VERSION 5.8 ;
BUSBITCHARS "[]" ;
DIVIDERCHAR "/" ;
UNITS
    DATABASE MICRONS 1000 ;
END UNITS

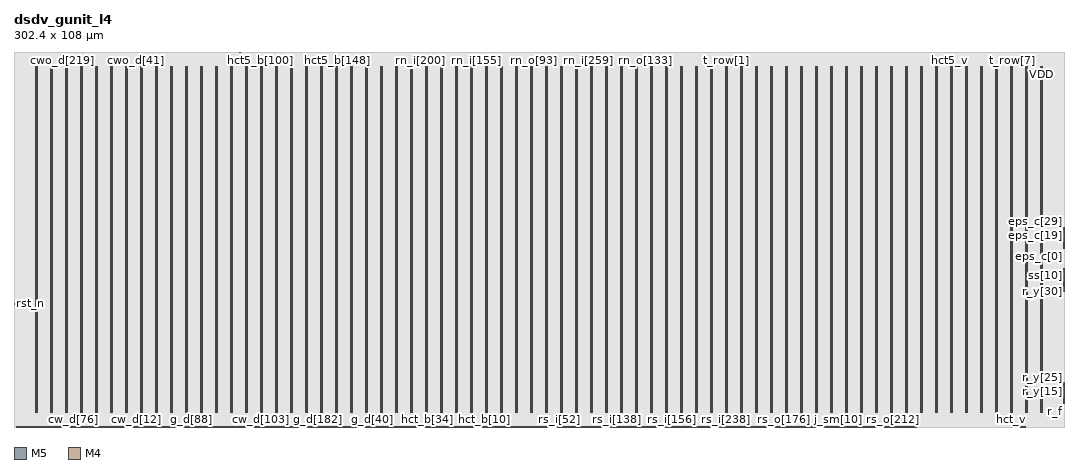
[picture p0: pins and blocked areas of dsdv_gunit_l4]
MACRO dsdv_gunit_l4
  FOREIGN dsdv_gunit_l4 0 0 ;
  CLASS BLOCK ;
  SIZE 302.4 BY 108 ;
  PIN clk
    DIRECTION INPUT ;
    USE SIGNAL ;
    PORT
      LAYER M5 ;
        RECT  155.028 0 155.076 0.48 ;
    END
  END clk
  PIN cw_a[0]
    DIRECTION INPUT ;
    USE SIGNAL ;
    PORT
      LAYER M5 ;
        RECT  31.296 0 31.32 0.084 ;
    END
  END cw_a[0]
  PIN cw_a[1]
    DIRECTION INPUT ;
    USE SIGNAL ;
    PORT
      LAYER M5 ;
        RECT  31.488 0 31.512 0.084 ;
    END
  END cw_a[1]
  PIN cw_a[2]
    DIRECTION INPUT ;
    USE SIGNAL ;
    PORT
      LAYER M5 ;
        RECT  31.68 0 31.704 0.084 ;
    END
  END cw_a[2]
  PIN cw_a[3]
    DIRECTION INPUT ;
    USE SIGNAL ;
    PORT
      LAYER M5 ;
        RECT  31.872 0 31.896 0.084 ;
    END
  END cw_a[3]
  PIN cw_a[4]
    DIRECTION INPUT ;
    USE SIGNAL ;
    PORT
      LAYER M5 ;
        RECT  32.064 0 32.088 0.084 ;
    END
  END cw_a[4]
  PIN cw_a[5]
    DIRECTION INPUT ;
    USE SIGNAL ;
    PORT
      LAYER M5 ;
        RECT  32.256 0 32.28 0.084 ;
    END
  END cw_a[5]
  PIN cw_a[6]
    DIRECTION INPUT ;
    USE SIGNAL ;
    PORT
      LAYER M5 ;
        RECT  32.448 0 32.472 0.084 ;
    END
  END cw_a[6]
  PIN cw_a[7]
    DIRECTION INPUT ;
    USE SIGNAL ;
    PORT
      LAYER M5 ;
        RECT  32.64 0 32.664 0.084 ;
    END
  END cw_a[7]
  PIN cw_d[0]
    DIRECTION INPUT ;
    USE SIGNAL ;
    PORT
      LAYER M5 ;
        RECT  32.832 0 32.856 0.084 ;
    END
  END cw_d[0]
  PIN cw_d[100]
    DIRECTION INPUT ;
    USE SIGNAL ;
    PORT
      LAYER M5 ;
        RECT  70.464 0 70.488 0.084 ;
    END
  END cw_d[100]
  PIN cw_d[101]
    DIRECTION INPUT ;
    USE SIGNAL ;
    PORT
      LAYER M5 ;
        RECT  70.656 0 70.68 0.084 ;
    END
  END cw_d[101]
  PIN cw_d[102]
    DIRECTION INPUT ;
    USE SIGNAL ;
    PORT
      LAYER M5 ;
        RECT  70.848 0 70.872 0.084 ;
    END
  END cw_d[102]
  PIN cw_d[103]
    DIRECTION INPUT ;
    USE SIGNAL ;
    PORT
      LAYER M5 ;
        RECT  71.04 0 71.064 0.084 ;
    END
  END cw_d[103]
  PIN cw_d[104]
    DIRECTION INPUT ;
    USE SIGNAL ;
    PORT
      LAYER M5 ;
        RECT  71.232 0 71.256 0.084 ;
    END
  END cw_d[104]
  PIN cw_d[105]
    DIRECTION INPUT ;
    USE SIGNAL ;
    PORT
      LAYER M5 ;
        RECT  71.424 0 71.448 0.084 ;
    END
  END cw_d[105]
  PIN cw_d[106]
    DIRECTION INPUT ;
    USE SIGNAL ;
    PORT
      LAYER M5 ;
        RECT  71.616 0 71.64 0.084 ;
    END
  END cw_d[106]
  PIN cw_d[107]
    DIRECTION INPUT ;
    USE SIGNAL ;
    PORT
      LAYER M5 ;
        RECT  71.808 0 71.832 0.084 ;
    END
  END cw_d[107]
  PIN cw_d[108]
    DIRECTION INPUT ;
    USE SIGNAL ;
    PORT
      LAYER M5 ;
        RECT  72 0 72.024 0.084 ;
    END
  END cw_d[108]
  PIN cw_d[109]
    DIRECTION INPUT ;
    USE SIGNAL ;
    PORT
      LAYER M5 ;
        RECT  72.192 0 72.216 0.084 ;
    END
  END cw_d[109]
  PIN cw_d[10]
    DIRECTION INPUT ;
    USE SIGNAL ;
    PORT
      LAYER M5 ;
        RECT  34.752 0 34.776 0.084 ;
    END
  END cw_d[10]
  PIN cw_d[110]
    DIRECTION INPUT ;
    USE SIGNAL ;
    PORT
      LAYER M5 ;
        RECT  72.384 0 72.408 0.084 ;
    END
  END cw_d[110]
  PIN cw_d[111]
    DIRECTION INPUT ;
    USE SIGNAL ;
    PORT
      LAYER M5 ;
        RECT  72.576 0 72.6 0.084 ;
    END
  END cw_d[111]
  PIN cw_d[112]
    DIRECTION INPUT ;
    USE SIGNAL ;
    PORT
      LAYER M5 ;
        RECT  72.768 0 72.792 0.084 ;
    END
  END cw_d[112]
  PIN cw_d[113]
    DIRECTION INPUT ;
    USE SIGNAL ;
    PORT
      LAYER M5 ;
        RECT  72.96 0 72.984 0.084 ;
    END
  END cw_d[113]
  PIN cw_d[114]
    DIRECTION INPUT ;
    USE SIGNAL ;
    PORT
      LAYER M5 ;
        RECT  73.152 0 73.176 0.084 ;
    END
  END cw_d[114]
  PIN cw_d[115]
    DIRECTION INPUT ;
    USE SIGNAL ;
    PORT
      LAYER M5 ;
        RECT  73.344 0 73.368 0.084 ;
    END
  END cw_d[115]
  PIN cw_d[116]
    DIRECTION INPUT ;
    USE SIGNAL ;
    PORT
      LAYER M5 ;
        RECT  73.536 0 73.56 0.084 ;
    END
  END cw_d[116]
  PIN cw_d[117]
    DIRECTION INPUT ;
    USE SIGNAL ;
    PORT
      LAYER M5 ;
        RECT  73.728 0 73.752 0.084 ;
    END
  END cw_d[117]
  PIN cw_d[118]
    DIRECTION INPUT ;
    USE SIGNAL ;
    PORT
      LAYER M5 ;
        RECT  6.72 0 6.744 0.084 ;
    END
  END cw_d[118]
  PIN cw_d[119]
    DIRECTION INPUT ;
    USE SIGNAL ;
    PORT
      LAYER M5 ;
        RECT  6.912 0 6.936 0.084 ;
    END
  END cw_d[119]
  PIN cw_d[11]
    DIRECTION INPUT ;
    USE SIGNAL ;
    PORT
      LAYER M5 ;
        RECT  34.944 0 34.968 0.084 ;
    END
  END cw_d[11]
  PIN cw_d[120]
    DIRECTION INPUT ;
    USE SIGNAL ;
    PORT
      LAYER M5 ;
        RECT  7.104 0 7.128 0.084 ;
    END
  END cw_d[120]
  PIN cw_d[121]
    DIRECTION INPUT ;
    USE SIGNAL ;
    PORT
      LAYER M5 ;
        RECT  7.296 0 7.32 0.084 ;
    END
  END cw_d[121]
  PIN cw_d[122]
    DIRECTION INPUT ;
    USE SIGNAL ;
    PORT
      LAYER M5 ;
        RECT  7.488 0 7.512 0.084 ;
    END
  END cw_d[122]
  PIN cw_d[123]
    DIRECTION INPUT ;
    USE SIGNAL ;
    PORT
      LAYER M5 ;
        RECT  7.68 0 7.704 0.084 ;
    END
  END cw_d[123]
  PIN cw_d[124]
    DIRECTION INPUT ;
    USE SIGNAL ;
    PORT
      LAYER M5 ;
        RECT  7.872 0 7.896 0.084 ;
    END
  END cw_d[124]
  PIN cw_d[125]
    DIRECTION INPUT ;
    USE SIGNAL ;
    PORT
      LAYER M5 ;
        RECT  8.064 0 8.088 0.084 ;
    END
  END cw_d[125]
  PIN cw_d[126]
    DIRECTION INPUT ;
    USE SIGNAL ;
    PORT
      LAYER M5 ;
        RECT  8.256 0 8.28 0.084 ;
    END
  END cw_d[126]
  PIN cw_d[127]
    DIRECTION INPUT ;
    USE SIGNAL ;
    PORT
      LAYER M5 ;
        RECT  8.448 0 8.472 0.084 ;
    END
  END cw_d[127]
  PIN cw_d[128]
    DIRECTION INPUT ;
    USE SIGNAL ;
    PORT
      LAYER M5 ;
        RECT  8.64 0 8.664 0.084 ;
    END
  END cw_d[128]
  PIN cw_d[129]
    DIRECTION INPUT ;
    USE SIGNAL ;
    PORT
      LAYER M5 ;
        RECT  8.832 0 8.856 0.084 ;
    END
  END cw_d[129]
  PIN cw_d[12]
    DIRECTION INPUT ;
    USE SIGNAL ;
    PORT
      LAYER M5 ;
        RECT  35.136 0 35.16 0.084 ;
    END
  END cw_d[12]
  PIN cw_d[130]
    DIRECTION INPUT ;
    USE SIGNAL ;
    PORT
      LAYER M5 ;
        RECT  9.024 0 9.048 0.084 ;
    END
  END cw_d[130]
  PIN cw_d[131]
    DIRECTION INPUT ;
    USE SIGNAL ;
    PORT
      LAYER M5 ;
        RECT  9.216 0 9.24 0.084 ;
    END
  END cw_d[131]
  PIN cw_d[132]
    DIRECTION INPUT ;
    USE SIGNAL ;
    PORT
      LAYER M5 ;
        RECT  9.408 0 9.432 0.084 ;
    END
  END cw_d[132]
  PIN cw_d[133]
    DIRECTION INPUT ;
    USE SIGNAL ;
    PORT
      LAYER M5 ;
        RECT  9.6 0 9.624 0.084 ;
    END
  END cw_d[133]
  PIN cw_d[134]
    DIRECTION INPUT ;
    USE SIGNAL ;
    PORT
      LAYER M5 ;
        RECT  9.792 0 9.816 0.084 ;
    END
  END cw_d[134]
  PIN cw_d[135]
    DIRECTION INPUT ;
    USE SIGNAL ;
    PORT
      LAYER M5 ;
        RECT  9.984 0 10.008 0.084 ;
    END
  END cw_d[135]
  PIN cw_d[136]
    DIRECTION INPUT ;
    USE SIGNAL ;
    PORT
      LAYER M5 ;
        RECT  10.176 0 10.2 0.084 ;
    END
  END cw_d[136]
  PIN cw_d[137]
    DIRECTION INPUT ;
    USE SIGNAL ;
    PORT
      LAYER M5 ;
        RECT  10.368 0 10.392 0.084 ;
    END
  END cw_d[137]
  PIN cw_d[138]
    DIRECTION INPUT ;
    USE SIGNAL ;
    PORT
      LAYER M5 ;
        RECT  10.56 0 10.584 0.084 ;
    END
  END cw_d[138]
  PIN cw_d[139]
    DIRECTION INPUT ;
    USE SIGNAL ;
    PORT
      LAYER M5 ;
        RECT  10.752 0 10.776 0.084 ;
    END
  END cw_d[139]
  PIN cw_d[13]
    DIRECTION INPUT ;
    USE SIGNAL ;
    PORT
      LAYER M5 ;
        RECT  35.328 0 35.352 0.084 ;
    END
  END cw_d[13]
  PIN cw_d[140]
    DIRECTION INPUT ;
    USE SIGNAL ;
    PORT
      LAYER M5 ;
        RECT  10.944 0 10.968 0.084 ;
    END
  END cw_d[140]
  PIN cw_d[141]
    DIRECTION INPUT ;
    USE SIGNAL ;
    PORT
      LAYER M5 ;
        RECT  11.136 0 11.16 0.084 ;
    END
  END cw_d[141]
  PIN cw_d[142]
    DIRECTION INPUT ;
    USE SIGNAL ;
    PORT
      LAYER M5 ;
        RECT  11.328 0 11.352 0.084 ;
    END
  END cw_d[142]
  PIN cw_d[143]
    DIRECTION INPUT ;
    USE SIGNAL ;
    PORT
      LAYER M5 ;
        RECT  11.52 0 11.544 0.084 ;
    END
  END cw_d[143]
  PIN cw_d[144]
    DIRECTION INPUT ;
    USE SIGNAL ;
    PORT
      LAYER M5 ;
        RECT  11.712 0 11.736 0.084 ;
    END
  END cw_d[144]
  PIN cw_d[145]
    DIRECTION INPUT ;
    USE SIGNAL ;
    PORT
      LAYER M5 ;
        RECT  11.904 0 11.928 0.084 ;
    END
  END cw_d[145]
  PIN cw_d[146]
    DIRECTION INPUT ;
    USE SIGNAL ;
    PORT
      LAYER M5 ;
        RECT  12.096 0 12.12 0.084 ;
    END
  END cw_d[146]
  PIN cw_d[147]
    DIRECTION INPUT ;
    USE SIGNAL ;
    PORT
      LAYER M5 ;
        RECT  12.288 0 12.312 0.084 ;
    END
  END cw_d[147]
  PIN cw_d[148]
    DIRECTION INPUT ;
    USE SIGNAL ;
    PORT
      LAYER M5 ;
        RECT  12.48 0 12.504 0.084 ;
    END
  END cw_d[148]
  PIN cw_d[149]
    DIRECTION INPUT ;
    USE SIGNAL ;
    PORT
      LAYER M5 ;
        RECT  12.672 0 12.696 0.084 ;
    END
  END cw_d[149]
  PIN cw_d[14]
    DIRECTION INPUT ;
    USE SIGNAL ;
    PORT
      LAYER M5 ;
        RECT  35.52 0 35.544 0.084 ;
    END
  END cw_d[14]
  PIN cw_d[150]
    DIRECTION INPUT ;
    USE SIGNAL ;
    PORT
      LAYER M5 ;
        RECT  0.576 0 0.6 0.084 ;
    END
  END cw_d[150]
  PIN cw_d[151]
    DIRECTION INPUT ;
    USE SIGNAL ;
    PORT
      LAYER M5 ;
        RECT  0.768 0 0.792 0.084 ;
    END
  END cw_d[151]
  PIN cw_d[152]
    DIRECTION INPUT ;
    USE SIGNAL ;
    PORT
      LAYER M5 ;
        RECT  0.96 0 0.984 0.084 ;
    END
  END cw_d[152]
  PIN cw_d[153]
    DIRECTION INPUT ;
    USE SIGNAL ;
    PORT
      LAYER M5 ;
        RECT  1.152 0 1.176 0.084 ;
    END
  END cw_d[153]
  PIN cw_d[154]
    DIRECTION INPUT ;
    USE SIGNAL ;
    PORT
      LAYER M5 ;
        RECT  1.344 0 1.368 0.084 ;
    END
  END cw_d[154]
  PIN cw_d[155]
    DIRECTION INPUT ;
    USE SIGNAL ;
    PORT
      LAYER M5 ;
        RECT  1.536 0 1.56 0.084 ;
    END
  END cw_d[155]
  PIN cw_d[156]
    DIRECTION INPUT ;
    USE SIGNAL ;
    PORT
      LAYER M5 ;
        RECT  1.728 0 1.752 0.084 ;
    END
  END cw_d[156]
  PIN cw_d[157]
    DIRECTION INPUT ;
    USE SIGNAL ;
    PORT
      LAYER M5 ;
        RECT  1.92 0 1.944 0.084 ;
    END
  END cw_d[157]
  PIN cw_d[158]
    DIRECTION INPUT ;
    USE SIGNAL ;
    PORT
      LAYER M5 ;
        RECT  2.112 0 2.136 0.084 ;
    END
  END cw_d[158]
  PIN cw_d[159]
    DIRECTION INPUT ;
    USE SIGNAL ;
    PORT
      LAYER M5 ;
        RECT  2.304 0 2.328 0.084 ;
    END
  END cw_d[159]
  PIN cw_d[15]
    DIRECTION INPUT ;
    USE SIGNAL ;
    PORT
      LAYER M5 ;
        RECT  35.712 0 35.736 0.084 ;
    END
  END cw_d[15]
  PIN cw_d[160]
    DIRECTION INPUT ;
    USE SIGNAL ;
    PORT
      LAYER M5 ;
        RECT  2.496 0 2.52 0.084 ;
    END
  END cw_d[160]
  PIN cw_d[161]
    DIRECTION INPUT ;
    USE SIGNAL ;
    PORT
      LAYER M5 ;
        RECT  2.688 0 2.712 0.084 ;
    END
  END cw_d[161]
  PIN cw_d[162]
    DIRECTION INPUT ;
    USE SIGNAL ;
    PORT
      LAYER M5 ;
        RECT  2.88 0 2.904 0.084 ;
    END
  END cw_d[162]
  PIN cw_d[163]
    DIRECTION INPUT ;
    USE SIGNAL ;
    PORT
      LAYER M5 ;
        RECT  3.072 0 3.096 0.084 ;
    END
  END cw_d[163]
  PIN cw_d[164]
    DIRECTION INPUT ;
    USE SIGNAL ;
    PORT
      LAYER M5 ;
        RECT  3.264 0 3.288 0.084 ;
    END
  END cw_d[164]
  PIN cw_d[165]
    DIRECTION INPUT ;
    USE SIGNAL ;
    PORT
      LAYER M5 ;
        RECT  3.456 0 3.48 0.084 ;
    END
  END cw_d[165]
  PIN cw_d[166]
    DIRECTION INPUT ;
    USE SIGNAL ;
    PORT
      LAYER M5 ;
        RECT  3.648 0 3.672 0.084 ;
    END
  END cw_d[166]
  PIN cw_d[167]
    DIRECTION INPUT ;
    USE SIGNAL ;
    PORT
      LAYER M5 ;
        RECT  3.84 0 3.864 0.084 ;
    END
  END cw_d[167]
  PIN cw_d[168]
    DIRECTION INPUT ;
    USE SIGNAL ;
    PORT
      LAYER M5 ;
        RECT  4.032 0 4.056 0.084 ;
    END
  END cw_d[168]
  PIN cw_d[169]
    DIRECTION INPUT ;
    USE SIGNAL ;
    PORT
      LAYER M5 ;
        RECT  4.224 0 4.248 0.084 ;
    END
  END cw_d[169]
  PIN cw_d[16]
    DIRECTION INPUT ;
    USE SIGNAL ;
    PORT
      LAYER M5 ;
        RECT  35.904 0 35.928 0.084 ;
    END
  END cw_d[16]
  PIN cw_d[170]
    DIRECTION INPUT ;
    USE SIGNAL ;
    PORT
      LAYER M5 ;
        RECT  4.416 0 4.44 0.084 ;
    END
  END cw_d[170]
  PIN cw_d[171]
    DIRECTION INPUT ;
    USE SIGNAL ;
    PORT
      LAYER M5 ;
        RECT  4.608 0 4.632 0.084 ;
    END
  END cw_d[171]
  PIN cw_d[172]
    DIRECTION INPUT ;
    USE SIGNAL ;
    PORT
      LAYER M5 ;
        RECT  4.8 0 4.824 0.084 ;
    END
  END cw_d[172]
  PIN cw_d[173]
    DIRECTION INPUT ;
    USE SIGNAL ;
    PORT
      LAYER M5 ;
        RECT  4.992 0 5.016 0.084 ;
    END
  END cw_d[173]
  PIN cw_d[174]
    DIRECTION INPUT ;
    USE SIGNAL ;
    PORT
      LAYER M5 ;
        RECT  5.184 0 5.208 0.084 ;
    END
  END cw_d[174]
  PIN cw_d[175]
    DIRECTION INPUT ;
    USE SIGNAL ;
    PORT
      LAYER M5 ;
        RECT  5.376 0 5.4 0.084 ;
    END
  END cw_d[175]
  PIN cw_d[176]
    DIRECTION INPUT ;
    USE SIGNAL ;
    PORT
      LAYER M5 ;
        RECT  5.568 0 5.592 0.084 ;
    END
  END cw_d[176]
  PIN cw_d[177]
    DIRECTION INPUT ;
    USE SIGNAL ;
    PORT
      LAYER M5 ;
        RECT  5.76 0 5.784 0.084 ;
    END
  END cw_d[177]
  PIN cw_d[178]
    DIRECTION INPUT ;
    USE SIGNAL ;
    PORT
      LAYER M5 ;
        RECT  5.952 0 5.976 0.084 ;
    END
  END cw_d[178]
  PIN cw_d[179]
    DIRECTION INPUT ;
    USE SIGNAL ;
    PORT
      LAYER M5 ;
        RECT  6.144 0 6.168 0.084 ;
    END
  END cw_d[179]
  PIN cw_d[17]
    DIRECTION INPUT ;
    USE SIGNAL ;
    PORT
      LAYER M5 ;
        RECT  36.096 0 36.12 0.084 ;
    END
  END cw_d[17]
  PIN cw_d[180]
    DIRECTION INPUT ;
    USE SIGNAL ;
    PORT
      LAYER M5 ;
        RECT  6.336 0 6.36 0.084 ;
    END
  END cw_d[180]
  PIN cw_d[181]
    DIRECTION INPUT ;
    USE SIGNAL ;
    PORT
      LAYER M5 ;
        RECT  6.528 0 6.552 0.084 ;
    END
  END cw_d[181]
  PIN cw_d[182]
    DIRECTION INPUT ;
    USE SIGNAL ;
    PORT
      LAYER M5 ;
        RECT  25.152 0 25.176 0.084 ;
    END
  END cw_d[182]
  PIN cw_d[183]
    DIRECTION INPUT ;
    USE SIGNAL ;
    PORT
      LAYER M5 ;
        RECT  25.344 0 25.368 0.084 ;
    END
  END cw_d[183]
  PIN cw_d[184]
    DIRECTION INPUT ;
    USE SIGNAL ;
    PORT
      LAYER M5 ;
        RECT  25.536 0 25.56 0.084 ;
    END
  END cw_d[184]
  PIN cw_d[185]
    DIRECTION INPUT ;
    USE SIGNAL ;
    PORT
      LAYER M5 ;
        RECT  25.728 0 25.752 0.084 ;
    END
  END cw_d[185]
  PIN cw_d[186]
    DIRECTION INPUT ;
    USE SIGNAL ;
    PORT
      LAYER M5 ;
        RECT  25.92 0 25.944 0.084 ;
    END
  END cw_d[186]
  PIN cw_d[187]
    DIRECTION INPUT ;
    USE SIGNAL ;
    PORT
      LAYER M5 ;
        RECT  26.112 0 26.136 0.084 ;
    END
  END cw_d[187]
  PIN cw_d[188]
    DIRECTION INPUT ;
    USE SIGNAL ;
    PORT
      LAYER M5 ;
        RECT  26.304 0 26.328 0.084 ;
    END
  END cw_d[188]
  PIN cw_d[189]
    DIRECTION INPUT ;
    USE SIGNAL ;
    PORT
      LAYER M5 ;
        RECT  26.496 0 26.52 0.084 ;
    END
  END cw_d[189]
  PIN cw_d[18]
    DIRECTION INPUT ;
    USE SIGNAL ;
    PORT
      LAYER M5 ;
        RECT  36.288 0 36.312 0.084 ;
    END
  END cw_d[18]
  PIN cw_d[190]
    DIRECTION INPUT ;
    USE SIGNAL ;
    PORT
      LAYER M5 ;
        RECT  26.688 0 26.712 0.084 ;
    END
  END cw_d[190]
  PIN cw_d[191]
    DIRECTION INPUT ;
    USE SIGNAL ;
    PORT
      LAYER M5 ;
        RECT  26.88 0 26.904 0.084 ;
    END
  END cw_d[191]
  PIN cw_d[192]
    DIRECTION INPUT ;
    USE SIGNAL ;
    PORT
      LAYER M5 ;
        RECT  27.072 0 27.096 0.084 ;
    END
  END cw_d[192]
  PIN cw_d[193]
    DIRECTION INPUT ;
    USE SIGNAL ;
    PORT
      LAYER M5 ;
        RECT  27.264 0 27.288 0.084 ;
    END
  END cw_d[193]
  PIN cw_d[194]
    DIRECTION INPUT ;
    USE SIGNAL ;
    PORT
      LAYER M5 ;
        RECT  27.456 0 27.48 0.084 ;
    END
  END cw_d[194]
  PIN cw_d[195]
    DIRECTION INPUT ;
    USE SIGNAL ;
    PORT
      LAYER M5 ;
        RECT  27.648 0 27.672 0.084 ;
    END
  END cw_d[195]
  PIN cw_d[196]
    DIRECTION INPUT ;
    USE SIGNAL ;
    PORT
      LAYER M5 ;
        RECT  27.84 0 27.864 0.084 ;
    END
  END cw_d[196]
  PIN cw_d[197]
    DIRECTION INPUT ;
    USE SIGNAL ;
    PORT
      LAYER M5 ;
        RECT  28.032 0 28.056 0.084 ;
    END
  END cw_d[197]
  PIN cw_d[198]
    DIRECTION INPUT ;
    USE SIGNAL ;
    PORT
      LAYER M5 ;
        RECT  28.224 0 28.248 0.084 ;
    END
  END cw_d[198]
  PIN cw_d[199]
    DIRECTION INPUT ;
    USE SIGNAL ;
    PORT
      LAYER M5 ;
        RECT  28.416 0 28.44 0.084 ;
    END
  END cw_d[199]
  PIN cw_d[19]
    DIRECTION INPUT ;
    USE SIGNAL ;
    PORT
      LAYER M5 ;
        RECT  36.48 0 36.504 0.084 ;
    END
  END cw_d[19]
  PIN cw_d[1]
    DIRECTION INPUT ;
    USE SIGNAL ;
    PORT
      LAYER M5 ;
        RECT  33.024 0 33.048 0.084 ;
    END
  END cw_d[1]
  PIN cw_d[200]
    DIRECTION INPUT ;
    USE SIGNAL ;
    PORT
      LAYER M5 ;
        RECT  28.608 0 28.632 0.084 ;
    END
  END cw_d[200]
  PIN cw_d[201]
    DIRECTION INPUT ;
    USE SIGNAL ;
    PORT
      LAYER M5 ;
        RECT  28.8 0 28.824 0.084 ;
    END
  END cw_d[201]
  PIN cw_d[202]
    DIRECTION INPUT ;
    USE SIGNAL ;
    PORT
      LAYER M5 ;
        RECT  28.992 0 29.016 0.084 ;
    END
  END cw_d[202]
  PIN cw_d[203]
    DIRECTION INPUT ;
    USE SIGNAL ;
    PORT
      LAYER M5 ;
        RECT  29.184 0 29.208 0.084 ;
    END
  END cw_d[203]
  PIN cw_d[204]
    DIRECTION INPUT ;
    USE SIGNAL ;
    PORT
      LAYER M5 ;
        RECT  29.376 0 29.4 0.084 ;
    END
  END cw_d[204]
  PIN cw_d[205]
    DIRECTION INPUT ;
    USE SIGNAL ;
    PORT
      LAYER M5 ;
        RECT  29.568 0 29.592 0.084 ;
    END
  END cw_d[205]
  PIN cw_d[206]
    DIRECTION INPUT ;
    USE SIGNAL ;
    PORT
      LAYER M5 ;
        RECT  29.76 0 29.784 0.084 ;
    END
  END cw_d[206]
  PIN cw_d[207]
    DIRECTION INPUT ;
    USE SIGNAL ;
    PORT
      LAYER M5 ;
        RECT  29.952 0 29.976 0.084 ;
    END
  END cw_d[207]
  PIN cw_d[208]
    DIRECTION INPUT ;
    USE SIGNAL ;
    PORT
      LAYER M5 ;
        RECT  30.144 0 30.168 0.084 ;
    END
  END cw_d[208]
  PIN cw_d[209]
    DIRECTION INPUT ;
    USE SIGNAL ;
    PORT
      LAYER M5 ;
        RECT  30.336 0 30.36 0.084 ;
    END
  END cw_d[209]
  PIN cw_d[20]
    DIRECTION INPUT ;
    USE SIGNAL ;
    PORT
      LAYER M5 ;
        RECT  36.672 0 36.696 0.084 ;
    END
  END cw_d[20]
  PIN cw_d[210]
    DIRECTION INPUT ;
    USE SIGNAL ;
    PORT
      LAYER M5 ;
        RECT  30.528 0 30.552 0.084 ;
    END
  END cw_d[210]
  PIN cw_d[211]
    DIRECTION INPUT ;
    USE SIGNAL ;
    PORT
      LAYER M5 ;
        RECT  30.72 0 30.744 0.084 ;
    END
  END cw_d[211]
  PIN cw_d[212]
    DIRECTION INPUT ;
    USE SIGNAL ;
    PORT
      LAYER M5 ;
        RECT  30.912 0 30.936 0.084 ;
    END
  END cw_d[212]
  PIN cw_d[213]
    DIRECTION INPUT ;
    USE SIGNAL ;
    PORT
      LAYER M5 ;
        RECT  31.104 0 31.128 0.084 ;
    END
  END cw_d[213]
  PIN cw_d[214]
    DIRECTION INPUT ;
    USE SIGNAL ;
    PORT
      LAYER M5 ;
        RECT  43.2 0 43.224 0.084 ;
    END
  END cw_d[214]
  PIN cw_d[215]
    DIRECTION INPUT ;
    USE SIGNAL ;
    PORT
      LAYER M5 ;
        RECT  43.392 0 43.416 0.084 ;
    END
  END cw_d[215]
  PIN cw_d[216]
    DIRECTION INPUT ;
    USE SIGNAL ;
    PORT
      LAYER M5 ;
        RECT  43.584 0 43.608 0.084 ;
    END
  END cw_d[216]
  PIN cw_d[217]
    DIRECTION INPUT ;
    USE SIGNAL ;
    PORT
      LAYER M5 ;
        RECT  43.776 0 43.8 0.084 ;
    END
  END cw_d[217]
  PIN cw_d[218]
    DIRECTION INPUT ;
    USE SIGNAL ;
    PORT
      LAYER M5 ;
        RECT  43.968 0 43.992 0.084 ;
    END
  END cw_d[218]
  PIN cw_d[219]
    DIRECTION INPUT ;
    USE SIGNAL ;
    PORT
      LAYER M5 ;
        RECT  44.16 0 44.184 0.084 ;
    END
  END cw_d[219]
  PIN cw_d[21]
    DIRECTION INPUT ;
    USE SIGNAL ;
    PORT
      LAYER M5 ;
        RECT  36.864 0 36.888 0.084 ;
    END
  END cw_d[21]
  PIN cw_d[220]
    DIRECTION INPUT ;
    USE SIGNAL ;
    PORT
      LAYER M5 ;
        RECT  44.352 0 44.376 0.084 ;
    END
  END cw_d[220]
  PIN cw_d[221]
    DIRECTION INPUT ;
    USE SIGNAL ;
    PORT
      LAYER M5 ;
        RECT  44.544 0 44.568 0.084 ;
    END
  END cw_d[221]
  PIN cw_d[222]
    DIRECTION INPUT ;
    USE SIGNAL ;
    PORT
      LAYER M5 ;
        RECT  44.736 0 44.76 0.084 ;
    END
  END cw_d[222]
  PIN cw_d[223]
    DIRECTION INPUT ;
    USE SIGNAL ;
    PORT
      LAYER M5 ;
        RECT  44.928 0 44.952 0.084 ;
    END
  END cw_d[223]
  PIN cw_d[224]
    DIRECTION INPUT ;
    USE SIGNAL ;
    PORT
      LAYER M5 ;
        RECT  45.12 0 45.144 0.084 ;
    END
  END cw_d[224]
  PIN cw_d[225]
    DIRECTION INPUT ;
    USE SIGNAL ;
    PORT
      LAYER M5 ;
        RECT  45.312 0 45.336 0.084 ;
    END
  END cw_d[225]
  PIN cw_d[226]
    DIRECTION INPUT ;
    USE SIGNAL ;
    PORT
      LAYER M5 ;
        RECT  45.504 0 45.528 0.084 ;
    END
  END cw_d[226]
  PIN cw_d[227]
    DIRECTION INPUT ;
    USE SIGNAL ;
    PORT
      LAYER M5 ;
        RECT  45.696 0 45.72 0.084 ;
    END
  END cw_d[227]
  PIN cw_d[228]
    DIRECTION INPUT ;
    USE SIGNAL ;
    PORT
      LAYER M5 ;
        RECT  45.888 0 45.912 0.084 ;
    END
  END cw_d[228]
  PIN cw_d[229]
    DIRECTION INPUT ;
    USE SIGNAL ;
    PORT
      LAYER M5 ;
        RECT  46.08 0 46.104 0.084 ;
    END
  END cw_d[229]
  PIN cw_d[22]
    DIRECTION INPUT ;
    USE SIGNAL ;
    PORT
      LAYER M5 ;
        RECT  19.008 0 19.032 0.084 ;
    END
  END cw_d[22]
  PIN cw_d[230]
    DIRECTION INPUT ;
    USE SIGNAL ;
    PORT
      LAYER M5 ;
        RECT  46.272 0 46.296 0.084 ;
    END
  END cw_d[230]
  PIN cw_d[231]
    DIRECTION INPUT ;
    USE SIGNAL ;
    PORT
      LAYER M5 ;
        RECT  46.464 0 46.488 0.084 ;
    END
  END cw_d[231]
  PIN cw_d[232]
    DIRECTION INPUT ;
    USE SIGNAL ;
    PORT
      LAYER M5 ;
        RECT  46.656 0 46.68 0.084 ;
    END
  END cw_d[232]
  PIN cw_d[233]
    DIRECTION INPUT ;
    USE SIGNAL ;
    PORT
      LAYER M5 ;
        RECT  46.848 0 46.872 0.084 ;
    END
  END cw_d[233]
  PIN cw_d[234]
    DIRECTION INPUT ;
    USE SIGNAL ;
    PORT
      LAYER M5 ;
        RECT  47.04 0 47.064 0.084 ;
    END
  END cw_d[234]
  PIN cw_d[235]
    DIRECTION INPUT ;
    USE SIGNAL ;
    PORT
      LAYER M5 ;
        RECT  47.232 0 47.256 0.084 ;
    END
  END cw_d[235]
  PIN cw_d[236]
    DIRECTION INPUT ;
    USE SIGNAL ;
    PORT
      LAYER M5 ;
        RECT  47.424 0 47.448 0.084 ;
    END
  END cw_d[236]
  PIN cw_d[237]
    DIRECTION INPUT ;
    USE SIGNAL ;
    PORT
      LAYER M5 ;
        RECT  47.616 0 47.64 0.084 ;
    END
  END cw_d[237]
  PIN cw_d[238]
    DIRECTION INPUT ;
    USE SIGNAL ;
    PORT
      LAYER M5 ;
        RECT  47.808 0 47.832 0.084 ;
    END
  END cw_d[238]
  PIN cw_d[239]
    DIRECTION INPUT ;
    USE SIGNAL ;
    PORT
      LAYER M5 ;
        RECT  48 0 48.024 0.084 ;
    END
  END cw_d[239]
  PIN cw_d[23]
    DIRECTION INPUT ;
    USE SIGNAL ;
    PORT
      LAYER M5 ;
        RECT  19.2 0 19.224 0.084 ;
    END
  END cw_d[23]
  PIN cw_d[240]
    DIRECTION INPUT ;
    USE SIGNAL ;
    PORT
      LAYER M5 ;
        RECT  48.192 0 48.216 0.084 ;
    END
  END cw_d[240]
  PIN cw_d[241]
    DIRECTION INPUT ;
    USE SIGNAL ;
    PORT
      LAYER M5 ;
        RECT  48.384 0 48.408 0.084 ;
    END
  END cw_d[241]
  PIN cw_d[242]
    DIRECTION INPUT ;
    USE SIGNAL ;
    PORT
      LAYER M5 ;
        RECT  48.576 0 48.6 0.084 ;
    END
  END cw_d[242]
  PIN cw_d[243]
    DIRECTION INPUT ;
    USE SIGNAL ;
    PORT
      LAYER M5 ;
        RECT  48.768 0 48.792 0.084 ;
    END
  END cw_d[243]
  PIN cw_d[244]
    DIRECTION INPUT ;
    USE SIGNAL ;
    PORT
      LAYER M5 ;
        RECT  48.96 0 48.984 0.084 ;
    END
  END cw_d[244]
  PIN cw_d[245]
    DIRECTION INPUT ;
    USE SIGNAL ;
    PORT
      LAYER M5 ;
        RECT  49.152 0 49.176 0.084 ;
    END
  END cw_d[245]
  PIN cw_d[246]
    DIRECTION INPUT ;
    USE SIGNAL ;
    PORT
      LAYER M5 ;
        RECT  104.64 0 104.664 0.084 ;
    END
  END cw_d[246]
  PIN cw_d[247]
    DIRECTION INPUT ;
    USE SIGNAL ;
    PORT
      LAYER M5 ;
        RECT  104.832 0 104.856 0.084 ;
    END
  END cw_d[247]
  PIN cw_d[248]
    DIRECTION INPUT ;
    USE SIGNAL ;
    PORT
      LAYER M5 ;
        RECT  105.024 0 105.048 0.084 ;
    END
  END cw_d[248]
  PIN cw_d[249]
    DIRECTION INPUT ;
    USE SIGNAL ;
    PORT
      LAYER M5 ;
        RECT  105.216 0 105.24 0.084 ;
    END
  END cw_d[249]
  PIN cw_d[24]
    DIRECTION INPUT ;
    USE SIGNAL ;
    PORT
      LAYER M5 ;
        RECT  19.392 0 19.416 0.084 ;
    END
  END cw_d[24]
  PIN cw_d[250]
    DIRECTION INPUT ;
    USE SIGNAL ;
    PORT
      LAYER M5 ;
        RECT  105.408 0 105.432 0.084 ;
    END
  END cw_d[250]
  PIN cw_d[251]
    DIRECTION INPUT ;
    USE SIGNAL ;
    PORT
      LAYER M5 ;
        RECT  105.6 0 105.624 0.084 ;
    END
  END cw_d[251]
  PIN cw_d[252]
    DIRECTION INPUT ;
    USE SIGNAL ;
    PORT
      LAYER M5 ;
        RECT  105.792 0 105.816 0.084 ;
    END
  END cw_d[252]
  PIN cw_d[253]
    DIRECTION INPUT ;
    USE SIGNAL ;
    PORT
      LAYER M5 ;
        RECT  105.984 0 106.008 0.084 ;
    END
  END cw_d[253]
  PIN cw_d[254]
    DIRECTION INPUT ;
    USE SIGNAL ;
    PORT
      LAYER M5 ;
        RECT  106.176 0 106.2 0.084 ;
    END
  END cw_d[254]
  PIN cw_d[255]
    DIRECTION INPUT ;
    USE SIGNAL ;
    PORT
      LAYER M5 ;
        RECT  106.368 0 106.392 0.084 ;
    END
  END cw_d[255]
  PIN cw_d[25]
    DIRECTION INPUT ;
    USE SIGNAL ;
    PORT
      LAYER M5 ;
        RECT  19.584 0 19.608 0.084 ;
    END
  END cw_d[25]
  PIN cw_d[26]
    DIRECTION INPUT ;
    USE SIGNAL ;
    PORT
      LAYER M5 ;
        RECT  19.776 0 19.8 0.084 ;
    END
  END cw_d[26]
  PIN cw_d[27]
    DIRECTION INPUT ;
    USE SIGNAL ;
    PORT
      LAYER M5 ;
        RECT  19.968 0 19.992 0.084 ;
    END
  END cw_d[27]
  PIN cw_d[28]
    DIRECTION INPUT ;
    USE SIGNAL ;
    PORT
      LAYER M5 ;
        RECT  20.16 0 20.184 0.084 ;
    END
  END cw_d[28]
  PIN cw_d[29]
    DIRECTION INPUT ;
    USE SIGNAL ;
    PORT
      LAYER M5 ;
        RECT  20.352 0 20.376 0.084 ;
    END
  END cw_d[29]
  PIN cw_d[2]
    DIRECTION INPUT ;
    USE SIGNAL ;
    PORT
      LAYER M5 ;
        RECT  33.216 0 33.24 0.084 ;
    END
  END cw_d[2]
  PIN cw_d[30]
    DIRECTION INPUT ;
    USE SIGNAL ;
    PORT
      LAYER M5 ;
        RECT  20.544 0 20.568 0.084 ;
    END
  END cw_d[30]
  PIN cw_d[31]
    DIRECTION INPUT ;
    USE SIGNAL ;
    PORT
      LAYER M5 ;
        RECT  20.736 0 20.76 0.084 ;
    END
  END cw_d[31]
  PIN cw_d[32]
    DIRECTION INPUT ;
    USE SIGNAL ;
    PORT
      LAYER M5 ;
        RECT  20.928 0 20.952 0.084 ;
    END
  END cw_d[32]
  PIN cw_d[33]
    DIRECTION INPUT ;
    USE SIGNAL ;
    PORT
      LAYER M5 ;
        RECT  21.12 0 21.144 0.084 ;
    END
  END cw_d[33]
  PIN cw_d[34]
    DIRECTION INPUT ;
    USE SIGNAL ;
    PORT
      LAYER M5 ;
        RECT  21.312 0 21.336 0.084 ;
    END
  END cw_d[34]
  PIN cw_d[35]
    DIRECTION INPUT ;
    USE SIGNAL ;
    PORT
      LAYER M5 ;
        RECT  21.504 0 21.528 0.084 ;
    END
  END cw_d[35]
  PIN cw_d[36]
    DIRECTION INPUT ;
    USE SIGNAL ;
    PORT
      LAYER M5 ;
        RECT  21.696 0 21.72 0.084 ;
    END
  END cw_d[36]
  PIN cw_d[37]
    DIRECTION INPUT ;
    USE SIGNAL ;
    PORT
      LAYER M5 ;
        RECT  21.888 0 21.912 0.084 ;
    END
  END cw_d[37]
  PIN cw_d[38]
    DIRECTION INPUT ;
    USE SIGNAL ;
    PORT
      LAYER M5 ;
        RECT  22.08 0 22.104 0.084 ;
    END
  END cw_d[38]
  PIN cw_d[39]
    DIRECTION INPUT ;
    USE SIGNAL ;
    PORT
      LAYER M5 ;
        RECT  22.272 0 22.296 0.084 ;
    END
  END cw_d[39]
  PIN cw_d[3]
    DIRECTION INPUT ;
    USE SIGNAL ;
    PORT
      LAYER M5 ;
        RECT  33.408 0 33.432 0.084 ;
    END
  END cw_d[3]
  PIN cw_d[40]
    DIRECTION INPUT ;
    USE SIGNAL ;
    PORT
      LAYER M5 ;
        RECT  22.464 0 22.488 0.084 ;
    END
  END cw_d[40]
  PIN cw_d[41]
    DIRECTION INPUT ;
    USE SIGNAL ;
    PORT
      LAYER M5 ;
        RECT  22.656 0 22.68 0.084 ;
    END
  END cw_d[41]
  PIN cw_d[42]
    DIRECTION INPUT ;
    USE SIGNAL ;
    PORT
      LAYER M5 ;
        RECT  22.848 0 22.872 0.084 ;
    END
  END cw_d[42]
  PIN cw_d[43]
    DIRECTION INPUT ;
    USE SIGNAL ;
    PORT
      LAYER M5 ;
        RECT  23.04 0 23.064 0.084 ;
    END
  END cw_d[43]
  PIN cw_d[44]
    DIRECTION INPUT ;
    USE SIGNAL ;
    PORT
      LAYER M5 ;
        RECT  23.232 0 23.256 0.084 ;
    END
  END cw_d[44]
  PIN cw_d[45]
    DIRECTION INPUT ;
    USE SIGNAL ;
    PORT
      LAYER M5 ;
        RECT  23.424 0 23.448 0.084 ;
    END
  END cw_d[45]
  PIN cw_d[46]
    DIRECTION INPUT ;
    USE SIGNAL ;
    PORT
      LAYER M5 ;
        RECT  23.616 0 23.64 0.084 ;
    END
  END cw_d[46]
  PIN cw_d[47]
    DIRECTION INPUT ;
    USE SIGNAL ;
    PORT
      LAYER M5 ;
        RECT  23.808 0 23.832 0.084 ;
    END
  END cw_d[47]
  PIN cw_d[48]
    DIRECTION INPUT ;
    USE SIGNAL ;
    PORT
      LAYER M5 ;
        RECT  24 0 24.024 0.084 ;
    END
  END cw_d[48]
  PIN cw_d[49]
    DIRECTION INPUT ;
    USE SIGNAL ;
    PORT
      LAYER M5 ;
        RECT  24.192 0 24.216 0.084 ;
    END
  END cw_d[49]
  PIN cw_d[4]
    DIRECTION INPUT ;
    USE SIGNAL ;
    PORT
      LAYER M5 ;
        RECT  33.6 0 33.624 0.084 ;
    END
  END cw_d[4]
  PIN cw_d[50]
    DIRECTION INPUT ;
    USE SIGNAL ;
    PORT
      LAYER M5 ;
        RECT  24.384 0 24.408 0.084 ;
    END
  END cw_d[50]
  PIN cw_d[51]
    DIRECTION INPUT ;
    USE SIGNAL ;
    PORT
      LAYER M5 ;
        RECT  24.576 0 24.6 0.084 ;
    END
  END cw_d[51]
  PIN cw_d[52]
    DIRECTION INPUT ;
    USE SIGNAL ;
    PORT
      LAYER M5 ;
        RECT  24.768 0 24.792 0.084 ;
    END
  END cw_d[52]
  PIN cw_d[53]
    DIRECTION INPUT ;
    USE SIGNAL ;
    PORT
      LAYER M5 ;
        RECT  24.96 0 24.984 0.084 ;
    END
  END cw_d[53]
  PIN cw_d[54]
    DIRECTION INPUT ;
    USE SIGNAL ;
    PORT
      LAYER M5 ;
        RECT  12.864 0 12.888 0.084 ;
    END
  END cw_d[54]
  PIN cw_d[55]
    DIRECTION INPUT ;
    USE SIGNAL ;
    PORT
      LAYER M5 ;
        RECT  13.056 0 13.08 0.084 ;
    END
  END cw_d[55]
  PIN cw_d[56]
    DIRECTION INPUT ;
    USE SIGNAL ;
    PORT
      LAYER M5 ;
        RECT  13.248 0 13.272 0.084 ;
    END
  END cw_d[56]
  PIN cw_d[57]
    DIRECTION INPUT ;
    USE SIGNAL ;
    PORT
      LAYER M5 ;
        RECT  13.44 0 13.464 0.084 ;
    END
  END cw_d[57]
  PIN cw_d[58]
    DIRECTION INPUT ;
    USE SIGNAL ;
    PORT
      LAYER M5 ;
        RECT  13.632 0 13.656 0.084 ;
    END
  END cw_d[58]
  PIN cw_d[59]
    DIRECTION INPUT ;
    USE SIGNAL ;
    PORT
      LAYER M5 ;
        RECT  13.824 0 13.848 0.084 ;
    END
  END cw_d[59]
  PIN cw_d[5]
    DIRECTION INPUT ;
    USE SIGNAL ;
    PORT
      LAYER M5 ;
        RECT  33.792 0 33.816 0.084 ;
    END
  END cw_d[5]
  PIN cw_d[60]
    DIRECTION INPUT ;
    USE SIGNAL ;
    PORT
      LAYER M5 ;
        RECT  14.016 0 14.04 0.084 ;
    END
  END cw_d[60]
  PIN cw_d[61]
    DIRECTION INPUT ;
    USE SIGNAL ;
    PORT
      LAYER M5 ;
        RECT  14.208 0 14.232 0.084 ;
    END
  END cw_d[61]
  PIN cw_d[62]
    DIRECTION INPUT ;
    USE SIGNAL ;
    PORT
      LAYER M5 ;
        RECT  14.4 0 14.424 0.084 ;
    END
  END cw_d[62]
  PIN cw_d[63]
    DIRECTION INPUT ;
    USE SIGNAL ;
    PORT
      LAYER M5 ;
        RECT  14.592 0 14.616 0.084 ;
    END
  END cw_d[63]
  PIN cw_d[64]
    DIRECTION INPUT ;
    USE SIGNAL ;
    PORT
      LAYER M5 ;
        RECT  14.784 0 14.808 0.084 ;
    END
  END cw_d[64]
  PIN cw_d[65]
    DIRECTION INPUT ;
    USE SIGNAL ;
    PORT
      LAYER M5 ;
        RECT  14.976 0 15 0.084 ;
    END
  END cw_d[65]
  PIN cw_d[66]
    DIRECTION INPUT ;
    USE SIGNAL ;
    PORT
      LAYER M5 ;
        RECT  15.168 0 15.192 0.084 ;
    END
  END cw_d[66]
  PIN cw_d[67]
    DIRECTION INPUT ;
    USE SIGNAL ;
    PORT
      LAYER M5 ;
        RECT  15.36 0 15.384 0.084 ;
    END
  END cw_d[67]
  PIN cw_d[68]
    DIRECTION INPUT ;
    USE SIGNAL ;
    PORT
      LAYER M5 ;
        RECT  15.552 0 15.576 0.084 ;
    END
  END cw_d[68]
  PIN cw_d[69]
    DIRECTION INPUT ;
    USE SIGNAL ;
    PORT
      LAYER M5 ;
        RECT  15.744 0 15.768 0.084 ;
    END
  END cw_d[69]
  PIN cw_d[6]
    DIRECTION INPUT ;
    USE SIGNAL ;
    PORT
      LAYER M5 ;
        RECT  33.984 0 34.008 0.084 ;
    END
  END cw_d[6]
  PIN cw_d[70]
    DIRECTION INPUT ;
    USE SIGNAL ;
    PORT
      LAYER M5 ;
        RECT  15.936 0 15.96 0.084 ;
    END
  END cw_d[70]
  PIN cw_d[71]
    DIRECTION INPUT ;
    USE SIGNAL ;
    PORT
      LAYER M5 ;
        RECT  16.128 0 16.152 0.084 ;
    END
  END cw_d[71]
  PIN cw_d[72]
    DIRECTION INPUT ;
    USE SIGNAL ;
    PORT
      LAYER M5 ;
        RECT  16.32 0 16.344 0.084 ;
    END
  END cw_d[72]
  PIN cw_d[73]
    DIRECTION INPUT ;
    USE SIGNAL ;
    PORT
      LAYER M5 ;
        RECT  16.512 0 16.536 0.084 ;
    END
  END cw_d[73]
  PIN cw_d[74]
    DIRECTION INPUT ;
    USE SIGNAL ;
    PORT
      LAYER M5 ;
        RECT  16.704 0 16.728 0.084 ;
    END
  END cw_d[74]
  PIN cw_d[75]
    DIRECTION INPUT ;
    USE SIGNAL ;
    PORT
      LAYER M5 ;
        RECT  16.896 0 16.92 0.084 ;
    END
  END cw_d[75]
  PIN cw_d[76]
    DIRECTION INPUT ;
    USE SIGNAL ;
    PORT
      LAYER M5 ;
        RECT  17.088 0 17.112 0.084 ;
    END
  END cw_d[76]
  PIN cw_d[77]
    DIRECTION INPUT ;
    USE SIGNAL ;
    PORT
      LAYER M5 ;
        RECT  17.28 0 17.304 0.084 ;
    END
  END cw_d[77]
  PIN cw_d[78]
    DIRECTION INPUT ;
    USE SIGNAL ;
    PORT
      LAYER M5 ;
        RECT  17.472 0 17.496 0.084 ;
    END
  END cw_d[78]
  PIN cw_d[79]
    DIRECTION INPUT ;
    USE SIGNAL ;
    PORT
      LAYER M5 ;
        RECT  17.664 0 17.688 0.084 ;
    END
  END cw_d[79]
  PIN cw_d[7]
    DIRECTION INPUT ;
    USE SIGNAL ;
    PORT
      LAYER M5 ;
        RECT  34.176 0 34.2 0.084 ;
    END
  END cw_d[7]
  PIN cw_d[80]
    DIRECTION INPUT ;
    USE SIGNAL ;
    PORT
      LAYER M5 ;
        RECT  17.856 0 17.88 0.084 ;
    END
  END cw_d[80]
  PIN cw_d[81]
    DIRECTION INPUT ;
    USE SIGNAL ;
    PORT
      LAYER M5 ;
        RECT  18.048 0 18.072 0.084 ;
    END
  END cw_d[81]
  PIN cw_d[82]
    DIRECTION INPUT ;
    USE SIGNAL ;
    PORT
      LAYER M5 ;
        RECT  18.24 0 18.264 0.084 ;
    END
  END cw_d[82]
  PIN cw_d[83]
    DIRECTION INPUT ;
    USE SIGNAL ;
    PORT
      LAYER M5 ;
        RECT  18.432 0 18.456 0.084 ;
    END
  END cw_d[83]
  PIN cw_d[84]
    DIRECTION INPUT ;
    USE SIGNAL ;
    PORT
      LAYER M5 ;
        RECT  18.624 0 18.648 0.084 ;
    END
  END cw_d[84]
  PIN cw_d[85]
    DIRECTION INPUT ;
    USE SIGNAL ;
    PORT
      LAYER M5 ;
        RECT  18.816 0 18.84 0.084 ;
    END
  END cw_d[85]
  PIN cw_d[86]
    DIRECTION INPUT ;
    USE SIGNAL ;
    PORT
      LAYER M5 ;
        RECT  67.776 0 67.8 0.084 ;
    END
  END cw_d[86]
  PIN cw_d[87]
    DIRECTION INPUT ;
    USE SIGNAL ;
    PORT
      LAYER M5 ;
        RECT  67.968 0 67.992 0.084 ;
    END
  END cw_d[87]
  PIN cw_d[88]
    DIRECTION INPUT ;
    USE SIGNAL ;
    PORT
      LAYER M5 ;
        RECT  68.16 0 68.184 0.084 ;
    END
  END cw_d[88]
  PIN cw_d[89]
    DIRECTION INPUT ;
    USE SIGNAL ;
    PORT
      LAYER M5 ;
        RECT  68.352 0 68.376 0.084 ;
    END
  END cw_d[89]
  PIN cw_d[8]
    DIRECTION INPUT ;
    USE SIGNAL ;
    PORT
      LAYER M5 ;
        RECT  34.368 0 34.392 0.084 ;
    END
  END cw_d[8]
  PIN cw_d[90]
    DIRECTION INPUT ;
    USE SIGNAL ;
    PORT
      LAYER M5 ;
        RECT  68.544 0 68.568 0.084 ;
    END
  END cw_d[90]
  PIN cw_d[91]
    DIRECTION INPUT ;
    USE SIGNAL ;
    PORT
      LAYER M5 ;
        RECT  68.736 0 68.76 0.084 ;
    END
  END cw_d[91]
  PIN cw_d[92]
    DIRECTION INPUT ;
    USE SIGNAL ;
    PORT
      LAYER M5 ;
        RECT  68.928 0 68.952 0.084 ;
    END
  END cw_d[92]
  PIN cw_d[93]
    DIRECTION INPUT ;
    USE SIGNAL ;
    PORT
      LAYER M5 ;
        RECT  69.12 0 69.144 0.084 ;
    END
  END cw_d[93]
  PIN cw_d[94]
    DIRECTION INPUT ;
    USE SIGNAL ;
    PORT
      LAYER M5 ;
        RECT  69.312 0 69.336 0.084 ;
    END
  END cw_d[94]
  PIN cw_d[95]
    DIRECTION INPUT ;
    USE SIGNAL ;
    PORT
      LAYER M5 ;
        RECT  69.504 0 69.528 0.084 ;
    END
  END cw_d[95]
  PIN cw_d[96]
    DIRECTION INPUT ;
    USE SIGNAL ;
    PORT
      LAYER M5 ;
        RECT  69.696 0 69.72 0.084 ;
    END
  END cw_d[96]
  PIN cw_d[97]
    DIRECTION INPUT ;
    USE SIGNAL ;
    PORT
      LAYER M5 ;
        RECT  69.888 0 69.912 0.084 ;
    END
  END cw_d[97]
  PIN cw_d[98]
    DIRECTION INPUT ;
    USE SIGNAL ;
    PORT
      LAYER M5 ;
        RECT  70.08 0 70.104 0.084 ;
    END
  END cw_d[98]
  PIN cw_d[99]
    DIRECTION INPUT ;
    USE SIGNAL ;
    PORT
      LAYER M5 ;
        RECT  70.272 0 70.296 0.084 ;
    END
  END cw_d[99]
  PIN cw_d[9]
    DIRECTION INPUT ;
    USE SIGNAL ;
    PORT
      LAYER M5 ;
        RECT  34.56 0 34.584 0.084 ;
    END
  END cw_d[9]
  PIN cw_v
    DIRECTION INPUT ;
    USE SIGNAL ;
    PORT
      LAYER M5 ;
        RECT  106.56 0 106.584 0.084 ;
    END
  END cw_v
  PIN cwo_a[0]
    DIRECTION OUTPUT ;
    USE SIGNAL ;
    PORT
      LAYER M5 ;
        RECT  58.56 107.916 58.584 108 ;
    END
  END cwo_a[0]
  PIN cwo_a[1]
    DIRECTION OUTPUT ;
    USE SIGNAL ;
    PORT
      LAYER M5 ;
        RECT  58.752 107.916 58.776 108 ;
    END
  END cwo_a[1]
  PIN cwo_a[2]
    DIRECTION OUTPUT ;
    USE SIGNAL ;
    PORT
      LAYER M5 ;
        RECT  58.944 107.916 58.968 108 ;
    END
  END cwo_a[2]
  PIN cwo_a[3]
    DIRECTION OUTPUT ;
    USE SIGNAL ;
    PORT
      LAYER M5 ;
        RECT  59.136 107.916 59.16 108 ;
    END
  END cwo_a[3]
  PIN cwo_a[4]
    DIRECTION OUTPUT ;
    USE SIGNAL ;
    PORT
      LAYER M5 ;
        RECT  59.328 107.916 59.352 108 ;
    END
  END cwo_a[4]
  PIN cwo_a[5]
    DIRECTION OUTPUT ;
    USE SIGNAL ;
    PORT
      LAYER M5 ;
        RECT  59.52 107.916 59.544 108 ;
    END
  END cwo_a[5]
  PIN cwo_a[6]
    DIRECTION OUTPUT ;
    USE SIGNAL ;
    PORT
      LAYER M5 ;
        RECT  59.712 107.916 59.736 108 ;
    END
  END cwo_a[6]
  PIN cwo_a[7]
    DIRECTION OUTPUT ;
    USE SIGNAL ;
    PORT
      LAYER M5 ;
        RECT  59.904 107.916 59.928 108 ;
    END
  END cwo_a[7]
  PIN cwo_d[0]
    DIRECTION OUTPUT ;
    USE SIGNAL ;
    PORT
      LAYER M5 ;
        RECT  60.096 107.916 60.12 108 ;
    END
  END cwo_d[0]
  PIN cwo_d[100]
    DIRECTION OUTPUT ;
    USE SIGNAL ;
    PORT
      LAYER M5 ;
        RECT  67.008 107.916 67.032 108 ;
    END
  END cwo_d[100]
  PIN cwo_d[101]
    DIRECTION OUTPUT ;
    USE SIGNAL ;
    PORT
      LAYER M5 ;
        RECT  67.2 107.916 67.224 108 ;
    END
  END cwo_d[101]
  PIN cwo_d[102]
    DIRECTION OUTPUT ;
    USE SIGNAL ;
    PORT
      LAYER M5 ;
        RECT  67.392 107.916 67.416 108 ;
    END
  END cwo_d[102]
  PIN cwo_d[103]
    DIRECTION OUTPUT ;
    USE SIGNAL ;
    PORT
      LAYER M5 ;
        RECT  67.584 107.916 67.608 108 ;
    END
  END cwo_d[103]
  PIN cwo_d[104]
    DIRECTION OUTPUT ;
    USE SIGNAL ;
    PORT
      LAYER M5 ;
        RECT  67.776 107.916 67.8 108 ;
    END
  END cwo_d[104]
  PIN cwo_d[105]
    DIRECTION OUTPUT ;
    USE SIGNAL ;
    PORT
      LAYER M5 ;
        RECT  67.968 107.916 67.992 108 ;
    END
  END cwo_d[105]
  PIN cwo_d[106]
    DIRECTION OUTPUT ;
    USE SIGNAL ;
    PORT
      LAYER M5 ;
        RECT  68.16 107.916 68.184 108 ;
    END
  END cwo_d[106]
  PIN cwo_d[107]
    DIRECTION OUTPUT ;
    USE SIGNAL ;
    PORT
      LAYER M5 ;
        RECT  68.352 107.916 68.376 108 ;
    END
  END cwo_d[107]
  PIN cwo_d[108]
    DIRECTION OUTPUT ;
    USE SIGNAL ;
    PORT
      LAYER M5 ;
        RECT  68.544 107.916 68.568 108 ;
    END
  END cwo_d[108]
  PIN cwo_d[109]
    DIRECTION OUTPUT ;
    USE SIGNAL ;
    PORT
      LAYER M5 ;
        RECT  68.736 107.916 68.76 108 ;
    END
  END cwo_d[109]
  PIN cwo_d[10]
    DIRECTION OUTPUT ;
    USE SIGNAL ;
    PORT
      LAYER M5 ;
        RECT  62.016 107.916 62.04 108 ;
    END
  END cwo_d[10]
  PIN cwo_d[110]
    DIRECTION OUTPUT ;
    USE SIGNAL ;
    PORT
      LAYER M5 ;
        RECT  68.928 107.916 68.952 108 ;
    END
  END cwo_d[110]
  PIN cwo_d[111]
    DIRECTION OUTPUT ;
    USE SIGNAL ;
    PORT
      LAYER M5 ;
        RECT  69.12 107.916 69.144 108 ;
    END
  END cwo_d[111]
  PIN cwo_d[112]
    DIRECTION OUTPUT ;
    USE SIGNAL ;
    PORT
      LAYER M5 ;
        RECT  69.312 107.916 69.336 108 ;
    END
  END cwo_d[112]
  PIN cwo_d[113]
    DIRECTION OUTPUT ;
    USE SIGNAL ;
    PORT
      LAYER M5 ;
        RECT  69.504 107.916 69.528 108 ;
    END
  END cwo_d[113]
  PIN cwo_d[114]
    DIRECTION OUTPUT ;
    USE SIGNAL ;
    PORT
      LAYER M5 ;
        RECT  69.696 107.916 69.72 108 ;
    END
  END cwo_d[114]
  PIN cwo_d[115]
    DIRECTION OUTPUT ;
    USE SIGNAL ;
    PORT
      LAYER M5 ;
        RECT  69.888 107.916 69.912 108 ;
    END
  END cwo_d[115]
  PIN cwo_d[116]
    DIRECTION OUTPUT ;
    USE SIGNAL ;
    PORT
      LAYER M5 ;
        RECT  70.08 107.916 70.104 108 ;
    END
  END cwo_d[116]
  PIN cwo_d[117]
    DIRECTION OUTPUT ;
    USE SIGNAL ;
    PORT
      LAYER M5 ;
        RECT  70.272 107.916 70.296 108 ;
    END
  END cwo_d[117]
  PIN cwo_d[118]
    DIRECTION OUTPUT ;
    USE SIGNAL ;
    PORT
      LAYER M5 ;
        RECT  19.2 107.916 19.224 108 ;
    END
  END cwo_d[118]
  PIN cwo_d[119]
    DIRECTION OUTPUT ;
    USE SIGNAL ;
    PORT
      LAYER M5 ;
        RECT  19.392 107.916 19.416 108 ;
    END
  END cwo_d[119]
  PIN cwo_d[11]
    DIRECTION OUTPUT ;
    USE SIGNAL ;
    PORT
      LAYER M5 ;
        RECT  62.208 107.916 62.232 108 ;
    END
  END cwo_d[11]
  PIN cwo_d[120]
    DIRECTION OUTPUT ;
    USE SIGNAL ;
    PORT
      LAYER M5 ;
        RECT  19.584 107.916 19.608 108 ;
    END
  END cwo_d[120]
  PIN cwo_d[121]
    DIRECTION OUTPUT ;
    USE SIGNAL ;
    PORT
      LAYER M5 ;
        RECT  19.776 107.916 19.8 108 ;
    END
  END cwo_d[121]
  PIN cwo_d[122]
    DIRECTION OUTPUT ;
    USE SIGNAL ;
    PORT
      LAYER M5 ;
        RECT  19.968 107.916 19.992 108 ;
    END
  END cwo_d[122]
  PIN cwo_d[123]
    DIRECTION OUTPUT ;
    USE SIGNAL ;
    PORT
      LAYER M5 ;
        RECT  20.16 107.916 20.184 108 ;
    END
  END cwo_d[123]
  PIN cwo_d[124]
    DIRECTION OUTPUT ;
    USE SIGNAL ;
    PORT
      LAYER M5 ;
        RECT  20.352 107.916 20.376 108 ;
    END
  END cwo_d[124]
  PIN cwo_d[125]
    DIRECTION OUTPUT ;
    USE SIGNAL ;
    PORT
      LAYER M5 ;
        RECT  20.544 107.916 20.568 108 ;
    END
  END cwo_d[125]
  PIN cwo_d[126]
    DIRECTION OUTPUT ;
    USE SIGNAL ;
    PORT
      LAYER M5 ;
        RECT  20.736 107.916 20.76 108 ;
    END
  END cwo_d[126]
  PIN cwo_d[127]
    DIRECTION OUTPUT ;
    USE SIGNAL ;
    PORT
      LAYER M5 ;
        RECT  20.928 107.916 20.952 108 ;
    END
  END cwo_d[127]
  PIN cwo_d[128]
    DIRECTION OUTPUT ;
    USE SIGNAL ;
    PORT
      LAYER M5 ;
        RECT  21.12 107.916 21.144 108 ;
    END
  END cwo_d[128]
  PIN cwo_d[129]
    DIRECTION OUTPUT ;
    USE SIGNAL ;
    PORT
      LAYER M5 ;
        RECT  21.312 107.916 21.336 108 ;
    END
  END cwo_d[129]
  PIN cwo_d[12]
    DIRECTION OUTPUT ;
    USE SIGNAL ;
    PORT
      LAYER M5 ;
        RECT  62.4 107.916 62.424 108 ;
    END
  END cwo_d[12]
  PIN cwo_d[130]
    DIRECTION OUTPUT ;
    USE SIGNAL ;
    PORT
      LAYER M5 ;
        RECT  21.504 107.916 21.528 108 ;
    END
  END cwo_d[130]
  PIN cwo_d[131]
    DIRECTION OUTPUT ;
    USE SIGNAL ;
    PORT
      LAYER M5 ;
        RECT  21.696 107.916 21.72 108 ;
    END
  END cwo_d[131]
  PIN cwo_d[132]
    DIRECTION OUTPUT ;
    USE SIGNAL ;
    PORT
      LAYER M5 ;
        RECT  21.888 107.916 21.912 108 ;
    END
  END cwo_d[132]
  PIN cwo_d[133]
    DIRECTION OUTPUT ;
    USE SIGNAL ;
    PORT
      LAYER M5 ;
        RECT  22.08 107.916 22.104 108 ;
    END
  END cwo_d[133]
  PIN cwo_d[134]
    DIRECTION OUTPUT ;
    USE SIGNAL ;
    PORT
      LAYER M5 ;
        RECT  22.272 107.916 22.296 108 ;
    END
  END cwo_d[134]
  PIN cwo_d[135]
    DIRECTION OUTPUT ;
    USE SIGNAL ;
    PORT
      LAYER M5 ;
        RECT  22.464 107.916 22.488 108 ;
    END
  END cwo_d[135]
  PIN cwo_d[136]
    DIRECTION OUTPUT ;
    USE SIGNAL ;
    PORT
      LAYER M5 ;
        RECT  22.656 107.916 22.68 108 ;
    END
  END cwo_d[136]
  PIN cwo_d[137]
    DIRECTION OUTPUT ;
    USE SIGNAL ;
    PORT
      LAYER M5 ;
        RECT  22.848 107.916 22.872 108 ;
    END
  END cwo_d[137]
  PIN cwo_d[138]
    DIRECTION OUTPUT ;
    USE SIGNAL ;
    PORT
      LAYER M5 ;
        RECT  23.04 107.916 23.064 108 ;
    END
  END cwo_d[138]
  PIN cwo_d[139]
    DIRECTION OUTPUT ;
    USE SIGNAL ;
    PORT
      LAYER M5 ;
        RECT  23.232 107.916 23.256 108 ;
    END
  END cwo_d[139]
  PIN cwo_d[13]
    DIRECTION OUTPUT ;
    USE SIGNAL ;
    PORT
      LAYER M5 ;
        RECT  62.592 107.916 62.616 108 ;
    END
  END cwo_d[13]
  PIN cwo_d[140]
    DIRECTION OUTPUT ;
    USE SIGNAL ;
    PORT
      LAYER M5 ;
        RECT  23.424 107.916 23.448 108 ;
    END
  END cwo_d[140]
  PIN cwo_d[141]
    DIRECTION OUTPUT ;
    USE SIGNAL ;
    PORT
      LAYER M5 ;
        RECT  23.616 107.916 23.64 108 ;
    END
  END cwo_d[141]
  PIN cwo_d[142]
    DIRECTION OUTPUT ;
    USE SIGNAL ;
    PORT
      LAYER M5 ;
        RECT  23.808 107.916 23.832 108 ;
    END
  END cwo_d[142]
  PIN cwo_d[143]
    DIRECTION OUTPUT ;
    USE SIGNAL ;
    PORT
      LAYER M5 ;
        RECT  24 107.916 24.024 108 ;
    END
  END cwo_d[143]
  PIN cwo_d[144]
    DIRECTION OUTPUT ;
    USE SIGNAL ;
    PORT
      LAYER M5 ;
        RECT  24.192 107.916 24.216 108 ;
    END
  END cwo_d[144]
  PIN cwo_d[145]
    DIRECTION OUTPUT ;
    USE SIGNAL ;
    PORT
      LAYER M5 ;
        RECT  24.384 107.916 24.408 108 ;
    END
  END cwo_d[145]
  PIN cwo_d[146]
    DIRECTION OUTPUT ;
    USE SIGNAL ;
    PORT
      LAYER M5 ;
        RECT  24.576 107.916 24.6 108 ;
    END
  END cwo_d[146]
  PIN cwo_d[147]
    DIRECTION OUTPUT ;
    USE SIGNAL ;
    PORT
      LAYER M5 ;
        RECT  24.768 107.916 24.792 108 ;
    END
  END cwo_d[147]
  PIN cwo_d[148]
    DIRECTION OUTPUT ;
    USE SIGNAL ;
    PORT
      LAYER M5 ;
        RECT  24.96 107.916 24.984 108 ;
    END
  END cwo_d[148]
  PIN cwo_d[149]
    DIRECTION OUTPUT ;
    USE SIGNAL ;
    PORT
      LAYER M5 ;
        RECT  25.152 107.916 25.176 108 ;
    END
  END cwo_d[149]
  PIN cwo_d[14]
    DIRECTION OUTPUT ;
    USE SIGNAL ;
    PORT
      LAYER M5 ;
        RECT  62.784 107.916 62.808 108 ;
    END
  END cwo_d[14]
  PIN cwo_d[150]
    DIRECTION OUTPUT ;
    USE SIGNAL ;
    PORT
      LAYER M5 ;
        RECT  0.768 107.916 0.792 108 ;
    END
  END cwo_d[150]
  PIN cwo_d[151]
    DIRECTION OUTPUT ;
    USE SIGNAL ;
    PORT
      LAYER M5 ;
        RECT  0.96 107.916 0.984 108 ;
    END
  END cwo_d[151]
  PIN cwo_d[152]
    DIRECTION OUTPUT ;
    USE SIGNAL ;
    PORT
      LAYER M5 ;
        RECT  1.152 107.916 1.176 108 ;
    END
  END cwo_d[152]
  PIN cwo_d[153]
    DIRECTION OUTPUT ;
    USE SIGNAL ;
    PORT
      LAYER M5 ;
        RECT  1.344 107.916 1.368 108 ;
    END
  END cwo_d[153]
  PIN cwo_d[154]
    DIRECTION OUTPUT ;
    USE SIGNAL ;
    PORT
      LAYER M5 ;
        RECT  1.536 107.916 1.56 108 ;
    END
  END cwo_d[154]
  PIN cwo_d[155]
    DIRECTION OUTPUT ;
    USE SIGNAL ;
    PORT
      LAYER M5 ;
        RECT  1.728 107.916 1.752 108 ;
    END
  END cwo_d[155]
  PIN cwo_d[156]
    DIRECTION OUTPUT ;
    USE SIGNAL ;
    PORT
      LAYER M5 ;
        RECT  1.92 107.916 1.944 108 ;
    END
  END cwo_d[156]
  PIN cwo_d[157]
    DIRECTION OUTPUT ;
    USE SIGNAL ;
    PORT
      LAYER M5 ;
        RECT  2.112 107.916 2.136 108 ;
    END
  END cwo_d[157]
  PIN cwo_d[158]
    DIRECTION OUTPUT ;
    USE SIGNAL ;
    PORT
      LAYER M5 ;
        RECT  2.304 107.916 2.328 108 ;
    END
  END cwo_d[158]
  PIN cwo_d[159]
    DIRECTION OUTPUT ;
    USE SIGNAL ;
    PORT
      LAYER M5 ;
        RECT  2.496 107.916 2.52 108 ;
    END
  END cwo_d[159]
  PIN cwo_d[15]
    DIRECTION OUTPUT ;
    USE SIGNAL ;
    PORT
      LAYER M5 ;
        RECT  62.976 107.916 63 108 ;
    END
  END cwo_d[15]
  PIN cwo_d[160]
    DIRECTION OUTPUT ;
    USE SIGNAL ;
    PORT
      LAYER M5 ;
        RECT  2.688 107.916 2.712 108 ;
    END
  END cwo_d[160]
  PIN cwo_d[161]
    DIRECTION OUTPUT ;
    USE SIGNAL ;
    PORT
      LAYER M5 ;
        RECT  2.88 107.916 2.904 108 ;
    END
  END cwo_d[161]
  PIN cwo_d[162]
    DIRECTION OUTPUT ;
    USE SIGNAL ;
    PORT
      LAYER M5 ;
        RECT  3.072 107.916 3.096 108 ;
    END
  END cwo_d[162]
  PIN cwo_d[163]
    DIRECTION OUTPUT ;
    USE SIGNAL ;
    PORT
      LAYER M5 ;
        RECT  3.264 107.916 3.288 108 ;
    END
  END cwo_d[163]
  PIN cwo_d[164]
    DIRECTION OUTPUT ;
    USE SIGNAL ;
    PORT
      LAYER M5 ;
        RECT  3.456 107.916 3.48 108 ;
    END
  END cwo_d[164]
  PIN cwo_d[165]
    DIRECTION OUTPUT ;
    USE SIGNAL ;
    PORT
      LAYER M5 ;
        RECT  3.648 107.916 3.672 108 ;
    END
  END cwo_d[165]
  PIN cwo_d[166]
    DIRECTION OUTPUT ;
    USE SIGNAL ;
    PORT
      LAYER M5 ;
        RECT  3.84 107.916 3.864 108 ;
    END
  END cwo_d[166]
  PIN cwo_d[167]
    DIRECTION OUTPUT ;
    USE SIGNAL ;
    PORT
      LAYER M5 ;
        RECT  4.032 107.916 4.056 108 ;
    END
  END cwo_d[167]
  PIN cwo_d[168]
    DIRECTION OUTPUT ;
    USE SIGNAL ;
    PORT
      LAYER M5 ;
        RECT  4.224 107.916 4.248 108 ;
    END
  END cwo_d[168]
  PIN cwo_d[169]
    DIRECTION OUTPUT ;
    USE SIGNAL ;
    PORT
      LAYER M5 ;
        RECT  4.416 107.916 4.44 108 ;
    END
  END cwo_d[169]
  PIN cwo_d[16]
    DIRECTION OUTPUT ;
    USE SIGNAL ;
    PORT
      LAYER M5 ;
        RECT  63.168 107.916 63.192 108 ;
    END
  END cwo_d[16]
  PIN cwo_d[170]
    DIRECTION OUTPUT ;
    USE SIGNAL ;
    PORT
      LAYER M5 ;
        RECT  4.608 107.916 4.632 108 ;
    END
  END cwo_d[170]
  PIN cwo_d[171]
    DIRECTION OUTPUT ;
    USE SIGNAL ;
    PORT
      LAYER M5 ;
        RECT  4.8 107.916 4.824 108 ;
    END
  END cwo_d[171]
  PIN cwo_d[172]
    DIRECTION OUTPUT ;
    USE SIGNAL ;
    PORT
      LAYER M5 ;
        RECT  4.992 107.916 5.016 108 ;
    END
  END cwo_d[172]
  PIN cwo_d[173]
    DIRECTION OUTPUT ;
    USE SIGNAL ;
    PORT
      LAYER M5 ;
        RECT  5.184 107.916 5.208 108 ;
    END
  END cwo_d[173]
  PIN cwo_d[174]
    DIRECTION OUTPUT ;
    USE SIGNAL ;
    PORT
      LAYER M5 ;
        RECT  5.376 107.916 5.4 108 ;
    END
  END cwo_d[174]
  PIN cwo_d[175]
    DIRECTION OUTPUT ;
    USE SIGNAL ;
    PORT
      LAYER M5 ;
        RECT  5.568 107.916 5.592 108 ;
    END
  END cwo_d[175]
  PIN cwo_d[176]
    DIRECTION OUTPUT ;
    USE SIGNAL ;
    PORT
      LAYER M5 ;
        RECT  5.76 107.916 5.784 108 ;
    END
  END cwo_d[176]
  PIN cwo_d[177]
    DIRECTION OUTPUT ;
    USE SIGNAL ;
    PORT
      LAYER M5 ;
        RECT  5.952 107.916 5.976 108 ;
    END
  END cwo_d[177]
  PIN cwo_d[178]
    DIRECTION OUTPUT ;
    USE SIGNAL ;
    PORT
      LAYER M5 ;
        RECT  6.144 107.916 6.168 108 ;
    END
  END cwo_d[178]
  PIN cwo_d[179]
    DIRECTION OUTPUT ;
    USE SIGNAL ;
    PORT
      LAYER M5 ;
        RECT  6.336 107.916 6.36 108 ;
    END
  END cwo_d[179]
  PIN cwo_d[17]
    DIRECTION OUTPUT ;
    USE SIGNAL ;
    PORT
      LAYER M5 ;
        RECT  63.36 107.916 63.384 108 ;
    END
  END cwo_d[17]
  PIN cwo_d[180]
    DIRECTION OUTPUT ;
    USE SIGNAL ;
    PORT
      LAYER M5 ;
        RECT  6.528 107.916 6.552 108 ;
    END
  END cwo_d[180]
  PIN cwo_d[181]
    DIRECTION OUTPUT ;
    USE SIGNAL ;
    PORT
      LAYER M5 ;
        RECT  6.72 107.916 6.744 108 ;
    END
  END cwo_d[181]
  PIN cwo_d[182]
    DIRECTION OUTPUT ;
    USE SIGNAL ;
    PORT
      LAYER M5 ;
        RECT  25.344 107.916 25.368 108 ;
    END
  END cwo_d[182]
  PIN cwo_d[183]
    DIRECTION OUTPUT ;
    USE SIGNAL ;
    PORT
      LAYER M5 ;
        RECT  25.536 107.916 25.56 108 ;
    END
  END cwo_d[183]
  PIN cwo_d[184]
    DIRECTION OUTPUT ;
    USE SIGNAL ;
    PORT
      LAYER M5 ;
        RECT  25.728 107.916 25.752 108 ;
    END
  END cwo_d[184]
  PIN cwo_d[185]
    DIRECTION OUTPUT ;
    USE SIGNAL ;
    PORT
      LAYER M5 ;
        RECT  25.92 107.916 25.944 108 ;
    END
  END cwo_d[185]
  PIN cwo_d[186]
    DIRECTION OUTPUT ;
    USE SIGNAL ;
    PORT
      LAYER M5 ;
        RECT  26.112 107.916 26.136 108 ;
    END
  END cwo_d[186]
  PIN cwo_d[187]
    DIRECTION OUTPUT ;
    USE SIGNAL ;
    PORT
      LAYER M5 ;
        RECT  26.304 107.916 26.328 108 ;
    END
  END cwo_d[187]
  PIN cwo_d[188]
    DIRECTION OUTPUT ;
    USE SIGNAL ;
    PORT
      LAYER M5 ;
        RECT  26.496 107.916 26.52 108 ;
    END
  END cwo_d[188]
  PIN cwo_d[189]
    DIRECTION OUTPUT ;
    USE SIGNAL ;
    PORT
      LAYER M5 ;
        RECT  26.688 107.916 26.712 108 ;
    END
  END cwo_d[189]
  PIN cwo_d[18]
    DIRECTION OUTPUT ;
    USE SIGNAL ;
    PORT
      LAYER M5 ;
        RECT  63.552 107.916 63.576 108 ;
    END
  END cwo_d[18]
  PIN cwo_d[190]
    DIRECTION OUTPUT ;
    USE SIGNAL ;
    PORT
      LAYER M5 ;
        RECT  26.88 107.916 26.904 108 ;
    END
  END cwo_d[190]
  PIN cwo_d[191]
    DIRECTION OUTPUT ;
    USE SIGNAL ;
    PORT
      LAYER M5 ;
        RECT  27.072 107.916 27.096 108 ;
    END
  END cwo_d[191]
  PIN cwo_d[192]
    DIRECTION OUTPUT ;
    USE SIGNAL ;
    PORT
      LAYER M5 ;
        RECT  27.264 107.916 27.288 108 ;
    END
  END cwo_d[192]
  PIN cwo_d[193]
    DIRECTION OUTPUT ;
    USE SIGNAL ;
    PORT
      LAYER M5 ;
        RECT  27.456 107.916 27.48 108 ;
    END
  END cwo_d[193]
  PIN cwo_d[194]
    DIRECTION OUTPUT ;
    USE SIGNAL ;
    PORT
      LAYER M5 ;
        RECT  27.648 107.916 27.672 108 ;
    END
  END cwo_d[194]
  PIN cwo_d[195]
    DIRECTION OUTPUT ;
    USE SIGNAL ;
    PORT
      LAYER M5 ;
        RECT  27.84 107.916 27.864 108 ;
    END
  END cwo_d[195]
  PIN cwo_d[196]
    DIRECTION OUTPUT ;
    USE SIGNAL ;
    PORT
      LAYER M5 ;
        RECT  28.032 107.916 28.056 108 ;
    END
  END cwo_d[196]
  PIN cwo_d[197]
    DIRECTION OUTPUT ;
    USE SIGNAL ;
    PORT
      LAYER M5 ;
        RECT  28.224 107.916 28.248 108 ;
    END
  END cwo_d[197]
  PIN cwo_d[198]
    DIRECTION OUTPUT ;
    USE SIGNAL ;
    PORT
      LAYER M5 ;
        RECT  28.416 107.916 28.44 108 ;
    END
  END cwo_d[198]
  PIN cwo_d[199]
    DIRECTION OUTPUT ;
    USE SIGNAL ;
    PORT
      LAYER M5 ;
        RECT  28.608 107.916 28.632 108 ;
    END
  END cwo_d[199]
  PIN cwo_d[19]
    DIRECTION OUTPUT ;
    USE SIGNAL ;
    PORT
      LAYER M5 ;
        RECT  63.744 107.916 63.768 108 ;
    END
  END cwo_d[19]
  PIN cwo_d[1]
    DIRECTION OUTPUT ;
    USE SIGNAL ;
    PORT
      LAYER M5 ;
        RECT  60.288 107.916 60.312 108 ;
    END
  END cwo_d[1]
  PIN cwo_d[200]
    DIRECTION OUTPUT ;
    USE SIGNAL ;
    PORT
      LAYER M5 ;
        RECT  28.8 107.916 28.824 108 ;
    END
  END cwo_d[200]
  PIN cwo_d[201]
    DIRECTION OUTPUT ;
    USE SIGNAL ;
    PORT
      LAYER M5 ;
        RECT  28.992 107.916 29.016 108 ;
    END
  END cwo_d[201]
  PIN cwo_d[202]
    DIRECTION OUTPUT ;
    USE SIGNAL ;
    PORT
      LAYER M5 ;
        RECT  29.184 107.916 29.208 108 ;
    END
  END cwo_d[202]
  PIN cwo_d[203]
    DIRECTION OUTPUT ;
    USE SIGNAL ;
    PORT
      LAYER M5 ;
        RECT  29.376 107.916 29.4 108 ;
    END
  END cwo_d[203]
  PIN cwo_d[204]
    DIRECTION OUTPUT ;
    USE SIGNAL ;
    PORT
      LAYER M5 ;
        RECT  29.568 107.916 29.592 108 ;
    END
  END cwo_d[204]
  PIN cwo_d[205]
    DIRECTION OUTPUT ;
    USE SIGNAL ;
    PORT
      LAYER M5 ;
        RECT  29.76 107.916 29.784 108 ;
    END
  END cwo_d[205]
  PIN cwo_d[206]
    DIRECTION OUTPUT ;
    USE SIGNAL ;
    PORT
      LAYER M5 ;
        RECT  29.952 107.916 29.976 108 ;
    END
  END cwo_d[206]
  PIN cwo_d[207]
    DIRECTION OUTPUT ;
    USE SIGNAL ;
    PORT
      LAYER M5 ;
        RECT  30.144 107.916 30.168 108 ;
    END
  END cwo_d[207]
  PIN cwo_d[208]
    DIRECTION OUTPUT ;
    USE SIGNAL ;
    PORT
      LAYER M5 ;
        RECT  30.336 107.916 30.36 108 ;
    END
  END cwo_d[208]
  PIN cwo_d[209]
    DIRECTION OUTPUT ;
    USE SIGNAL ;
    PORT
      LAYER M5 ;
        RECT  30.528 107.916 30.552 108 ;
    END
  END cwo_d[209]
  PIN cwo_d[20]
    DIRECTION OUTPUT ;
    USE SIGNAL ;
    PORT
      LAYER M5 ;
        RECT  63.936 107.916 63.96 108 ;
    END
  END cwo_d[20]
  PIN cwo_d[210]
    DIRECTION OUTPUT ;
    USE SIGNAL ;
    PORT
      LAYER M5 ;
        RECT  30.72 107.916 30.744 108 ;
    END
  END cwo_d[210]
  PIN cwo_d[211]
    DIRECTION OUTPUT ;
    USE SIGNAL ;
    PORT
      LAYER M5 ;
        RECT  30.912 107.916 30.936 108 ;
    END
  END cwo_d[211]
  PIN cwo_d[212]
    DIRECTION OUTPUT ;
    USE SIGNAL ;
    PORT
      LAYER M5 ;
        RECT  31.104 107.916 31.128 108 ;
    END
  END cwo_d[212]
  PIN cwo_d[213]
    DIRECTION OUTPUT ;
    USE SIGNAL ;
    PORT
      LAYER M5 ;
        RECT  31.296 107.916 31.32 108 ;
    END
  END cwo_d[213]
  PIN cwo_d[214]
    DIRECTION OUTPUT ;
    USE SIGNAL ;
    PORT
      LAYER M5 ;
        RECT  13.056 107.916 13.08 108 ;
    END
  END cwo_d[214]
  PIN cwo_d[215]
    DIRECTION OUTPUT ;
    USE SIGNAL ;
    PORT
      LAYER M5 ;
        RECT  13.248 107.916 13.272 108 ;
    END
  END cwo_d[215]
  PIN cwo_d[216]
    DIRECTION OUTPUT ;
    USE SIGNAL ;
    PORT
      LAYER M5 ;
        RECT  13.44 107.916 13.464 108 ;
    END
  END cwo_d[216]
  PIN cwo_d[217]
    DIRECTION OUTPUT ;
    USE SIGNAL ;
    PORT
      LAYER M5 ;
        RECT  13.632 107.916 13.656 108 ;
    END
  END cwo_d[217]
  PIN cwo_d[218]
    DIRECTION OUTPUT ;
    USE SIGNAL ;
    PORT
      LAYER M5 ;
        RECT  13.824 107.916 13.848 108 ;
    END
  END cwo_d[218]
  PIN cwo_d[219]
    DIRECTION OUTPUT ;
    USE SIGNAL ;
    PORT
      LAYER M5 ;
        RECT  14.016 107.916 14.04 108 ;
    END
  END cwo_d[219]
  PIN cwo_d[21]
    DIRECTION OUTPUT ;
    USE SIGNAL ;
    PORT
      LAYER M5 ;
        RECT  64.128 107.916 64.152 108 ;
    END
  END cwo_d[21]
  PIN cwo_d[220]
    DIRECTION OUTPUT ;
    USE SIGNAL ;
    PORT
      LAYER M5 ;
        RECT  14.208 107.916 14.232 108 ;
    END
  END cwo_d[220]
  PIN cwo_d[221]
    DIRECTION OUTPUT ;
    USE SIGNAL ;
    PORT
      LAYER M5 ;
        RECT  14.4 107.916 14.424 108 ;
    END
  END cwo_d[221]
  PIN cwo_d[222]
    DIRECTION OUTPUT ;
    USE SIGNAL ;
    PORT
      LAYER M5 ;
        RECT  14.592 107.916 14.616 108 ;
    END
  END cwo_d[222]
  PIN cwo_d[223]
    DIRECTION OUTPUT ;
    USE SIGNAL ;
    PORT
      LAYER M5 ;
        RECT  14.784 107.916 14.808 108 ;
    END
  END cwo_d[223]
  PIN cwo_d[224]
    DIRECTION OUTPUT ;
    USE SIGNAL ;
    PORT
      LAYER M5 ;
        RECT  14.976 107.916 15 108 ;
    END
  END cwo_d[224]
  PIN cwo_d[225]
    DIRECTION OUTPUT ;
    USE SIGNAL ;
    PORT
      LAYER M5 ;
        RECT  15.168 107.916 15.192 108 ;
    END
  END cwo_d[225]
  PIN cwo_d[226]
    DIRECTION OUTPUT ;
    USE SIGNAL ;
    PORT
      LAYER M5 ;
        RECT  15.36 107.916 15.384 108 ;
    END
  END cwo_d[226]
  PIN cwo_d[227]
    DIRECTION OUTPUT ;
    USE SIGNAL ;
    PORT
      LAYER M5 ;
        RECT  15.552 107.916 15.576 108 ;
    END
  END cwo_d[227]
  PIN cwo_d[228]
    DIRECTION OUTPUT ;
    USE SIGNAL ;
    PORT
      LAYER M5 ;
        RECT  15.744 107.916 15.768 108 ;
    END
  END cwo_d[228]
  PIN cwo_d[229]
    DIRECTION OUTPUT ;
    USE SIGNAL ;
    PORT
      LAYER M5 ;
        RECT  15.936 107.916 15.96 108 ;
    END
  END cwo_d[229]
  PIN cwo_d[22]
    DIRECTION OUTPUT ;
    USE SIGNAL ;
    PORT
      LAYER M5 ;
        RECT  31.488 107.916 31.512 108 ;
    END
  END cwo_d[22]
  PIN cwo_d[230]
    DIRECTION OUTPUT ;
    USE SIGNAL ;
    PORT
      LAYER M5 ;
        RECT  16.128 107.916 16.152 108 ;
    END
  END cwo_d[230]
  PIN cwo_d[231]
    DIRECTION OUTPUT ;
    USE SIGNAL ;
    PORT
      LAYER M5 ;
        RECT  16.32 107.916 16.344 108 ;
    END
  END cwo_d[231]
  PIN cwo_d[232]
    DIRECTION OUTPUT ;
    USE SIGNAL ;
    PORT
      LAYER M5 ;
        RECT  16.512 107.916 16.536 108 ;
    END
  END cwo_d[232]
  PIN cwo_d[233]
    DIRECTION OUTPUT ;
    USE SIGNAL ;
    PORT
      LAYER M5 ;
        RECT  16.704 107.916 16.728 108 ;
    END
  END cwo_d[233]
  PIN cwo_d[234]
    DIRECTION OUTPUT ;
    USE SIGNAL ;
    PORT
      LAYER M5 ;
        RECT  16.896 107.916 16.92 108 ;
    END
  END cwo_d[234]
  PIN cwo_d[235]
    DIRECTION OUTPUT ;
    USE SIGNAL ;
    PORT
      LAYER M5 ;
        RECT  17.088 107.916 17.112 108 ;
    END
  END cwo_d[235]
  PIN cwo_d[236]
    DIRECTION OUTPUT ;
    USE SIGNAL ;
    PORT
      LAYER M5 ;
        RECT  17.28 107.916 17.304 108 ;
    END
  END cwo_d[236]
  PIN cwo_d[237]
    DIRECTION OUTPUT ;
    USE SIGNAL ;
    PORT
      LAYER M5 ;
        RECT  17.472 107.916 17.496 108 ;
    END
  END cwo_d[237]
  PIN cwo_d[238]
    DIRECTION OUTPUT ;
    USE SIGNAL ;
    PORT
      LAYER M5 ;
        RECT  17.664 107.916 17.688 108 ;
    END
  END cwo_d[238]
  PIN cwo_d[239]
    DIRECTION OUTPUT ;
    USE SIGNAL ;
    PORT
      LAYER M5 ;
        RECT  17.856 107.916 17.88 108 ;
    END
  END cwo_d[239]
  PIN cwo_d[23]
    DIRECTION OUTPUT ;
    USE SIGNAL ;
    PORT
      LAYER M5 ;
        RECT  31.68 107.916 31.704 108 ;
    END
  END cwo_d[23]
  PIN cwo_d[240]
    DIRECTION OUTPUT ;
    USE SIGNAL ;
    PORT
      LAYER M5 ;
        RECT  18.048 107.916 18.072 108 ;
    END
  END cwo_d[240]
  PIN cwo_d[241]
    DIRECTION OUTPUT ;
    USE SIGNAL ;
    PORT
      LAYER M5 ;
        RECT  18.24 107.916 18.264 108 ;
    END
  END cwo_d[241]
  PIN cwo_d[242]
    DIRECTION OUTPUT ;
    USE SIGNAL ;
    PORT
      LAYER M5 ;
        RECT  18.432 107.916 18.456 108 ;
    END
  END cwo_d[242]
  PIN cwo_d[243]
    DIRECTION OUTPUT ;
    USE SIGNAL ;
    PORT
      LAYER M5 ;
        RECT  18.624 107.916 18.648 108 ;
    END
  END cwo_d[243]
  PIN cwo_d[244]
    DIRECTION OUTPUT ;
    USE SIGNAL ;
    PORT
      LAYER M5 ;
        RECT  18.816 107.916 18.84 108 ;
    END
  END cwo_d[244]
  PIN cwo_d[245]
    DIRECTION OUTPUT ;
    USE SIGNAL ;
    PORT
      LAYER M5 ;
        RECT  19.008 107.916 19.032 108 ;
    END
  END cwo_d[245]
  PIN cwo_d[246]
    DIRECTION OUTPUT ;
    USE SIGNAL ;
    PORT
      LAYER M5 ;
        RECT  37.632 107.916 37.656 108 ;
    END
  END cwo_d[246]
  PIN cwo_d[247]
    DIRECTION OUTPUT ;
    USE SIGNAL ;
    PORT
      LAYER M5 ;
        RECT  37.824 107.916 37.848 108 ;
    END
  END cwo_d[247]
  PIN cwo_d[248]
    DIRECTION OUTPUT ;
    USE SIGNAL ;
    PORT
      LAYER M5 ;
        RECT  38.016 107.916 38.04 108 ;
    END
  END cwo_d[248]
  PIN cwo_d[249]
    DIRECTION OUTPUT ;
    USE SIGNAL ;
    PORT
      LAYER M5 ;
        RECT  38.208 107.916 38.232 108 ;
    END
  END cwo_d[249]
  PIN cwo_d[24]
    DIRECTION OUTPUT ;
    USE SIGNAL ;
    PORT
      LAYER M5 ;
        RECT  31.872 107.916 31.896 108 ;
    END
  END cwo_d[24]
  PIN cwo_d[250]
    DIRECTION OUTPUT ;
    USE SIGNAL ;
    PORT
      LAYER M5 ;
        RECT  38.4 107.916 38.424 108 ;
    END
  END cwo_d[250]
  PIN cwo_d[251]
    DIRECTION OUTPUT ;
    USE SIGNAL ;
    PORT
      LAYER M5 ;
        RECT  38.592 107.916 38.616 108 ;
    END
  END cwo_d[251]
  PIN cwo_d[252]
    DIRECTION OUTPUT ;
    USE SIGNAL ;
    PORT
      LAYER M5 ;
        RECT  38.784 107.916 38.808 108 ;
    END
  END cwo_d[252]
  PIN cwo_d[253]
    DIRECTION OUTPUT ;
    USE SIGNAL ;
    PORT
      LAYER M5 ;
        RECT  38.976 107.916 39 108 ;
    END
  END cwo_d[253]
  PIN cwo_d[254]
    DIRECTION OUTPUT ;
    USE SIGNAL ;
    PORT
      LAYER M5 ;
        RECT  39.168 107.916 39.192 108 ;
    END
  END cwo_d[254]
  PIN cwo_d[255]
    DIRECTION OUTPUT ;
    USE SIGNAL ;
    PORT
      LAYER M5 ;
        RECT  39.36 107.916 39.384 108 ;
    END
  END cwo_d[255]
  PIN cwo_d[25]
    DIRECTION OUTPUT ;
    USE SIGNAL ;
    PORT
      LAYER M5 ;
        RECT  32.064 107.916 32.088 108 ;
    END
  END cwo_d[25]
  PIN cwo_d[26]
    DIRECTION OUTPUT ;
    USE SIGNAL ;
    PORT
      LAYER M5 ;
        RECT  32.256 107.916 32.28 108 ;
    END
  END cwo_d[26]
  PIN cwo_d[27]
    DIRECTION OUTPUT ;
    USE SIGNAL ;
    PORT
      LAYER M5 ;
        RECT  32.448 107.916 32.472 108 ;
    END
  END cwo_d[27]
  PIN cwo_d[28]
    DIRECTION OUTPUT ;
    USE SIGNAL ;
    PORT
      LAYER M5 ;
        RECT  32.64 107.916 32.664 108 ;
    END
  END cwo_d[28]
  PIN cwo_d[29]
    DIRECTION OUTPUT ;
    USE SIGNAL ;
    PORT
      LAYER M5 ;
        RECT  32.832 107.916 32.856 108 ;
    END
  END cwo_d[29]
  PIN cwo_d[2]
    DIRECTION OUTPUT ;
    USE SIGNAL ;
    PORT
      LAYER M5 ;
        RECT  60.48 107.916 60.504 108 ;
    END
  END cwo_d[2]
  PIN cwo_d[30]
    DIRECTION OUTPUT ;
    USE SIGNAL ;
    PORT
      LAYER M5 ;
        RECT  33.024 107.916 33.048 108 ;
    END
  END cwo_d[30]
  PIN cwo_d[31]
    DIRECTION OUTPUT ;
    USE SIGNAL ;
    PORT
      LAYER M5 ;
        RECT  33.216 107.916 33.24 108 ;
    END
  END cwo_d[31]
  PIN cwo_d[32]
    DIRECTION OUTPUT ;
    USE SIGNAL ;
    PORT
      LAYER M5 ;
        RECT  33.408 107.916 33.432 108 ;
    END
  END cwo_d[32]
  PIN cwo_d[33]
    DIRECTION OUTPUT ;
    USE SIGNAL ;
    PORT
      LAYER M5 ;
        RECT  33.6 107.916 33.624 108 ;
    END
  END cwo_d[33]
  PIN cwo_d[34]
    DIRECTION OUTPUT ;
    USE SIGNAL ;
    PORT
      LAYER M5 ;
        RECT  33.792 107.916 33.816 108 ;
    END
  END cwo_d[34]
  PIN cwo_d[35]
    DIRECTION OUTPUT ;
    USE SIGNAL ;
    PORT
      LAYER M5 ;
        RECT  33.984 107.916 34.008 108 ;
    END
  END cwo_d[35]
  PIN cwo_d[36]
    DIRECTION OUTPUT ;
    USE SIGNAL ;
    PORT
      LAYER M5 ;
        RECT  34.176 107.916 34.2 108 ;
    END
  END cwo_d[36]
  PIN cwo_d[37]
    DIRECTION OUTPUT ;
    USE SIGNAL ;
    PORT
      LAYER M5 ;
        RECT  34.368 107.916 34.392 108 ;
    END
  END cwo_d[37]
  PIN cwo_d[38]
    DIRECTION OUTPUT ;
    USE SIGNAL ;
    PORT
      LAYER M5 ;
        RECT  34.56 107.916 34.584 108 ;
    END
  END cwo_d[38]
  PIN cwo_d[39]
    DIRECTION OUTPUT ;
    USE SIGNAL ;
    PORT
      LAYER M5 ;
        RECT  34.752 107.916 34.776 108 ;
    END
  END cwo_d[39]
  PIN cwo_d[3]
    DIRECTION OUTPUT ;
    USE SIGNAL ;
    PORT
      LAYER M5 ;
        RECT  60.672 107.916 60.696 108 ;
    END
  END cwo_d[3]
  PIN cwo_d[40]
    DIRECTION OUTPUT ;
    USE SIGNAL ;
    PORT
      LAYER M5 ;
        RECT  34.944 107.916 34.968 108 ;
    END
  END cwo_d[40]
  PIN cwo_d[41]
    DIRECTION OUTPUT ;
    USE SIGNAL ;
    PORT
      LAYER M5 ;
        RECT  35.136 107.916 35.16 108 ;
    END
  END cwo_d[41]
  PIN cwo_d[42]
    DIRECTION OUTPUT ;
    USE SIGNAL ;
    PORT
      LAYER M5 ;
        RECT  35.328 107.916 35.352 108 ;
    END
  END cwo_d[42]
  PIN cwo_d[43]
    DIRECTION OUTPUT ;
    USE SIGNAL ;
    PORT
      LAYER M5 ;
        RECT  35.52 107.916 35.544 108 ;
    END
  END cwo_d[43]
  PIN cwo_d[44]
    DIRECTION OUTPUT ;
    USE SIGNAL ;
    PORT
      LAYER M5 ;
        RECT  35.712 107.916 35.736 108 ;
    END
  END cwo_d[44]
  PIN cwo_d[45]
    DIRECTION OUTPUT ;
    USE SIGNAL ;
    PORT
      LAYER M5 ;
        RECT  35.904 107.916 35.928 108 ;
    END
  END cwo_d[45]
  PIN cwo_d[46]
    DIRECTION OUTPUT ;
    USE SIGNAL ;
    PORT
      LAYER M5 ;
        RECT  36.096 107.916 36.12 108 ;
    END
  END cwo_d[46]
  PIN cwo_d[47]
    DIRECTION OUTPUT ;
    USE SIGNAL ;
    PORT
      LAYER M5 ;
        RECT  36.288 107.916 36.312 108 ;
    END
  END cwo_d[47]
  PIN cwo_d[48]
    DIRECTION OUTPUT ;
    USE SIGNAL ;
    PORT
      LAYER M5 ;
        RECT  36.48 107.916 36.504 108 ;
    END
  END cwo_d[48]
  PIN cwo_d[49]
    DIRECTION OUTPUT ;
    USE SIGNAL ;
    PORT
      LAYER M5 ;
        RECT  36.672 107.916 36.696 108 ;
    END
  END cwo_d[49]
  PIN cwo_d[4]
    DIRECTION OUTPUT ;
    USE SIGNAL ;
    PORT
      LAYER M5 ;
        RECT  60.864 107.916 60.888 108 ;
    END
  END cwo_d[4]
  PIN cwo_d[50]
    DIRECTION OUTPUT ;
    USE SIGNAL ;
    PORT
      LAYER M5 ;
        RECT  36.864 107.916 36.888 108 ;
    END
  END cwo_d[50]
  PIN cwo_d[51]
    DIRECTION OUTPUT ;
    USE SIGNAL ;
    PORT
      LAYER M5 ;
        RECT  37.056 107.916 37.08 108 ;
    END
  END cwo_d[51]
  PIN cwo_d[52]
    DIRECTION OUTPUT ;
    USE SIGNAL ;
    PORT
      LAYER M5 ;
        RECT  37.248 107.916 37.272 108 ;
    END
  END cwo_d[52]
  PIN cwo_d[53]
    DIRECTION OUTPUT ;
    USE SIGNAL ;
    PORT
      LAYER M5 ;
        RECT  37.44 107.916 37.464 108 ;
    END
  END cwo_d[53]
  PIN cwo_d[54]
    DIRECTION OUTPUT ;
    USE SIGNAL ;
    PORT
      LAYER M5 ;
        RECT  6.912 107.916 6.936 108 ;
    END
  END cwo_d[54]
  PIN cwo_d[55]
    DIRECTION OUTPUT ;
    USE SIGNAL ;
    PORT
      LAYER M5 ;
        RECT  7.104 107.916 7.128 108 ;
    END
  END cwo_d[55]
  PIN cwo_d[56]
    DIRECTION OUTPUT ;
    USE SIGNAL ;
    PORT
      LAYER M5 ;
        RECT  7.296 107.916 7.32 108 ;
    END
  END cwo_d[56]
  PIN cwo_d[57]
    DIRECTION OUTPUT ;
    USE SIGNAL ;
    PORT
      LAYER M5 ;
        RECT  7.488 107.916 7.512 108 ;
    END
  END cwo_d[57]
  PIN cwo_d[58]
    DIRECTION OUTPUT ;
    USE SIGNAL ;
    PORT
      LAYER M5 ;
        RECT  7.68 107.916 7.704 108 ;
    END
  END cwo_d[58]
  PIN cwo_d[59]
    DIRECTION OUTPUT ;
    USE SIGNAL ;
    PORT
      LAYER M5 ;
        RECT  7.872 107.916 7.896 108 ;
    END
  END cwo_d[59]
  PIN cwo_d[5]
    DIRECTION OUTPUT ;
    USE SIGNAL ;
    PORT
      LAYER M5 ;
        RECT  61.056 107.916 61.08 108 ;
    END
  END cwo_d[5]
  PIN cwo_d[60]
    DIRECTION OUTPUT ;
    USE SIGNAL ;
    PORT
      LAYER M5 ;
        RECT  8.064 107.916 8.088 108 ;
    END
  END cwo_d[60]
  PIN cwo_d[61]
    DIRECTION OUTPUT ;
    USE SIGNAL ;
    PORT
      LAYER M5 ;
        RECT  8.256 107.916 8.28 108 ;
    END
  END cwo_d[61]
  PIN cwo_d[62]
    DIRECTION OUTPUT ;
    USE SIGNAL ;
    PORT
      LAYER M5 ;
        RECT  8.448 107.916 8.472 108 ;
    END
  END cwo_d[62]
  PIN cwo_d[63]
    DIRECTION OUTPUT ;
    USE SIGNAL ;
    PORT
      LAYER M5 ;
        RECT  8.64 107.916 8.664 108 ;
    END
  END cwo_d[63]
  PIN cwo_d[64]
    DIRECTION OUTPUT ;
    USE SIGNAL ;
    PORT
      LAYER M5 ;
        RECT  8.832 107.916 8.856 108 ;
    END
  END cwo_d[64]
  PIN cwo_d[65]
    DIRECTION OUTPUT ;
    USE SIGNAL ;
    PORT
      LAYER M5 ;
        RECT  9.024 107.916 9.048 108 ;
    END
  END cwo_d[65]
  PIN cwo_d[66]
    DIRECTION OUTPUT ;
    USE SIGNAL ;
    PORT
      LAYER M5 ;
        RECT  9.216 107.916 9.24 108 ;
    END
  END cwo_d[66]
  PIN cwo_d[67]
    DIRECTION OUTPUT ;
    USE SIGNAL ;
    PORT
      LAYER M5 ;
        RECT  9.408 107.916 9.432 108 ;
    END
  END cwo_d[67]
  PIN cwo_d[68]
    DIRECTION OUTPUT ;
    USE SIGNAL ;
    PORT
      LAYER M5 ;
        RECT  9.6 107.916 9.624 108 ;
    END
  END cwo_d[68]
  PIN cwo_d[69]
    DIRECTION OUTPUT ;
    USE SIGNAL ;
    PORT
      LAYER M5 ;
        RECT  9.792 107.916 9.816 108 ;
    END
  END cwo_d[69]
  PIN cwo_d[6]
    DIRECTION OUTPUT ;
    USE SIGNAL ;
    PORT
      LAYER M5 ;
        RECT  61.248 107.916 61.272 108 ;
    END
  END cwo_d[6]
  PIN cwo_d[70]
    DIRECTION OUTPUT ;
    USE SIGNAL ;
    PORT
      LAYER M5 ;
        RECT  9.984 107.916 10.008 108 ;
    END
  END cwo_d[70]
  PIN cwo_d[71]
    DIRECTION OUTPUT ;
    USE SIGNAL ;
    PORT
      LAYER M5 ;
        RECT  10.176 107.916 10.2 108 ;
    END
  END cwo_d[71]
  PIN cwo_d[72]
    DIRECTION OUTPUT ;
    USE SIGNAL ;
    PORT
      LAYER M5 ;
        RECT  10.368 107.916 10.392 108 ;
    END
  END cwo_d[72]
  PIN cwo_d[73]
    DIRECTION OUTPUT ;
    USE SIGNAL ;
    PORT
      LAYER M5 ;
        RECT  10.56 107.916 10.584 108 ;
    END
  END cwo_d[73]
  PIN cwo_d[74]
    DIRECTION OUTPUT ;
    USE SIGNAL ;
    PORT
      LAYER M5 ;
        RECT  10.752 107.916 10.776 108 ;
    END
  END cwo_d[74]
  PIN cwo_d[75]
    DIRECTION OUTPUT ;
    USE SIGNAL ;
    PORT
      LAYER M5 ;
        RECT  10.944 107.916 10.968 108 ;
    END
  END cwo_d[75]
  PIN cwo_d[76]
    DIRECTION OUTPUT ;
    USE SIGNAL ;
    PORT
      LAYER M5 ;
        RECT  11.136 107.916 11.16 108 ;
    END
  END cwo_d[76]
  PIN cwo_d[77]
    DIRECTION OUTPUT ;
    USE SIGNAL ;
    PORT
      LAYER M5 ;
        RECT  11.328 107.916 11.352 108 ;
    END
  END cwo_d[77]
  PIN cwo_d[78]
    DIRECTION OUTPUT ;
    USE SIGNAL ;
    PORT
      LAYER M5 ;
        RECT  11.52 107.916 11.544 108 ;
    END
  END cwo_d[78]
  PIN cwo_d[79]
    DIRECTION OUTPUT ;
    USE SIGNAL ;
    PORT
      LAYER M5 ;
        RECT  11.712 107.916 11.736 108 ;
    END
  END cwo_d[79]
  PIN cwo_d[7]
    DIRECTION OUTPUT ;
    USE SIGNAL ;
    PORT
      LAYER M5 ;
        RECT  61.44 107.916 61.464 108 ;
    END
  END cwo_d[7]
  PIN cwo_d[80]
    DIRECTION OUTPUT ;
    USE SIGNAL ;
    PORT
      LAYER M5 ;
        RECT  11.904 107.916 11.928 108 ;
    END
  END cwo_d[80]
  PIN cwo_d[81]
    DIRECTION OUTPUT ;
    USE SIGNAL ;
    PORT
      LAYER M5 ;
        RECT  12.096 107.916 12.12 108 ;
    END
  END cwo_d[81]
  PIN cwo_d[82]
    DIRECTION OUTPUT ;
    USE SIGNAL ;
    PORT
      LAYER M5 ;
        RECT  12.288 107.916 12.312 108 ;
    END
  END cwo_d[82]
  PIN cwo_d[83]
    DIRECTION OUTPUT ;
    USE SIGNAL ;
    PORT
      LAYER M5 ;
        RECT  12.48 107.916 12.504 108 ;
    END
  END cwo_d[83]
  PIN cwo_d[84]
    DIRECTION OUTPUT ;
    USE SIGNAL ;
    PORT
      LAYER M5 ;
        RECT  12.672 107.916 12.696 108 ;
    END
  END cwo_d[84]
  PIN cwo_d[85]
    DIRECTION OUTPUT ;
    USE SIGNAL ;
    PORT
      LAYER M5 ;
        RECT  12.864 107.916 12.888 108 ;
    END
  END cwo_d[85]
  PIN cwo_d[86]
    DIRECTION OUTPUT ;
    USE SIGNAL ;
    PORT
      LAYER M5 ;
        RECT  64.32 107.916 64.344 108 ;
    END
  END cwo_d[86]
  PIN cwo_d[87]
    DIRECTION OUTPUT ;
    USE SIGNAL ;
    PORT
      LAYER M5 ;
        RECT  64.512 107.916 64.536 108 ;
    END
  END cwo_d[87]
  PIN cwo_d[88]
    DIRECTION OUTPUT ;
    USE SIGNAL ;
    PORT
      LAYER M5 ;
        RECT  64.704 107.916 64.728 108 ;
    END
  END cwo_d[88]
  PIN cwo_d[89]
    DIRECTION OUTPUT ;
    USE SIGNAL ;
    PORT
      LAYER M5 ;
        RECT  64.896 107.916 64.92 108 ;
    END
  END cwo_d[89]
  PIN cwo_d[8]
    DIRECTION OUTPUT ;
    USE SIGNAL ;
    PORT
      LAYER M5 ;
        RECT  61.632 107.916 61.656 108 ;
    END
  END cwo_d[8]
  PIN cwo_d[90]
    DIRECTION OUTPUT ;
    USE SIGNAL ;
    PORT
      LAYER M5 ;
        RECT  65.088 107.916 65.112 108 ;
    END
  END cwo_d[90]
  PIN cwo_d[91]
    DIRECTION OUTPUT ;
    USE SIGNAL ;
    PORT
      LAYER M5 ;
        RECT  65.28 107.916 65.304 108 ;
    END
  END cwo_d[91]
  PIN cwo_d[92]
    DIRECTION OUTPUT ;
    USE SIGNAL ;
    PORT
      LAYER M5 ;
        RECT  65.472 107.916 65.496 108 ;
    END
  END cwo_d[92]
  PIN cwo_d[93]
    DIRECTION OUTPUT ;
    USE SIGNAL ;
    PORT
      LAYER M5 ;
        RECT  65.664 107.916 65.688 108 ;
    END
  END cwo_d[93]
  PIN cwo_d[94]
    DIRECTION OUTPUT ;
    USE SIGNAL ;
    PORT
      LAYER M5 ;
        RECT  65.856 107.916 65.88 108 ;
    END
  END cwo_d[94]
  PIN cwo_d[95]
    DIRECTION OUTPUT ;
    USE SIGNAL ;
    PORT
      LAYER M5 ;
        RECT  66.048 107.916 66.072 108 ;
    END
  END cwo_d[95]
  PIN cwo_d[96]
    DIRECTION OUTPUT ;
    USE SIGNAL ;
    PORT
      LAYER M5 ;
        RECT  66.24 107.916 66.264 108 ;
    END
  END cwo_d[96]
  PIN cwo_d[97]
    DIRECTION OUTPUT ;
    USE SIGNAL ;
    PORT
      LAYER M5 ;
        RECT  66.432 107.916 66.456 108 ;
    END
  END cwo_d[97]
  PIN cwo_d[98]
    DIRECTION OUTPUT ;
    USE SIGNAL ;
    PORT
      LAYER M5 ;
        RECT  66.624 107.916 66.648 108 ;
    END
  END cwo_d[98]
  PIN cwo_d[99]
    DIRECTION OUTPUT ;
    USE SIGNAL ;
    PORT
      LAYER M5 ;
        RECT  66.816 107.916 66.84 108 ;
    END
  END cwo_d[99]
  PIN cwo_d[9]
    DIRECTION OUTPUT ;
    USE SIGNAL ;
    PORT
      LAYER M5 ;
        RECT  61.824 107.916 61.848 108 ;
    END
  END cwo_d[9]
  PIN cwo_v
    DIRECTION OUTPUT ;
    USE SIGNAL ;
    PORT
      LAYER M5 ;
        RECT  39.552 107.916 39.576 108 ;
    END
  END cwo_v
  PIN eps_c[0]
    DIRECTION OUTPUT ;
    USE SIGNAL ;
    PORT
      LAYER M4 ;
        RECT  302.316 51.36 302.4 51.384 ;
    END
  END eps_c[0]
  PIN eps_c[10]
    DIRECTION OUTPUT ;
    USE SIGNAL ;
    PORT
      LAYER M4 ;
        RECT  302.316 53.28 302.4 53.304 ;
    END
  END eps_c[10]
  PIN eps_c[11]
    DIRECTION OUTPUT ;
    USE SIGNAL ;
    PORT
      LAYER M4 ;
        RECT  302.316 53.472 302.4 53.496 ;
    END
  END eps_c[11]
  PIN eps_c[12]
    DIRECTION OUTPUT ;
    USE SIGNAL ;
    PORT
      LAYER M4 ;
        RECT  302.316 53.664 302.4 53.688 ;
    END
  END eps_c[12]
  PIN eps_c[13]
    DIRECTION OUTPUT ;
    USE SIGNAL ;
    PORT
      LAYER M4 ;
        RECT  302.316 53.856 302.4 53.88 ;
    END
  END eps_c[13]
  PIN eps_c[14]
    DIRECTION OUTPUT ;
    USE SIGNAL ;
    PORT
      LAYER M4 ;
        RECT  302.316 54.048 302.4 54.072 ;
    END
  END eps_c[14]
  PIN eps_c[15]
    DIRECTION OUTPUT ;
    USE SIGNAL ;
    PORT
      LAYER M4 ;
        RECT  302.316 54.24 302.4 54.264 ;
    END
  END eps_c[15]
  PIN eps_c[16]
    DIRECTION OUTPUT ;
    USE SIGNAL ;
    PORT
      LAYER M4 ;
        RECT  302.316 54.432 302.4 54.456 ;
    END
  END eps_c[16]
  PIN eps_c[17]
    DIRECTION OUTPUT ;
    USE SIGNAL ;
    PORT
      LAYER M4 ;
        RECT  302.316 54.624 302.4 54.648 ;
    END
  END eps_c[17]
  PIN eps_c[18]
    DIRECTION OUTPUT ;
    USE SIGNAL ;
    PORT
      LAYER M4 ;
        RECT  302.316 54.816 302.4 54.84 ;
    END
  END eps_c[18]
  PIN eps_c[19]
    DIRECTION OUTPUT ;
    USE SIGNAL ;
    PORT
      LAYER M4 ;
        RECT  302.316 55.008 302.4 55.032 ;
    END
  END eps_c[19]
  PIN eps_c[1]
    DIRECTION OUTPUT ;
    USE SIGNAL ;
    PORT
      LAYER M4 ;
        RECT  302.316 51.552 302.4 51.576 ;
    END
  END eps_c[1]
  PIN eps_c[20]
    DIRECTION OUTPUT ;
    USE SIGNAL ;
    PORT
      LAYER M4 ;
        RECT  302.316 55.2 302.4 55.224 ;
    END
  END eps_c[20]
  PIN eps_c[21]
    DIRECTION OUTPUT ;
    USE SIGNAL ;
    PORT
      LAYER M4 ;
        RECT  302.316 55.392 302.4 55.416 ;
    END
  END eps_c[21]
  PIN eps_c[22]
    DIRECTION OUTPUT ;
    USE SIGNAL ;
    PORT
      LAYER M4 ;
        RECT  302.316 55.584 302.4 55.608 ;
    END
  END eps_c[22]
  PIN eps_c[23]
    DIRECTION OUTPUT ;
    USE SIGNAL ;
    PORT
      LAYER M4 ;
        RECT  302.316 55.776 302.4 55.8 ;
    END
  END eps_c[23]
  PIN eps_c[24]
    DIRECTION OUTPUT ;
    USE SIGNAL ;
    PORT
      LAYER M4 ;
        RECT  302.316 55.968 302.4 55.992 ;
    END
  END eps_c[24]
  PIN eps_c[25]
    DIRECTION OUTPUT ;
    USE SIGNAL ;
    PORT
      LAYER M4 ;
        RECT  302.316 56.16 302.4 56.184 ;
    END
  END eps_c[25]
  PIN eps_c[26]
    DIRECTION OUTPUT ;
    USE SIGNAL ;
    PORT
      LAYER M4 ;
        RECT  302.316 56.352 302.4 56.376 ;
    END
  END eps_c[26]
  PIN eps_c[27]
    DIRECTION OUTPUT ;
    USE SIGNAL ;
    PORT
      LAYER M4 ;
        RECT  302.316 56.544 302.4 56.568 ;
    END
  END eps_c[27]
  PIN eps_c[28]
    DIRECTION OUTPUT ;
    USE SIGNAL ;
    PORT
      LAYER M4 ;
        RECT  302.316 56.736 302.4 56.76 ;
    END
  END eps_c[28]
  PIN eps_c[29]
    DIRECTION OUTPUT ;
    USE SIGNAL ;
    PORT
      LAYER M4 ;
        RECT  302.316 56.928 302.4 56.952 ;
    END
  END eps_c[29]
  PIN eps_c[2]
    DIRECTION OUTPUT ;
    USE SIGNAL ;
    PORT
      LAYER M4 ;
        RECT  302.316 51.744 302.4 51.768 ;
    END
  END eps_c[2]
  PIN eps_c[30]
    DIRECTION OUTPUT ;
    USE SIGNAL ;
    PORT
      LAYER M4 ;
        RECT  302.316 57.12 302.4 57.144 ;
    END
  END eps_c[30]
  PIN eps_c[31]
    DIRECTION OUTPUT ;
    USE SIGNAL ;
    PORT
      LAYER M4 ;
        RECT  302.316 57.312 302.4 57.336 ;
    END
  END eps_c[31]
  PIN eps_c[3]
    DIRECTION OUTPUT ;
    USE SIGNAL ;
    PORT
      LAYER M4 ;
        RECT  302.316 51.936 302.4 51.96 ;
    END
  END eps_c[3]
  PIN eps_c[4]
    DIRECTION OUTPUT ;
    USE SIGNAL ;
    PORT
      LAYER M4 ;
        RECT  302.316 52.128 302.4 52.152 ;
    END
  END eps_c[4]
  PIN eps_c[5]
    DIRECTION OUTPUT ;
    USE SIGNAL ;
    PORT
      LAYER M4 ;
        RECT  302.316 52.32 302.4 52.344 ;
    END
  END eps_c[5]
  PIN eps_c[6]
    DIRECTION OUTPUT ;
    USE SIGNAL ;
    PORT
      LAYER M4 ;
        RECT  302.316 52.512 302.4 52.536 ;
    END
  END eps_c[6]
  PIN eps_c[7]
    DIRECTION OUTPUT ;
    USE SIGNAL ;
    PORT
      LAYER M4 ;
        RECT  302.316 52.704 302.4 52.728 ;
    END
  END eps_c[7]
  PIN eps_c[8]
    DIRECTION OUTPUT ;
    USE SIGNAL ;
    PORT
      LAYER M4 ;
        RECT  302.316 52.896 302.4 52.92 ;
    END
  END eps_c[8]
  PIN eps_c[9]
    DIRECTION OUTPUT ;
    USE SIGNAL ;
    PORT
      LAYER M4 ;
        RECT  302.316 53.088 302.4 53.112 ;
    END
  END eps_c[9]
  PIN f5
    DIRECTION INPUT ;
    USE SIGNAL ;
    PORT
      LAYER M5 ;
        RECT  39.744 107.916 39.768 108 ;
    END
  END f5
  PIN fault
    DIRECTION OUTPUT ;
    USE SIGNAL ;
    PORT
      LAYER M5 ;
        RECT  106.752 0 106.776 0.084 ;
    END
  END fault
  PIN g_acc[0]
    DIRECTION INPUT ;
    USE SIGNAL ;
    PORT
      LAYER M5 ;
        RECT  106.944 0 106.968 0.084 ;
    END
  END g_acc[0]
  PIN g_acc[1]
    DIRECTION INPUT ;
    USE SIGNAL ;
    PORT
      LAYER M5 ;
        RECT  107.136 0 107.16 0.084 ;
    END
  END g_acc[1]
  PIN g_acc[2]
    DIRECTION INPUT ;
    USE SIGNAL ;
    PORT
      LAYER M5 ;
        RECT  107.328 0 107.352 0.084 ;
    END
  END g_acc[2]
  PIN g_acc[3]
    DIRECTION INPUT ;
    USE SIGNAL ;
    PORT
      LAYER M5 ;
        RECT  107.52 0 107.544 0.084 ;
    END
  END g_acc[3]
  PIN g_acc[4]
    DIRECTION INPUT ;
    USE SIGNAL ;
    PORT
      LAYER M5 ;
        RECT  107.712 0 107.736 0.084 ;
    END
  END g_acc[4]
  PIN g_d[0]
    DIRECTION INPUT ;
    USE SIGNAL ;
    PORT
      LAYER M5 ;
        RECT  107.904 0 107.928 0.084 ;
    END
  END g_d[0]
  PIN g_d[100]
    DIRECTION INPUT ;
    USE SIGNAL ;
    PORT
      LAYER M5 ;
        RECT  53.376 0 53.4 0.084 ;
    END
  END g_d[100]
  PIN g_d[101]
    DIRECTION INPUT ;
    USE SIGNAL ;
    PORT
      LAYER M5 ;
        RECT  53.568 0 53.592 0.084 ;
    END
  END g_d[101]
  PIN g_d[102]
    DIRECTION INPUT ;
    USE SIGNAL ;
    PORT
      LAYER M5 ;
        RECT  53.76 0 53.784 0.084 ;
    END
  END g_d[102]
  PIN g_d[103]
    DIRECTION INPUT ;
    USE SIGNAL ;
    PORT
      LAYER M5 ;
        RECT  53.952 0 53.976 0.084 ;
    END
  END g_d[103]
  PIN g_d[104]
    DIRECTION INPUT ;
    USE SIGNAL ;
    PORT
      LAYER M5 ;
        RECT  54.144 0 54.168 0.084 ;
    END
  END g_d[104]
  PIN g_d[105]
    DIRECTION INPUT ;
    USE SIGNAL ;
    PORT
      LAYER M5 ;
        RECT  54.336 0 54.36 0.084 ;
    END
  END g_d[105]
  PIN g_d[106]
    DIRECTION INPUT ;
    USE SIGNAL ;
    PORT
      LAYER M5 ;
        RECT  54.528 0 54.552 0.084 ;
    END
  END g_d[106]
  PIN g_d[107]
    DIRECTION INPUT ;
    USE SIGNAL ;
    PORT
      LAYER M5 ;
        RECT  54.72 0 54.744 0.084 ;
    END
  END g_d[107]
  PIN g_d[108]
    DIRECTION INPUT ;
    USE SIGNAL ;
    PORT
      LAYER M5 ;
        RECT  54.912 0 54.936 0.084 ;
    END
  END g_d[108]
  PIN g_d[109]
    DIRECTION INPUT ;
    USE SIGNAL ;
    PORT
      LAYER M5 ;
        RECT  55.104 0 55.128 0.084 ;
    END
  END g_d[109]
  PIN g_d[10]
    DIRECTION INPUT ;
    USE SIGNAL ;
    PORT
      LAYER M5 ;
        RECT  109.824 0 109.848 0.084 ;
    END
  END g_d[10]
  PIN g_d[110]
    DIRECTION INPUT ;
    USE SIGNAL ;
    PORT
      LAYER M5 ;
        RECT  55.296 0 55.32 0.084 ;
    END
  END g_d[110]
  PIN g_d[111]
    DIRECTION INPUT ;
    USE SIGNAL ;
    PORT
      LAYER M5 ;
        RECT  55.488 0 55.512 0.084 ;
    END
  END g_d[111]
  PIN g_d[112]
    DIRECTION INPUT ;
    USE SIGNAL ;
    PORT
      LAYER M5 ;
        RECT  55.68 0 55.704 0.084 ;
    END
  END g_d[112]
  PIN g_d[113]
    DIRECTION INPUT ;
    USE SIGNAL ;
    PORT
      LAYER M5 ;
        RECT  55.872 0 55.896 0.084 ;
    END
  END g_d[113]
  PIN g_d[114]
    DIRECTION INPUT ;
    USE SIGNAL ;
    PORT
      LAYER M5 ;
        RECT  56.064 0 56.088 0.084 ;
    END
  END g_d[114]
  PIN g_d[115]
    DIRECTION INPUT ;
    USE SIGNAL ;
    PORT
      LAYER M5 ;
        RECT  56.256 0 56.28 0.084 ;
    END
  END g_d[115]
  PIN g_d[116]
    DIRECTION INPUT ;
    USE SIGNAL ;
    PORT
      LAYER M5 ;
        RECT  56.448 0 56.472 0.084 ;
    END
  END g_d[116]
  PIN g_d[117]
    DIRECTION INPUT ;
    USE SIGNAL ;
    PORT
      LAYER M5 ;
        RECT  56.64 0 56.664 0.084 ;
    END
  END g_d[117]
  PIN g_d[118]
    DIRECTION INPUT ;
    USE SIGNAL ;
    PORT
      LAYER M5 ;
        RECT  56.832 0 56.856 0.084 ;
    END
  END g_d[118]
  PIN g_d[119]
    DIRECTION INPUT ;
    USE SIGNAL ;
    PORT
      LAYER M5 ;
        RECT  57.024 0 57.048 0.084 ;
    END
  END g_d[119]
  PIN g_d[11]
    DIRECTION INPUT ;
    USE SIGNAL ;
    PORT
      LAYER M5 ;
        RECT  110.016 0 110.04 0.084 ;
    END
  END g_d[11]
  PIN g_d[120]
    DIRECTION INPUT ;
    USE SIGNAL ;
    PORT
      LAYER M5 ;
        RECT  57.216 0 57.24 0.084 ;
    END
  END g_d[120]
  PIN g_d[121]
    DIRECTION INPUT ;
    USE SIGNAL ;
    PORT
      LAYER M5 ;
        RECT  57.408 0 57.432 0.084 ;
    END
  END g_d[121]
  PIN g_d[122]
    DIRECTION INPUT ;
    USE SIGNAL ;
    PORT
      LAYER M5 ;
        RECT  57.6 0 57.624 0.084 ;
    END
  END g_d[122]
  PIN g_d[123]
    DIRECTION INPUT ;
    USE SIGNAL ;
    PORT
      LAYER M5 ;
        RECT  57.792 0 57.816 0.084 ;
    END
  END g_d[123]
  PIN g_d[124]
    DIRECTION INPUT ;
    USE SIGNAL ;
    PORT
      LAYER M5 ;
        RECT  57.984 0 58.008 0.084 ;
    END
  END g_d[124]
  PIN g_d[125]
    DIRECTION INPUT ;
    USE SIGNAL ;
    PORT
      LAYER M5 ;
        RECT  58.176 0 58.2 0.084 ;
    END
  END g_d[125]
  PIN g_d[126]
    DIRECTION INPUT ;
    USE SIGNAL ;
    PORT
      LAYER M5 ;
        RECT  58.368 0 58.392 0.084 ;
    END
  END g_d[126]
  PIN g_d[127]
    DIRECTION INPUT ;
    USE SIGNAL ;
    PORT
      LAYER M5 ;
        RECT  58.56 0 58.584 0.084 ;
    END
  END g_d[127]
  PIN g_d[128]
    DIRECTION INPUT ;
    USE SIGNAL ;
    PORT
      LAYER M5 ;
        RECT  58.752 0 58.776 0.084 ;
    END
  END g_d[128]
  PIN g_d[129]
    DIRECTION INPUT ;
    USE SIGNAL ;
    PORT
      LAYER M5 ;
        RECT  58.944 0 58.968 0.084 ;
    END
  END g_d[129]
  PIN g_d[12]
    DIRECTION INPUT ;
    USE SIGNAL ;
    PORT
      LAYER M5 ;
        RECT  110.208 0 110.232 0.084 ;
    END
  END g_d[12]
  PIN g_d[130]
    DIRECTION INPUT ;
    USE SIGNAL ;
    PORT
      LAYER M5 ;
        RECT  59.136 0 59.16 0.084 ;
    END
  END g_d[130]
  PIN g_d[131]
    DIRECTION INPUT ;
    USE SIGNAL ;
    PORT
      LAYER M5 ;
        RECT  59.328 0 59.352 0.084 ;
    END
  END g_d[131]
  PIN g_d[132]
    DIRECTION INPUT ;
    USE SIGNAL ;
    PORT
      LAYER M5 ;
        RECT  59.52 0 59.544 0.084 ;
    END
  END g_d[132]
  PIN g_d[133]
    DIRECTION INPUT ;
    USE SIGNAL ;
    PORT
      LAYER M5 ;
        RECT  59.712 0 59.736 0.084 ;
    END
  END g_d[133]
  PIN g_d[134]
    DIRECTION INPUT ;
    USE SIGNAL ;
    PORT
      LAYER M5 ;
        RECT  59.904 0 59.928 0.084 ;
    END
  END g_d[134]
  PIN g_d[135]
    DIRECTION INPUT ;
    USE SIGNAL ;
    PORT
      LAYER M5 ;
        RECT  60.096 0 60.12 0.084 ;
    END
  END g_d[135]
  PIN g_d[136]
    DIRECTION INPUT ;
    USE SIGNAL ;
    PORT
      LAYER M5 ;
        RECT  60.288 0 60.312 0.084 ;
    END
  END g_d[136]
  PIN g_d[137]
    DIRECTION INPUT ;
    USE SIGNAL ;
    PORT
      LAYER M5 ;
        RECT  60.48 0 60.504 0.084 ;
    END
  END g_d[137]
  PIN g_d[138]
    DIRECTION INPUT ;
    USE SIGNAL ;
    PORT
      LAYER M5 ;
        RECT  60.672 0 60.696 0.084 ;
    END
  END g_d[138]
  PIN g_d[139]
    DIRECTION INPUT ;
    USE SIGNAL ;
    PORT
      LAYER M5 ;
        RECT  60.864 0 60.888 0.084 ;
    END
  END g_d[139]
  PIN g_d[13]
    DIRECTION INPUT ;
    USE SIGNAL ;
    PORT
      LAYER M5 ;
        RECT  110.4 0 110.424 0.084 ;
    END
  END g_d[13]
  PIN g_d[140]
    DIRECTION INPUT ;
    USE SIGNAL ;
    PORT
      LAYER M5 ;
        RECT  61.056 0 61.08 0.084 ;
    END
  END g_d[140]
  PIN g_d[141]
    DIRECTION INPUT ;
    USE SIGNAL ;
    PORT
      LAYER M5 ;
        RECT  61.248 0 61.272 0.084 ;
    END
  END g_d[141]
  PIN g_d[142]
    DIRECTION INPUT ;
    USE SIGNAL ;
    PORT
      LAYER M5 ;
        RECT  61.44 0 61.464 0.084 ;
    END
  END g_d[142]
  PIN g_d[143]
    DIRECTION INPUT ;
    USE SIGNAL ;
    PORT
      LAYER M5 ;
        RECT  61.632 0 61.656 0.084 ;
    END
  END g_d[143]
  PIN g_d[144]
    DIRECTION INPUT ;
    USE SIGNAL ;
    PORT
      LAYER M5 ;
        RECT  61.824 0 61.848 0.084 ;
    END
  END g_d[144]
  PIN g_d[145]
    DIRECTION INPUT ;
    USE SIGNAL ;
    PORT
      LAYER M5 ;
        RECT  62.016 0 62.04 0.084 ;
    END
  END g_d[145]
  PIN g_d[146]
    DIRECTION INPUT ;
    USE SIGNAL ;
    PORT
      LAYER M5 ;
        RECT  62.208 0 62.232 0.084 ;
    END
  END g_d[146]
  PIN g_d[147]
    DIRECTION INPUT ;
    USE SIGNAL ;
    PORT
      LAYER M5 ;
        RECT  62.4 0 62.424 0.084 ;
    END
  END g_d[147]
  PIN g_d[148]
    DIRECTION INPUT ;
    USE SIGNAL ;
    PORT
      LAYER M5 ;
        RECT  62.592 0 62.616 0.084 ;
    END
  END g_d[148]
  PIN g_d[149]
    DIRECTION INPUT ;
    USE SIGNAL ;
    PORT
      LAYER M5 ;
        RECT  62.784 0 62.808 0.084 ;
    END
  END g_d[149]
  PIN g_d[14]
    DIRECTION INPUT ;
    USE SIGNAL ;
    PORT
      LAYER M5 ;
        RECT  110.592 0 110.616 0.084 ;
    END
  END g_d[14]
  PIN g_d[150]
    DIRECTION INPUT ;
    USE SIGNAL ;
    PORT
      LAYER M5 ;
        RECT  62.976 0 63 0.084 ;
    END
  END g_d[150]
  PIN g_d[151]
    DIRECTION INPUT ;
    USE SIGNAL ;
    PORT
      LAYER M5 ;
        RECT  63.168 0 63.192 0.084 ;
    END
  END g_d[151]
  PIN g_d[152]
    DIRECTION INPUT ;
    USE SIGNAL ;
    PORT
      LAYER M5 ;
        RECT  63.36 0 63.384 0.084 ;
    END
  END g_d[152]
  PIN g_d[153]
    DIRECTION INPUT ;
    USE SIGNAL ;
    PORT
      LAYER M5 ;
        RECT  63.552 0 63.576 0.084 ;
    END
  END g_d[153]
  PIN g_d[154]
    DIRECTION INPUT ;
    USE SIGNAL ;
    PORT
      LAYER M5 ;
        RECT  63.744 0 63.768 0.084 ;
    END
  END g_d[154]
  PIN g_d[155]
    DIRECTION INPUT ;
    USE SIGNAL ;
    PORT
      LAYER M5 ;
        RECT  63.936 0 63.96 0.084 ;
    END
  END g_d[155]
  PIN g_d[156]
    DIRECTION INPUT ;
    USE SIGNAL ;
    PORT
      LAYER M5 ;
        RECT  64.128 0 64.152 0.084 ;
    END
  END g_d[156]
  PIN g_d[157]
    DIRECTION INPUT ;
    USE SIGNAL ;
    PORT
      LAYER M5 ;
        RECT  64.32 0 64.344 0.084 ;
    END
  END g_d[157]
  PIN g_d[158]
    DIRECTION INPUT ;
    USE SIGNAL ;
    PORT
      LAYER M5 ;
        RECT  64.512 0 64.536 0.084 ;
    END
  END g_d[158]
  PIN g_d[159]
    DIRECTION INPUT ;
    USE SIGNAL ;
    PORT
      LAYER M5 ;
        RECT  64.704 0 64.728 0.084 ;
    END
  END g_d[159]
  PIN g_d[15]
    DIRECTION INPUT ;
    USE SIGNAL ;
    PORT
      LAYER M5 ;
        RECT  98.496 0 98.52 0.084 ;
    END
  END g_d[15]
  PIN g_d[160]
    DIRECTION INPUT ;
    USE SIGNAL ;
    PORT
      LAYER M5 ;
        RECT  64.896 0 64.92 0.084 ;
    END
  END g_d[160]
  PIN g_d[161]
    DIRECTION INPUT ;
    USE SIGNAL ;
    PORT
      LAYER M5 ;
        RECT  65.088 0 65.112 0.084 ;
    END
  END g_d[161]
  PIN g_d[162]
    DIRECTION INPUT ;
    USE SIGNAL ;
    PORT
      LAYER M5 ;
        RECT  65.28 0 65.304 0.084 ;
    END
  END g_d[162]
  PIN g_d[163]
    DIRECTION INPUT ;
    USE SIGNAL ;
    PORT
      LAYER M5 ;
        RECT  65.472 0 65.496 0.084 ;
    END
  END g_d[163]
  PIN g_d[164]
    DIRECTION INPUT ;
    USE SIGNAL ;
    PORT
      LAYER M5 ;
        RECT  65.664 0 65.688 0.084 ;
    END
  END g_d[164]
  PIN g_d[165]
    DIRECTION INPUT ;
    USE SIGNAL ;
    PORT
      LAYER M5 ;
        RECT  65.856 0 65.88 0.084 ;
    END
  END g_d[165]
  PIN g_d[166]
    DIRECTION INPUT ;
    USE SIGNAL ;
    PORT
      LAYER M5 ;
        RECT  66.048 0 66.072 0.084 ;
    END
  END g_d[166]
  PIN g_d[167]
    DIRECTION INPUT ;
    USE SIGNAL ;
    PORT
      LAYER M5 ;
        RECT  66.24 0 66.264 0.084 ;
    END
  END g_d[167]
  PIN g_d[168]
    DIRECTION INPUT ;
    USE SIGNAL ;
    PORT
      LAYER M5 ;
        RECT  66.432 0 66.456 0.084 ;
    END
  END g_d[168]
  PIN g_d[169]
    DIRECTION INPUT ;
    USE SIGNAL ;
    PORT
      LAYER M5 ;
        RECT  66.624 0 66.648 0.084 ;
    END
  END g_d[169]
  PIN g_d[16]
    DIRECTION INPUT ;
    USE SIGNAL ;
    PORT
      LAYER M5 ;
        RECT  98.688 0 98.712 0.084 ;
    END
  END g_d[16]
  PIN g_d[170]
    DIRECTION INPUT ;
    USE SIGNAL ;
    PORT
      LAYER M5 ;
        RECT  66.816 0 66.84 0.084 ;
    END
  END g_d[170]
  PIN g_d[171]
    DIRECTION INPUT ;
    USE SIGNAL ;
    PORT
      LAYER M5 ;
        RECT  67.008 0 67.032 0.084 ;
    END
  END g_d[171]
  PIN g_d[172]
    DIRECTION INPUT ;
    USE SIGNAL ;
    PORT
      LAYER M5 ;
        RECT  67.2 0 67.224 0.084 ;
    END
  END g_d[172]
  PIN g_d[173]
    DIRECTION INPUT ;
    USE SIGNAL ;
    PORT
      LAYER M5 ;
        RECT  67.392 0 67.416 0.084 ;
    END
  END g_d[173]
  PIN g_d[174]
    DIRECTION INPUT ;
    USE SIGNAL ;
    PORT
      LAYER M5 ;
        RECT  67.584 0 67.608 0.084 ;
    END
  END g_d[174]
  PIN g_d[175]
    DIRECTION INPUT ;
    USE SIGNAL ;
    PORT
      LAYER M5 ;
        RECT  86.208 0 86.232 0.084 ;
    END
  END g_d[175]
  PIN g_d[176]
    DIRECTION INPUT ;
    USE SIGNAL ;
    PORT
      LAYER M5 ;
        RECT  86.4 0 86.424 0.084 ;
    END
  END g_d[176]
  PIN g_d[177]
    DIRECTION INPUT ;
    USE SIGNAL ;
    PORT
      LAYER M5 ;
        RECT  86.592 0 86.616 0.084 ;
    END
  END g_d[177]
  PIN g_d[178]
    DIRECTION INPUT ;
    USE SIGNAL ;
    PORT
      LAYER M5 ;
        RECT  86.784 0 86.808 0.084 ;
    END
  END g_d[178]
  PIN g_d[179]
    DIRECTION INPUT ;
    USE SIGNAL ;
    PORT
      LAYER M5 ;
        RECT  86.976 0 87 0.084 ;
    END
  END g_d[179]
  PIN g_d[17]
    DIRECTION INPUT ;
    USE SIGNAL ;
    PORT
      LAYER M5 ;
        RECT  98.88 0 98.904 0.084 ;
    END
  END g_d[17]
  PIN g_d[180]
    DIRECTION INPUT ;
    USE SIGNAL ;
    PORT
      LAYER M5 ;
        RECT  87.168 0 87.192 0.084 ;
    END
  END g_d[180]
  PIN g_d[181]
    DIRECTION INPUT ;
    USE SIGNAL ;
    PORT
      LAYER M5 ;
        RECT  87.36 0 87.384 0.084 ;
    END
  END g_d[181]
  PIN g_d[182]
    DIRECTION INPUT ;
    USE SIGNAL ;
    PORT
      LAYER M5 ;
        RECT  87.552 0 87.576 0.084 ;
    END
  END g_d[182]
  PIN g_d[183]
    DIRECTION INPUT ;
    USE SIGNAL ;
    PORT
      LAYER M5 ;
        RECT  87.744 0 87.768 0.084 ;
    END
  END g_d[183]
  PIN g_d[184]
    DIRECTION INPUT ;
    USE SIGNAL ;
    PORT
      LAYER M5 ;
        RECT  87.936 0 87.96 0.084 ;
    END
  END g_d[184]
  PIN g_d[185]
    DIRECTION INPUT ;
    USE SIGNAL ;
    PORT
      LAYER M5 ;
        RECT  88.128 0 88.152 0.084 ;
    END
  END g_d[185]
  PIN g_d[186]
    DIRECTION INPUT ;
    USE SIGNAL ;
    PORT
      LAYER M5 ;
        RECT  88.32 0 88.344 0.084 ;
    END
  END g_d[186]
  PIN g_d[187]
    DIRECTION INPUT ;
    USE SIGNAL ;
    PORT
      LAYER M5 ;
        RECT  88.512 0 88.536 0.084 ;
    END
  END g_d[187]
  PIN g_d[188]
    DIRECTION INPUT ;
    USE SIGNAL ;
    PORT
      LAYER M5 ;
        RECT  88.704 0 88.728 0.084 ;
    END
  END g_d[188]
  PIN g_d[189]
    DIRECTION INPUT ;
    USE SIGNAL ;
    PORT
      LAYER M5 ;
        RECT  88.896 0 88.92 0.084 ;
    END
  END g_d[189]
  PIN g_d[18]
    DIRECTION INPUT ;
    USE SIGNAL ;
    PORT
      LAYER M5 ;
        RECT  99.072 0 99.096 0.084 ;
    END
  END g_d[18]
  PIN g_d[190]
    DIRECTION INPUT ;
    USE SIGNAL ;
    PORT
      LAYER M5 ;
        RECT  89.088 0 89.112 0.084 ;
    END
  END g_d[190]
  PIN g_d[191]
    DIRECTION INPUT ;
    USE SIGNAL ;
    PORT
      LAYER M5 ;
        RECT  89.28 0 89.304 0.084 ;
    END
  END g_d[191]
  PIN g_d[192]
    DIRECTION INPUT ;
    USE SIGNAL ;
    PORT
      LAYER M5 ;
        RECT  89.472 0 89.496 0.084 ;
    END
  END g_d[192]
  PIN g_d[193]
    DIRECTION INPUT ;
    USE SIGNAL ;
    PORT
      LAYER M5 ;
        RECT  89.664 0 89.688 0.084 ;
    END
  END g_d[193]
  PIN g_d[194]
    DIRECTION INPUT ;
    USE SIGNAL ;
    PORT
      LAYER M5 ;
        RECT  89.856 0 89.88 0.084 ;
    END
  END g_d[194]
  PIN g_d[195]
    DIRECTION INPUT ;
    USE SIGNAL ;
    PORT
      LAYER M5 ;
        RECT  90.048 0 90.072 0.084 ;
    END
  END g_d[195]
  PIN g_d[196]
    DIRECTION INPUT ;
    USE SIGNAL ;
    PORT
      LAYER M5 ;
        RECT  90.24 0 90.264 0.084 ;
    END
  END g_d[196]
  PIN g_d[197]
    DIRECTION INPUT ;
    USE SIGNAL ;
    PORT
      LAYER M5 ;
        RECT  90.432 0 90.456 0.084 ;
    END
  END g_d[197]
  PIN g_d[198]
    DIRECTION INPUT ;
    USE SIGNAL ;
    PORT
      LAYER M5 ;
        RECT  90.624 0 90.648 0.084 ;
    END
  END g_d[198]
  PIN g_d[199]
    DIRECTION INPUT ;
    USE SIGNAL ;
    PORT
      LAYER M5 ;
        RECT  90.816 0 90.84 0.084 ;
    END
  END g_d[199]
  PIN g_d[19]
    DIRECTION INPUT ;
    USE SIGNAL ;
    PORT
      LAYER M5 ;
        RECT  99.264 0 99.288 0.084 ;
    END
  END g_d[19]
  PIN g_d[1]
    DIRECTION INPUT ;
    USE SIGNAL ;
    PORT
      LAYER M5 ;
        RECT  108.096 0 108.12 0.084 ;
    END
  END g_d[1]
  PIN g_d[200]
    DIRECTION INPUT ;
    USE SIGNAL ;
    PORT
      LAYER M5 ;
        RECT  91.008 0 91.032 0.084 ;
    END
  END g_d[200]
  PIN g_d[201]
    DIRECTION INPUT ;
    USE SIGNAL ;
    PORT
      LAYER M5 ;
        RECT  91.2 0 91.224 0.084 ;
    END
  END g_d[201]
  PIN g_d[202]
    DIRECTION INPUT ;
    USE SIGNAL ;
    PORT
      LAYER M5 ;
        RECT  91.392 0 91.416 0.084 ;
    END
  END g_d[202]
  PIN g_d[203]
    DIRECTION INPUT ;
    USE SIGNAL ;
    PORT
      LAYER M5 ;
        RECT  91.584 0 91.608 0.084 ;
    END
  END g_d[203]
  PIN g_d[204]
    DIRECTION INPUT ;
    USE SIGNAL ;
    PORT
      LAYER M5 ;
        RECT  91.776 0 91.8 0.084 ;
    END
  END g_d[204]
  PIN g_d[205]
    DIRECTION INPUT ;
    USE SIGNAL ;
    PORT
      LAYER M5 ;
        RECT  91.968 0 91.992 0.084 ;
    END
  END g_d[205]
  PIN g_d[206]
    DIRECTION INPUT ;
    USE SIGNAL ;
    PORT
      LAYER M5 ;
        RECT  92.16 0 92.184 0.084 ;
    END
  END g_d[206]
  PIN g_d[207]
    DIRECTION INPUT ;
    USE SIGNAL ;
    PORT
      LAYER M5 ;
        RECT  80.064 0 80.088 0.084 ;
    END
  END g_d[207]
  PIN g_d[208]
    DIRECTION INPUT ;
    USE SIGNAL ;
    PORT
      LAYER M5 ;
        RECT  80.256 0 80.28 0.084 ;
    END
  END g_d[208]
  PIN g_d[209]
    DIRECTION INPUT ;
    USE SIGNAL ;
    PORT
      LAYER M5 ;
        RECT  80.448 0 80.472 0.084 ;
    END
  END g_d[209]
  PIN g_d[20]
    DIRECTION INPUT ;
    USE SIGNAL ;
    PORT
      LAYER M5 ;
        RECT  99.456 0 99.48 0.084 ;
    END
  END g_d[20]
  PIN g_d[210]
    DIRECTION INPUT ;
    USE SIGNAL ;
    PORT
      LAYER M5 ;
        RECT  80.64 0 80.664 0.084 ;
    END
  END g_d[210]
  PIN g_d[211]
    DIRECTION INPUT ;
    USE SIGNAL ;
    PORT
      LAYER M5 ;
        RECT  80.832 0 80.856 0.084 ;
    END
  END g_d[211]
  PIN g_d[212]
    DIRECTION INPUT ;
    USE SIGNAL ;
    PORT
      LAYER M5 ;
        RECT  81.024 0 81.048 0.084 ;
    END
  END g_d[212]
  PIN g_d[213]
    DIRECTION INPUT ;
    USE SIGNAL ;
    PORT
      LAYER M5 ;
        RECT  81.216 0 81.24 0.084 ;
    END
  END g_d[213]
  PIN g_d[214]
    DIRECTION INPUT ;
    USE SIGNAL ;
    PORT
      LAYER M5 ;
        RECT  81.408 0 81.432 0.084 ;
    END
  END g_d[214]
  PIN g_d[215]
    DIRECTION INPUT ;
    USE SIGNAL ;
    PORT
      LAYER M5 ;
        RECT  81.6 0 81.624 0.084 ;
    END
  END g_d[215]
  PIN g_d[216]
    DIRECTION INPUT ;
    USE SIGNAL ;
    PORT
      LAYER M5 ;
        RECT  81.792 0 81.816 0.084 ;
    END
  END g_d[216]
  PIN g_d[217]
    DIRECTION INPUT ;
    USE SIGNAL ;
    PORT
      LAYER M5 ;
        RECT  81.984 0 82.008 0.084 ;
    END
  END g_d[217]
  PIN g_d[218]
    DIRECTION INPUT ;
    USE SIGNAL ;
    PORT
      LAYER M5 ;
        RECT  82.176 0 82.2 0.084 ;
    END
  END g_d[218]
  PIN g_d[219]
    DIRECTION INPUT ;
    USE SIGNAL ;
    PORT
      LAYER M5 ;
        RECT  82.368 0 82.392 0.084 ;
    END
  END g_d[219]
  PIN g_d[21]
    DIRECTION INPUT ;
    USE SIGNAL ;
    PORT
      LAYER M5 ;
        RECT  99.648 0 99.672 0.084 ;
    END
  END g_d[21]
  PIN g_d[220]
    DIRECTION INPUT ;
    USE SIGNAL ;
    PORT
      LAYER M5 ;
        RECT  82.56 0 82.584 0.084 ;
    END
  END g_d[220]
  PIN g_d[221]
    DIRECTION INPUT ;
    USE SIGNAL ;
    PORT
      LAYER M5 ;
        RECT  82.752 0 82.776 0.084 ;
    END
  END g_d[221]
  PIN g_d[222]
    DIRECTION INPUT ;
    USE SIGNAL ;
    PORT
      LAYER M5 ;
        RECT  82.944 0 82.968 0.084 ;
    END
  END g_d[222]
  PIN g_d[223]
    DIRECTION INPUT ;
    USE SIGNAL ;
    PORT
      LAYER M5 ;
        RECT  83.136 0 83.16 0.084 ;
    END
  END g_d[223]
  PIN g_d[224]
    DIRECTION INPUT ;
    USE SIGNAL ;
    PORT
      LAYER M5 ;
        RECT  83.328 0 83.352 0.084 ;
    END
  END g_d[224]
  PIN g_d[225]
    DIRECTION INPUT ;
    USE SIGNAL ;
    PORT
      LAYER M5 ;
        RECT  83.52 0 83.544 0.084 ;
    END
  END g_d[225]
  PIN g_d[226]
    DIRECTION INPUT ;
    USE SIGNAL ;
    PORT
      LAYER M5 ;
        RECT  83.712 0 83.736 0.084 ;
    END
  END g_d[226]
  PIN g_d[227]
    DIRECTION INPUT ;
    USE SIGNAL ;
    PORT
      LAYER M5 ;
        RECT  83.904 0 83.928 0.084 ;
    END
  END g_d[227]
  PIN g_d[228]
    DIRECTION INPUT ;
    USE SIGNAL ;
    PORT
      LAYER M5 ;
        RECT  84.096 0 84.12 0.084 ;
    END
  END g_d[228]
  PIN g_d[229]
    DIRECTION INPUT ;
    USE SIGNAL ;
    PORT
      LAYER M5 ;
        RECT  84.288 0 84.312 0.084 ;
    END
  END g_d[229]
  PIN g_d[22]
    DIRECTION INPUT ;
    USE SIGNAL ;
    PORT
      LAYER M5 ;
        RECT  99.84 0 99.864 0.084 ;
    END
  END g_d[22]
  PIN g_d[230]
    DIRECTION INPUT ;
    USE SIGNAL ;
    PORT
      LAYER M5 ;
        RECT  84.48 0 84.504 0.084 ;
    END
  END g_d[230]
  PIN g_d[231]
    DIRECTION INPUT ;
    USE SIGNAL ;
    PORT
      LAYER M5 ;
        RECT  84.672 0 84.696 0.084 ;
    END
  END g_d[231]
  PIN g_d[232]
    DIRECTION INPUT ;
    USE SIGNAL ;
    PORT
      LAYER M5 ;
        RECT  84.864 0 84.888 0.084 ;
    END
  END g_d[232]
  PIN g_d[233]
    DIRECTION INPUT ;
    USE SIGNAL ;
    PORT
      LAYER M5 ;
        RECT  85.056 0 85.08 0.084 ;
    END
  END g_d[233]
  PIN g_d[234]
    DIRECTION INPUT ;
    USE SIGNAL ;
    PORT
      LAYER M5 ;
        RECT  85.248 0 85.272 0.084 ;
    END
  END g_d[234]
  PIN g_d[235]
    DIRECTION INPUT ;
    USE SIGNAL ;
    PORT
      LAYER M5 ;
        RECT  85.44 0 85.464 0.084 ;
    END
  END g_d[235]
  PIN g_d[236]
    DIRECTION INPUT ;
    USE SIGNAL ;
    PORT
      LAYER M5 ;
        RECT  85.632 0 85.656 0.084 ;
    END
  END g_d[236]
  PIN g_d[237]
    DIRECTION INPUT ;
    USE SIGNAL ;
    PORT
      LAYER M5 ;
        RECT  85.824 0 85.848 0.084 ;
    END
  END g_d[237]
  PIN g_d[238]
    DIRECTION INPUT ;
    USE SIGNAL ;
    PORT
      LAYER M5 ;
        RECT  86.016 0 86.04 0.084 ;
    END
  END g_d[238]
  PIN g_d[239]
    DIRECTION INPUT ;
    USE SIGNAL ;
    PORT
      LAYER M5 ;
        RECT  73.92 0 73.944 0.084 ;
    END
  END g_d[239]
  PIN g_d[23]
    DIRECTION INPUT ;
    USE SIGNAL ;
    PORT
      LAYER M5 ;
        RECT  100.032 0 100.056 0.084 ;
    END
  END g_d[23]
  PIN g_d[240]
    DIRECTION INPUT ;
    USE SIGNAL ;
    PORT
      LAYER M5 ;
        RECT  74.112 0 74.136 0.084 ;
    END
  END g_d[240]
  PIN g_d[241]
    DIRECTION INPUT ;
    USE SIGNAL ;
    PORT
      LAYER M5 ;
        RECT  74.304 0 74.328 0.084 ;
    END
  END g_d[241]
  PIN g_d[242]
    DIRECTION INPUT ;
    USE SIGNAL ;
    PORT
      LAYER M5 ;
        RECT  74.496 0 74.52 0.084 ;
    END
  END g_d[242]
  PIN g_d[243]
    DIRECTION INPUT ;
    USE SIGNAL ;
    PORT
      LAYER M5 ;
        RECT  74.688 0 74.712 0.084 ;
    END
  END g_d[243]
  PIN g_d[244]
    DIRECTION INPUT ;
    USE SIGNAL ;
    PORT
      LAYER M5 ;
        RECT  74.88 0 74.904 0.084 ;
    END
  END g_d[244]
  PIN g_d[245]
    DIRECTION INPUT ;
    USE SIGNAL ;
    PORT
      LAYER M5 ;
        RECT  75.072 0 75.096 0.084 ;
    END
  END g_d[245]
  PIN g_d[246]
    DIRECTION INPUT ;
    USE SIGNAL ;
    PORT
      LAYER M5 ;
        RECT  75.264 0 75.288 0.084 ;
    END
  END g_d[246]
  PIN g_d[247]
    DIRECTION INPUT ;
    USE SIGNAL ;
    PORT
      LAYER M5 ;
        RECT  75.456 0 75.48 0.084 ;
    END
  END g_d[247]
  PIN g_d[248]
    DIRECTION INPUT ;
    USE SIGNAL ;
    PORT
      LAYER M5 ;
        RECT  75.648 0 75.672 0.084 ;
    END
  END g_d[248]
  PIN g_d[249]
    DIRECTION INPUT ;
    USE SIGNAL ;
    PORT
      LAYER M5 ;
        RECT  75.84 0 75.864 0.084 ;
    END
  END g_d[249]
  PIN g_d[24]
    DIRECTION INPUT ;
    USE SIGNAL ;
    PORT
      LAYER M5 ;
        RECT  100.224 0 100.248 0.084 ;
    END
  END g_d[24]
  PIN g_d[250]
    DIRECTION INPUT ;
    USE SIGNAL ;
    PORT
      LAYER M5 ;
        RECT  76.032 0 76.056 0.084 ;
    END
  END g_d[250]
  PIN g_d[251]
    DIRECTION INPUT ;
    USE SIGNAL ;
    PORT
      LAYER M5 ;
        RECT  76.224 0 76.248 0.084 ;
    END
  END g_d[251]
  PIN g_d[252]
    DIRECTION INPUT ;
    USE SIGNAL ;
    PORT
      LAYER M5 ;
        RECT  76.416 0 76.44 0.084 ;
    END
  END g_d[252]
  PIN g_d[253]
    DIRECTION INPUT ;
    USE SIGNAL ;
    PORT
      LAYER M5 ;
        RECT  76.608 0 76.632 0.084 ;
    END
  END g_d[253]
  PIN g_d[254]
    DIRECTION INPUT ;
    USE SIGNAL ;
    PORT
      LAYER M5 ;
        RECT  76.8 0 76.824 0.084 ;
    END
  END g_d[254]
  PIN g_d[255]
    DIRECTION INPUT ;
    USE SIGNAL ;
    PORT
      LAYER M5 ;
        RECT  76.992 0 77.016 0.084 ;
    END
  END g_d[255]
  PIN g_d[256]
    DIRECTION INPUT ;
    USE SIGNAL ;
    PORT
      LAYER M5 ;
        RECT  77.184 0 77.208 0.084 ;
    END
  END g_d[256]
  PIN g_d[257]
    DIRECTION INPUT ;
    USE SIGNAL ;
    PORT
      LAYER M5 ;
        RECT  77.376 0 77.4 0.084 ;
    END
  END g_d[257]
  PIN g_d[258]
    DIRECTION INPUT ;
    USE SIGNAL ;
    PORT
      LAYER M5 ;
        RECT  77.568 0 77.592 0.084 ;
    END
  END g_d[258]
  PIN g_d[259]
    DIRECTION INPUT ;
    USE SIGNAL ;
    PORT
      LAYER M5 ;
        RECT  77.76 0 77.784 0.084 ;
    END
  END g_d[259]
  PIN g_d[25]
    DIRECTION INPUT ;
    USE SIGNAL ;
    PORT
      LAYER M5 ;
        RECT  100.416 0 100.44 0.084 ;
    END
  END g_d[25]
  PIN g_d[260]
    DIRECTION INPUT ;
    USE SIGNAL ;
    PORT
      LAYER M5 ;
        RECT  77.952 0 77.976 0.084 ;
    END
  END g_d[260]
  PIN g_d[261]
    DIRECTION INPUT ;
    USE SIGNAL ;
    PORT
      LAYER M5 ;
        RECT  78.144 0 78.168 0.084 ;
    END
  END g_d[261]
  PIN g_d[262]
    DIRECTION INPUT ;
    USE SIGNAL ;
    PORT
      LAYER M5 ;
        RECT  78.336 0 78.36 0.084 ;
    END
  END g_d[262]
  PIN g_d[263]
    DIRECTION INPUT ;
    USE SIGNAL ;
    PORT
      LAYER M5 ;
        RECT  78.528 0 78.552 0.084 ;
    END
  END g_d[263]
  PIN g_d[264]
    DIRECTION INPUT ;
    USE SIGNAL ;
    PORT
      LAYER M5 ;
        RECT  78.72 0 78.744 0.084 ;
    END
  END g_d[264]
  PIN g_d[265]
    DIRECTION INPUT ;
    USE SIGNAL ;
    PORT
      LAYER M5 ;
        RECT  78.912 0 78.936 0.084 ;
    END
  END g_d[265]
  PIN g_d[266]
    DIRECTION INPUT ;
    USE SIGNAL ;
    PORT
      LAYER M5 ;
        RECT  79.104 0 79.128 0.084 ;
    END
  END g_d[266]
  PIN g_d[267]
    DIRECTION INPUT ;
    USE SIGNAL ;
    PORT
      LAYER M5 ;
        RECT  79.296 0 79.32 0.084 ;
    END
  END g_d[267]
  PIN g_d[268]
    DIRECTION INPUT ;
    USE SIGNAL ;
    PORT
      LAYER M5 ;
        RECT  79.488 0 79.512 0.084 ;
    END
  END g_d[268]
  PIN g_d[269]
    DIRECTION INPUT ;
    USE SIGNAL ;
    PORT
      LAYER M5 ;
        RECT  79.68 0 79.704 0.084 ;
    END
  END g_d[269]
  PIN g_d[26]
    DIRECTION INPUT ;
    USE SIGNAL ;
    PORT
      LAYER M5 ;
        RECT  100.608 0 100.632 0.084 ;
    END
  END g_d[26]
  PIN g_d[270]
    DIRECTION INPUT ;
    USE SIGNAL ;
    PORT
      LAYER M5 ;
        RECT  79.872 0 79.896 0.084 ;
    END
  END g_d[270]
  PIN g_d[271]
    DIRECTION INPUT ;
    USE SIGNAL ;
    PORT
      LAYER M5 ;
        RECT  92.352 0 92.376 0.084 ;
    END
  END g_d[271]
  PIN g_d[272]
    DIRECTION INPUT ;
    USE SIGNAL ;
    PORT
      LAYER M5 ;
        RECT  92.544 0 92.568 0.084 ;
    END
  END g_d[272]
  PIN g_d[273]
    DIRECTION INPUT ;
    USE SIGNAL ;
    PORT
      LAYER M5 ;
        RECT  92.736 0 92.76 0.084 ;
    END
  END g_d[273]
  PIN g_d[274]
    DIRECTION INPUT ;
    USE SIGNAL ;
    PORT
      LAYER M5 ;
        RECT  92.928 0 92.952 0.084 ;
    END
  END g_d[274]
  PIN g_d[275]
    DIRECTION INPUT ;
    USE SIGNAL ;
    PORT
      LAYER M5 ;
        RECT  93.12 0 93.144 0.084 ;
    END
  END g_d[275]
  PIN g_d[276]
    DIRECTION INPUT ;
    USE SIGNAL ;
    PORT
      LAYER M5 ;
        RECT  93.312 0 93.336 0.084 ;
    END
  END g_d[276]
  PIN g_d[277]
    DIRECTION INPUT ;
    USE SIGNAL ;
    PORT
      LAYER M5 ;
        RECT  93.504 0 93.528 0.084 ;
    END
  END g_d[277]
  PIN g_d[278]
    DIRECTION INPUT ;
    USE SIGNAL ;
    PORT
      LAYER M5 ;
        RECT  93.696 0 93.72 0.084 ;
    END
  END g_d[278]
  PIN g_d[279]
    DIRECTION INPUT ;
    USE SIGNAL ;
    PORT
      LAYER M5 ;
        RECT  93.888 0 93.912 0.084 ;
    END
  END g_d[279]
  PIN g_d[27]
    DIRECTION INPUT ;
    USE SIGNAL ;
    PORT
      LAYER M5 ;
        RECT  100.8 0 100.824 0.084 ;
    END
  END g_d[27]
  PIN g_d[280]
    DIRECTION INPUT ;
    USE SIGNAL ;
    PORT
      LAYER M5 ;
        RECT  94.08 0 94.104 0.084 ;
    END
  END g_d[280]
  PIN g_d[281]
    DIRECTION INPUT ;
    USE SIGNAL ;
    PORT
      LAYER M5 ;
        RECT  94.272 0 94.296 0.084 ;
    END
  END g_d[281]
  PIN g_d[282]
    DIRECTION INPUT ;
    USE SIGNAL ;
    PORT
      LAYER M5 ;
        RECT  94.464 0 94.488 0.084 ;
    END
  END g_d[282]
  PIN g_d[283]
    DIRECTION INPUT ;
    USE SIGNAL ;
    PORT
      LAYER M5 ;
        RECT  94.656 0 94.68 0.084 ;
    END
  END g_d[283]
  PIN g_d[284]
    DIRECTION INPUT ;
    USE SIGNAL ;
    PORT
      LAYER M5 ;
        RECT  94.848 0 94.872 0.084 ;
    END
  END g_d[284]
  PIN g_d[285]
    DIRECTION INPUT ;
    USE SIGNAL ;
    PORT
      LAYER M5 ;
        RECT  95.04 0 95.064 0.084 ;
    END
  END g_d[285]
  PIN g_d[286]
    DIRECTION INPUT ;
    USE SIGNAL ;
    PORT
      LAYER M5 ;
        RECT  95.232 0 95.256 0.084 ;
    END
  END g_d[286]
  PIN g_d[287]
    DIRECTION INPUT ;
    USE SIGNAL ;
    PORT
      LAYER M5 ;
        RECT  95.424 0 95.448 0.084 ;
    END
  END g_d[287]
  PIN g_d[288]
    DIRECTION INPUT ;
    USE SIGNAL ;
    PORT
      LAYER M5 ;
        RECT  95.616 0 95.64 0.084 ;
    END
  END g_d[288]
  PIN g_d[289]
    DIRECTION INPUT ;
    USE SIGNAL ;
    PORT
      LAYER M5 ;
        RECT  95.808 0 95.832 0.084 ;
    END
  END g_d[289]
  PIN g_d[28]
    DIRECTION INPUT ;
    USE SIGNAL ;
    PORT
      LAYER M5 ;
        RECT  100.992 0 101.016 0.084 ;
    END
  END g_d[28]
  PIN g_d[290]
    DIRECTION INPUT ;
    USE SIGNAL ;
    PORT
      LAYER M5 ;
        RECT  96 0 96.024 0.084 ;
    END
  END g_d[290]
  PIN g_d[291]
    DIRECTION INPUT ;
    USE SIGNAL ;
    PORT
      LAYER M5 ;
        RECT  96.192 0 96.216 0.084 ;
    END
  END g_d[291]
  PIN g_d[292]
    DIRECTION INPUT ;
    USE SIGNAL ;
    PORT
      LAYER M5 ;
        RECT  96.384 0 96.408 0.084 ;
    END
  END g_d[292]
  PIN g_d[293]
    DIRECTION INPUT ;
    USE SIGNAL ;
    PORT
      LAYER M5 ;
        RECT  96.576 0 96.6 0.084 ;
    END
  END g_d[293]
  PIN g_d[294]
    DIRECTION INPUT ;
    USE SIGNAL ;
    PORT
      LAYER M5 ;
        RECT  96.768 0 96.792 0.084 ;
    END
  END g_d[294]
  PIN g_d[295]
    DIRECTION INPUT ;
    USE SIGNAL ;
    PORT
      LAYER M5 ;
        RECT  96.96 0 96.984 0.084 ;
    END
  END g_d[295]
  PIN g_d[296]
    DIRECTION INPUT ;
    USE SIGNAL ;
    PORT
      LAYER M5 ;
        RECT  97.152 0 97.176 0.084 ;
    END
  END g_d[296]
  PIN g_d[297]
    DIRECTION INPUT ;
    USE SIGNAL ;
    PORT
      LAYER M5 ;
        RECT  97.344 0 97.368 0.084 ;
    END
  END g_d[297]
  PIN g_d[298]
    DIRECTION INPUT ;
    USE SIGNAL ;
    PORT
      LAYER M5 ;
        RECT  97.536 0 97.56 0.084 ;
    END
  END g_d[298]
  PIN g_d[299]
    DIRECTION INPUT ;
    USE SIGNAL ;
    PORT
      LAYER M5 ;
        RECT  97.728 0 97.752 0.084 ;
    END
  END g_d[299]
  PIN g_d[29]
    DIRECTION INPUT ;
    USE SIGNAL ;
    PORT
      LAYER M5 ;
        RECT  101.184 0 101.208 0.084 ;
    END
  END g_d[29]
  PIN g_d[2]
    DIRECTION INPUT ;
    USE SIGNAL ;
    PORT
      LAYER M5 ;
        RECT  108.288 0 108.312 0.084 ;
    END
  END g_d[2]
  PIN g_d[300]
    DIRECTION INPUT ;
    USE SIGNAL ;
    PORT
      LAYER M5 ;
        RECT  97.92 0 97.944 0.084 ;
    END
  END g_d[300]
  PIN g_d[301]
    DIRECTION INPUT ;
    USE SIGNAL ;
    PORT
      LAYER M5 ;
        RECT  98.112 0 98.136 0.084 ;
    END
  END g_d[301]
  PIN g_d[302]
    DIRECTION INPUT ;
    USE SIGNAL ;
    PORT
      LAYER M5 ;
        RECT  98.304 0 98.328 0.084 ;
    END
  END g_d[302]
  PIN g_d[303]
    DIRECTION INPUT ;
    USE SIGNAL ;
    PORT
      LAYER M5 ;
        RECT  123.072 0 123.096 0.084 ;
    END
  END g_d[303]
  PIN g_d[304]
    DIRECTION INPUT ;
    USE SIGNAL ;
    PORT
      LAYER M5 ;
        RECT  123.264 0 123.288 0.084 ;
    END
  END g_d[304]
  PIN g_d[305]
    DIRECTION INPUT ;
    USE SIGNAL ;
    PORT
      LAYER M5 ;
        RECT  123.456 0 123.48 0.084 ;
    END
  END g_d[305]
  PIN g_d[306]
    DIRECTION INPUT ;
    USE SIGNAL ;
    PORT
      LAYER M5 ;
        RECT  123.648 0 123.672 0.084 ;
    END
  END g_d[306]
  PIN g_d[307]
    DIRECTION INPUT ;
    USE SIGNAL ;
    PORT
      LAYER M5 ;
        RECT  123.84 0 123.864 0.084 ;
    END
  END g_d[307]
  PIN g_d[308]
    DIRECTION INPUT ;
    USE SIGNAL ;
    PORT
      LAYER M5 ;
        RECT  124.032 0 124.056 0.084 ;
    END
  END g_d[308]
  PIN g_d[309]
    DIRECTION INPUT ;
    USE SIGNAL ;
    PORT
      LAYER M5 ;
        RECT  124.224 0 124.248 0.084 ;
    END
  END g_d[309]
  PIN g_d[30]
    DIRECTION INPUT ;
    USE SIGNAL ;
    PORT
      LAYER M5 ;
        RECT  101.376 0 101.4 0.084 ;
    END
  END g_d[30]
  PIN g_d[310]
    DIRECTION INPUT ;
    USE SIGNAL ;
    PORT
      LAYER M5 ;
        RECT  124.416 0 124.44 0.084 ;
    END
  END g_d[310]
  PIN g_d[311]
    DIRECTION INPUT ;
    USE SIGNAL ;
    PORT
      LAYER M5 ;
        RECT  124.608 0 124.632 0.084 ;
    END
  END g_d[311]
  PIN g_d[312]
    DIRECTION INPUT ;
    USE SIGNAL ;
    PORT
      LAYER M5 ;
        RECT  124.8 0 124.824 0.084 ;
    END
  END g_d[312]
  PIN g_d[313]
    DIRECTION INPUT ;
    USE SIGNAL ;
    PORT
      LAYER M5 ;
        RECT  124.992 0 125.016 0.084 ;
    END
  END g_d[313]
  PIN g_d[314]
    DIRECTION INPUT ;
    USE SIGNAL ;
    PORT
      LAYER M5 ;
        RECT  125.184 0 125.208 0.084 ;
    END
  END g_d[314]
  PIN g_d[315]
    DIRECTION INPUT ;
    USE SIGNAL ;
    PORT
      LAYER M5 ;
        RECT  125.376 0 125.4 0.084 ;
    END
  END g_d[315]
  PIN g_d[316]
    DIRECTION INPUT ;
    USE SIGNAL ;
    PORT
      LAYER M5 ;
        RECT  125.568 0 125.592 0.084 ;
    END
  END g_d[316]
  PIN g_d[317]
    DIRECTION INPUT ;
    USE SIGNAL ;
    PORT
      LAYER M5 ;
        RECT  125.76 0 125.784 0.084 ;
    END
  END g_d[317]
  PIN g_d[318]
    DIRECTION INPUT ;
    USE SIGNAL ;
    PORT
      LAYER M5 ;
        RECT  125.952 0 125.976 0.084 ;
    END
  END g_d[318]
  PIN g_d[319]
    DIRECTION INPUT ;
    USE SIGNAL ;
    PORT
      LAYER M5 ;
        RECT  126.144 0 126.168 0.084 ;
    END
  END g_d[319]
  PIN g_d[31]
    DIRECTION INPUT ;
    USE SIGNAL ;
    PORT
      LAYER M5 ;
        RECT  101.568 0 101.592 0.084 ;
    END
  END g_d[31]
  PIN g_d[32]
    DIRECTION INPUT ;
    USE SIGNAL ;
    PORT
      LAYER M5 ;
        RECT  101.76 0 101.784 0.084 ;
    END
  END g_d[32]
  PIN g_d[33]
    DIRECTION INPUT ;
    USE SIGNAL ;
    PORT
      LAYER M5 ;
        RECT  101.952 0 101.976 0.084 ;
    END
  END g_d[33]
  PIN g_d[34]
    DIRECTION INPUT ;
    USE SIGNAL ;
    PORT
      LAYER M5 ;
        RECT  102.144 0 102.168 0.084 ;
    END
  END g_d[34]
  PIN g_d[35]
    DIRECTION INPUT ;
    USE SIGNAL ;
    PORT
      LAYER M5 ;
        RECT  102.336 0 102.36 0.084 ;
    END
  END g_d[35]
  PIN g_d[36]
    DIRECTION INPUT ;
    USE SIGNAL ;
    PORT
      LAYER M5 ;
        RECT  102.528 0 102.552 0.084 ;
    END
  END g_d[36]
  PIN g_d[37]
    DIRECTION INPUT ;
    USE SIGNAL ;
    PORT
      LAYER M5 ;
        RECT  102.72 0 102.744 0.084 ;
    END
  END g_d[37]
  PIN g_d[38]
    DIRECTION INPUT ;
    USE SIGNAL ;
    PORT
      LAYER M5 ;
        RECT  102.912 0 102.936 0.084 ;
    END
  END g_d[38]
  PIN g_d[39]
    DIRECTION INPUT ;
    USE SIGNAL ;
    PORT
      LAYER M5 ;
        RECT  103.104 0 103.128 0.084 ;
    END
  END g_d[39]
  PIN g_d[3]
    DIRECTION INPUT ;
    USE SIGNAL ;
    PORT
      LAYER M5 ;
        RECT  108.48 0 108.504 0.084 ;
    END
  END g_d[3]
  PIN g_d[40]
    DIRECTION INPUT ;
    USE SIGNAL ;
    PORT
      LAYER M5 ;
        RECT  103.296 0 103.32 0.084 ;
    END
  END g_d[40]
  PIN g_d[41]
    DIRECTION INPUT ;
    USE SIGNAL ;
    PORT
      LAYER M5 ;
        RECT  103.488 0 103.512 0.084 ;
    END
  END g_d[41]
  PIN g_d[42]
    DIRECTION INPUT ;
    USE SIGNAL ;
    PORT
      LAYER M5 ;
        RECT  103.68 0 103.704 0.084 ;
    END
  END g_d[42]
  PIN g_d[43]
    DIRECTION INPUT ;
    USE SIGNAL ;
    PORT
      LAYER M5 ;
        RECT  103.872 0 103.896 0.084 ;
    END
  END g_d[43]
  PIN g_d[44]
    DIRECTION INPUT ;
    USE SIGNAL ;
    PORT
      LAYER M5 ;
        RECT  104.064 0 104.088 0.084 ;
    END
  END g_d[44]
  PIN g_d[45]
    DIRECTION INPUT ;
    USE SIGNAL ;
    PORT
      LAYER M5 ;
        RECT  104.256 0 104.28 0.084 ;
    END
  END g_d[45]
  PIN g_d[46]
    DIRECTION INPUT ;
    USE SIGNAL ;
    PORT
      LAYER M5 ;
        RECT  104.448 0 104.472 0.084 ;
    END
  END g_d[46]
  PIN g_d[47]
    DIRECTION INPUT ;
    USE SIGNAL ;
    PORT
      LAYER M5 ;
        RECT  37.056 0 37.08 0.084 ;
    END
  END g_d[47]
  PIN g_d[48]
    DIRECTION INPUT ;
    USE SIGNAL ;
    PORT
      LAYER M5 ;
        RECT  37.248 0 37.272 0.084 ;
    END
  END g_d[48]
  PIN g_d[49]
    DIRECTION INPUT ;
    USE SIGNAL ;
    PORT
      LAYER M5 ;
        RECT  37.44 0 37.464 0.084 ;
    END
  END g_d[49]
  PIN g_d[4]
    DIRECTION INPUT ;
    USE SIGNAL ;
    PORT
      LAYER M5 ;
        RECT  108.672 0 108.696 0.084 ;
    END
  END g_d[4]
  PIN g_d[50]
    DIRECTION INPUT ;
    USE SIGNAL ;
    PORT
      LAYER M5 ;
        RECT  37.632 0 37.656 0.084 ;
    END
  END g_d[50]
  PIN g_d[51]
    DIRECTION INPUT ;
    USE SIGNAL ;
    PORT
      LAYER M5 ;
        RECT  37.824 0 37.848 0.084 ;
    END
  END g_d[51]
  PIN g_d[52]
    DIRECTION INPUT ;
    USE SIGNAL ;
    PORT
      LAYER M5 ;
        RECT  38.016 0 38.04 0.084 ;
    END
  END g_d[52]
  PIN g_d[53]
    DIRECTION INPUT ;
    USE SIGNAL ;
    PORT
      LAYER M5 ;
        RECT  38.208 0 38.232 0.084 ;
    END
  END g_d[53]
  PIN g_d[54]
    DIRECTION INPUT ;
    USE SIGNAL ;
    PORT
      LAYER M5 ;
        RECT  38.4 0 38.424 0.084 ;
    END
  END g_d[54]
  PIN g_d[55]
    DIRECTION INPUT ;
    USE SIGNAL ;
    PORT
      LAYER M5 ;
        RECT  38.592 0 38.616 0.084 ;
    END
  END g_d[55]
  PIN g_d[56]
    DIRECTION INPUT ;
    USE SIGNAL ;
    PORT
      LAYER M5 ;
        RECT  38.784 0 38.808 0.084 ;
    END
  END g_d[56]
  PIN g_d[57]
    DIRECTION INPUT ;
    USE SIGNAL ;
    PORT
      LAYER M5 ;
        RECT  38.976 0 39 0.084 ;
    END
  END g_d[57]
  PIN g_d[58]
    DIRECTION INPUT ;
    USE SIGNAL ;
    PORT
      LAYER M5 ;
        RECT  39.168 0 39.192 0.084 ;
    END
  END g_d[58]
  PIN g_d[59]
    DIRECTION INPUT ;
    USE SIGNAL ;
    PORT
      LAYER M5 ;
        RECT  39.36 0 39.384 0.084 ;
    END
  END g_d[59]
  PIN g_d[5]
    DIRECTION INPUT ;
    USE SIGNAL ;
    PORT
      LAYER M5 ;
        RECT  108.864 0 108.888 0.084 ;
    END
  END g_d[5]
  PIN g_d[60]
    DIRECTION INPUT ;
    USE SIGNAL ;
    PORT
      LAYER M5 ;
        RECT  39.552 0 39.576 0.084 ;
    END
  END g_d[60]
  PIN g_d[61]
    DIRECTION INPUT ;
    USE SIGNAL ;
    PORT
      LAYER M5 ;
        RECT  39.744 0 39.768 0.084 ;
    END
  END g_d[61]
  PIN g_d[62]
    DIRECTION INPUT ;
    USE SIGNAL ;
    PORT
      LAYER M5 ;
        RECT  39.936 0 39.96 0.084 ;
    END
  END g_d[62]
  PIN g_d[63]
    DIRECTION INPUT ;
    USE SIGNAL ;
    PORT
      LAYER M5 ;
        RECT  40.128 0 40.152 0.084 ;
    END
  END g_d[63]
  PIN g_d[64]
    DIRECTION INPUT ;
    USE SIGNAL ;
    PORT
      LAYER M5 ;
        RECT  40.32 0 40.344 0.084 ;
    END
  END g_d[64]
  PIN g_d[65]
    DIRECTION INPUT ;
    USE SIGNAL ;
    PORT
      LAYER M5 ;
        RECT  40.512 0 40.536 0.084 ;
    END
  END g_d[65]
  PIN g_d[66]
    DIRECTION INPUT ;
    USE SIGNAL ;
    PORT
      LAYER M5 ;
        RECT  40.704 0 40.728 0.084 ;
    END
  END g_d[66]
  PIN g_d[67]
    DIRECTION INPUT ;
    USE SIGNAL ;
    PORT
      LAYER M5 ;
        RECT  40.896 0 40.92 0.084 ;
    END
  END g_d[67]
  PIN g_d[68]
    DIRECTION INPUT ;
    USE SIGNAL ;
    PORT
      LAYER M5 ;
        RECT  41.088 0 41.112 0.084 ;
    END
  END g_d[68]
  PIN g_d[69]
    DIRECTION INPUT ;
    USE SIGNAL ;
    PORT
      LAYER M5 ;
        RECT  41.28 0 41.304 0.084 ;
    END
  END g_d[69]
  PIN g_d[6]
    DIRECTION INPUT ;
    USE SIGNAL ;
    PORT
      LAYER M5 ;
        RECT  109.056 0 109.08 0.084 ;
    END
  END g_d[6]
  PIN g_d[70]
    DIRECTION INPUT ;
    USE SIGNAL ;
    PORT
      LAYER M5 ;
        RECT  41.472 0 41.496 0.084 ;
    END
  END g_d[70]
  PIN g_d[71]
    DIRECTION INPUT ;
    USE SIGNAL ;
    PORT
      LAYER M5 ;
        RECT  41.664 0 41.688 0.084 ;
    END
  END g_d[71]
  PIN g_d[72]
    DIRECTION INPUT ;
    USE SIGNAL ;
    PORT
      LAYER M5 ;
        RECT  41.856 0 41.88 0.084 ;
    END
  END g_d[72]
  PIN g_d[73]
    DIRECTION INPUT ;
    USE SIGNAL ;
    PORT
      LAYER M5 ;
        RECT  42.048 0 42.072 0.084 ;
    END
  END g_d[73]
  PIN g_d[74]
    DIRECTION INPUT ;
    USE SIGNAL ;
    PORT
      LAYER M5 ;
        RECT  42.24 0 42.264 0.084 ;
    END
  END g_d[74]
  PIN g_d[75]
    DIRECTION INPUT ;
    USE SIGNAL ;
    PORT
      LAYER M5 ;
        RECT  42.432 0 42.456 0.084 ;
    END
  END g_d[75]
  PIN g_d[76]
    DIRECTION INPUT ;
    USE SIGNAL ;
    PORT
      LAYER M5 ;
        RECT  42.624 0 42.648 0.084 ;
    END
  END g_d[76]
  PIN g_d[77]
    DIRECTION INPUT ;
    USE SIGNAL ;
    PORT
      LAYER M5 ;
        RECT  42.816 0 42.84 0.084 ;
    END
  END g_d[77]
  PIN g_d[78]
    DIRECTION INPUT ;
    USE SIGNAL ;
    PORT
      LAYER M5 ;
        RECT  43.008 0 43.032 0.084 ;
    END
  END g_d[78]
  PIN g_d[79]
    DIRECTION INPUT ;
    USE SIGNAL ;
    PORT
      LAYER M5 ;
        RECT  49.344 0 49.368 0.084 ;
    END
  END g_d[79]
  PIN g_d[7]
    DIRECTION INPUT ;
    USE SIGNAL ;
    PORT
      LAYER M5 ;
        RECT  109.248 0 109.272 0.084 ;
    END
  END g_d[7]
  PIN g_d[80]
    DIRECTION INPUT ;
    USE SIGNAL ;
    PORT
      LAYER M5 ;
        RECT  49.536 0 49.56 0.084 ;
    END
  END g_d[80]
  PIN g_d[81]
    DIRECTION INPUT ;
    USE SIGNAL ;
    PORT
      LAYER M5 ;
        RECT  49.728 0 49.752 0.084 ;
    END
  END g_d[81]
  PIN g_d[82]
    DIRECTION INPUT ;
    USE SIGNAL ;
    PORT
      LAYER M5 ;
        RECT  49.92 0 49.944 0.084 ;
    END
  END g_d[82]
  PIN g_d[83]
    DIRECTION INPUT ;
    USE SIGNAL ;
    PORT
      LAYER M5 ;
        RECT  50.112 0 50.136 0.084 ;
    END
  END g_d[83]
  PIN g_d[84]
    DIRECTION INPUT ;
    USE SIGNAL ;
    PORT
      LAYER M5 ;
        RECT  50.304 0 50.328 0.084 ;
    END
  END g_d[84]
  PIN g_d[85]
    DIRECTION INPUT ;
    USE SIGNAL ;
    PORT
      LAYER M5 ;
        RECT  50.496 0 50.52 0.084 ;
    END
  END g_d[85]
  PIN g_d[86]
    DIRECTION INPUT ;
    USE SIGNAL ;
    PORT
      LAYER M5 ;
        RECT  50.688 0 50.712 0.084 ;
    END
  END g_d[86]
  PIN g_d[87]
    DIRECTION INPUT ;
    USE SIGNAL ;
    PORT
      LAYER M5 ;
        RECT  50.88 0 50.904 0.084 ;
    END
  END g_d[87]
  PIN g_d[88]
    DIRECTION INPUT ;
    USE SIGNAL ;
    PORT
      LAYER M5 ;
        RECT  51.072 0 51.096 0.084 ;
    END
  END g_d[88]
  PIN g_d[89]
    DIRECTION INPUT ;
    USE SIGNAL ;
    PORT
      LAYER M5 ;
        RECT  51.264 0 51.288 0.084 ;
    END
  END g_d[89]
  PIN g_d[8]
    DIRECTION INPUT ;
    USE SIGNAL ;
    PORT
      LAYER M5 ;
        RECT  109.44 0 109.464 0.084 ;
    END
  END g_d[8]
  PIN g_d[90]
    DIRECTION INPUT ;
    USE SIGNAL ;
    PORT
      LAYER M5 ;
        RECT  51.456 0 51.48 0.084 ;
    END
  END g_d[90]
  PIN g_d[91]
    DIRECTION INPUT ;
    USE SIGNAL ;
    PORT
      LAYER M5 ;
        RECT  51.648 0 51.672 0.084 ;
    END
  END g_d[91]
  PIN g_d[92]
    DIRECTION INPUT ;
    USE SIGNAL ;
    PORT
      LAYER M5 ;
        RECT  51.84 0 51.864 0.084 ;
    END
  END g_d[92]
  PIN g_d[93]
    DIRECTION INPUT ;
    USE SIGNAL ;
    PORT
      LAYER M5 ;
        RECT  52.032 0 52.056 0.084 ;
    END
  END g_d[93]
  PIN g_d[94]
    DIRECTION INPUT ;
    USE SIGNAL ;
    PORT
      LAYER M5 ;
        RECT  52.224 0 52.248 0.084 ;
    END
  END g_d[94]
  PIN g_d[95]
    DIRECTION INPUT ;
    USE SIGNAL ;
    PORT
      LAYER M5 ;
        RECT  52.416 0 52.44 0.084 ;
    END
  END g_d[95]
  PIN g_d[96]
    DIRECTION INPUT ;
    USE SIGNAL ;
    PORT
      LAYER M5 ;
        RECT  52.608 0 52.632 0.084 ;
    END
  END g_d[96]
  PIN g_d[97]
    DIRECTION INPUT ;
    USE SIGNAL ;
    PORT
      LAYER M5 ;
        RECT  52.8 0 52.824 0.084 ;
    END
  END g_d[97]
  PIN g_d[98]
    DIRECTION INPUT ;
    USE SIGNAL ;
    PORT
      LAYER M5 ;
        RECT  52.992 0 53.016 0.084 ;
    END
  END g_d[98]
  PIN g_d[99]
    DIRECTION INPUT ;
    USE SIGNAL ;
    PORT
      LAYER M5 ;
        RECT  53.184 0 53.208 0.084 ;
    END
  END g_d[99]
  PIN g_d[9]
    DIRECTION INPUT ;
    USE SIGNAL ;
    PORT
      LAYER M5 ;
        RECT  109.632 0 109.656 0.084 ;
    END
  END g_d[9]
  PIN g_i[0]
    DIRECTION INPUT ;
    USE SIGNAL ;
    PORT
      LAYER M5 ;
        RECT  126.336 0 126.36 0.084 ;
    END
  END g_i[0]
  PIN g_i[1]
    DIRECTION INPUT ;
    USE SIGNAL ;
    PORT
      LAYER M5 ;
        RECT  126.528 0 126.552 0.084 ;
    END
  END g_i[1]
  PIN g_i[2]
    DIRECTION INPUT ;
    USE SIGNAL ;
    PORT
      LAYER M5 ;
        RECT  126.72 0 126.744 0.084 ;
    END
  END g_i[2]
  PIN g_i[3]
    DIRECTION INPUT ;
    USE SIGNAL ;
    PORT
      LAYER M5 ;
        RECT  126.912 0 126.936 0.084 ;
    END
  END g_i[3]
  PIN g_v
    DIRECTION INPUT ;
    USE SIGNAL ;
    PORT
      LAYER M5 ;
        RECT  127.104 0 127.128 0.084 ;
    END
  END g_v
  PIN hct5_b[0]
    DIRECTION INPUT ;
    USE SIGNAL ;
    PORT
      LAYER M5 ;
        RECT  39.936 107.916 39.96 108 ;
    END
  END hct5_b[0]
  PIN hct5_b[100]
    DIRECTION INPUT ;
    USE SIGNAL ;
    PORT
      LAYER M5 ;
        RECT  71.04 107.916 71.064 108 ;
    END
  END hct5_b[100]
  PIN hct5_b[101]
    DIRECTION INPUT ;
    USE SIGNAL ;
    PORT
      LAYER M5 ;
        RECT  71.232 107.916 71.256 108 ;
    END
  END hct5_b[101]
  PIN hct5_b[102]
    DIRECTION INPUT ;
    USE SIGNAL ;
    PORT
      LAYER M5 ;
        RECT  71.424 107.916 71.448 108 ;
    END
  END hct5_b[102]
  PIN hct5_b[103]
    DIRECTION INPUT ;
    USE SIGNAL ;
    PORT
      LAYER M5 ;
        RECT  71.616 107.916 71.64 108 ;
    END
  END hct5_b[103]
  PIN hct5_b[104]
    DIRECTION INPUT ;
    USE SIGNAL ;
    PORT
      LAYER M5 ;
        RECT  71.808 107.916 71.832 108 ;
    END
  END hct5_b[104]
  PIN hct5_b[105]
    DIRECTION INPUT ;
    USE SIGNAL ;
    PORT
      LAYER M5 ;
        RECT  72 107.916 72.024 108 ;
    END
  END hct5_b[105]
  PIN hct5_b[106]
    DIRECTION INPUT ;
    USE SIGNAL ;
    PORT
      LAYER M5 ;
        RECT  72.192 107.916 72.216 108 ;
    END
  END hct5_b[106]
  PIN hct5_b[107]
    DIRECTION INPUT ;
    USE SIGNAL ;
    PORT
      LAYER M5 ;
        RECT  72.384 107.916 72.408 108 ;
    END
  END hct5_b[107]
  PIN hct5_b[108]
    DIRECTION INPUT ;
    USE SIGNAL ;
    PORT
      LAYER M5 ;
        RECT  72.576 107.916 72.6 108 ;
    END
  END hct5_b[108]
  PIN hct5_b[109]
    DIRECTION INPUT ;
    USE SIGNAL ;
    PORT
      LAYER M5 ;
        RECT  72.768 107.916 72.792 108 ;
    END
  END hct5_b[109]
  PIN hct5_b[10]
    DIRECTION INPUT ;
    USE SIGNAL ;
    PORT
      LAYER M5 ;
        RECT  48 107.916 48.024 108 ;
    END
  END hct5_b[10]
  PIN hct5_b[110]
    DIRECTION INPUT ;
    USE SIGNAL ;
    PORT
      LAYER M5 ;
        RECT  72.96 107.916 72.984 108 ;
    END
  END hct5_b[110]
  PIN hct5_b[111]
    DIRECTION INPUT ;
    USE SIGNAL ;
    PORT
      LAYER M5 ;
        RECT  73.152 107.916 73.176 108 ;
    END
  END hct5_b[111]
  PIN hct5_b[112]
    DIRECTION INPUT ;
    USE SIGNAL ;
    PORT
      LAYER M5 ;
        RECT  73.344 107.916 73.368 108 ;
    END
  END hct5_b[112]
  PIN hct5_b[113]
    DIRECTION INPUT ;
    USE SIGNAL ;
    PORT
      LAYER M5 ;
        RECT  73.536 107.916 73.56 108 ;
    END
  END hct5_b[113]
  PIN hct5_b[114]
    DIRECTION INPUT ;
    USE SIGNAL ;
    PORT
      LAYER M5 ;
        RECT  73.728 107.916 73.752 108 ;
    END
  END hct5_b[114]
  PIN hct5_b[115]
    DIRECTION INPUT ;
    USE SIGNAL ;
    PORT
      LAYER M5 ;
        RECT  73.92 107.916 73.944 108 ;
    END
  END hct5_b[115]
  PIN hct5_b[116]
    DIRECTION INPUT ;
    USE SIGNAL ;
    PORT
      LAYER M5 ;
        RECT  74.112 107.916 74.136 108 ;
    END
  END hct5_b[116]
  PIN hct5_b[117]
    DIRECTION INPUT ;
    USE SIGNAL ;
    PORT
      LAYER M5 ;
        RECT  74.304 107.916 74.328 108 ;
    END
  END hct5_b[117]
  PIN hct5_b[118]
    DIRECTION INPUT ;
    USE SIGNAL ;
    PORT
      LAYER M5 ;
        RECT  74.496 107.916 74.52 108 ;
    END
  END hct5_b[118]
  PIN hct5_b[119]
    DIRECTION INPUT ;
    USE SIGNAL ;
    PORT
      LAYER M5 ;
        RECT  74.688 107.916 74.712 108 ;
    END
  END hct5_b[119]
  PIN hct5_b[11]
    DIRECTION INPUT ;
    USE SIGNAL ;
    PORT
      LAYER M5 ;
        RECT  48.192 107.916 48.216 108 ;
    END
  END hct5_b[11]
  PIN hct5_b[120]
    DIRECTION INPUT ;
    USE SIGNAL ;
    PORT
      LAYER M5 ;
        RECT  74.88 107.916 74.904 108 ;
    END
  END hct5_b[120]
  PIN hct5_b[121]
    DIRECTION INPUT ;
    USE SIGNAL ;
    PORT
      LAYER M5 ;
        RECT  75.072 107.916 75.096 108 ;
    END
  END hct5_b[121]
  PIN hct5_b[122]
    DIRECTION INPUT ;
    USE SIGNAL ;
    PORT
      LAYER M5 ;
        RECT  75.264 107.916 75.288 108 ;
    END
  END hct5_b[122]
  PIN hct5_b[123]
    DIRECTION INPUT ;
    USE SIGNAL ;
    PORT
      LAYER M5 ;
        RECT  75.456 107.916 75.48 108 ;
    END
  END hct5_b[123]
  PIN hct5_b[124]
    DIRECTION INPUT ;
    USE SIGNAL ;
    PORT
      LAYER M5 ;
        RECT  75.648 107.916 75.672 108 ;
    END
  END hct5_b[124]
  PIN hct5_b[125]
    DIRECTION INPUT ;
    USE SIGNAL ;
    PORT
      LAYER M5 ;
        RECT  75.84 107.916 75.864 108 ;
    END
  END hct5_b[125]
  PIN hct5_b[126]
    DIRECTION INPUT ;
    USE SIGNAL ;
    PORT
      LAYER M5 ;
        RECT  76.032 107.916 76.056 108 ;
    END
  END hct5_b[126]
  PIN hct5_b[127]
    DIRECTION INPUT ;
    USE SIGNAL ;
    PORT
      LAYER M5 ;
        RECT  76.224 107.916 76.248 108 ;
    END
  END hct5_b[127]
  PIN hct5_b[128]
    DIRECTION INPUT ;
    USE SIGNAL ;
    PORT
      LAYER M5 ;
        RECT  76.416 107.916 76.44 108 ;
    END
  END hct5_b[128]
  PIN hct5_b[129]
    DIRECTION INPUT ;
    USE SIGNAL ;
    PORT
      LAYER M5 ;
        RECT  89.52 107.916 89.544 108 ;
    END
  END hct5_b[129]
  PIN hct5_b[12]
    DIRECTION INPUT ;
    USE SIGNAL ;
    PORT
      LAYER M5 ;
        RECT  48.384 107.916 48.408 108 ;
    END
  END hct5_b[12]
  PIN hct5_b[130]
    DIRECTION INPUT ;
    USE SIGNAL ;
    PORT
      LAYER M5 ;
        RECT  89.712 107.916 89.736 108 ;
    END
  END hct5_b[130]
  PIN hct5_b[131]
    DIRECTION INPUT ;
    USE SIGNAL ;
    PORT
      LAYER M5 ;
        RECT  89.904 107.916 89.928 108 ;
    END
  END hct5_b[131]
  PIN hct5_b[132]
    DIRECTION INPUT ;
    USE SIGNAL ;
    PORT
      LAYER M5 ;
        RECT  90.096 107.916 90.12 108 ;
    END
  END hct5_b[132]
  PIN hct5_b[133]
    DIRECTION INPUT ;
    USE SIGNAL ;
    PORT
      LAYER M5 ;
        RECT  90.288 107.916 90.312 108 ;
    END
  END hct5_b[133]
  PIN hct5_b[134]
    DIRECTION INPUT ;
    USE SIGNAL ;
    PORT
      LAYER M5 ;
        RECT  90.48 107.916 90.504 108 ;
    END
  END hct5_b[134]
  PIN hct5_b[135]
    DIRECTION INPUT ;
    USE SIGNAL ;
    PORT
      LAYER M5 ;
        RECT  90.672 107.916 90.696 108 ;
    END
  END hct5_b[135]
  PIN hct5_b[136]
    DIRECTION INPUT ;
    USE SIGNAL ;
    PORT
      LAYER M5 ;
        RECT  90.864 107.916 90.888 108 ;
    END
  END hct5_b[136]
  PIN hct5_b[137]
    DIRECTION INPUT ;
    USE SIGNAL ;
    PORT
      LAYER M5 ;
        RECT  91.056 107.916 91.08 108 ;
    END
  END hct5_b[137]
  PIN hct5_b[138]
    DIRECTION INPUT ;
    USE SIGNAL ;
    PORT
      LAYER M5 ;
        RECT  91.248 107.916 91.272 108 ;
    END
  END hct5_b[138]
  PIN hct5_b[139]
    DIRECTION INPUT ;
    USE SIGNAL ;
    PORT
      LAYER M5 ;
        RECT  91.44 107.916 91.464 108 ;
    END
  END hct5_b[139]
  PIN hct5_b[13]
    DIRECTION INPUT ;
    USE SIGNAL ;
    PORT
      LAYER M5 ;
        RECT  48.576 107.916 48.6 108 ;
    END
  END hct5_b[13]
  PIN hct5_b[140]
    DIRECTION INPUT ;
    USE SIGNAL ;
    PORT
      LAYER M5 ;
        RECT  91.632 107.916 91.656 108 ;
    END
  END hct5_b[140]
  PIN hct5_b[141]
    DIRECTION INPUT ;
    USE SIGNAL ;
    PORT
      LAYER M5 ;
        RECT  91.824 107.916 91.848 108 ;
    END
  END hct5_b[141]
  PIN hct5_b[142]
    DIRECTION INPUT ;
    USE SIGNAL ;
    PORT
      LAYER M5 ;
        RECT  92.016 107.916 92.04 108 ;
    END
  END hct5_b[142]
  PIN hct5_b[143]
    DIRECTION INPUT ;
    USE SIGNAL ;
    PORT
      LAYER M5 ;
        RECT  92.208 107.916 92.232 108 ;
    END
  END hct5_b[143]
  PIN hct5_b[144]
    DIRECTION INPUT ;
    USE SIGNAL ;
    PORT
      LAYER M5 ;
        RECT  92.4 107.916 92.424 108 ;
    END
  END hct5_b[144]
  PIN hct5_b[145]
    DIRECTION INPUT ;
    USE SIGNAL ;
    PORT
      LAYER M5 ;
        RECT  92.592 107.916 92.616 108 ;
    END
  END hct5_b[145]
  PIN hct5_b[146]
    DIRECTION INPUT ;
    USE SIGNAL ;
    PORT
      LAYER M5 ;
        RECT  92.784 107.916 92.808 108 ;
    END
  END hct5_b[146]
  PIN hct5_b[147]
    DIRECTION INPUT ;
    USE SIGNAL ;
    PORT
      LAYER M5 ;
        RECT  92.976 107.916 93 108 ;
    END
  END hct5_b[147]
  PIN hct5_b[148]
    DIRECTION INPUT ;
    USE SIGNAL ;
    PORT
      LAYER M5 ;
        RECT  93.168 107.916 93.192 108 ;
    END
  END hct5_b[148]
  PIN hct5_b[149]
    DIRECTION INPUT ;
    USE SIGNAL ;
    PORT
      LAYER M5 ;
        RECT  93.36 107.916 93.384 108 ;
    END
  END hct5_b[149]
  PIN hct5_b[14]
    DIRECTION INPUT ;
    USE SIGNAL ;
    PORT
      LAYER M5 ;
        RECT  48.768 107.916 48.792 108 ;
    END
  END hct5_b[14]
  PIN hct5_b[150]
    DIRECTION INPUT ;
    USE SIGNAL ;
    PORT
      LAYER M5 ;
        RECT  93.552 107.916 93.576 108 ;
    END
  END hct5_b[150]
  PIN hct5_b[151]
    DIRECTION INPUT ;
    USE SIGNAL ;
    PORT
      LAYER M5 ;
        RECT  93.744 107.916 93.768 108 ;
    END
  END hct5_b[151]
  PIN hct5_b[152]
    DIRECTION INPUT ;
    USE SIGNAL ;
    PORT
      LAYER M5 ;
        RECT  93.936 107.916 93.96 108 ;
    END
  END hct5_b[152]
  PIN hct5_b[153]
    DIRECTION INPUT ;
    USE SIGNAL ;
    PORT
      LAYER M5 ;
        RECT  94.128 107.916 94.152 108 ;
    END
  END hct5_b[153]
  PIN hct5_b[154]
    DIRECTION INPUT ;
    USE SIGNAL ;
    PORT
      LAYER M5 ;
        RECT  94.32 107.916 94.344 108 ;
    END
  END hct5_b[154]
  PIN hct5_b[155]
    DIRECTION INPUT ;
    USE SIGNAL ;
    PORT
      LAYER M5 ;
        RECT  94.512 107.916 94.536 108 ;
    END
  END hct5_b[155]
  PIN hct5_b[156]
    DIRECTION INPUT ;
    USE SIGNAL ;
    PORT
      LAYER M5 ;
        RECT  94.704 107.916 94.728 108 ;
    END
  END hct5_b[156]
  PIN hct5_b[157]
    DIRECTION INPUT ;
    USE SIGNAL ;
    PORT
      LAYER M5 ;
        RECT  94.896 107.916 94.92 108 ;
    END
  END hct5_b[157]
  PIN hct5_b[158]
    DIRECTION INPUT ;
    USE SIGNAL ;
    PORT
      LAYER M5 ;
        RECT  95.088 107.916 95.112 108 ;
    END
  END hct5_b[158]
  PIN hct5_b[159]
    DIRECTION INPUT ;
    USE SIGNAL ;
    PORT
      LAYER M5 ;
        RECT  95.28 107.916 95.304 108 ;
    END
  END hct5_b[159]
  PIN hct5_b[15]
    DIRECTION INPUT ;
    USE SIGNAL ;
    PORT
      LAYER M5 ;
        RECT  48.96 107.916 48.984 108 ;
    END
  END hct5_b[15]
  PIN hct5_b[160]
    DIRECTION INPUT ;
    USE SIGNAL ;
    PORT
      LAYER M5 ;
        RECT  95.472 107.916 95.496 108 ;
    END
  END hct5_b[160]
  PIN hct5_b[161]
    DIRECTION INPUT ;
    USE SIGNAL ;
    PORT
      LAYER M5 ;
        RECT  76.608 107.916 76.632 108 ;
    END
  END hct5_b[161]
  PIN hct5_b[162]
    DIRECTION INPUT ;
    USE SIGNAL ;
    PORT
      LAYER M5 ;
        RECT  76.8 107.916 76.824 108 ;
    END
  END hct5_b[162]
  PIN hct5_b[163]
    DIRECTION INPUT ;
    USE SIGNAL ;
    PORT
      LAYER M5 ;
        RECT  76.992 107.916 77.016 108 ;
    END
  END hct5_b[163]
  PIN hct5_b[164]
    DIRECTION INPUT ;
    USE SIGNAL ;
    PORT
      LAYER M5 ;
        RECT  77.184 107.916 77.208 108 ;
    END
  END hct5_b[164]
  PIN hct5_b[165]
    DIRECTION INPUT ;
    USE SIGNAL ;
    PORT
      LAYER M5 ;
        RECT  77.376 107.916 77.4 108 ;
    END
  END hct5_b[165]
  PIN hct5_b[166]
    DIRECTION INPUT ;
    USE SIGNAL ;
    PORT
      LAYER M5 ;
        RECT  77.568 107.916 77.592 108 ;
    END
  END hct5_b[166]
  PIN hct5_b[167]
    DIRECTION INPUT ;
    USE SIGNAL ;
    PORT
      LAYER M5 ;
        RECT  77.76 107.916 77.784 108 ;
    END
  END hct5_b[167]
  PIN hct5_b[168]
    DIRECTION INPUT ;
    USE SIGNAL ;
    PORT
      LAYER M5 ;
        RECT  77.952 107.916 77.976 108 ;
    END
  END hct5_b[168]
  PIN hct5_b[169]
    DIRECTION INPUT ;
    USE SIGNAL ;
    PORT
      LAYER M5 ;
        RECT  78.144 107.916 78.168 108 ;
    END
  END hct5_b[169]
  PIN hct5_b[16]
    DIRECTION INPUT ;
    USE SIGNAL ;
    PORT
      LAYER M5 ;
        RECT  49.152 107.916 49.176 108 ;
    END
  END hct5_b[16]
  PIN hct5_b[17]
    DIRECTION INPUT ;
    USE SIGNAL ;
    PORT
      LAYER M5 ;
        RECT  49.344 107.916 49.368 108 ;
    END
  END hct5_b[17]
  PIN hct5_b[18]
    DIRECTION INPUT ;
    USE SIGNAL ;
    PORT
      LAYER M5 ;
        RECT  49.536 107.916 49.56 108 ;
    END
  END hct5_b[18]
  PIN hct5_b[19]
    DIRECTION INPUT ;
    USE SIGNAL ;
    PORT
      LAYER M5 ;
        RECT  49.728 107.916 49.752 108 ;
    END
  END hct5_b[19]
  PIN hct5_b[1]
    DIRECTION INPUT ;
    USE SIGNAL ;
    PORT
      LAYER M5 ;
        RECT  40.128 107.916 40.152 108 ;
    END
  END hct5_b[1]
  PIN hct5_b[20]
    DIRECTION INPUT ;
    USE SIGNAL ;
    PORT
      LAYER M5 ;
        RECT  49.92 107.916 49.944 108 ;
    END
  END hct5_b[20]
  PIN hct5_b[21]
    DIRECTION INPUT ;
    USE SIGNAL ;
    PORT
      LAYER M5 ;
        RECT  50.112 107.916 50.136 108 ;
    END
  END hct5_b[21]
  PIN hct5_b[22]
    DIRECTION INPUT ;
    USE SIGNAL ;
    PORT
      LAYER M5 ;
        RECT  50.304 107.916 50.328 108 ;
    END
  END hct5_b[22]
  PIN hct5_b[23]
    DIRECTION INPUT ;
    USE SIGNAL ;
    PORT
      LAYER M5 ;
        RECT  50.496 107.916 50.52 108 ;
    END
  END hct5_b[23]
  PIN hct5_b[24]
    DIRECTION INPUT ;
    USE SIGNAL ;
    PORT
      LAYER M5 ;
        RECT  50.688 107.916 50.712 108 ;
    END
  END hct5_b[24]
  PIN hct5_b[25]
    DIRECTION INPUT ;
    USE SIGNAL ;
    PORT
      LAYER M5 ;
        RECT  50.88 107.916 50.904 108 ;
    END
  END hct5_b[25]
  PIN hct5_b[26]
    DIRECTION INPUT ;
    USE SIGNAL ;
    PORT
      LAYER M5 ;
        RECT  51.072 107.916 51.096 108 ;
    END
  END hct5_b[26]
  PIN hct5_b[27]
    DIRECTION INPUT ;
    USE SIGNAL ;
    PORT
      LAYER M5 ;
        RECT  51.264 107.916 51.288 108 ;
    END
  END hct5_b[27]
  PIN hct5_b[28]
    DIRECTION INPUT ;
    USE SIGNAL ;
    PORT
      LAYER M5 ;
        RECT  51.456 107.916 51.48 108 ;
    END
  END hct5_b[28]
  PIN hct5_b[29]
    DIRECTION INPUT ;
    USE SIGNAL ;
    PORT
      LAYER M5 ;
        RECT  51.648 107.916 51.672 108 ;
    END
  END hct5_b[29]
  PIN hct5_b[2]
    DIRECTION INPUT ;
    USE SIGNAL ;
    PORT
      LAYER M5 ;
        RECT  40.32 107.916 40.344 108 ;
    END
  END hct5_b[2]
  PIN hct5_b[30]
    DIRECTION INPUT ;
    USE SIGNAL ;
    PORT
      LAYER M5 ;
        RECT  51.84 107.916 51.864 108 ;
    END
  END hct5_b[30]
  PIN hct5_b[31]
    DIRECTION INPUT ;
    USE SIGNAL ;
    PORT
      LAYER M5 ;
        RECT  52.032 107.916 52.056 108 ;
    END
  END hct5_b[31]
  PIN hct5_b[32]
    DIRECTION INPUT ;
    USE SIGNAL ;
    PORT
      LAYER M5 ;
        RECT  52.224 107.916 52.248 108 ;
    END
  END hct5_b[32]
  PIN hct5_b[33]
    DIRECTION INPUT ;
    USE SIGNAL ;
    PORT
      LAYER M5 ;
        RECT  52.416 107.916 52.44 108 ;
    END
  END hct5_b[33]
  PIN hct5_b[34]
    DIRECTION INPUT ;
    USE SIGNAL ;
    PORT
      LAYER M5 ;
        RECT  52.608 107.916 52.632 108 ;
    END
  END hct5_b[34]
  PIN hct5_b[35]
    DIRECTION INPUT ;
    USE SIGNAL ;
    PORT
      LAYER M5 ;
        RECT  52.8 107.916 52.824 108 ;
    END
  END hct5_b[35]
  PIN hct5_b[36]
    DIRECTION INPUT ;
    USE SIGNAL ;
    PORT
      LAYER M5 ;
        RECT  52.992 107.916 53.016 108 ;
    END
  END hct5_b[36]
  PIN hct5_b[37]
    DIRECTION INPUT ;
    USE SIGNAL ;
    PORT
      LAYER M5 ;
        RECT  53.184 107.916 53.208 108 ;
    END
  END hct5_b[37]
  PIN hct5_b[38]
    DIRECTION INPUT ;
    USE SIGNAL ;
    PORT
      LAYER M5 ;
        RECT  53.376 107.916 53.4 108 ;
    END
  END hct5_b[38]
  PIN hct5_b[39]
    DIRECTION INPUT ;
    USE SIGNAL ;
    PORT
      LAYER M5 ;
        RECT  53.568 107.916 53.592 108 ;
    END
  END hct5_b[39]
  PIN hct5_b[3]
    DIRECTION INPUT ;
    USE SIGNAL ;
    PORT
      LAYER M5 ;
        RECT  40.512 107.916 40.536 108 ;
    END
  END hct5_b[3]
  PIN hct5_b[40]
    DIRECTION INPUT ;
    USE SIGNAL ;
    PORT
      LAYER M5 ;
        RECT  53.76 107.916 53.784 108 ;
    END
  END hct5_b[40]
  PIN hct5_b[41]
    DIRECTION INPUT ;
    USE SIGNAL ;
    PORT
      LAYER M5 ;
        RECT  53.952 107.916 53.976 108 ;
    END
  END hct5_b[41]
  PIN hct5_b[42]
    DIRECTION INPUT ;
    USE SIGNAL ;
    PORT
      LAYER M5 ;
        RECT  54.144 107.916 54.168 108 ;
    END
  END hct5_b[42]
  PIN hct5_b[43]
    DIRECTION INPUT ;
    USE SIGNAL ;
    PORT
      LAYER M5 ;
        RECT  54.336 107.916 54.36 108 ;
    END
  END hct5_b[43]
  PIN hct5_b[44]
    DIRECTION INPUT ;
    USE SIGNAL ;
    PORT
      LAYER M5 ;
        RECT  54.528 107.916 54.552 108 ;
    END
  END hct5_b[44]
  PIN hct5_b[45]
    DIRECTION INPUT ;
    USE SIGNAL ;
    PORT
      LAYER M5 ;
        RECT  54.72 107.916 54.744 108 ;
    END
  END hct5_b[45]
  PIN hct5_b[46]
    DIRECTION INPUT ;
    USE SIGNAL ;
    PORT
      LAYER M5 ;
        RECT  54.912 107.916 54.936 108 ;
    END
  END hct5_b[46]
  PIN hct5_b[47]
    DIRECTION INPUT ;
    USE SIGNAL ;
    PORT
      LAYER M5 ;
        RECT  55.104 107.916 55.128 108 ;
    END
  END hct5_b[47]
  PIN hct5_b[48]
    DIRECTION INPUT ;
    USE SIGNAL ;
    PORT
      LAYER M5 ;
        RECT  55.296 107.916 55.32 108 ;
    END
  END hct5_b[48]
  PIN hct5_b[49]
    DIRECTION INPUT ;
    USE SIGNAL ;
    PORT
      LAYER M5 ;
        RECT  55.488 107.916 55.512 108 ;
    END
  END hct5_b[49]
  PIN hct5_b[4]
    DIRECTION INPUT ;
    USE SIGNAL ;
    PORT
      LAYER M5 ;
        RECT  40.704 107.916 40.728 108 ;
    END
  END hct5_b[4]
  PIN hct5_b[50]
    DIRECTION INPUT ;
    USE SIGNAL ;
    PORT
      LAYER M5 ;
        RECT  55.68 107.916 55.704 108 ;
    END
  END hct5_b[50]
  PIN hct5_b[51]
    DIRECTION INPUT ;
    USE SIGNAL ;
    PORT
      LAYER M5 ;
        RECT  55.872 107.916 55.896 108 ;
    END
  END hct5_b[51]
  PIN hct5_b[52]
    DIRECTION INPUT ;
    USE SIGNAL ;
    PORT
      LAYER M5 ;
        RECT  56.064 107.916 56.088 108 ;
    END
  END hct5_b[52]
  PIN hct5_b[53]
    DIRECTION INPUT ;
    USE SIGNAL ;
    PORT
      LAYER M5 ;
        RECT  56.256 107.916 56.28 108 ;
    END
  END hct5_b[53]
  PIN hct5_b[54]
    DIRECTION INPUT ;
    USE SIGNAL ;
    PORT
      LAYER M5 ;
        RECT  56.448 107.916 56.472 108 ;
    END
  END hct5_b[54]
  PIN hct5_b[55]
    DIRECTION INPUT ;
    USE SIGNAL ;
    PORT
      LAYER M5 ;
        RECT  56.64 107.916 56.664 108 ;
    END
  END hct5_b[55]
  PIN hct5_b[56]
    DIRECTION INPUT ;
    USE SIGNAL ;
    PORT
      LAYER M5 ;
        RECT  56.832 107.916 56.856 108 ;
    END
  END hct5_b[56]
  PIN hct5_b[57]
    DIRECTION INPUT ;
    USE SIGNAL ;
    PORT
      LAYER M5 ;
        RECT  57.024 107.916 57.048 108 ;
    END
  END hct5_b[57]
  PIN hct5_b[58]
    DIRECTION INPUT ;
    USE SIGNAL ;
    PORT
      LAYER M5 ;
        RECT  57.216 107.916 57.24 108 ;
    END
  END hct5_b[58]
  PIN hct5_b[59]
    DIRECTION INPUT ;
    USE SIGNAL ;
    PORT
      LAYER M5 ;
        RECT  57.408 107.916 57.432 108 ;
    END
  END hct5_b[59]
  PIN hct5_b[5]
    DIRECTION INPUT ;
    USE SIGNAL ;
    PORT
      LAYER M5 ;
        RECT  47.04 107.916 47.064 108 ;
    END
  END hct5_b[5]
  PIN hct5_b[60]
    DIRECTION INPUT ;
    USE SIGNAL ;
    PORT
      LAYER M5 ;
        RECT  57.6 107.916 57.624 108 ;
    END
  END hct5_b[60]
  PIN hct5_b[61]
    DIRECTION INPUT ;
    USE SIGNAL ;
    PORT
      LAYER M5 ;
        RECT  57.792 107.916 57.816 108 ;
    END
  END hct5_b[61]
  PIN hct5_b[62]
    DIRECTION INPUT ;
    USE SIGNAL ;
    PORT
      LAYER M5 ;
        RECT  57.984 107.916 58.008 108 ;
    END
  END hct5_b[62]
  PIN hct5_b[63]
    DIRECTION INPUT ;
    USE SIGNAL ;
    PORT
      LAYER M5 ;
        RECT  58.176 107.916 58.2 108 ;
    END
  END hct5_b[63]
  PIN hct5_b[64]
    DIRECTION INPUT ;
    USE SIGNAL ;
    PORT
      LAYER M5 ;
        RECT  58.368 107.916 58.392 108 ;
    END
  END hct5_b[64]
  PIN hct5_b[65]
    DIRECTION INPUT ;
    USE SIGNAL ;
    PORT
      LAYER M5 ;
        RECT  40.896 107.916 40.92 108 ;
    END
  END hct5_b[65]
  PIN hct5_b[66]
    DIRECTION INPUT ;
    USE SIGNAL ;
    PORT
      LAYER M5 ;
        RECT  41.088 107.916 41.112 108 ;
    END
  END hct5_b[66]
  PIN hct5_b[67]
    DIRECTION INPUT ;
    USE SIGNAL ;
    PORT
      LAYER M5 ;
        RECT  41.28 107.916 41.304 108 ;
    END
  END hct5_b[67]
  PIN hct5_b[68]
    DIRECTION INPUT ;
    USE SIGNAL ;
    PORT
      LAYER M5 ;
        RECT  41.472 107.916 41.496 108 ;
    END
  END hct5_b[68]
  PIN hct5_b[69]
    DIRECTION INPUT ;
    USE SIGNAL ;
    PORT
      LAYER M5 ;
        RECT  41.664 107.916 41.688 108 ;
    END
  END hct5_b[69]
  PIN hct5_b[6]
    DIRECTION INPUT ;
    USE SIGNAL ;
    PORT
      LAYER M5 ;
        RECT  47.232 107.916 47.256 108 ;
    END
  END hct5_b[6]
  PIN hct5_b[70]
    DIRECTION INPUT ;
    USE SIGNAL ;
    PORT
      LAYER M5 ;
        RECT  41.856 107.916 41.88 108 ;
    END
  END hct5_b[70]
  PIN hct5_b[71]
    DIRECTION INPUT ;
    USE SIGNAL ;
    PORT
      LAYER M5 ;
        RECT  42.048 107.916 42.072 108 ;
    END
  END hct5_b[71]
  PIN hct5_b[72]
    DIRECTION INPUT ;
    USE SIGNAL ;
    PORT
      LAYER M5 ;
        RECT  42.24 107.916 42.264 108 ;
    END
  END hct5_b[72]
  PIN hct5_b[73]
    DIRECTION INPUT ;
    USE SIGNAL ;
    PORT
      LAYER M5 ;
        RECT  42.432 107.916 42.456 108 ;
    END
  END hct5_b[73]
  PIN hct5_b[74]
    DIRECTION INPUT ;
    USE SIGNAL ;
    PORT
      LAYER M5 ;
        RECT  42.624 107.916 42.648 108 ;
    END
  END hct5_b[74]
  PIN hct5_b[75]
    DIRECTION INPUT ;
    USE SIGNAL ;
    PORT
      LAYER M5 ;
        RECT  42.816 107.916 42.84 108 ;
    END
  END hct5_b[75]
  PIN hct5_b[76]
    DIRECTION INPUT ;
    USE SIGNAL ;
    PORT
      LAYER M5 ;
        RECT  43.008 107.916 43.032 108 ;
    END
  END hct5_b[76]
  PIN hct5_b[77]
    DIRECTION INPUT ;
    USE SIGNAL ;
    PORT
      LAYER M5 ;
        RECT  43.2 107.916 43.224 108 ;
    END
  END hct5_b[77]
  PIN hct5_b[78]
    DIRECTION INPUT ;
    USE SIGNAL ;
    PORT
      LAYER M5 ;
        RECT  43.392 107.916 43.416 108 ;
    END
  END hct5_b[78]
  PIN hct5_b[79]
    DIRECTION INPUT ;
    USE SIGNAL ;
    PORT
      LAYER M5 ;
        RECT  43.584 107.916 43.608 108 ;
    END
  END hct5_b[79]
  PIN hct5_b[7]
    DIRECTION INPUT ;
    USE SIGNAL ;
    PORT
      LAYER M5 ;
        RECT  47.424 107.916 47.448 108 ;
    END
  END hct5_b[7]
  PIN hct5_b[80]
    DIRECTION INPUT ;
    USE SIGNAL ;
    PORT
      LAYER M5 ;
        RECT  43.776 107.916 43.8 108 ;
    END
  END hct5_b[80]
  PIN hct5_b[81]
    DIRECTION INPUT ;
    USE SIGNAL ;
    PORT
      LAYER M5 ;
        RECT  43.968 107.916 43.992 108 ;
    END
  END hct5_b[81]
  PIN hct5_b[82]
    DIRECTION INPUT ;
    USE SIGNAL ;
    PORT
      LAYER M5 ;
        RECT  44.16 107.916 44.184 108 ;
    END
  END hct5_b[82]
  PIN hct5_b[83]
    DIRECTION INPUT ;
    USE SIGNAL ;
    PORT
      LAYER M5 ;
        RECT  44.352 107.916 44.376 108 ;
    END
  END hct5_b[83]
  PIN hct5_b[84]
    DIRECTION INPUT ;
    USE SIGNAL ;
    PORT
      LAYER M5 ;
        RECT  44.544 107.916 44.568 108 ;
    END
  END hct5_b[84]
  PIN hct5_b[85]
    DIRECTION INPUT ;
    USE SIGNAL ;
    PORT
      LAYER M5 ;
        RECT  44.736 107.916 44.76 108 ;
    END
  END hct5_b[85]
  PIN hct5_b[86]
    DIRECTION INPUT ;
    USE SIGNAL ;
    PORT
      LAYER M5 ;
        RECT  44.928 107.916 44.952 108 ;
    END
  END hct5_b[86]
  PIN hct5_b[87]
    DIRECTION INPUT ;
    USE SIGNAL ;
    PORT
      LAYER M5 ;
        RECT  45.12 107.916 45.144 108 ;
    END
  END hct5_b[87]
  PIN hct5_b[88]
    DIRECTION INPUT ;
    USE SIGNAL ;
    PORT
      LAYER M5 ;
        RECT  45.312 107.916 45.336 108 ;
    END
  END hct5_b[88]
  PIN hct5_b[89]
    DIRECTION INPUT ;
    USE SIGNAL ;
    PORT
      LAYER M5 ;
        RECT  45.504 107.916 45.528 108 ;
    END
  END hct5_b[89]
  PIN hct5_b[8]
    DIRECTION INPUT ;
    USE SIGNAL ;
    PORT
      LAYER M5 ;
        RECT  47.616 107.916 47.64 108 ;
    END
  END hct5_b[8]
  PIN hct5_b[90]
    DIRECTION INPUT ;
    USE SIGNAL ;
    PORT
      LAYER M5 ;
        RECT  45.696 107.916 45.72 108 ;
    END
  END hct5_b[90]
  PIN hct5_b[91]
    DIRECTION INPUT ;
    USE SIGNAL ;
    PORT
      LAYER M5 ;
        RECT  45.888 107.916 45.912 108 ;
    END
  END hct5_b[91]
  PIN hct5_b[92]
    DIRECTION INPUT ;
    USE SIGNAL ;
    PORT
      LAYER M5 ;
        RECT  46.08 107.916 46.104 108 ;
    END
  END hct5_b[92]
  PIN hct5_b[93]
    DIRECTION INPUT ;
    USE SIGNAL ;
    PORT
      LAYER M5 ;
        RECT  46.272 107.916 46.296 108 ;
    END
  END hct5_b[93]
  PIN hct5_b[94]
    DIRECTION INPUT ;
    USE SIGNAL ;
    PORT
      LAYER M5 ;
        RECT  46.464 107.916 46.488 108 ;
    END
  END hct5_b[94]
  PIN hct5_b[95]
    DIRECTION INPUT ;
    USE SIGNAL ;
    PORT
      LAYER M5 ;
        RECT  46.656 107.916 46.68 108 ;
    END
  END hct5_b[95]
  PIN hct5_b[96]
    DIRECTION INPUT ;
    USE SIGNAL ;
    PORT
      LAYER M5 ;
        RECT  46.848 107.916 46.872 108 ;
    END
  END hct5_b[96]
  PIN hct5_b[97]
    DIRECTION INPUT ;
    USE SIGNAL ;
    PORT
      LAYER M5 ;
        RECT  70.464 107.916 70.488 108 ;
    END
  END hct5_b[97]
  PIN hct5_b[98]
    DIRECTION INPUT ;
    USE SIGNAL ;
    PORT
      LAYER M5 ;
        RECT  70.656 107.916 70.68 108 ;
    END
  END hct5_b[98]
  PIN hct5_b[99]
    DIRECTION INPUT ;
    USE SIGNAL ;
    PORT
      LAYER M5 ;
        RECT  70.848 107.916 70.872 108 ;
    END
  END hct5_b[99]
  PIN hct5_b[9]
    DIRECTION INPUT ;
    USE SIGNAL ;
    PORT
      LAYER M5 ;
        RECT  47.808 107.916 47.832 108 ;
    END
  END hct5_b[9]
  PIN hct5_v
    DIRECTION INPUT ;
    USE SIGNAL ;
    PORT
      LAYER M5 ;
        RECT  269.616 107.916 269.64 108 ;
    END
  END hct5_v
  PIN hct_b[0]
    DIRECTION OUTPUT ;
    USE SIGNAL ;
    PORT
      LAYER M5 ;
        RECT  127.296 0 127.32 0.084 ;
    END
  END hct_b[0]
  PIN hct_b[100]
    DIRECTION OUTPUT ;
    USE SIGNAL ;
    PORT
      LAYER M5 ;
        RECT  130.176 0 130.2 0.084 ;
    END
  END hct_b[100]
  PIN hct_b[101]
    DIRECTION OUTPUT ;
    USE SIGNAL ;
    PORT
      LAYER M5 ;
        RECT  130.368 0 130.392 0.084 ;
    END
  END hct_b[101]
  PIN hct_b[102]
    DIRECTION OUTPUT ;
    USE SIGNAL ;
    PORT
      LAYER M5 ;
        RECT  130.56 0 130.584 0.084 ;
    END
  END hct_b[102]
  PIN hct_b[103]
    DIRECTION OUTPUT ;
    USE SIGNAL ;
    PORT
      LAYER M5 ;
        RECT  130.752 0 130.776 0.084 ;
    END
  END hct_b[103]
  PIN hct_b[104]
    DIRECTION OUTPUT ;
    USE SIGNAL ;
    PORT
      LAYER M5 ;
        RECT  130.944 0 130.968 0.084 ;
    END
  END hct_b[104]
  PIN hct_b[105]
    DIRECTION OUTPUT ;
    USE SIGNAL ;
    PORT
      LAYER M5 ;
        RECT  131.136 0 131.16 0.084 ;
    END
  END hct_b[105]
  PIN hct_b[106]
    DIRECTION OUTPUT ;
    USE SIGNAL ;
    PORT
      LAYER M5 ;
        RECT  131.328 0 131.352 0.084 ;
    END
  END hct_b[106]
  PIN hct_b[107]
    DIRECTION OUTPUT ;
    USE SIGNAL ;
    PORT
      LAYER M5 ;
        RECT  131.52 0 131.544 0.084 ;
    END
  END hct_b[107]
  PIN hct_b[108]
    DIRECTION OUTPUT ;
    USE SIGNAL ;
    PORT
      LAYER M5 ;
        RECT  131.712 0 131.736 0.084 ;
    END
  END hct_b[108]
  PIN hct_b[109]
    DIRECTION OUTPUT ;
    USE SIGNAL ;
    PORT
      LAYER M5 ;
        RECT  131.904 0 131.928 0.084 ;
    END
  END hct_b[109]
  PIN hct_b[10]
    DIRECTION OUTPUT ;
    USE SIGNAL ;
    PORT
      LAYER M5 ;
        RECT  135.36 0 135.384 0.084 ;
    END
  END hct_b[10]
  PIN hct_b[110]
    DIRECTION OUTPUT ;
    USE SIGNAL ;
    PORT
      LAYER M5 ;
        RECT  132.096 0 132.12 0.084 ;
    END
  END hct_b[110]
  PIN hct_b[111]
    DIRECTION OUTPUT ;
    USE SIGNAL ;
    PORT
      LAYER M5 ;
        RECT  132.288 0 132.312 0.084 ;
    END
  END hct_b[111]
  PIN hct_b[112]
    DIRECTION OUTPUT ;
    USE SIGNAL ;
    PORT
      LAYER M5 ;
        RECT  132.48 0 132.504 0.084 ;
    END
  END hct_b[112]
  PIN hct_b[113]
    DIRECTION OUTPUT ;
    USE SIGNAL ;
    PORT
      LAYER M5 ;
        RECT  132.672 0 132.696 0.084 ;
    END
  END hct_b[113]
  PIN hct_b[114]
    DIRECTION OUTPUT ;
    USE SIGNAL ;
    PORT
      LAYER M5 ;
        RECT  132.864 0 132.888 0.084 ;
    END
  END hct_b[114]
  PIN hct_b[115]
    DIRECTION OUTPUT ;
    USE SIGNAL ;
    PORT
      LAYER M5 ;
        RECT  133.056 0 133.08 0.084 ;
    END
  END hct_b[115]
  PIN hct_b[116]
    DIRECTION OUTPUT ;
    USE SIGNAL ;
    PORT
      LAYER M5 ;
        RECT  133.248 0 133.272 0.084 ;
    END
  END hct_b[116]
  PIN hct_b[117]
    DIRECTION OUTPUT ;
    USE SIGNAL ;
    PORT
      LAYER M5 ;
        RECT  133.44 0 133.464 0.084 ;
    END
  END hct_b[117]
  PIN hct_b[118]
    DIRECTION OUTPUT ;
    USE SIGNAL ;
    PORT
      LAYER M5 ;
        RECT  133.632 0 133.656 0.084 ;
    END
  END hct_b[118]
  PIN hct_b[119]
    DIRECTION OUTPUT ;
    USE SIGNAL ;
    PORT
      LAYER M5 ;
        RECT  137.856 0 137.88 0.084 ;
    END
  END hct_b[119]
  PIN hct_b[11]
    DIRECTION OUTPUT ;
    USE SIGNAL ;
    PORT
      LAYER M5 ;
        RECT  135.552 0 135.576 0.084 ;
    END
  END hct_b[11]
  PIN hct_b[120]
    DIRECTION OUTPUT ;
    USE SIGNAL ;
    PORT
      LAYER M5 ;
        RECT  138.048 0 138.072 0.084 ;
    END
  END hct_b[120]
  PIN hct_b[121]
    DIRECTION OUTPUT ;
    USE SIGNAL ;
    PORT
      LAYER M5 ;
        RECT  138.24 0 138.264 0.084 ;
    END
  END hct_b[121]
  PIN hct_b[122]
    DIRECTION OUTPUT ;
    USE SIGNAL ;
    PORT
      LAYER M5 ;
        RECT  138.432 0 138.456 0.084 ;
    END
  END hct_b[122]
  PIN hct_b[123]
    DIRECTION OUTPUT ;
    USE SIGNAL ;
    PORT
      LAYER M5 ;
        RECT  138.624 0 138.648 0.084 ;
    END
  END hct_b[123]
  PIN hct_b[124]
    DIRECTION OUTPUT ;
    USE SIGNAL ;
    PORT
      LAYER M5 ;
        RECT  138.816 0 138.84 0.084 ;
    END
  END hct_b[124]
  PIN hct_b[125]
    DIRECTION OUTPUT ;
    USE SIGNAL ;
    PORT
      LAYER M5 ;
        RECT  139.008 0 139.032 0.084 ;
    END
  END hct_b[125]
  PIN hct_b[126]
    DIRECTION OUTPUT ;
    USE SIGNAL ;
    PORT
      LAYER M5 ;
        RECT  139.2 0 139.224 0.084 ;
    END
  END hct_b[126]
  PIN hct_b[127]
    DIRECTION OUTPUT ;
    USE SIGNAL ;
    PORT
      LAYER M5 ;
        RECT  139.392 0 139.416 0.084 ;
    END
  END hct_b[127]
  PIN hct_b[128]
    DIRECTION OUTPUT ;
    USE SIGNAL ;
    PORT
      LAYER M5 ;
        RECT  139.584 0 139.608 0.084 ;
    END
  END hct_b[128]
  PIN hct_b[129]
    DIRECTION OUTPUT ;
    USE SIGNAL ;
    PORT
      LAYER M5 ;
        RECT  139.776 0 139.8 0.084 ;
    END
  END hct_b[129]
  PIN hct_b[12]
    DIRECTION OUTPUT ;
    USE SIGNAL ;
    PORT
      LAYER M5 ;
        RECT  135.744 0 135.768 0.084 ;
    END
  END hct_b[12]
  PIN hct_b[130]
    DIRECTION OUTPUT ;
    USE SIGNAL ;
    PORT
      LAYER M5 ;
        RECT  139.968 0 139.992 0.084 ;
    END
  END hct_b[130]
  PIN hct_b[131]
    DIRECTION OUTPUT ;
    USE SIGNAL ;
    PORT
      LAYER M5 ;
        RECT  140.16 0 140.184 0.084 ;
    END
  END hct_b[131]
  PIN hct_b[132]
    DIRECTION OUTPUT ;
    USE SIGNAL ;
    PORT
      LAYER M5 ;
        RECT  140.352 0 140.376 0.084 ;
    END
  END hct_b[132]
  PIN hct_b[133]
    DIRECTION OUTPUT ;
    USE SIGNAL ;
    PORT
      LAYER M5 ;
        RECT  140.544 0 140.568 0.084 ;
    END
  END hct_b[133]
  PIN hct_b[134]
    DIRECTION OUTPUT ;
    USE SIGNAL ;
    PORT
      LAYER M5 ;
        RECT  140.736 0 140.76 0.084 ;
    END
  END hct_b[134]
  PIN hct_b[135]
    DIRECTION OUTPUT ;
    USE SIGNAL ;
    PORT
      LAYER M5 ;
        RECT  140.928 0 140.952 0.084 ;
    END
  END hct_b[135]
  PIN hct_b[136]
    DIRECTION OUTPUT ;
    USE SIGNAL ;
    PORT
      LAYER M5 ;
        RECT  141.12 0 141.144 0.084 ;
    END
  END hct_b[136]
  PIN hct_b[137]
    DIRECTION OUTPUT ;
    USE SIGNAL ;
    PORT
      LAYER M5 ;
        RECT  141.312 0 141.336 0.084 ;
    END
  END hct_b[137]
  PIN hct_b[138]
    DIRECTION OUTPUT ;
    USE SIGNAL ;
    PORT
      LAYER M5 ;
        RECT  141.504 0 141.528 0.084 ;
    END
  END hct_b[138]
  PIN hct_b[139]
    DIRECTION OUTPUT ;
    USE SIGNAL ;
    PORT
      LAYER M5 ;
        RECT  141.696 0 141.72 0.084 ;
    END
  END hct_b[139]
  PIN hct_b[13]
    DIRECTION OUTPUT ;
    USE SIGNAL ;
    PORT
      LAYER M5 ;
        RECT  135.936 0 135.96 0.084 ;
    END
  END hct_b[13]
  PIN hct_b[140]
    DIRECTION OUTPUT ;
    USE SIGNAL ;
    PORT
      LAYER M5 ;
        RECT  141.888 0 141.912 0.084 ;
    END
  END hct_b[140]
  PIN hct_b[141]
    DIRECTION OUTPUT ;
    USE SIGNAL ;
    PORT
      LAYER M5 ;
        RECT  142.08 0 142.104 0.084 ;
    END
  END hct_b[141]
  PIN hct_b[142]
    DIRECTION OUTPUT ;
    USE SIGNAL ;
    PORT
      LAYER M5 ;
        RECT  142.272 0 142.296 0.084 ;
    END
  END hct_b[142]
  PIN hct_b[143]
    DIRECTION OUTPUT ;
    USE SIGNAL ;
    PORT
      LAYER M5 ;
        RECT  142.464 0 142.488 0.084 ;
    END
  END hct_b[143]
  PIN hct_b[144]
    DIRECTION OUTPUT ;
    USE SIGNAL ;
    PORT
      LAYER M5 ;
        RECT  142.656 0 142.68 0.084 ;
    END
  END hct_b[144]
  PIN hct_b[145]
    DIRECTION OUTPUT ;
    USE SIGNAL ;
    PORT
      LAYER M5 ;
        RECT  142.848 0 142.872 0.084 ;
    END
  END hct_b[145]
  PIN hct_b[146]
    DIRECTION OUTPUT ;
    USE SIGNAL ;
    PORT
      LAYER M5 ;
        RECT  143.04 0 143.064 0.084 ;
    END
  END hct_b[146]
  PIN hct_b[147]
    DIRECTION OUTPUT ;
    USE SIGNAL ;
    PORT
      LAYER M5 ;
        RECT  143.232 0 143.256 0.084 ;
    END
  END hct_b[147]
  PIN hct_b[148]
    DIRECTION OUTPUT ;
    USE SIGNAL ;
    PORT
      LAYER M5 ;
        RECT  143.424 0 143.448 0.084 ;
    END
  END hct_b[148]
  PIN hct_b[149]
    DIRECTION OUTPUT ;
    USE SIGNAL ;
    PORT
      LAYER M5 ;
        RECT  143.616 0 143.64 0.084 ;
    END
  END hct_b[149]
  PIN hct_b[14]
    DIRECTION OUTPUT ;
    USE SIGNAL ;
    PORT
      LAYER M5 ;
        RECT  136.128 0 136.152 0.084 ;
    END
  END hct_b[14]
  PIN hct_b[150]
    DIRECTION OUTPUT ;
    USE SIGNAL ;
    PORT
      LAYER M5 ;
        RECT  143.808 0 143.832 0.084 ;
    END
  END hct_b[150]
  PIN hct_b[151]
    DIRECTION OUTPUT ;
    USE SIGNAL ;
    PORT
      LAYER M5 ;
        RECT  150.144 0 150.168 0.084 ;
    END
  END hct_b[151]
  PIN hct_b[152]
    DIRECTION OUTPUT ;
    USE SIGNAL ;
    PORT
      LAYER M5 ;
        RECT  150.336 0 150.36 0.084 ;
    END
  END hct_b[152]
  PIN hct_b[153]
    DIRECTION OUTPUT ;
    USE SIGNAL ;
    PORT
      LAYER M5 ;
        RECT  150.528 0 150.552 0.084 ;
    END
  END hct_b[153]
  PIN hct_b[154]
    DIRECTION OUTPUT ;
    USE SIGNAL ;
    PORT
      LAYER M5 ;
        RECT  150.72 0 150.744 0.084 ;
    END
  END hct_b[154]
  PIN hct_b[155]
    DIRECTION OUTPUT ;
    USE SIGNAL ;
    PORT
      LAYER M5 ;
        RECT  150.912 0 150.936 0.084 ;
    END
  END hct_b[155]
  PIN hct_b[156]
    DIRECTION OUTPUT ;
    USE SIGNAL ;
    PORT
      LAYER M5 ;
        RECT  151.104 0 151.128 0.084 ;
    END
  END hct_b[156]
  PIN hct_b[157]
    DIRECTION OUTPUT ;
    USE SIGNAL ;
    PORT
      LAYER M5 ;
        RECT  151.296 0 151.32 0.084 ;
    END
  END hct_b[157]
  PIN hct_b[158]
    DIRECTION OUTPUT ;
    USE SIGNAL ;
    PORT
      LAYER M5 ;
        RECT  151.488 0 151.512 0.084 ;
    END
  END hct_b[158]
  PIN hct_b[159]
    DIRECTION OUTPUT ;
    USE SIGNAL ;
    PORT
      LAYER M5 ;
        RECT  151.68 0 151.704 0.084 ;
    END
  END hct_b[159]
  PIN hct_b[15]
    DIRECTION OUTPUT ;
    USE SIGNAL ;
    PORT
      LAYER M5 ;
        RECT  136.32 0 136.344 0.084 ;
    END
  END hct_b[15]
  PIN hct_b[160]
    DIRECTION OUTPUT ;
    USE SIGNAL ;
    PORT
      LAYER M5 ;
        RECT  151.872 0 151.896 0.084 ;
    END
  END hct_b[160]
  PIN hct_b[161]
    DIRECTION OUTPUT ;
    USE SIGNAL ;
    PORT
      LAYER M5 ;
        RECT  152.064 0 152.088 0.084 ;
    END
  END hct_b[161]
  PIN hct_b[162]
    DIRECTION OUTPUT ;
    USE SIGNAL ;
    PORT
      LAYER M5 ;
        RECT  152.256 0 152.28 0.084 ;
    END
  END hct_b[162]
  PIN hct_b[163]
    DIRECTION OUTPUT ;
    USE SIGNAL ;
    PORT
      LAYER M5 ;
        RECT  152.448 0 152.472 0.084 ;
    END
  END hct_b[163]
  PIN hct_b[164]
    DIRECTION OUTPUT ;
    USE SIGNAL ;
    PORT
      LAYER M5 ;
        RECT  152.64 0 152.664 0.084 ;
    END
  END hct_b[164]
  PIN hct_b[165]
    DIRECTION OUTPUT ;
    USE SIGNAL ;
    PORT
      LAYER M5 ;
        RECT  152.832 0 152.856 0.084 ;
    END
  END hct_b[165]
  PIN hct_b[166]
    DIRECTION OUTPUT ;
    USE SIGNAL ;
    PORT
      LAYER M5 ;
        RECT  153.024 0 153.048 0.084 ;
    END
  END hct_b[166]
  PIN hct_b[167]
    DIRECTION OUTPUT ;
    USE SIGNAL ;
    PORT
      LAYER M5 ;
        RECT  153.216 0 153.24 0.084 ;
    END
  END hct_b[167]
  PIN hct_b[168]
    DIRECTION OUTPUT ;
    USE SIGNAL ;
    PORT
      LAYER M5 ;
        RECT  153.408 0 153.432 0.084 ;
    END
  END hct_b[168]
  PIN hct_b[169]
    DIRECTION OUTPUT ;
    USE SIGNAL ;
    PORT
      LAYER M5 ;
        RECT  153.6 0 153.624 0.084 ;
    END
  END hct_b[169]
  PIN hct_b[16]
    DIRECTION OUTPUT ;
    USE SIGNAL ;
    PORT
      LAYER M5 ;
        RECT  136.512 0 136.536 0.084 ;
    END
  END hct_b[16]
  PIN hct_b[17]
    DIRECTION OUTPUT ;
    USE SIGNAL ;
    PORT
      LAYER M5 ;
        RECT  136.704 0 136.728 0.084 ;
    END
  END hct_b[17]
  PIN hct_b[18]
    DIRECTION OUTPUT ;
    USE SIGNAL ;
    PORT
      LAYER M5 ;
        RECT  136.896 0 136.92 0.084 ;
    END
  END hct_b[18]
  PIN hct_b[19]
    DIRECTION OUTPUT ;
    USE SIGNAL ;
    PORT
      LAYER M5 ;
        RECT  137.088 0 137.112 0.084 ;
    END
  END hct_b[19]
  PIN hct_b[1]
    DIRECTION OUTPUT ;
    USE SIGNAL ;
    PORT
      LAYER M5 ;
        RECT  127.488 0 127.512 0.084 ;
    END
  END hct_b[1]
  PIN hct_b[20]
    DIRECTION OUTPUT ;
    USE SIGNAL ;
    PORT
      LAYER M5 ;
        RECT  137.28 0 137.304 0.084 ;
    END
  END hct_b[20]
  PIN hct_b[21]
    DIRECTION OUTPUT ;
    USE SIGNAL ;
    PORT
      LAYER M5 ;
        RECT  137.472 0 137.496 0.084 ;
    END
  END hct_b[21]
  PIN hct_b[22]
    DIRECTION OUTPUT ;
    USE SIGNAL ;
    PORT
      LAYER M5 ;
        RECT  137.664 0 137.688 0.084 ;
    END
  END hct_b[22]
  PIN hct_b[23]
    DIRECTION OUTPUT ;
    USE SIGNAL ;
    PORT
      LAYER M5 ;
        RECT  116.928 0 116.952 0.084 ;
    END
  END hct_b[23]
  PIN hct_b[24]
    DIRECTION OUTPUT ;
    USE SIGNAL ;
    PORT
      LAYER M5 ;
        RECT  117.12 0 117.144 0.084 ;
    END
  END hct_b[24]
  PIN hct_b[25]
    DIRECTION OUTPUT ;
    USE SIGNAL ;
    PORT
      LAYER M5 ;
        RECT  117.312 0 117.336 0.084 ;
    END
  END hct_b[25]
  PIN hct_b[26]
    DIRECTION OUTPUT ;
    USE SIGNAL ;
    PORT
      LAYER M5 ;
        RECT  117.504 0 117.528 0.084 ;
    END
  END hct_b[26]
  PIN hct_b[27]
    DIRECTION OUTPUT ;
    USE SIGNAL ;
    PORT
      LAYER M5 ;
        RECT  117.696 0 117.72 0.084 ;
    END
  END hct_b[27]
  PIN hct_b[28]
    DIRECTION OUTPUT ;
    USE SIGNAL ;
    PORT
      LAYER M5 ;
        RECT  117.888 0 117.912 0.084 ;
    END
  END hct_b[28]
  PIN hct_b[29]
    DIRECTION OUTPUT ;
    USE SIGNAL ;
    PORT
      LAYER M5 ;
        RECT  118.08 0 118.104 0.084 ;
    END
  END hct_b[29]
  PIN hct_b[2]
    DIRECTION OUTPUT ;
    USE SIGNAL ;
    PORT
      LAYER M5 ;
        RECT  133.824 0 133.848 0.084 ;
    END
  END hct_b[2]
  PIN hct_b[30]
    DIRECTION OUTPUT ;
    USE SIGNAL ;
    PORT
      LAYER M5 ;
        RECT  118.272 0 118.296 0.084 ;
    END
  END hct_b[30]
  PIN hct_b[31]
    DIRECTION OUTPUT ;
    USE SIGNAL ;
    PORT
      LAYER M5 ;
        RECT  118.464 0 118.488 0.084 ;
    END
  END hct_b[31]
  PIN hct_b[32]
    DIRECTION OUTPUT ;
    USE SIGNAL ;
    PORT
      LAYER M5 ;
        RECT  118.656 0 118.68 0.084 ;
    END
  END hct_b[32]
  PIN hct_b[33]
    DIRECTION OUTPUT ;
    USE SIGNAL ;
    PORT
      LAYER M5 ;
        RECT  118.848 0 118.872 0.084 ;
    END
  END hct_b[33]
  PIN hct_b[34]
    DIRECTION OUTPUT ;
    USE SIGNAL ;
    PORT
      LAYER M5 ;
        RECT  119.04 0 119.064 0.084 ;
    END
  END hct_b[34]
  PIN hct_b[35]
    DIRECTION OUTPUT ;
    USE SIGNAL ;
    PORT
      LAYER M5 ;
        RECT  119.232 0 119.256 0.084 ;
    END
  END hct_b[35]
  PIN hct_b[36]
    DIRECTION OUTPUT ;
    USE SIGNAL ;
    PORT
      LAYER M5 ;
        RECT  119.424 0 119.448 0.084 ;
    END
  END hct_b[36]
  PIN hct_b[37]
    DIRECTION OUTPUT ;
    USE SIGNAL ;
    PORT
      LAYER M5 ;
        RECT  119.616 0 119.64 0.084 ;
    END
  END hct_b[37]
  PIN hct_b[38]
    DIRECTION OUTPUT ;
    USE SIGNAL ;
    PORT
      LAYER M5 ;
        RECT  119.808 0 119.832 0.084 ;
    END
  END hct_b[38]
  PIN hct_b[39]
    DIRECTION OUTPUT ;
    USE SIGNAL ;
    PORT
      LAYER M5 ;
        RECT  120 0 120.024 0.084 ;
    END
  END hct_b[39]
  PIN hct_b[3]
    DIRECTION OUTPUT ;
    USE SIGNAL ;
    PORT
      LAYER M5 ;
        RECT  134.016 0 134.04 0.084 ;
    END
  END hct_b[3]
  PIN hct_b[40]
    DIRECTION OUTPUT ;
    USE SIGNAL ;
    PORT
      LAYER M5 ;
        RECT  120.192 0 120.216 0.084 ;
    END
  END hct_b[40]
  PIN hct_b[41]
    DIRECTION OUTPUT ;
    USE SIGNAL ;
    PORT
      LAYER M5 ;
        RECT  120.384 0 120.408 0.084 ;
    END
  END hct_b[41]
  PIN hct_b[42]
    DIRECTION OUTPUT ;
    USE SIGNAL ;
    PORT
      LAYER M5 ;
        RECT  120.576 0 120.6 0.084 ;
    END
  END hct_b[42]
  PIN hct_b[43]
    DIRECTION OUTPUT ;
    USE SIGNAL ;
    PORT
      LAYER M5 ;
        RECT  120.768 0 120.792 0.084 ;
    END
  END hct_b[43]
  PIN hct_b[44]
    DIRECTION OUTPUT ;
    USE SIGNAL ;
    PORT
      LAYER M5 ;
        RECT  120.96 0 120.984 0.084 ;
    END
  END hct_b[44]
  PIN hct_b[45]
    DIRECTION OUTPUT ;
    USE SIGNAL ;
    PORT
      LAYER M5 ;
        RECT  121.152 0 121.176 0.084 ;
    END
  END hct_b[45]
  PIN hct_b[46]
    DIRECTION OUTPUT ;
    USE SIGNAL ;
    PORT
      LAYER M5 ;
        RECT  121.344 0 121.368 0.084 ;
    END
  END hct_b[46]
  PIN hct_b[47]
    DIRECTION OUTPUT ;
    USE SIGNAL ;
    PORT
      LAYER M5 ;
        RECT  121.536 0 121.56 0.084 ;
    END
  END hct_b[47]
  PIN hct_b[48]
    DIRECTION OUTPUT ;
    USE SIGNAL ;
    PORT
      LAYER M5 ;
        RECT  121.728 0 121.752 0.084 ;
    END
  END hct_b[48]
  PIN hct_b[49]
    DIRECTION OUTPUT ;
    USE SIGNAL ;
    PORT
      LAYER M5 ;
        RECT  121.92 0 121.944 0.084 ;
    END
  END hct_b[49]
  PIN hct_b[4]
    DIRECTION OUTPUT ;
    USE SIGNAL ;
    PORT
      LAYER M5 ;
        RECT  134.208 0 134.232 0.084 ;
    END
  END hct_b[4]
  PIN hct_b[50]
    DIRECTION OUTPUT ;
    USE SIGNAL ;
    PORT
      LAYER M5 ;
        RECT  122.112 0 122.136 0.084 ;
    END
  END hct_b[50]
  PIN hct_b[51]
    DIRECTION OUTPUT ;
    USE SIGNAL ;
    PORT
      LAYER M5 ;
        RECT  122.304 0 122.328 0.084 ;
    END
  END hct_b[51]
  PIN hct_b[52]
    DIRECTION OUTPUT ;
    USE SIGNAL ;
    PORT
      LAYER M5 ;
        RECT  122.496 0 122.52 0.084 ;
    END
  END hct_b[52]
  PIN hct_b[53]
    DIRECTION OUTPUT ;
    USE SIGNAL ;
    PORT
      LAYER M5 ;
        RECT  122.688 0 122.712 0.084 ;
    END
  END hct_b[53]
  PIN hct_b[54]
    DIRECTION OUTPUT ;
    USE SIGNAL ;
    PORT
      LAYER M5 ;
        RECT  122.88 0 122.904 0.084 ;
    END
  END hct_b[54]
  PIN hct_b[55]
    DIRECTION OUTPUT ;
    USE SIGNAL ;
    PORT
      LAYER M5 ;
        RECT  110.784 0 110.808 0.084 ;
    END
  END hct_b[55]
  PIN hct_b[56]
    DIRECTION OUTPUT ;
    USE SIGNAL ;
    PORT
      LAYER M5 ;
        RECT  110.976 0 111 0.084 ;
    END
  END hct_b[56]
  PIN hct_b[57]
    DIRECTION OUTPUT ;
    USE SIGNAL ;
    PORT
      LAYER M5 ;
        RECT  111.168 0 111.192 0.084 ;
    END
  END hct_b[57]
  PIN hct_b[58]
    DIRECTION OUTPUT ;
    USE SIGNAL ;
    PORT
      LAYER M5 ;
        RECT  111.36 0 111.384 0.084 ;
    END
  END hct_b[58]
  PIN hct_b[59]
    DIRECTION OUTPUT ;
    USE SIGNAL ;
    PORT
      LAYER M5 ;
        RECT  111.552 0 111.576 0.084 ;
    END
  END hct_b[59]
  PIN hct_b[5]
    DIRECTION OUTPUT ;
    USE SIGNAL ;
    PORT
      LAYER M5 ;
        RECT  134.4 0 134.424 0.084 ;
    END
  END hct_b[5]
  PIN hct_b[60]
    DIRECTION OUTPUT ;
    USE SIGNAL ;
    PORT
      LAYER M5 ;
        RECT  111.744 0 111.768 0.084 ;
    END
  END hct_b[60]
  PIN hct_b[61]
    DIRECTION OUTPUT ;
    USE SIGNAL ;
    PORT
      LAYER M5 ;
        RECT  111.936 0 111.96 0.084 ;
    END
  END hct_b[61]
  PIN hct_b[62]
    DIRECTION OUTPUT ;
    USE SIGNAL ;
    PORT
      LAYER M5 ;
        RECT  112.128 0 112.152 0.084 ;
    END
  END hct_b[62]
  PIN hct_b[63]
    DIRECTION OUTPUT ;
    USE SIGNAL ;
    PORT
      LAYER M5 ;
        RECT  112.32 0 112.344 0.084 ;
    END
  END hct_b[63]
  PIN hct_b[64]
    DIRECTION OUTPUT ;
    USE SIGNAL ;
    PORT
      LAYER M5 ;
        RECT  112.512 0 112.536 0.084 ;
    END
  END hct_b[64]
  PIN hct_b[65]
    DIRECTION OUTPUT ;
    USE SIGNAL ;
    PORT
      LAYER M5 ;
        RECT  112.704 0 112.728 0.084 ;
    END
  END hct_b[65]
  PIN hct_b[66]
    DIRECTION OUTPUT ;
    USE SIGNAL ;
    PORT
      LAYER M5 ;
        RECT  112.896 0 112.92 0.084 ;
    END
  END hct_b[66]
  PIN hct_b[67]
    DIRECTION OUTPUT ;
    USE SIGNAL ;
    PORT
      LAYER M5 ;
        RECT  113.088 0 113.112 0.084 ;
    END
  END hct_b[67]
  PIN hct_b[68]
    DIRECTION OUTPUT ;
    USE SIGNAL ;
    PORT
      LAYER M5 ;
        RECT  113.28 0 113.304 0.084 ;
    END
  END hct_b[68]
  PIN hct_b[69]
    DIRECTION OUTPUT ;
    USE SIGNAL ;
    PORT
      LAYER M5 ;
        RECT  113.472 0 113.496 0.084 ;
    END
  END hct_b[69]
  PIN hct_b[6]
    DIRECTION OUTPUT ;
    USE SIGNAL ;
    PORT
      LAYER M5 ;
        RECT  134.592 0 134.616 0.084 ;
    END
  END hct_b[6]
  PIN hct_b[70]
    DIRECTION OUTPUT ;
    USE SIGNAL ;
    PORT
      LAYER M5 ;
        RECT  113.664 0 113.688 0.084 ;
    END
  END hct_b[70]
  PIN hct_b[71]
    DIRECTION OUTPUT ;
    USE SIGNAL ;
    PORT
      LAYER M5 ;
        RECT  113.856 0 113.88 0.084 ;
    END
  END hct_b[71]
  PIN hct_b[72]
    DIRECTION OUTPUT ;
    USE SIGNAL ;
    PORT
      LAYER M5 ;
        RECT  114.048 0 114.072 0.084 ;
    END
  END hct_b[72]
  PIN hct_b[73]
    DIRECTION OUTPUT ;
    USE SIGNAL ;
    PORT
      LAYER M5 ;
        RECT  114.24 0 114.264 0.084 ;
    END
  END hct_b[73]
  PIN hct_b[74]
    DIRECTION OUTPUT ;
    USE SIGNAL ;
    PORT
      LAYER M5 ;
        RECT  114.432 0 114.456 0.084 ;
    END
  END hct_b[74]
  PIN hct_b[75]
    DIRECTION OUTPUT ;
    USE SIGNAL ;
    PORT
      LAYER M5 ;
        RECT  114.624 0 114.648 0.084 ;
    END
  END hct_b[75]
  PIN hct_b[76]
    DIRECTION OUTPUT ;
    USE SIGNAL ;
    PORT
      LAYER M5 ;
        RECT  114.816 0 114.84 0.084 ;
    END
  END hct_b[76]
  PIN hct_b[77]
    DIRECTION OUTPUT ;
    USE SIGNAL ;
    PORT
      LAYER M5 ;
        RECT  115.008 0 115.032 0.084 ;
    END
  END hct_b[77]
  PIN hct_b[78]
    DIRECTION OUTPUT ;
    USE SIGNAL ;
    PORT
      LAYER M5 ;
        RECT  115.2 0 115.224 0.084 ;
    END
  END hct_b[78]
  PIN hct_b[79]
    DIRECTION OUTPUT ;
    USE SIGNAL ;
    PORT
      LAYER M5 ;
        RECT  115.392 0 115.416 0.084 ;
    END
  END hct_b[79]
  PIN hct_b[7]
    DIRECTION OUTPUT ;
    USE SIGNAL ;
    PORT
      LAYER M5 ;
        RECT  134.784 0 134.808 0.084 ;
    END
  END hct_b[7]
  PIN hct_b[80]
    DIRECTION OUTPUT ;
    USE SIGNAL ;
    PORT
      LAYER M5 ;
        RECT  115.584 0 115.608 0.084 ;
    END
  END hct_b[80]
  PIN hct_b[81]
    DIRECTION OUTPUT ;
    USE SIGNAL ;
    PORT
      LAYER M5 ;
        RECT  115.776 0 115.8 0.084 ;
    END
  END hct_b[81]
  PIN hct_b[82]
    DIRECTION OUTPUT ;
    USE SIGNAL ;
    PORT
      LAYER M5 ;
        RECT  115.968 0 115.992 0.084 ;
    END
  END hct_b[82]
  PIN hct_b[83]
    DIRECTION OUTPUT ;
    USE SIGNAL ;
    PORT
      LAYER M5 ;
        RECT  116.16 0 116.184 0.084 ;
    END
  END hct_b[83]
  PIN hct_b[84]
    DIRECTION OUTPUT ;
    USE SIGNAL ;
    PORT
      LAYER M5 ;
        RECT  116.352 0 116.376 0.084 ;
    END
  END hct_b[84]
  PIN hct_b[85]
    DIRECTION OUTPUT ;
    USE SIGNAL ;
    PORT
      LAYER M5 ;
        RECT  116.544 0 116.568 0.084 ;
    END
  END hct_b[85]
  PIN hct_b[86]
    DIRECTION OUTPUT ;
    USE SIGNAL ;
    PORT
      LAYER M5 ;
        RECT  116.736 0 116.76 0.084 ;
    END
  END hct_b[86]
  PIN hct_b[87]
    DIRECTION OUTPUT ;
    USE SIGNAL ;
    PORT
      LAYER M5 ;
        RECT  127.68 0 127.704 0.084 ;
    END
  END hct_b[87]
  PIN hct_b[88]
    DIRECTION OUTPUT ;
    USE SIGNAL ;
    PORT
      LAYER M5 ;
        RECT  127.872 0 127.896 0.084 ;
    END
  END hct_b[88]
  PIN hct_b[89]
    DIRECTION OUTPUT ;
    USE SIGNAL ;
    PORT
      LAYER M5 ;
        RECT  128.064 0 128.088 0.084 ;
    END
  END hct_b[89]
  PIN hct_b[8]
    DIRECTION OUTPUT ;
    USE SIGNAL ;
    PORT
      LAYER M5 ;
        RECT  134.976 0 135 0.084 ;
    END
  END hct_b[8]
  PIN hct_b[90]
    DIRECTION OUTPUT ;
    USE SIGNAL ;
    PORT
      LAYER M5 ;
        RECT  128.256 0 128.28 0.084 ;
    END
  END hct_b[90]
  PIN hct_b[91]
    DIRECTION OUTPUT ;
    USE SIGNAL ;
    PORT
      LAYER M5 ;
        RECT  128.448 0 128.472 0.084 ;
    END
  END hct_b[91]
  PIN hct_b[92]
    DIRECTION OUTPUT ;
    USE SIGNAL ;
    PORT
      LAYER M5 ;
        RECT  128.64 0 128.664 0.084 ;
    END
  END hct_b[92]
  PIN hct_b[93]
    DIRECTION OUTPUT ;
    USE SIGNAL ;
    PORT
      LAYER M5 ;
        RECT  128.832 0 128.856 0.084 ;
    END
  END hct_b[93]
  PIN hct_b[94]
    DIRECTION OUTPUT ;
    USE SIGNAL ;
    PORT
      LAYER M5 ;
        RECT  129.024 0 129.048 0.084 ;
    END
  END hct_b[94]
  PIN hct_b[95]
    DIRECTION OUTPUT ;
    USE SIGNAL ;
    PORT
      LAYER M5 ;
        RECT  129.216 0 129.24 0.084 ;
    END
  END hct_b[95]
  PIN hct_b[96]
    DIRECTION OUTPUT ;
    USE SIGNAL ;
    PORT
      LAYER M5 ;
        RECT  129.408 0 129.432 0.084 ;
    END
  END hct_b[96]
  PIN hct_b[97]
    DIRECTION OUTPUT ;
    USE SIGNAL ;
    PORT
      LAYER M5 ;
        RECT  129.6 0 129.624 0.084 ;
    END
  END hct_b[97]
  PIN hct_b[98]
    DIRECTION OUTPUT ;
    USE SIGNAL ;
    PORT
      LAYER M5 ;
        RECT  129.792 0 129.816 0.084 ;
    END
  END hct_b[98]
  PIN hct_b[99]
    DIRECTION OUTPUT ;
    USE SIGNAL ;
    PORT
      LAYER M5 ;
        RECT  129.984 0 130.008 0.084 ;
    END
  END hct_b[99]
  PIN hct_b[9]
    DIRECTION OUTPUT ;
    USE SIGNAL ;
    PORT
      LAYER M5 ;
        RECT  135.168 0 135.192 0.084 ;
    END
  END hct_b[9]
  PIN hct_v
    DIRECTION OUTPUT ;
    USE SIGNAL ;
    PORT
      LAYER M5 ;
        RECT  287.232 0 287.256 0.084 ;
    END
  END hct_v
  PIN j_lm[0]
    DIRECTION INPUT ;
    USE SIGNAL ;
    PORT
      LAYER M5 ;
        RECT  287.424 0 287.448 0.084 ;
    END
  END j_lm[0]
  PIN j_lm[1]
    DIRECTION INPUT ;
    USE SIGNAL ;
    PORT
      LAYER M5 ;
        RECT  287.616 0 287.64 0.084 ;
    END
  END j_lm[1]
  PIN j_lm[2]
    DIRECTION INPUT ;
    USE SIGNAL ;
    PORT
      LAYER M5 ;
        RECT  287.808 0 287.832 0.084 ;
    END
  END j_lm[2]
  PIN j_lm[3]
    DIRECTION INPUT ;
    USE SIGNAL ;
    PORT
      LAYER M5 ;
        RECT  288 0 288.024 0.084 ;
    END
  END j_lm[3]
  PIN j_lm[4]
    DIRECTION INPUT ;
    USE SIGNAL ;
    PORT
      LAYER M5 ;
        RECT  288.192 0 288.216 0.084 ;
    END
  END j_lm[4]
  PIN j_row[0]
    DIRECTION INPUT ;
    USE SIGNAL ;
    PORT
      LAYER M5 ;
        RECT  288.384 0 288.408 0.084 ;
    END
  END j_row[0]
  PIN j_row[1]
    DIRECTION INPUT ;
    USE SIGNAL ;
    PORT
      LAYER M5 ;
        RECT  288.576 0 288.6 0.084 ;
    END
  END j_row[1]
  PIN j_row[2]
    DIRECTION INPUT ;
    USE SIGNAL ;
    PORT
      LAYER M5 ;
        RECT  288.768 0 288.792 0.084 ;
    END
  END j_row[2]
  PIN j_row[3]
    DIRECTION INPUT ;
    USE SIGNAL ;
    PORT
      LAYER M5 ;
        RECT  288.96 0 288.984 0.084 ;
    END
  END j_row[3]
  PIN j_row[4]
    DIRECTION INPUT ;
    USE SIGNAL ;
    PORT
      LAYER M5 ;
        RECT  289.152 0 289.176 0.084 ;
    END
  END j_row[4]
  PIN j_row[5]
    DIRECTION INPUT ;
    USE SIGNAL ;
    PORT
      LAYER M5 ;
        RECT  289.344 0 289.368 0.084 ;
    END
  END j_row[5]
  PIN j_row[6]
    DIRECTION INPUT ;
    USE SIGNAL ;
    PORT
      LAYER M5 ;
        RECT  289.536 0 289.56 0.084 ;
    END
  END j_row[6]
  PIN j_row[7]
    DIRECTION INPUT ;
    USE SIGNAL ;
    PORT
      LAYER M5 ;
        RECT  289.728 0 289.752 0.084 ;
    END
  END j_row[7]
  PIN j_row[8]
    DIRECTION INPUT ;
    USE SIGNAL ;
    PORT
      LAYER M5 ;
        RECT  289.92 0 289.944 0.084 ;
    END
  END j_row[8]
  PIN j_row[9]
    DIRECTION INPUT ;
    USE SIGNAL ;
    PORT
      LAYER M5 ;
        RECT  290.112 0 290.136 0.084 ;
    END
  END j_row[9]
  PIN j_set
    DIRECTION INPUT ;
    USE SIGNAL ;
    PORT
      LAYER M5 ;
        RECT  290.304 0 290.328 0.084 ;
    END
  END j_set
  PIN j_sm[0]
    DIRECTION INPUT ;
    USE SIGNAL ;
    PORT
      LAYER M5 ;
        RECT  290.496 0 290.52 0.084 ;
    END
  END j_sm[0]
  PIN j_sm[10]
    DIRECTION INPUT ;
    USE SIGNAL ;
    PORT
      LAYER M5 ;
        RECT  237.36 0 237.384 0.084 ;
    END
  END j_sm[10]
  PIN j_sm[11]
    DIRECTION INPUT ;
    USE SIGNAL ;
    PORT
      LAYER M5 ;
        RECT  237.552 0 237.576 0.084 ;
    END
  END j_sm[11]
  PIN j_sm[12]
    DIRECTION INPUT ;
    USE SIGNAL ;
    PORT
      LAYER M5 ;
        RECT  237.744 0 237.768 0.084 ;
    END
  END j_sm[12]
  PIN j_sm[13]
    DIRECTION INPUT ;
    USE SIGNAL ;
    PORT
      LAYER M5 ;
        RECT  237.936 0 237.96 0.084 ;
    END
  END j_sm[13]
  PIN j_sm[14]
    DIRECTION INPUT ;
    USE SIGNAL ;
    PORT
      LAYER M5 ;
        RECT  238.128 0 238.152 0.084 ;
    END
  END j_sm[14]
  PIN j_sm[15]
    DIRECTION INPUT ;
    USE SIGNAL ;
    PORT
      LAYER M5 ;
        RECT  238.32 0 238.344 0.084 ;
    END
  END j_sm[15]
  PIN j_sm[1]
    DIRECTION INPUT ;
    USE SIGNAL ;
    PORT
      LAYER M5 ;
        RECT  290.688 0 290.712 0.084 ;
    END
  END j_sm[1]
  PIN j_sm[2]
    DIRECTION INPUT ;
    USE SIGNAL ;
    PORT
      LAYER M5 ;
        RECT  290.88 0 290.904 0.084 ;
    END
  END j_sm[2]
  PIN j_sm[3]
    DIRECTION INPUT ;
    USE SIGNAL ;
    PORT
      LAYER M5 ;
        RECT  291.072 0 291.096 0.084 ;
    END
  END j_sm[3]
  PIN j_sm[4]
    DIRECTION INPUT ;
    USE SIGNAL ;
    PORT
      LAYER M5 ;
        RECT  291.264 0 291.288 0.084 ;
    END
  END j_sm[4]
  PIN j_sm[5]
    DIRECTION INPUT ;
    USE SIGNAL ;
    PORT
      LAYER M5 ;
        RECT  236.4 0 236.424 0.084 ;
    END
  END j_sm[5]
  PIN j_sm[6]
    DIRECTION INPUT ;
    USE SIGNAL ;
    PORT
      LAYER M5 ;
        RECT  236.592 0 236.616 0.084 ;
    END
  END j_sm[6]
  PIN j_sm[7]
    DIRECTION INPUT ;
    USE SIGNAL ;
    PORT
      LAYER M5 ;
        RECT  236.784 0 236.808 0.084 ;
    END
  END j_sm[7]
  PIN j_sm[8]
    DIRECTION INPUT ;
    USE SIGNAL ;
    PORT
      LAYER M5 ;
        RECT  236.976 0 237 0.084 ;
    END
  END j_sm[8]
  PIN j_sm[9]
    DIRECTION INPUT ;
    USE SIGNAL ;
    PORT
      LAYER M5 ;
        RECT  237.168 0 237.192 0.084 ;
    END
  END j_sm[9]
  PIN j_v
    DIRECTION INPUT ;
    USE SIGNAL ;
    PORT
      LAYER M5 ;
        RECT  238.512 0 238.536 0.084 ;
    END
  END j_v
  PIN j_w
    DIRECTION INPUT ;
    USE SIGNAL ;
    PORT
      LAYER M5 ;
        RECT  238.704 0 238.728 0.084 ;
    END
  END j_w
  PIN launch
    DIRECTION OUTPUT ;
    USE SIGNAL ;
    PORT
      LAYER M5 ;
        RECT  269.808 107.916 269.832 108 ;
    END
  END launch
  PIN launch_s
    DIRECTION OUTPUT ;
    USE SIGNAL ;
    PORT
      LAYER M5 ;
        RECT  238.896 0 238.92 0.084 ;
    END
  END launch_s
  PIN mix_go_s
    DIRECTION OUTPUT ;
    USE SIGNAL ;
    PORT
      LAYER M5 ;
        RECT  239.088 0 239.112 0.084 ;
    END
  END mix_go_s
  PIN mx_i[0]
    DIRECTION OUTPUT ;
    USE SIGNAL ;
    PORT
      LAYER M5 ;
        RECT  270 107.916 270.024 108 ;
    END
  END mx_i[0]
  PIN mx_i[1]
    DIRECTION OUTPUT ;
    USE SIGNAL ;
    PORT
      LAYER M5 ;
        RECT  270.192 107.916 270.216 108 ;
    END
  END mx_i[1]
  PIN mx_i[2]
    DIRECTION OUTPUT ;
    USE SIGNAL ;
    PORT
      LAYER M5 ;
        RECT  270.384 107.916 270.408 108 ;
    END
  END mx_i[2]
  PIN mx_i[3]
    DIRECTION OUTPUT ;
    USE SIGNAL ;
    PORT
      LAYER M5 ;
        RECT  270.576 107.916 270.6 108 ;
    END
  END mx_i[3]
  PIN mx_i[4]
    DIRECTION OUTPUT ;
    USE SIGNAL ;
    PORT
      LAYER M5 ;
        RECT  270.768 107.916 270.792 108 ;
    END
  END mx_i[4]
  PIN mx_v
    DIRECTION OUTPUT ;
    USE SIGNAL ;
    PORT
      LAYER M5 ;
        RECT  270.96 107.916 270.984 108 ;
    END
  END mx_v
  PIN mx_y[0]
    DIRECTION OUTPUT ;
    USE SIGNAL ;
    PORT
      LAYER M5 ;
        RECT  271.152 107.916 271.176 108 ;
    END
  END mx_y[0]
  PIN mx_y[10]
    DIRECTION OUTPUT ;
    USE SIGNAL ;
    PORT
      LAYER M5 ;
        RECT  273.072 107.916 273.096 108 ;
    END
  END mx_y[10]
  PIN mx_y[11]
    DIRECTION OUTPUT ;
    USE SIGNAL ;
    PORT
      LAYER M5 ;
        RECT  273.264 107.916 273.288 108 ;
    END
  END mx_y[11]
  PIN mx_y[12]
    DIRECTION OUTPUT ;
    USE SIGNAL ;
    PORT
      LAYER M5 ;
        RECT  273.456 107.916 273.48 108 ;
    END
  END mx_y[12]
  PIN mx_y[13]
    DIRECTION OUTPUT ;
    USE SIGNAL ;
    PORT
      LAYER M5 ;
        RECT  273.648 107.916 273.672 108 ;
    END
  END mx_y[13]
  PIN mx_y[14]
    DIRECTION OUTPUT ;
    USE SIGNAL ;
    PORT
      LAYER M5 ;
        RECT  273.84 107.916 273.864 108 ;
    END
  END mx_y[14]
  PIN mx_y[15]
    DIRECTION OUTPUT ;
    USE SIGNAL ;
    PORT
      LAYER M5 ;
        RECT  274.032 107.916 274.056 108 ;
    END
  END mx_y[15]
  PIN mx_y[16]
    DIRECTION OUTPUT ;
    USE SIGNAL ;
    PORT
      LAYER M5 ;
        RECT  274.224 107.916 274.248 108 ;
    END
  END mx_y[16]
  PIN mx_y[17]
    DIRECTION OUTPUT ;
    USE SIGNAL ;
    PORT
      LAYER M5 ;
        RECT  274.416 107.916 274.44 108 ;
    END
  END mx_y[17]
  PIN mx_y[18]
    DIRECTION OUTPUT ;
    USE SIGNAL ;
    PORT
      LAYER M5 ;
        RECT  274.608 107.916 274.632 108 ;
    END
  END mx_y[18]
  PIN mx_y[19]
    DIRECTION OUTPUT ;
    USE SIGNAL ;
    PORT
      LAYER M5 ;
        RECT  274.8 107.916 274.824 108 ;
    END
  END mx_y[19]
  PIN mx_y[1]
    DIRECTION OUTPUT ;
    USE SIGNAL ;
    PORT
      LAYER M5 ;
        RECT  271.344 107.916 271.368 108 ;
    END
  END mx_y[1]
  PIN mx_y[20]
    DIRECTION OUTPUT ;
    USE SIGNAL ;
    PORT
      LAYER M5 ;
        RECT  274.992 107.916 275.016 108 ;
    END
  END mx_y[20]
  PIN mx_y[21]
    DIRECTION OUTPUT ;
    USE SIGNAL ;
    PORT
      LAYER M5 ;
        RECT  275.184 107.916 275.208 108 ;
    END
  END mx_y[21]
  PIN mx_y[22]
    DIRECTION OUTPUT ;
    USE SIGNAL ;
    PORT
      LAYER M5 ;
        RECT  275.376 107.916 275.4 108 ;
    END
  END mx_y[22]
  PIN mx_y[23]
    DIRECTION OUTPUT ;
    USE SIGNAL ;
    PORT
      LAYER M5 ;
        RECT  275.568 107.916 275.592 108 ;
    END
  END mx_y[23]
  PIN mx_y[24]
    DIRECTION OUTPUT ;
    USE SIGNAL ;
    PORT
      LAYER M5 ;
        RECT  95.664 107.916 95.688 108 ;
    END
  END mx_y[24]
  PIN mx_y[25]
    DIRECTION OUTPUT ;
    USE SIGNAL ;
    PORT
      LAYER M5 ;
        RECT  95.856 107.916 95.88 108 ;
    END
  END mx_y[25]
  PIN mx_y[26]
    DIRECTION OUTPUT ;
    USE SIGNAL ;
    PORT
      LAYER M5 ;
        RECT  96.048 107.916 96.072 108 ;
    END
  END mx_y[26]
  PIN mx_y[27]
    DIRECTION OUTPUT ;
    USE SIGNAL ;
    PORT
      LAYER M5 ;
        RECT  96.24 107.916 96.264 108 ;
    END
  END mx_y[27]
  PIN mx_y[28]
    DIRECTION OUTPUT ;
    USE SIGNAL ;
    PORT
      LAYER M5 ;
        RECT  96.432 107.916 96.456 108 ;
    END
  END mx_y[28]
  PIN mx_y[29]
    DIRECTION OUTPUT ;
    USE SIGNAL ;
    PORT
      LAYER M5 ;
        RECT  96.624 107.916 96.648 108 ;
    END
  END mx_y[29]
  PIN mx_y[2]
    DIRECTION OUTPUT ;
    USE SIGNAL ;
    PORT
      LAYER M5 ;
        RECT  271.536 107.916 271.56 108 ;
    END
  END mx_y[2]
  PIN mx_y[30]
    DIRECTION OUTPUT ;
    USE SIGNAL ;
    PORT
      LAYER M5 ;
        RECT  96.816 107.916 96.84 108 ;
    END
  END mx_y[30]
  PIN mx_y[31]
    DIRECTION OUTPUT ;
    USE SIGNAL ;
    PORT
      LAYER M5 ;
        RECT  97.008 107.916 97.032 108 ;
    END
  END mx_y[31]
  PIN mx_y[3]
    DIRECTION OUTPUT ;
    USE SIGNAL ;
    PORT
      LAYER M5 ;
        RECT  271.728 107.916 271.752 108 ;
    END
  END mx_y[3]
  PIN mx_y[4]
    DIRECTION OUTPUT ;
    USE SIGNAL ;
    PORT
      LAYER M5 ;
        RECT  271.92 107.916 271.944 108 ;
    END
  END mx_y[4]
  PIN mx_y[5]
    DIRECTION OUTPUT ;
    USE SIGNAL ;
    PORT
      LAYER M5 ;
        RECT  272.112 107.916 272.136 108 ;
    END
  END mx_y[5]
  PIN mx_y[6]
    DIRECTION OUTPUT ;
    USE SIGNAL ;
    PORT
      LAYER M5 ;
        RECT  272.304 107.916 272.328 108 ;
    END
  END mx_y[6]
  PIN mx_y[7]
    DIRECTION OUTPUT ;
    USE SIGNAL ;
    PORT
      LAYER M5 ;
        RECT  272.496 107.916 272.52 108 ;
    END
  END mx_y[7]
  PIN mx_y[8]
    DIRECTION OUTPUT ;
    USE SIGNAL ;
    PORT
      LAYER M5 ;
        RECT  272.688 107.916 272.712 108 ;
    END
  END mx_y[8]
  PIN mx_y[9]
    DIRECTION OUTPUT ;
    USE SIGNAL ;
    PORT
      LAYER M5 ;
        RECT  272.88 107.916 272.904 108 ;
    END
  END mx_y[9]
  PIN r_f
    DIRECTION INPUT ;
    USE SIGNAL ;
    PORT
      LAYER M4 ;
        RECT  302.316 6.816 302.4 6.84 ;
    END
  END r_f
  PIN r_v
    DIRECTION INPUT ;
    USE SIGNAL ;
    PORT
      LAYER M4 ;
        RECT  302.316 7.008 302.4 7.032 ;
    END
  END r_v
  PIN r_y[0]
    DIRECTION INPUT ;
    USE SIGNAL ;
    PORT
      LAYER M4 ;
        RECT  302.316 7.2 302.4 7.224 ;
    END
  END r_y[0]
  PIN r_y[10]
    DIRECTION INPUT ;
    USE SIGNAL ;
    PORT
      LAYER M4 ;
        RECT  302.316 9.168 302.4 9.192 ;
    END
  END r_y[10]
  PIN r_y[11]
    DIRECTION INPUT ;
    USE SIGNAL ;
    PORT
      LAYER M4 ;
        RECT  302.316 9.36 302.4 9.384 ;
    END
  END r_y[11]
  PIN r_y[12]
    DIRECTION INPUT ;
    USE SIGNAL ;
    PORT
      LAYER M4 ;
        RECT  302.316 9.552 302.4 9.576 ;
    END
  END r_y[12]
  PIN r_y[13]
    DIRECTION INPUT ;
    USE SIGNAL ;
    PORT
      LAYER M4 ;
        RECT  302.316 9.744 302.4 9.768 ;
    END
  END r_y[13]
  PIN r_y[14]
    DIRECTION INPUT ;
    USE SIGNAL ;
    PORT
      LAYER M4 ;
        RECT  302.316 9.936 302.4 9.96 ;
    END
  END r_y[14]
  PIN r_y[15]
    DIRECTION INPUT ;
    USE SIGNAL ;
    PORT
      LAYER M4 ;
        RECT  302.316 10.128 302.4 10.152 ;
    END
  END r_y[15]
  PIN r_y[16]
    DIRECTION INPUT ;
    USE SIGNAL ;
    PORT
      LAYER M4 ;
        RECT  302.316 10.32 302.4 10.344 ;
    END
  END r_y[16]
  PIN r_y[17]
    DIRECTION INPUT ;
    USE SIGNAL ;
    PORT
      LAYER M4 ;
        RECT  302.316 10.512 302.4 10.536 ;
    END
  END r_y[17]
  PIN r_y[18]
    DIRECTION INPUT ;
    USE SIGNAL ;
    PORT
      LAYER M4 ;
        RECT  302.316 10.704 302.4 10.728 ;
    END
  END r_y[18]
  PIN r_y[19]
    DIRECTION INPUT ;
    USE SIGNAL ;
    PORT
      LAYER M4 ;
        RECT  302.316 10.896 302.4 10.92 ;
    END
  END r_y[19]
  PIN r_y[1]
    DIRECTION INPUT ;
    USE SIGNAL ;
    PORT
      LAYER M4 ;
        RECT  302.316 7.392 302.4 7.416 ;
    END
  END r_y[1]
  PIN r_y[20]
    DIRECTION INPUT ;
    USE SIGNAL ;
    PORT
      LAYER M4 ;
        RECT  302.316 11.088 302.4 11.112 ;
    END
  END r_y[20]
  PIN r_y[21]
    DIRECTION INPUT ;
    USE SIGNAL ;
    PORT
      LAYER M4 ;
        RECT  302.316 11.28 302.4 11.304 ;
    END
  END r_y[21]
  PIN r_y[22]
    DIRECTION INPUT ;
    USE SIGNAL ;
    PORT
      LAYER M4 ;
        RECT  302.316 11.472 302.4 11.496 ;
    END
  END r_y[22]
  PIN r_y[23]
    DIRECTION INPUT ;
    USE SIGNAL ;
    PORT
      LAYER M4 ;
        RECT  302.316 11.664 302.4 11.688 ;
    END
  END r_y[23]
  PIN r_y[24]
    DIRECTION INPUT ;
    USE SIGNAL ;
    PORT
      LAYER M4 ;
        RECT  302.316 11.856 302.4 11.88 ;
    END
  END r_y[24]
  PIN r_y[25]
    DIRECTION INPUT ;
    USE SIGNAL ;
    PORT
      LAYER M4 ;
        RECT  302.316 12.048 302.4 12.072 ;
    END
  END r_y[25]
  PIN r_y[26]
    DIRECTION INPUT ;
    USE SIGNAL ;
    PORT
      LAYER M4 ;
        RECT  302.316 12.24 302.4 12.264 ;
    END
  END r_y[26]
  PIN r_y[27]
    DIRECTION INPUT ;
    USE SIGNAL ;
    PORT
      LAYER M4 ;
        RECT  302.316 12.432 302.4 12.456 ;
    END
  END r_y[27]
  PIN r_y[28]
    DIRECTION INPUT ;
    USE SIGNAL ;
    PORT
      LAYER M4 ;
        RECT  302.316 12.624 302.4 12.648 ;
    END
  END r_y[28]
  PIN r_y[29]
    DIRECTION INPUT ;
    USE SIGNAL ;
    PORT
      LAYER M4 ;
        RECT  302.316 12.816 302.4 12.84 ;
    END
  END r_y[29]
  PIN r_y[2]
    DIRECTION INPUT ;
    USE SIGNAL ;
    PORT
      LAYER M4 ;
        RECT  302.316 7.584 302.4 7.608 ;
    END
  END r_y[2]
  PIN r_y[30]
    DIRECTION INPUT ;
    USE SIGNAL ;
    PORT
      LAYER M4 ;
        RECT  302.316 39.072 302.4 39.096 ;
    END
  END r_y[30]
  PIN r_y[31]
    DIRECTION INPUT ;
    USE SIGNAL ;
    PORT
      LAYER M4 ;
        RECT  302.316 39.264 302.4 39.288 ;
    END
  END r_y[31]
  PIN r_y[3]
    DIRECTION INPUT ;
    USE SIGNAL ;
    PORT
      LAYER M4 ;
        RECT  302.316 7.776 302.4 7.8 ;
    END
  END r_y[3]
  PIN r_y[4]
    DIRECTION INPUT ;
    USE SIGNAL ;
    PORT
      LAYER M4 ;
        RECT  302.316 8.016 302.4 8.04 ;
    END
  END r_y[4]
  PIN r_y[5]
    DIRECTION INPUT ;
    USE SIGNAL ;
    PORT
      LAYER M4 ;
        RECT  302.316 8.208 302.4 8.232 ;
    END
  END r_y[5]
  PIN r_y[6]
    DIRECTION INPUT ;
    USE SIGNAL ;
    PORT
      LAYER M4 ;
        RECT  302.316 8.4 302.4 8.424 ;
    END
  END r_y[6]
  PIN r_y[7]
    DIRECTION INPUT ;
    USE SIGNAL ;
    PORT
      LAYER M4 ;
        RECT  302.316 8.592 302.4 8.616 ;
    END
  END r_y[7]
  PIN r_y[8]
    DIRECTION INPUT ;
    USE SIGNAL ;
    PORT
      LAYER M4 ;
        RECT  302.316 8.784 302.4 8.808 ;
    END
  END r_y[8]
  PIN r_y[9]
    DIRECTION INPUT ;
    USE SIGNAL ;
    PORT
      LAYER M4 ;
        RECT  302.316 8.976 302.4 9 ;
    END
  END r_y[9]
  PIN rn_i[0]
    DIRECTION INPUT ;
    USE SIGNAL ;
    PORT
      LAYER M5 ;
        RECT  97.2 107.916 97.224 108 ;
    END
  END rn_i[0]
  PIN rn_i[100]
    DIRECTION INPUT ;
    USE SIGNAL ;
    PORT
      LAYER M5 ;
        RECT  122.544 107.916 122.568 108 ;
    END
  END rn_i[100]
  PIN rn_i[101]
    DIRECTION INPUT ;
    USE SIGNAL ;
    PORT
      LAYER M5 ;
        RECT  122.736 107.916 122.76 108 ;
    END
  END rn_i[101]
  PIN rn_i[102]
    DIRECTION INPUT ;
    USE SIGNAL ;
    PORT
      LAYER M5 ;
        RECT  122.928 107.916 122.952 108 ;
    END
  END rn_i[102]
  PIN rn_i[103]
    DIRECTION INPUT ;
    USE SIGNAL ;
    PORT
      LAYER M5 ;
        RECT  123.12 107.916 123.144 108 ;
    END
  END rn_i[103]
  PIN rn_i[104]
    DIRECTION INPUT ;
    USE SIGNAL ;
    PORT
      LAYER M5 ;
        RECT  123.312 107.916 123.336 108 ;
    END
  END rn_i[104]
  PIN rn_i[105]
    DIRECTION INPUT ;
    USE SIGNAL ;
    PORT
      LAYER M5 ;
        RECT  123.504 107.916 123.528 108 ;
    END
  END rn_i[105]
  PIN rn_i[106]
    DIRECTION INPUT ;
    USE SIGNAL ;
    PORT
      LAYER M5 ;
        RECT  123.696 107.916 123.72 108 ;
    END
  END rn_i[106]
  PIN rn_i[107]
    DIRECTION INPUT ;
    USE SIGNAL ;
    PORT
      LAYER M5 ;
        RECT  123.888 107.916 123.912 108 ;
    END
  END rn_i[107]
  PIN rn_i[108]
    DIRECTION INPUT ;
    USE SIGNAL ;
    PORT
      LAYER M5 ;
        RECT  124.08 107.916 124.104 108 ;
    END
  END rn_i[108]
  PIN rn_i[109]
    DIRECTION INPUT ;
    USE SIGNAL ;
    PORT
      LAYER M5 ;
        RECT  124.272 107.916 124.296 108 ;
    END
  END rn_i[109]
  PIN rn_i[10]
    DIRECTION INPUT ;
    USE SIGNAL ;
    PORT
      LAYER M5 ;
        RECT  99.12 107.916 99.144 108 ;
    END
  END rn_i[10]
  PIN rn_i[110]
    DIRECTION INPUT ;
    USE SIGNAL ;
    PORT
      LAYER M5 ;
        RECT  124.464 107.916 124.488 108 ;
    END
  END rn_i[110]
  PIN rn_i[111]
    DIRECTION INPUT ;
    USE SIGNAL ;
    PORT
      LAYER M5 ;
        RECT  124.656 107.916 124.68 108 ;
    END
  END rn_i[111]
  PIN rn_i[112]
    DIRECTION INPUT ;
    USE SIGNAL ;
    PORT
      LAYER M5 ;
        RECT  124.848 107.916 124.872 108 ;
    END
  END rn_i[112]
  PIN rn_i[113]
    DIRECTION INPUT ;
    USE SIGNAL ;
    PORT
      LAYER M5 ;
        RECT  125.04 107.916 125.064 108 ;
    END
  END rn_i[113]
  PIN rn_i[114]
    DIRECTION INPUT ;
    USE SIGNAL ;
    PORT
      LAYER M5 ;
        RECT  125.232 107.916 125.256 108 ;
    END
  END rn_i[114]
  PIN rn_i[115]
    DIRECTION INPUT ;
    USE SIGNAL ;
    PORT
      LAYER M5 ;
        RECT  125.424 107.916 125.448 108 ;
    END
  END rn_i[115]
  PIN rn_i[116]
    DIRECTION INPUT ;
    USE SIGNAL ;
    PORT
      LAYER M5 ;
        RECT  125.616 107.916 125.64 108 ;
    END
  END rn_i[116]
  PIN rn_i[117]
    DIRECTION INPUT ;
    USE SIGNAL ;
    PORT
      LAYER M5 ;
        RECT  125.808 107.916 125.832 108 ;
    END
  END rn_i[117]
  PIN rn_i[118]
    DIRECTION INPUT ;
    USE SIGNAL ;
    PORT
      LAYER M5 ;
        RECT  126 107.916 126.024 108 ;
    END
  END rn_i[118]
  PIN rn_i[119]
    DIRECTION INPUT ;
    USE SIGNAL ;
    PORT
      LAYER M5 ;
        RECT  126.192 107.916 126.216 108 ;
    END
  END rn_i[119]
  PIN rn_i[11]
    DIRECTION INPUT ;
    USE SIGNAL ;
    PORT
      LAYER M5 ;
        RECT  99.312 107.916 99.336 108 ;
    END
  END rn_i[11]
  PIN rn_i[120]
    DIRECTION INPUT ;
    USE SIGNAL ;
    PORT
      LAYER M5 ;
        RECT  107.952 107.916 107.976 108 ;
    END
  END rn_i[120]
  PIN rn_i[121]
    DIRECTION INPUT ;
    USE SIGNAL ;
    PORT
      LAYER M5 ;
        RECT  108.144 107.916 108.168 108 ;
    END
  END rn_i[121]
  PIN rn_i[122]
    DIRECTION INPUT ;
    USE SIGNAL ;
    PORT
      LAYER M5 ;
        RECT  108.336 107.916 108.36 108 ;
    END
  END rn_i[122]
  PIN rn_i[123]
    DIRECTION INPUT ;
    USE SIGNAL ;
    PORT
      LAYER M5 ;
        RECT  108.528 107.916 108.552 108 ;
    END
  END rn_i[123]
  PIN rn_i[124]
    DIRECTION INPUT ;
    USE SIGNAL ;
    PORT
      LAYER M5 ;
        RECT  108.72 107.916 108.744 108 ;
    END
  END rn_i[124]
  PIN rn_i[125]
    DIRECTION INPUT ;
    USE SIGNAL ;
    PORT
      LAYER M5 ;
        RECT  108.912 107.916 108.936 108 ;
    END
  END rn_i[125]
  PIN rn_i[126]
    DIRECTION INPUT ;
    USE SIGNAL ;
    PORT
      LAYER M5 ;
        RECT  109.104 107.916 109.128 108 ;
    END
  END rn_i[126]
  PIN rn_i[127]
    DIRECTION INPUT ;
    USE SIGNAL ;
    PORT
      LAYER M5 ;
        RECT  109.296 107.916 109.32 108 ;
    END
  END rn_i[127]
  PIN rn_i[128]
    DIRECTION INPUT ;
    USE SIGNAL ;
    PORT
      LAYER M5 ;
        RECT  109.488 107.916 109.512 108 ;
    END
  END rn_i[128]
  PIN rn_i[129]
    DIRECTION INPUT ;
    USE SIGNAL ;
    PORT
      LAYER M5 ;
        RECT  109.68 107.916 109.704 108 ;
    END
  END rn_i[129]
  PIN rn_i[12]
    DIRECTION INPUT ;
    USE SIGNAL ;
    PORT
      LAYER M5 ;
        RECT  99.504 107.916 99.528 108 ;
    END
  END rn_i[12]
  PIN rn_i[130]
    DIRECTION INPUT ;
    USE SIGNAL ;
    PORT
      LAYER M5 ;
        RECT  109.872 107.916 109.896 108 ;
    END
  END rn_i[130]
  PIN rn_i[131]
    DIRECTION INPUT ;
    USE SIGNAL ;
    PORT
      LAYER M5 ;
        RECT  110.064 107.916 110.088 108 ;
    END
  END rn_i[131]
  PIN rn_i[132]
    DIRECTION INPUT ;
    USE SIGNAL ;
    PORT
      LAYER M5 ;
        RECT  110.256 107.916 110.28 108 ;
    END
  END rn_i[132]
  PIN rn_i[133]
    DIRECTION INPUT ;
    USE SIGNAL ;
    PORT
      LAYER M5 ;
        RECT  110.448 107.916 110.472 108 ;
    END
  END rn_i[133]
  PIN rn_i[134]
    DIRECTION INPUT ;
    USE SIGNAL ;
    PORT
      LAYER M5 ;
        RECT  110.64 107.916 110.664 108 ;
    END
  END rn_i[134]
  PIN rn_i[135]
    DIRECTION INPUT ;
    USE SIGNAL ;
    PORT
      LAYER M5 ;
        RECT  110.832 107.916 110.856 108 ;
    END
  END rn_i[135]
  PIN rn_i[136]
    DIRECTION INPUT ;
    USE SIGNAL ;
    PORT
      LAYER M5 ;
        RECT  111.024 107.916 111.048 108 ;
    END
  END rn_i[136]
  PIN rn_i[137]
    DIRECTION INPUT ;
    USE SIGNAL ;
    PORT
      LAYER M5 ;
        RECT  111.216 107.916 111.24 108 ;
    END
  END rn_i[137]
  PIN rn_i[138]
    DIRECTION INPUT ;
    USE SIGNAL ;
    PORT
      LAYER M5 ;
        RECT  111.408 107.916 111.432 108 ;
    END
  END rn_i[138]
  PIN rn_i[139]
    DIRECTION INPUT ;
    USE SIGNAL ;
    PORT
      LAYER M5 ;
        RECT  111.6 107.916 111.624 108 ;
    END
  END rn_i[139]
  PIN rn_i[13]
    DIRECTION INPUT ;
    USE SIGNAL ;
    PORT
      LAYER M5 ;
        RECT  99.696 107.916 99.72 108 ;
    END
  END rn_i[13]
  PIN rn_i[140]
    DIRECTION INPUT ;
    USE SIGNAL ;
    PORT
      LAYER M5 ;
        RECT  111.792 107.916 111.816 108 ;
    END
  END rn_i[140]
  PIN rn_i[141]
    DIRECTION INPUT ;
    USE SIGNAL ;
    PORT
      LAYER M5 ;
        RECT  111.984 107.916 112.008 108 ;
    END
  END rn_i[141]
  PIN rn_i[142]
    DIRECTION INPUT ;
    USE SIGNAL ;
    PORT
      LAYER M5 ;
        RECT  112.176 107.916 112.2 108 ;
    END
  END rn_i[142]
  PIN rn_i[143]
    DIRECTION INPUT ;
    USE SIGNAL ;
    PORT
      LAYER M5 ;
        RECT  112.368 107.916 112.392 108 ;
    END
  END rn_i[143]
  PIN rn_i[144]
    DIRECTION INPUT ;
    USE SIGNAL ;
    PORT
      LAYER M5 ;
        RECT  112.56 107.916 112.584 108 ;
    END
  END rn_i[144]
  PIN rn_i[145]
    DIRECTION INPUT ;
    USE SIGNAL ;
    PORT
      LAYER M5 ;
        RECT  112.752 107.916 112.776 108 ;
    END
  END rn_i[145]
  PIN rn_i[146]
    DIRECTION INPUT ;
    USE SIGNAL ;
    PORT
      LAYER M5 ;
        RECT  112.944 107.916 112.968 108 ;
    END
  END rn_i[146]
  PIN rn_i[147]
    DIRECTION INPUT ;
    USE SIGNAL ;
    PORT
      LAYER M5 ;
        RECT  113.136 107.916 113.16 108 ;
    END
  END rn_i[147]
  PIN rn_i[148]
    DIRECTION INPUT ;
    USE SIGNAL ;
    PORT
      LAYER M5 ;
        RECT  113.328 107.916 113.352 108 ;
    END
  END rn_i[148]
  PIN rn_i[149]
    DIRECTION INPUT ;
    USE SIGNAL ;
    PORT
      LAYER M5 ;
        RECT  113.52 107.916 113.544 108 ;
    END
  END rn_i[149]
  PIN rn_i[14]
    DIRECTION INPUT ;
    USE SIGNAL ;
    PORT
      LAYER M5 ;
        RECT  99.888 107.916 99.912 108 ;
    END
  END rn_i[14]
  PIN rn_i[150]
    DIRECTION INPUT ;
    USE SIGNAL ;
    PORT
      LAYER M5 ;
        RECT  113.712 107.916 113.736 108 ;
    END
  END rn_i[150]
  PIN rn_i[151]
    DIRECTION INPUT ;
    USE SIGNAL ;
    PORT
      LAYER M5 ;
        RECT  113.904 107.916 113.928 108 ;
    END
  END rn_i[151]
  PIN rn_i[152]
    DIRECTION INPUT ;
    USE SIGNAL ;
    PORT
      LAYER M5 ;
        RECT  132.528 107.916 132.552 108 ;
    END
  END rn_i[152]
  PIN rn_i[153]
    DIRECTION INPUT ;
    USE SIGNAL ;
    PORT
      LAYER M5 ;
        RECT  132.72 107.916 132.744 108 ;
    END
  END rn_i[153]
  PIN rn_i[154]
    DIRECTION INPUT ;
    USE SIGNAL ;
    PORT
      LAYER M5 ;
        RECT  132.912 107.916 132.936 108 ;
    END
  END rn_i[154]
  PIN rn_i[155]
    DIRECTION INPUT ;
    USE SIGNAL ;
    PORT
      LAYER M5 ;
        RECT  133.104 107.916 133.128 108 ;
    END
  END rn_i[155]
  PIN rn_i[156]
    DIRECTION INPUT ;
    USE SIGNAL ;
    PORT
      LAYER M5 ;
        RECT  133.296 107.916 133.32 108 ;
    END
  END rn_i[156]
  PIN rn_i[157]
    DIRECTION INPUT ;
    USE SIGNAL ;
    PORT
      LAYER M5 ;
        RECT  133.488 107.916 133.512 108 ;
    END
  END rn_i[157]
  PIN rn_i[158]
    DIRECTION INPUT ;
    USE SIGNAL ;
    PORT
      LAYER M5 ;
        RECT  133.68 107.916 133.704 108 ;
    END
  END rn_i[158]
  PIN rn_i[159]
    DIRECTION INPUT ;
    USE SIGNAL ;
    PORT
      LAYER M5 ;
        RECT  133.872 107.916 133.896 108 ;
    END
  END rn_i[159]
  PIN rn_i[15]
    DIRECTION INPUT ;
    USE SIGNAL ;
    PORT
      LAYER M5 ;
        RECT  100.08 107.916 100.104 108 ;
    END
  END rn_i[15]
  PIN rn_i[160]
    DIRECTION INPUT ;
    USE SIGNAL ;
    PORT
      LAYER M5 ;
        RECT  134.064 107.916 134.088 108 ;
    END
  END rn_i[160]
  PIN rn_i[161]
    DIRECTION INPUT ;
    USE SIGNAL ;
    PORT
      LAYER M5 ;
        RECT  134.256 107.916 134.28 108 ;
    END
  END rn_i[161]
  PIN rn_i[162]
    DIRECTION INPUT ;
    USE SIGNAL ;
    PORT
      LAYER M5 ;
        RECT  134.448 107.916 134.472 108 ;
    END
  END rn_i[162]
  PIN rn_i[163]
    DIRECTION INPUT ;
    USE SIGNAL ;
    PORT
      LAYER M5 ;
        RECT  134.64 107.916 134.664 108 ;
    END
  END rn_i[163]
  PIN rn_i[164]
    DIRECTION INPUT ;
    USE SIGNAL ;
    PORT
      LAYER M5 ;
        RECT  134.832 107.916 134.856 108 ;
    END
  END rn_i[164]
  PIN rn_i[165]
    DIRECTION INPUT ;
    USE SIGNAL ;
    PORT
      LAYER M5 ;
        RECT  135.024 107.916 135.048 108 ;
    END
  END rn_i[165]
  PIN rn_i[166]
    DIRECTION INPUT ;
    USE SIGNAL ;
    PORT
      LAYER M5 ;
        RECT  135.216 107.916 135.24 108 ;
    END
  END rn_i[166]
  PIN rn_i[167]
    DIRECTION INPUT ;
    USE SIGNAL ;
    PORT
      LAYER M5 ;
        RECT  135.408 107.916 135.432 108 ;
    END
  END rn_i[167]
  PIN rn_i[168]
    DIRECTION INPUT ;
    USE SIGNAL ;
    PORT
      LAYER M5 ;
        RECT  135.6 107.916 135.624 108 ;
    END
  END rn_i[168]
  PIN rn_i[169]
    DIRECTION INPUT ;
    USE SIGNAL ;
    PORT
      LAYER M5 ;
        RECT  135.792 107.916 135.816 108 ;
    END
  END rn_i[169]
  PIN rn_i[16]
    DIRECTION INPUT ;
    USE SIGNAL ;
    PORT
      LAYER M5 ;
        RECT  100.272 107.916 100.296 108 ;
    END
  END rn_i[16]
  PIN rn_i[170]
    DIRECTION INPUT ;
    USE SIGNAL ;
    PORT
      LAYER M5 ;
        RECT  135.984 107.916 136.008 108 ;
    END
  END rn_i[170]
  PIN rn_i[171]
    DIRECTION INPUT ;
    USE SIGNAL ;
    PORT
      LAYER M5 ;
        RECT  136.176 107.916 136.2 108 ;
    END
  END rn_i[171]
  PIN rn_i[172]
    DIRECTION INPUT ;
    USE SIGNAL ;
    PORT
      LAYER M5 ;
        RECT  136.368 107.916 136.392 108 ;
    END
  END rn_i[172]
  PIN rn_i[173]
    DIRECTION INPUT ;
    USE SIGNAL ;
    PORT
      LAYER M5 ;
        RECT  136.56 107.916 136.584 108 ;
    END
  END rn_i[173]
  PIN rn_i[174]
    DIRECTION INPUT ;
    USE SIGNAL ;
    PORT
      LAYER M5 ;
        RECT  136.752 107.916 136.776 108 ;
    END
  END rn_i[174]
  PIN rn_i[175]
    DIRECTION INPUT ;
    USE SIGNAL ;
    PORT
      LAYER M5 ;
        RECT  136.944 107.916 136.968 108 ;
    END
  END rn_i[175]
  PIN rn_i[176]
    DIRECTION INPUT ;
    USE SIGNAL ;
    PORT
      LAYER M5 ;
        RECT  137.136 107.916 137.16 108 ;
    END
  END rn_i[176]
  PIN rn_i[177]
    DIRECTION INPUT ;
    USE SIGNAL ;
    PORT
      LAYER M5 ;
        RECT  137.328 107.916 137.352 108 ;
    END
  END rn_i[177]
  PIN rn_i[178]
    DIRECTION INPUT ;
    USE SIGNAL ;
    PORT
      LAYER M5 ;
        RECT  137.52 107.916 137.544 108 ;
    END
  END rn_i[178]
  PIN rn_i[179]
    DIRECTION INPUT ;
    USE SIGNAL ;
    PORT
      LAYER M5 ;
        RECT  137.712 107.916 137.736 108 ;
    END
  END rn_i[179]
  PIN rn_i[17]
    DIRECTION INPUT ;
    USE SIGNAL ;
    PORT
      LAYER M5 ;
        RECT  100.464 107.916 100.488 108 ;
    END
  END rn_i[17]
  PIN rn_i[180]
    DIRECTION INPUT ;
    USE SIGNAL ;
    PORT
      LAYER M5 ;
        RECT  137.904 107.916 137.928 108 ;
    END
  END rn_i[180]
  PIN rn_i[181]
    DIRECTION INPUT ;
    USE SIGNAL ;
    PORT
      LAYER M5 ;
        RECT  138.096 107.916 138.12 108 ;
    END
  END rn_i[181]
  PIN rn_i[182]
    DIRECTION INPUT ;
    USE SIGNAL ;
    PORT
      LAYER M5 ;
        RECT  138.288 107.916 138.312 108 ;
    END
  END rn_i[182]
  PIN rn_i[183]
    DIRECTION INPUT ;
    USE SIGNAL ;
    PORT
      LAYER M5 ;
        RECT  138.48 107.916 138.504 108 ;
    END
  END rn_i[183]
  PIN rn_i[184]
    DIRECTION INPUT ;
    USE SIGNAL ;
    PORT
      LAYER M5 ;
        RECT  114.096 107.916 114.12 108 ;
    END
  END rn_i[184]
  PIN rn_i[185]
    DIRECTION INPUT ;
    USE SIGNAL ;
    PORT
      LAYER M5 ;
        RECT  114.288 107.916 114.312 108 ;
    END
  END rn_i[185]
  PIN rn_i[186]
    DIRECTION INPUT ;
    USE SIGNAL ;
    PORT
      LAYER M5 ;
        RECT  114.48 107.916 114.504 108 ;
    END
  END rn_i[186]
  PIN rn_i[187]
    DIRECTION INPUT ;
    USE SIGNAL ;
    PORT
      LAYER M5 ;
        RECT  114.672 107.916 114.696 108 ;
    END
  END rn_i[187]
  PIN rn_i[188]
    DIRECTION INPUT ;
    USE SIGNAL ;
    PORT
      LAYER M5 ;
        RECT  114.864 107.916 114.888 108 ;
    END
  END rn_i[188]
  PIN rn_i[189]
    DIRECTION INPUT ;
    USE SIGNAL ;
    PORT
      LAYER M5 ;
        RECT  115.056 107.916 115.08 108 ;
    END
  END rn_i[189]
  PIN rn_i[18]
    DIRECTION INPUT ;
    USE SIGNAL ;
    PORT
      LAYER M5 ;
        RECT  100.656 107.916 100.68 108 ;
    END
  END rn_i[18]
  PIN rn_i[190]
    DIRECTION INPUT ;
    USE SIGNAL ;
    PORT
      LAYER M5 ;
        RECT  115.248 107.916 115.272 108 ;
    END
  END rn_i[190]
  PIN rn_i[191]
    DIRECTION INPUT ;
    USE SIGNAL ;
    PORT
      LAYER M5 ;
        RECT  115.44 107.916 115.464 108 ;
    END
  END rn_i[191]
  PIN rn_i[192]
    DIRECTION INPUT ;
    USE SIGNAL ;
    PORT
      LAYER M5 ;
        RECT  115.632 107.916 115.656 108 ;
    END
  END rn_i[192]
  PIN rn_i[193]
    DIRECTION INPUT ;
    USE SIGNAL ;
    PORT
      LAYER M5 ;
        RECT  115.824 107.916 115.848 108 ;
    END
  END rn_i[193]
  PIN rn_i[194]
    DIRECTION INPUT ;
    USE SIGNAL ;
    PORT
      LAYER M5 ;
        RECT  116.016 107.916 116.04 108 ;
    END
  END rn_i[194]
  PIN rn_i[195]
    DIRECTION INPUT ;
    USE SIGNAL ;
    PORT
      LAYER M5 ;
        RECT  116.208 107.916 116.232 108 ;
    END
  END rn_i[195]
  PIN rn_i[196]
    DIRECTION INPUT ;
    USE SIGNAL ;
    PORT
      LAYER M5 ;
        RECT  116.4 107.916 116.424 108 ;
    END
  END rn_i[196]
  PIN rn_i[197]
    DIRECTION INPUT ;
    USE SIGNAL ;
    PORT
      LAYER M5 ;
        RECT  116.592 107.916 116.616 108 ;
    END
  END rn_i[197]
  PIN rn_i[198]
    DIRECTION INPUT ;
    USE SIGNAL ;
    PORT
      LAYER M5 ;
        RECT  116.784 107.916 116.808 108 ;
    END
  END rn_i[198]
  PIN rn_i[199]
    DIRECTION INPUT ;
    USE SIGNAL ;
    PORT
      LAYER M5 ;
        RECT  116.976 107.916 117 108 ;
    END
  END rn_i[199]
  PIN rn_i[19]
    DIRECTION INPUT ;
    USE SIGNAL ;
    PORT
      LAYER M5 ;
        RECT  100.848 107.916 100.872 108 ;
    END
  END rn_i[19]
  PIN rn_i[1]
    DIRECTION INPUT ;
    USE SIGNAL ;
    PORT
      LAYER M5 ;
        RECT  97.392 107.916 97.416 108 ;
    END
  END rn_i[1]
  PIN rn_i[200]
    DIRECTION INPUT ;
    USE SIGNAL ;
    PORT
      LAYER M5 ;
        RECT  117.168 107.916 117.192 108 ;
    END
  END rn_i[200]
  PIN rn_i[201]
    DIRECTION INPUT ;
    USE SIGNAL ;
    PORT
      LAYER M5 ;
        RECT  117.36 107.916 117.384 108 ;
    END
  END rn_i[201]
  PIN rn_i[202]
    DIRECTION INPUT ;
    USE SIGNAL ;
    PORT
      LAYER M5 ;
        RECT  117.552 107.916 117.576 108 ;
    END
  END rn_i[202]
  PIN rn_i[203]
    DIRECTION INPUT ;
    USE SIGNAL ;
    PORT
      LAYER M5 ;
        RECT  117.744 107.916 117.768 108 ;
    END
  END rn_i[203]
  PIN rn_i[204]
    DIRECTION INPUT ;
    USE SIGNAL ;
    PORT
      LAYER M5 ;
        RECT  117.936 107.916 117.96 108 ;
    END
  END rn_i[204]
  PIN rn_i[205]
    DIRECTION INPUT ;
    USE SIGNAL ;
    PORT
      LAYER M5 ;
        RECT  118.128 107.916 118.152 108 ;
    END
  END rn_i[205]
  PIN rn_i[206]
    DIRECTION INPUT ;
    USE SIGNAL ;
    PORT
      LAYER M5 ;
        RECT  118.32 107.916 118.344 108 ;
    END
  END rn_i[206]
  PIN rn_i[207]
    DIRECTION INPUT ;
    USE SIGNAL ;
    PORT
      LAYER M5 ;
        RECT  118.512 107.916 118.536 108 ;
    END
  END rn_i[207]
  PIN rn_i[208]
    DIRECTION INPUT ;
    USE SIGNAL ;
    PORT
      LAYER M5 ;
        RECT  118.704 107.916 118.728 108 ;
    END
  END rn_i[208]
  PIN rn_i[209]
    DIRECTION INPUT ;
    USE SIGNAL ;
    PORT
      LAYER M5 ;
        RECT  118.896 107.916 118.92 108 ;
    END
  END rn_i[209]
  PIN rn_i[20]
    DIRECTION INPUT ;
    USE SIGNAL ;
    PORT
      LAYER M5 ;
        RECT  101.04 107.916 101.064 108 ;
    END
  END rn_i[20]
  PIN rn_i[210]
    DIRECTION INPUT ;
    USE SIGNAL ;
    PORT
      LAYER M5 ;
        RECT  119.088 107.916 119.112 108 ;
    END
  END rn_i[210]
  PIN rn_i[211]
    DIRECTION INPUT ;
    USE SIGNAL ;
    PORT
      LAYER M5 ;
        RECT  119.28 107.916 119.304 108 ;
    END
  END rn_i[211]
  PIN rn_i[212]
    DIRECTION INPUT ;
    USE SIGNAL ;
    PORT
      LAYER M5 ;
        RECT  119.472 107.916 119.496 108 ;
    END
  END rn_i[212]
  PIN rn_i[213]
    DIRECTION INPUT ;
    USE SIGNAL ;
    PORT
      LAYER M5 ;
        RECT  119.664 107.916 119.688 108 ;
    END
  END rn_i[213]
  PIN rn_i[214]
    DIRECTION INPUT ;
    USE SIGNAL ;
    PORT
      LAYER M5 ;
        RECT  119.856 107.916 119.88 108 ;
    END
  END rn_i[214]
  PIN rn_i[215]
    DIRECTION INPUT ;
    USE SIGNAL ;
    PORT
      LAYER M5 ;
        RECT  120.048 107.916 120.072 108 ;
    END
  END rn_i[215]
  PIN rn_i[216]
    DIRECTION INPUT ;
    USE SIGNAL ;
    PORT
      LAYER M5 ;
        RECT  150.96 107.916 150.984 108 ;
    END
  END rn_i[216]
  PIN rn_i[217]
    DIRECTION INPUT ;
    USE SIGNAL ;
    PORT
      LAYER M5 ;
        RECT  151.152 107.916 151.176 108 ;
    END
  END rn_i[217]
  PIN rn_i[218]
    DIRECTION INPUT ;
    USE SIGNAL ;
    PORT
      LAYER M5 ;
        RECT  151.344 107.916 151.368 108 ;
    END
  END rn_i[218]
  PIN rn_i[219]
    DIRECTION INPUT ;
    USE SIGNAL ;
    PORT
      LAYER M5 ;
        RECT  151.536 107.916 151.56 108 ;
    END
  END rn_i[219]
  PIN rn_i[21]
    DIRECTION INPUT ;
    USE SIGNAL ;
    PORT
      LAYER M5 ;
        RECT  101.232 107.916 101.256 108 ;
    END
  END rn_i[21]
  PIN rn_i[220]
    DIRECTION INPUT ;
    USE SIGNAL ;
    PORT
      LAYER M5 ;
        RECT  151.728 107.916 151.752 108 ;
    END
  END rn_i[220]
  PIN rn_i[221]
    DIRECTION INPUT ;
    USE SIGNAL ;
    PORT
      LAYER M5 ;
        RECT  151.92 107.916 151.944 108 ;
    END
  END rn_i[221]
  PIN rn_i[222]
    DIRECTION INPUT ;
    USE SIGNAL ;
    PORT
      LAYER M5 ;
        RECT  152.112 107.916 152.136 108 ;
    END
  END rn_i[222]
  PIN rn_i[223]
    DIRECTION INPUT ;
    USE SIGNAL ;
    PORT
      LAYER M5 ;
        RECT  152.304 107.916 152.328 108 ;
    END
  END rn_i[223]
  PIN rn_i[224]
    DIRECTION INPUT ;
    USE SIGNAL ;
    PORT
      LAYER M5 ;
        RECT  152.496 107.916 152.52 108 ;
    END
  END rn_i[224]
  PIN rn_i[225]
    DIRECTION INPUT ;
    USE SIGNAL ;
    PORT
      LAYER M5 ;
        RECT  152.688 107.916 152.712 108 ;
    END
  END rn_i[225]
  PIN rn_i[226]
    DIRECTION INPUT ;
    USE SIGNAL ;
    PORT
      LAYER M5 ;
        RECT  152.88 107.916 152.904 108 ;
    END
  END rn_i[226]
  PIN rn_i[227]
    DIRECTION INPUT ;
    USE SIGNAL ;
    PORT
      LAYER M5 ;
        RECT  153.072 107.916 153.096 108 ;
    END
  END rn_i[227]
  PIN rn_i[228]
    DIRECTION INPUT ;
    USE SIGNAL ;
    PORT
      LAYER M5 ;
        RECT  153.264 107.916 153.288 108 ;
    END
  END rn_i[228]
  PIN rn_i[229]
    DIRECTION INPUT ;
    USE SIGNAL ;
    PORT
      LAYER M5 ;
        RECT  153.456 107.916 153.48 108 ;
    END
  END rn_i[229]
  PIN rn_i[22]
    DIRECTION INPUT ;
    USE SIGNAL ;
    PORT
      LAYER M5 ;
        RECT  101.424 107.916 101.448 108 ;
    END
  END rn_i[22]
  PIN rn_i[230]
    DIRECTION INPUT ;
    USE SIGNAL ;
    PORT
      LAYER M5 ;
        RECT  153.648 107.916 153.672 108 ;
    END
  END rn_i[230]
  PIN rn_i[231]
    DIRECTION INPUT ;
    USE SIGNAL ;
    PORT
      LAYER M5 ;
        RECT  153.84 107.916 153.864 108 ;
    END
  END rn_i[231]
  PIN rn_i[232]
    DIRECTION INPUT ;
    USE SIGNAL ;
    PORT
      LAYER M5 ;
        RECT  154.032 107.916 154.056 108 ;
    END
  END rn_i[232]
  PIN rn_i[233]
    DIRECTION INPUT ;
    USE SIGNAL ;
    PORT
      LAYER M5 ;
        RECT  154.224 107.916 154.248 108 ;
    END
  END rn_i[233]
  PIN rn_i[234]
    DIRECTION INPUT ;
    USE SIGNAL ;
    PORT
      LAYER M5 ;
        RECT  154.416 107.916 154.44 108 ;
    END
  END rn_i[234]
  PIN rn_i[235]
    DIRECTION INPUT ;
    USE SIGNAL ;
    PORT
      LAYER M5 ;
        RECT  154.608 107.916 154.632 108 ;
    END
  END rn_i[235]
  PIN rn_i[236]
    DIRECTION INPUT ;
    USE SIGNAL ;
    PORT
      LAYER M5 ;
        RECT  154.8 107.916 154.824 108 ;
    END
  END rn_i[236]
  PIN rn_i[237]
    DIRECTION INPUT ;
    USE SIGNAL ;
    PORT
      LAYER M5 ;
        RECT  154.992 107.916 155.016 108 ;
    END
  END rn_i[237]
  PIN rn_i[238]
    DIRECTION INPUT ;
    USE SIGNAL ;
    PORT
      LAYER M5 ;
        RECT  155.184 107.916 155.208 108 ;
    END
  END rn_i[238]
  PIN rn_i[239]
    DIRECTION INPUT ;
    USE SIGNAL ;
    PORT
      LAYER M5 ;
        RECT  155.376 107.916 155.4 108 ;
    END
  END rn_i[239]
  PIN rn_i[23]
    DIRECTION INPUT ;
    USE SIGNAL ;
    PORT
      LAYER M5 ;
        RECT  101.616 107.916 101.64 108 ;
    END
  END rn_i[23]
  PIN rn_i[240]
    DIRECTION INPUT ;
    USE SIGNAL ;
    PORT
      LAYER M5 ;
        RECT  155.568 107.916 155.592 108 ;
    END
  END rn_i[240]
  PIN rn_i[241]
    DIRECTION INPUT ;
    USE SIGNAL ;
    PORT
      LAYER M5 ;
        RECT  155.76 107.916 155.784 108 ;
    END
  END rn_i[241]
  PIN rn_i[242]
    DIRECTION INPUT ;
    USE SIGNAL ;
    PORT
      LAYER M5 ;
        RECT  155.952 107.916 155.976 108 ;
    END
  END rn_i[242]
  PIN rn_i[243]
    DIRECTION INPUT ;
    USE SIGNAL ;
    PORT
      LAYER M5 ;
        RECT  156.144 107.916 156.168 108 ;
    END
  END rn_i[243]
  PIN rn_i[244]
    DIRECTION INPUT ;
    USE SIGNAL ;
    PORT
      LAYER M5 ;
        RECT  156.336 107.916 156.36 108 ;
    END
  END rn_i[244]
  PIN rn_i[245]
    DIRECTION INPUT ;
    USE SIGNAL ;
    PORT
      LAYER M5 ;
        RECT  156.528 107.916 156.552 108 ;
    END
  END rn_i[245]
  PIN rn_i[246]
    DIRECTION INPUT ;
    USE SIGNAL ;
    PORT
      LAYER M5 ;
        RECT  156.72 107.916 156.744 108 ;
    END
  END rn_i[246]
  PIN rn_i[247]
    DIRECTION INPUT ;
    USE SIGNAL ;
    PORT
      LAYER M5 ;
        RECT  156.912 107.916 156.936 108 ;
    END
  END rn_i[247]
  PIN rn_i[248]
    DIRECTION INPUT ;
    USE SIGNAL ;
    PORT
      LAYER M5 ;
        RECT  163.248 107.916 163.272 108 ;
    END
  END rn_i[248]
  PIN rn_i[249]
    DIRECTION INPUT ;
    USE SIGNAL ;
    PORT
      LAYER M5 ;
        RECT  163.44 107.916 163.464 108 ;
    END
  END rn_i[249]
  PIN rn_i[24]
    DIRECTION INPUT ;
    USE SIGNAL ;
    PORT
      LAYER M5 ;
        RECT  126.384 107.916 126.408 108 ;
    END
  END rn_i[24]
  PIN rn_i[250]
    DIRECTION INPUT ;
    USE SIGNAL ;
    PORT
      LAYER M5 ;
        RECT  163.632 107.916 163.656 108 ;
    END
  END rn_i[250]
  PIN rn_i[251]
    DIRECTION INPUT ;
    USE SIGNAL ;
    PORT
      LAYER M5 ;
        RECT  163.824 107.916 163.848 108 ;
    END
  END rn_i[251]
  PIN rn_i[252]
    DIRECTION INPUT ;
    USE SIGNAL ;
    PORT
      LAYER M5 ;
        RECT  164.016 107.916 164.04 108 ;
    END
  END rn_i[252]
  PIN rn_i[253]
    DIRECTION INPUT ;
    USE SIGNAL ;
    PORT
      LAYER M5 ;
        RECT  164.208 107.916 164.232 108 ;
    END
  END rn_i[253]
  PIN rn_i[254]
    DIRECTION INPUT ;
    USE SIGNAL ;
    PORT
      LAYER M5 ;
        RECT  164.4 107.916 164.424 108 ;
    END
  END rn_i[254]
  PIN rn_i[255]
    DIRECTION INPUT ;
    USE SIGNAL ;
    PORT
      LAYER M5 ;
        RECT  164.592 107.916 164.616 108 ;
    END
  END rn_i[255]
  PIN rn_i[256]
    DIRECTION INPUT ;
    USE SIGNAL ;
    PORT
      LAYER M5 ;
        RECT  164.784 107.916 164.808 108 ;
    END
  END rn_i[256]
  PIN rn_i[257]
    DIRECTION INPUT ;
    USE SIGNAL ;
    PORT
      LAYER M5 ;
        RECT  164.976 107.916 165 108 ;
    END
  END rn_i[257]
  PIN rn_i[258]
    DIRECTION INPUT ;
    USE SIGNAL ;
    PORT
      LAYER M5 ;
        RECT  165.168 107.916 165.192 108 ;
    END
  END rn_i[258]
  PIN rn_i[259]
    DIRECTION INPUT ;
    USE SIGNAL ;
    PORT
      LAYER M5 ;
        RECT  165.36 107.916 165.384 108 ;
    END
  END rn_i[259]
  PIN rn_i[25]
    DIRECTION INPUT ;
    USE SIGNAL ;
    PORT
      LAYER M5 ;
        RECT  126.576 107.916 126.6 108 ;
    END
  END rn_i[25]
  PIN rn_i[260]
    DIRECTION INPUT ;
    USE SIGNAL ;
    PORT
      LAYER M5 ;
        RECT  165.552 107.916 165.576 108 ;
    END
  END rn_i[260]
  PIN rn_i[261]
    DIRECTION INPUT ;
    USE SIGNAL ;
    PORT
      LAYER M5 ;
        RECT  165.744 107.916 165.768 108 ;
    END
  END rn_i[261]
  PIN rn_i[262]
    DIRECTION INPUT ;
    USE SIGNAL ;
    PORT
      LAYER M5 ;
        RECT  165.936 107.916 165.96 108 ;
    END
  END rn_i[262]
  PIN rn_i[263]
    DIRECTION INPUT ;
    USE SIGNAL ;
    PORT
      LAYER M5 ;
        RECT  166.128 107.916 166.152 108 ;
    END
  END rn_i[263]
  PIN rn_i[264]
    DIRECTION INPUT ;
    USE SIGNAL ;
    PORT
      LAYER M5 ;
        RECT  166.32 107.916 166.344 108 ;
    END
  END rn_i[264]
  PIN rn_i[265]
    DIRECTION INPUT ;
    USE SIGNAL ;
    PORT
      LAYER M5 ;
        RECT  166.512 107.916 166.536 108 ;
    END
  END rn_i[265]
  PIN rn_i[266]
    DIRECTION INPUT ;
    USE SIGNAL ;
    PORT
      LAYER M5 ;
        RECT  166.704 107.916 166.728 108 ;
    END
  END rn_i[266]
  PIN rn_i[267]
    DIRECTION INPUT ;
    USE SIGNAL ;
    PORT
      LAYER M5 ;
        RECT  166.896 107.916 166.92 108 ;
    END
  END rn_i[267]
  PIN rn_i[268]
    DIRECTION INPUT ;
    USE SIGNAL ;
    PORT
      LAYER M5 ;
        RECT  167.088 107.916 167.112 108 ;
    END
  END rn_i[268]
  PIN rn_i[269]
    DIRECTION INPUT ;
    USE SIGNAL ;
    PORT
      LAYER M5 ;
        RECT  167.28 107.916 167.304 108 ;
    END
  END rn_i[269]
  PIN rn_i[26]
    DIRECTION INPUT ;
    USE SIGNAL ;
    PORT
      LAYER M5 ;
        RECT  126.768 107.916 126.792 108 ;
    END
  END rn_i[26]
  PIN rn_i[270]
    DIRECTION INPUT ;
    USE SIGNAL ;
    PORT
      LAYER M5 ;
        RECT  167.472 107.916 167.496 108 ;
    END
  END rn_i[270]
  PIN rn_i[271]
    DIRECTION INPUT ;
    USE SIGNAL ;
    PORT
      LAYER M5 ;
        RECT  167.664 107.916 167.688 108 ;
    END
  END rn_i[271]
  PIN rn_i[272]
    DIRECTION INPUT ;
    USE SIGNAL ;
    PORT
      LAYER M5 ;
        RECT  167.856 107.916 167.88 108 ;
    END
  END rn_i[272]
  PIN rn_i[273]
    DIRECTION INPUT ;
    USE SIGNAL ;
    PORT
      LAYER M5 ;
        RECT  168.048 107.916 168.072 108 ;
    END
  END rn_i[273]
  PIN rn_i[274]
    DIRECTION INPUT ;
    USE SIGNAL ;
    PORT
      LAYER M5 ;
        RECT  168.24 107.916 168.264 108 ;
    END
  END rn_i[274]
  PIN rn_i[275]
    DIRECTION INPUT ;
    USE SIGNAL ;
    PORT
      LAYER M5 ;
        RECT  168.432 107.916 168.456 108 ;
    END
  END rn_i[275]
  PIN rn_i[27]
    DIRECTION INPUT ;
    USE SIGNAL ;
    PORT
      LAYER M5 ;
        RECT  126.96 107.916 126.984 108 ;
    END
  END rn_i[27]
  PIN rn_i[28]
    DIRECTION INPUT ;
    USE SIGNAL ;
    PORT
      LAYER M5 ;
        RECT  127.152 107.916 127.176 108 ;
    END
  END rn_i[28]
  PIN rn_i[29]
    DIRECTION INPUT ;
    USE SIGNAL ;
    PORT
      LAYER M5 ;
        RECT  127.344 107.916 127.368 108 ;
    END
  END rn_i[29]
  PIN rn_i[2]
    DIRECTION INPUT ;
    USE SIGNAL ;
    PORT
      LAYER M5 ;
        RECT  97.584 107.916 97.608 108 ;
    END
  END rn_i[2]
  PIN rn_i[30]
    DIRECTION INPUT ;
    USE SIGNAL ;
    PORT
      LAYER M5 ;
        RECT  127.536 107.916 127.56 108 ;
    END
  END rn_i[30]
  PIN rn_i[31]
    DIRECTION INPUT ;
    USE SIGNAL ;
    PORT
      LAYER M5 ;
        RECT  127.728 107.916 127.752 108 ;
    END
  END rn_i[31]
  PIN rn_i[32]
    DIRECTION INPUT ;
    USE SIGNAL ;
    PORT
      LAYER M5 ;
        RECT  127.92 107.916 127.944 108 ;
    END
  END rn_i[32]
  PIN rn_i[33]
    DIRECTION INPUT ;
    USE SIGNAL ;
    PORT
      LAYER M5 ;
        RECT  128.112 107.916 128.136 108 ;
    END
  END rn_i[33]
  PIN rn_i[34]
    DIRECTION INPUT ;
    USE SIGNAL ;
    PORT
      LAYER M5 ;
        RECT  128.304 107.916 128.328 108 ;
    END
  END rn_i[34]
  PIN rn_i[35]
    DIRECTION INPUT ;
    USE SIGNAL ;
    PORT
      LAYER M5 ;
        RECT  128.496 107.916 128.52 108 ;
    END
  END rn_i[35]
  PIN rn_i[36]
    DIRECTION INPUT ;
    USE SIGNAL ;
    PORT
      LAYER M5 ;
        RECT  128.688 107.916 128.712 108 ;
    END
  END rn_i[36]
  PIN rn_i[37]
    DIRECTION INPUT ;
    USE SIGNAL ;
    PORT
      LAYER M5 ;
        RECT  128.88 107.916 128.904 108 ;
    END
  END rn_i[37]
  PIN rn_i[38]
    DIRECTION INPUT ;
    USE SIGNAL ;
    PORT
      LAYER M5 ;
        RECT  129.072 107.916 129.096 108 ;
    END
  END rn_i[38]
  PIN rn_i[39]
    DIRECTION INPUT ;
    USE SIGNAL ;
    PORT
      LAYER M5 ;
        RECT  129.264 107.916 129.288 108 ;
    END
  END rn_i[39]
  PIN rn_i[3]
    DIRECTION INPUT ;
    USE SIGNAL ;
    PORT
      LAYER M5 ;
        RECT  97.776 107.916 97.8 108 ;
    END
  END rn_i[3]
  PIN rn_i[40]
    DIRECTION INPUT ;
    USE SIGNAL ;
    PORT
      LAYER M5 ;
        RECT  129.456 107.916 129.48 108 ;
    END
  END rn_i[40]
  PIN rn_i[41]
    DIRECTION INPUT ;
    USE SIGNAL ;
    PORT
      LAYER M5 ;
        RECT  129.648 107.916 129.672 108 ;
    END
  END rn_i[41]
  PIN rn_i[42]
    DIRECTION INPUT ;
    USE SIGNAL ;
    PORT
      LAYER M5 ;
        RECT  129.84 107.916 129.864 108 ;
    END
  END rn_i[42]
  PIN rn_i[43]
    DIRECTION INPUT ;
    USE SIGNAL ;
    PORT
      LAYER M5 ;
        RECT  130.032 107.916 130.056 108 ;
    END
  END rn_i[43]
  PIN rn_i[44]
    DIRECTION INPUT ;
    USE SIGNAL ;
    PORT
      LAYER M5 ;
        RECT  130.224 107.916 130.248 108 ;
    END
  END rn_i[44]
  PIN rn_i[45]
    DIRECTION INPUT ;
    USE SIGNAL ;
    PORT
      LAYER M5 ;
        RECT  130.416 107.916 130.44 108 ;
    END
  END rn_i[45]
  PIN rn_i[46]
    DIRECTION INPUT ;
    USE SIGNAL ;
    PORT
      LAYER M5 ;
        RECT  130.608 107.916 130.632 108 ;
    END
  END rn_i[46]
  PIN rn_i[47]
    DIRECTION INPUT ;
    USE SIGNAL ;
    PORT
      LAYER M5 ;
        RECT  130.8 107.916 130.824 108 ;
    END
  END rn_i[47]
  PIN rn_i[48]
    DIRECTION INPUT ;
    USE SIGNAL ;
    PORT
      LAYER M5 ;
        RECT  130.992 107.916 131.016 108 ;
    END
  END rn_i[48]
  PIN rn_i[49]
    DIRECTION INPUT ;
    USE SIGNAL ;
    PORT
      LAYER M5 ;
        RECT  131.184 107.916 131.208 108 ;
    END
  END rn_i[49]
  PIN rn_i[4]
    DIRECTION INPUT ;
    USE SIGNAL ;
    PORT
      LAYER M5 ;
        RECT  97.968 107.916 97.992 108 ;
    END
  END rn_i[4]
  PIN rn_i[50]
    DIRECTION INPUT ;
    USE SIGNAL ;
    PORT
      LAYER M5 ;
        RECT  131.376 107.916 131.4 108 ;
    END
  END rn_i[50]
  PIN rn_i[51]
    DIRECTION INPUT ;
    USE SIGNAL ;
    PORT
      LAYER M5 ;
        RECT  131.568 107.916 131.592 108 ;
    END
  END rn_i[51]
  PIN rn_i[52]
    DIRECTION INPUT ;
    USE SIGNAL ;
    PORT
      LAYER M5 ;
        RECT  131.76 107.916 131.784 108 ;
    END
  END rn_i[52]
  PIN rn_i[53]
    DIRECTION INPUT ;
    USE SIGNAL ;
    PORT
      LAYER M5 ;
        RECT  131.952 107.916 131.976 108 ;
    END
  END rn_i[53]
  PIN rn_i[54]
    DIRECTION INPUT ;
    USE SIGNAL ;
    PORT
      LAYER M5 ;
        RECT  132.144 107.916 132.168 108 ;
    END
  END rn_i[54]
  PIN rn_i[55]
    DIRECTION INPUT ;
    USE SIGNAL ;
    PORT
      LAYER M5 ;
        RECT  132.336 107.916 132.36 108 ;
    END
  END rn_i[55]
  PIN rn_i[56]
    DIRECTION INPUT ;
    USE SIGNAL ;
    PORT
      LAYER M5 ;
        RECT  101.808 107.916 101.832 108 ;
    END
  END rn_i[56]
  PIN rn_i[57]
    DIRECTION INPUT ;
    USE SIGNAL ;
    PORT
      LAYER M5 ;
        RECT  102 107.916 102.024 108 ;
    END
  END rn_i[57]
  PIN rn_i[58]
    DIRECTION INPUT ;
    USE SIGNAL ;
    PORT
      LAYER M5 ;
        RECT  102.192 107.916 102.216 108 ;
    END
  END rn_i[58]
  PIN rn_i[59]
    DIRECTION INPUT ;
    USE SIGNAL ;
    PORT
      LAYER M5 ;
        RECT  102.384 107.916 102.408 108 ;
    END
  END rn_i[59]
  PIN rn_i[5]
    DIRECTION INPUT ;
    USE SIGNAL ;
    PORT
      LAYER M5 ;
        RECT  98.16 107.916 98.184 108 ;
    END
  END rn_i[5]
  PIN rn_i[60]
    DIRECTION INPUT ;
    USE SIGNAL ;
    PORT
      LAYER M5 ;
        RECT  102.576 107.916 102.6 108 ;
    END
  END rn_i[60]
  PIN rn_i[61]
    DIRECTION INPUT ;
    USE SIGNAL ;
    PORT
      LAYER M5 ;
        RECT  102.768 107.916 102.792 108 ;
    END
  END rn_i[61]
  PIN rn_i[62]
    DIRECTION INPUT ;
    USE SIGNAL ;
    PORT
      LAYER M5 ;
        RECT  102.96 107.916 102.984 108 ;
    END
  END rn_i[62]
  PIN rn_i[63]
    DIRECTION INPUT ;
    USE SIGNAL ;
    PORT
      LAYER M5 ;
        RECT  103.152 107.916 103.176 108 ;
    END
  END rn_i[63]
  PIN rn_i[64]
    DIRECTION INPUT ;
    USE SIGNAL ;
    PORT
      LAYER M5 ;
        RECT  103.344 107.916 103.368 108 ;
    END
  END rn_i[64]
  PIN rn_i[65]
    DIRECTION INPUT ;
    USE SIGNAL ;
    PORT
      LAYER M5 ;
        RECT  103.536 107.916 103.56 108 ;
    END
  END rn_i[65]
  PIN rn_i[66]
    DIRECTION INPUT ;
    USE SIGNAL ;
    PORT
      LAYER M5 ;
        RECT  103.728 107.916 103.752 108 ;
    END
  END rn_i[66]
  PIN rn_i[67]
    DIRECTION INPUT ;
    USE SIGNAL ;
    PORT
      LAYER M5 ;
        RECT  103.92 107.916 103.944 108 ;
    END
  END rn_i[67]
  PIN rn_i[68]
    DIRECTION INPUT ;
    USE SIGNAL ;
    PORT
      LAYER M5 ;
        RECT  104.112 107.916 104.136 108 ;
    END
  END rn_i[68]
  PIN rn_i[69]
    DIRECTION INPUT ;
    USE SIGNAL ;
    PORT
      LAYER M5 ;
        RECT  104.304 107.916 104.328 108 ;
    END
  END rn_i[69]
  PIN rn_i[6]
    DIRECTION INPUT ;
    USE SIGNAL ;
    PORT
      LAYER M5 ;
        RECT  98.352 107.916 98.376 108 ;
    END
  END rn_i[6]
  PIN rn_i[70]
    DIRECTION INPUT ;
    USE SIGNAL ;
    PORT
      LAYER M5 ;
        RECT  104.496 107.916 104.52 108 ;
    END
  END rn_i[70]
  PIN rn_i[71]
    DIRECTION INPUT ;
    USE SIGNAL ;
    PORT
      LAYER M5 ;
        RECT  104.688 107.916 104.712 108 ;
    END
  END rn_i[71]
  PIN rn_i[72]
    DIRECTION INPUT ;
    USE SIGNAL ;
    PORT
      LAYER M5 ;
        RECT  104.88 107.916 104.904 108 ;
    END
  END rn_i[72]
  PIN rn_i[73]
    DIRECTION INPUT ;
    USE SIGNAL ;
    PORT
      LAYER M5 ;
        RECT  105.072 107.916 105.096 108 ;
    END
  END rn_i[73]
  PIN rn_i[74]
    DIRECTION INPUT ;
    USE SIGNAL ;
    PORT
      LAYER M5 ;
        RECT  105.264 107.916 105.288 108 ;
    END
  END rn_i[74]
  PIN rn_i[75]
    DIRECTION INPUT ;
    USE SIGNAL ;
    PORT
      LAYER M5 ;
        RECT  105.456 107.916 105.48 108 ;
    END
  END rn_i[75]
  PIN rn_i[76]
    DIRECTION INPUT ;
    USE SIGNAL ;
    PORT
      LAYER M5 ;
        RECT  105.648 107.916 105.672 108 ;
    END
  END rn_i[76]
  PIN rn_i[77]
    DIRECTION INPUT ;
    USE SIGNAL ;
    PORT
      LAYER M5 ;
        RECT  105.84 107.916 105.864 108 ;
    END
  END rn_i[77]
  PIN rn_i[78]
    DIRECTION INPUT ;
    USE SIGNAL ;
    PORT
      LAYER M5 ;
        RECT  106.032 107.916 106.056 108 ;
    END
  END rn_i[78]
  PIN rn_i[79]
    DIRECTION INPUT ;
    USE SIGNAL ;
    PORT
      LAYER M5 ;
        RECT  106.224 107.916 106.248 108 ;
    END
  END rn_i[79]
  PIN rn_i[7]
    DIRECTION INPUT ;
    USE SIGNAL ;
    PORT
      LAYER M5 ;
        RECT  98.544 107.916 98.568 108 ;
    END
  END rn_i[7]
  PIN rn_i[80]
    DIRECTION INPUT ;
    USE SIGNAL ;
    PORT
      LAYER M5 ;
        RECT  106.416 107.916 106.44 108 ;
    END
  END rn_i[80]
  PIN rn_i[81]
    DIRECTION INPUT ;
    USE SIGNAL ;
    PORT
      LAYER M5 ;
        RECT  106.608 107.916 106.632 108 ;
    END
  END rn_i[81]
  PIN rn_i[82]
    DIRECTION INPUT ;
    USE SIGNAL ;
    PORT
      LAYER M5 ;
        RECT  106.8 107.916 106.824 108 ;
    END
  END rn_i[82]
  PIN rn_i[83]
    DIRECTION INPUT ;
    USE SIGNAL ;
    PORT
      LAYER M5 ;
        RECT  106.992 107.916 107.016 108 ;
    END
  END rn_i[83]
  PIN rn_i[84]
    DIRECTION INPUT ;
    USE SIGNAL ;
    PORT
      LAYER M5 ;
        RECT  107.184 107.916 107.208 108 ;
    END
  END rn_i[84]
  PIN rn_i[85]
    DIRECTION INPUT ;
    USE SIGNAL ;
    PORT
      LAYER M5 ;
        RECT  107.376 107.916 107.4 108 ;
    END
  END rn_i[85]
  PIN rn_i[86]
    DIRECTION INPUT ;
    USE SIGNAL ;
    PORT
      LAYER M5 ;
        RECT  107.568 107.916 107.592 108 ;
    END
  END rn_i[86]
  PIN rn_i[87]
    DIRECTION INPUT ;
    USE SIGNAL ;
    PORT
      LAYER M5 ;
        RECT  107.76 107.916 107.784 108 ;
    END
  END rn_i[87]
  PIN rn_i[88]
    DIRECTION INPUT ;
    USE SIGNAL ;
    PORT
      LAYER M5 ;
        RECT  120.24 107.916 120.264 108 ;
    END
  END rn_i[88]
  PIN rn_i[89]
    DIRECTION INPUT ;
    USE SIGNAL ;
    PORT
      LAYER M5 ;
        RECT  120.432 107.916 120.456 108 ;
    END
  END rn_i[89]
  PIN rn_i[8]
    DIRECTION INPUT ;
    USE SIGNAL ;
    PORT
      LAYER M5 ;
        RECT  98.736 107.916 98.76 108 ;
    END
  END rn_i[8]
  PIN rn_i[90]
    DIRECTION INPUT ;
    USE SIGNAL ;
    PORT
      LAYER M5 ;
        RECT  120.624 107.916 120.648 108 ;
    END
  END rn_i[90]
  PIN rn_i[91]
    DIRECTION INPUT ;
    USE SIGNAL ;
    PORT
      LAYER M5 ;
        RECT  120.816 107.916 120.84 108 ;
    END
  END rn_i[91]
  PIN rn_i[92]
    DIRECTION INPUT ;
    USE SIGNAL ;
    PORT
      LAYER M5 ;
        RECT  121.008 107.916 121.032 108 ;
    END
  END rn_i[92]
  PIN rn_i[93]
    DIRECTION INPUT ;
    USE SIGNAL ;
    PORT
      LAYER M5 ;
        RECT  121.2 107.916 121.224 108 ;
    END
  END rn_i[93]
  PIN rn_i[94]
    DIRECTION INPUT ;
    USE SIGNAL ;
    PORT
      LAYER M5 ;
        RECT  121.392 107.916 121.416 108 ;
    END
  END rn_i[94]
  PIN rn_i[95]
    DIRECTION INPUT ;
    USE SIGNAL ;
    PORT
      LAYER M5 ;
        RECT  121.584 107.916 121.608 108 ;
    END
  END rn_i[95]
  PIN rn_i[96]
    DIRECTION INPUT ;
    USE SIGNAL ;
    PORT
      LAYER M5 ;
        RECT  121.776 107.916 121.8 108 ;
    END
  END rn_i[96]
  PIN rn_i[97]
    DIRECTION INPUT ;
    USE SIGNAL ;
    PORT
      LAYER M5 ;
        RECT  121.968 107.916 121.992 108 ;
    END
  END rn_i[97]
  PIN rn_i[98]
    DIRECTION INPUT ;
    USE SIGNAL ;
    PORT
      LAYER M5 ;
        RECT  122.16 107.916 122.184 108 ;
    END
  END rn_i[98]
  PIN rn_i[99]
    DIRECTION INPUT ;
    USE SIGNAL ;
    PORT
      LAYER M5 ;
        RECT  122.352 107.916 122.376 108 ;
    END
  END rn_i[99]
  PIN rn_i[9]
    DIRECTION INPUT ;
    USE SIGNAL ;
    PORT
      LAYER M5 ;
        RECT  98.928 107.916 98.952 108 ;
    END
  END rn_i[9]
  PIN rn_o[0]
    DIRECTION OUTPUT ;
    USE SIGNAL ;
    PORT
      LAYER M5 ;
        RECT  168.624 107.916 168.648 108 ;
    END
  END rn_o[0]
  PIN rn_o[100]
    DIRECTION OUTPUT ;
    USE SIGNAL ;
    PORT
      LAYER M5 ;
        RECT  138.672 107.916 138.696 108 ;
    END
  END rn_o[100]
  PIN rn_o[101]
    DIRECTION OUTPUT ;
    USE SIGNAL ;
    PORT
      LAYER M5 ;
        RECT  138.864 107.916 138.888 108 ;
    END
  END rn_o[101]
  PIN rn_o[102]
    DIRECTION OUTPUT ;
    USE SIGNAL ;
    PORT
      LAYER M5 ;
        RECT  139.056 107.916 139.08 108 ;
    END
  END rn_o[102]
  PIN rn_o[103]
    DIRECTION OUTPUT ;
    USE SIGNAL ;
    PORT
      LAYER M5 ;
        RECT  139.248 107.916 139.272 108 ;
    END
  END rn_o[103]
  PIN rn_o[104]
    DIRECTION OUTPUT ;
    USE SIGNAL ;
    PORT
      LAYER M5 ;
        RECT  139.44 107.916 139.464 108 ;
    END
  END rn_o[104]
  PIN rn_o[105]
    DIRECTION OUTPUT ;
    USE SIGNAL ;
    PORT
      LAYER M5 ;
        RECT  139.632 107.916 139.656 108 ;
    END
  END rn_o[105]
  PIN rn_o[106]
    DIRECTION OUTPUT ;
    USE SIGNAL ;
    PORT
      LAYER M5 ;
        RECT  139.824 107.916 139.848 108 ;
    END
  END rn_o[106]
  PIN rn_o[107]
    DIRECTION OUTPUT ;
    USE SIGNAL ;
    PORT
      LAYER M5 ;
        RECT  140.016 107.916 140.04 108 ;
    END
  END rn_o[107]
  PIN rn_o[108]
    DIRECTION OUTPUT ;
    USE SIGNAL ;
    PORT
      LAYER M5 ;
        RECT  140.208 107.916 140.232 108 ;
    END
  END rn_o[108]
  PIN rn_o[109]
    DIRECTION OUTPUT ;
    USE SIGNAL ;
    PORT
      LAYER M5 ;
        RECT  140.4 107.916 140.424 108 ;
    END
  END rn_o[109]
  PIN rn_o[10]
    DIRECTION OUTPUT ;
    USE SIGNAL ;
    PORT
      LAYER M5 ;
        RECT  158.256 107.916 158.28 108 ;
    END
  END rn_o[10]
  PIN rn_o[110]
    DIRECTION OUTPUT ;
    USE SIGNAL ;
    PORT
      LAYER M5 ;
        RECT  140.592 107.916 140.616 108 ;
    END
  END rn_o[110]
  PIN rn_o[111]
    DIRECTION OUTPUT ;
    USE SIGNAL ;
    PORT
      LAYER M5 ;
        RECT  140.784 107.916 140.808 108 ;
    END
  END rn_o[111]
  PIN rn_o[112]
    DIRECTION OUTPUT ;
    USE SIGNAL ;
    PORT
      LAYER M5 ;
        RECT  140.976 107.916 141 108 ;
    END
  END rn_o[112]
  PIN rn_o[113]
    DIRECTION OUTPUT ;
    USE SIGNAL ;
    PORT
      LAYER M5 ;
        RECT  141.168 107.916 141.192 108 ;
    END
  END rn_o[113]
  PIN rn_o[114]
    DIRECTION OUTPUT ;
    USE SIGNAL ;
    PORT
      LAYER M5 ;
        RECT  141.36 107.916 141.384 108 ;
    END
  END rn_o[114]
  PIN rn_o[115]
    DIRECTION OUTPUT ;
    USE SIGNAL ;
    PORT
      LAYER M5 ;
        RECT  141.552 107.916 141.576 108 ;
    END
  END rn_o[115]
  PIN rn_o[116]
    DIRECTION OUTPUT ;
    USE SIGNAL ;
    PORT
      LAYER M5 ;
        RECT  141.744 107.916 141.768 108 ;
    END
  END rn_o[116]
  PIN rn_o[117]
    DIRECTION OUTPUT ;
    USE SIGNAL ;
    PORT
      LAYER M5 ;
        RECT  141.936 107.916 141.96 108 ;
    END
  END rn_o[117]
  PIN rn_o[118]
    DIRECTION OUTPUT ;
    USE SIGNAL ;
    PORT
      LAYER M5 ;
        RECT  142.128 107.916 142.152 108 ;
    END
  END rn_o[118]
  PIN rn_o[119]
    DIRECTION OUTPUT ;
    USE SIGNAL ;
    PORT
      LAYER M5 ;
        RECT  142.32 107.916 142.344 108 ;
    END
  END rn_o[119]
  PIN rn_o[11]
    DIRECTION OUTPUT ;
    USE SIGNAL ;
    PORT
      LAYER M5 ;
        RECT  158.448 107.916 158.472 108 ;
    END
  END rn_o[11]
  PIN rn_o[120]
    DIRECTION OUTPUT ;
    USE SIGNAL ;
    PORT
      LAYER M5 ;
        RECT  142.512 107.916 142.536 108 ;
    END
  END rn_o[120]
  PIN rn_o[121]
    DIRECTION OUTPUT ;
    USE SIGNAL ;
    PORT
      LAYER M5 ;
        RECT  142.704 107.916 142.728 108 ;
    END
  END rn_o[121]
  PIN rn_o[122]
    DIRECTION OUTPUT ;
    USE SIGNAL ;
    PORT
      LAYER M5 ;
        RECT  142.896 107.916 142.92 108 ;
    END
  END rn_o[122]
  PIN rn_o[123]
    DIRECTION OUTPUT ;
    USE SIGNAL ;
    PORT
      LAYER M5 ;
        RECT  143.088 107.916 143.112 108 ;
    END
  END rn_o[123]
  PIN rn_o[124]
    DIRECTION OUTPUT ;
    USE SIGNAL ;
    PORT
      LAYER M5 ;
        RECT  143.28 107.916 143.304 108 ;
    END
  END rn_o[124]
  PIN rn_o[125]
    DIRECTION OUTPUT ;
    USE SIGNAL ;
    PORT
      LAYER M5 ;
        RECT  143.472 107.916 143.496 108 ;
    END
  END rn_o[125]
  PIN rn_o[126]
    DIRECTION OUTPUT ;
    USE SIGNAL ;
    PORT
      LAYER M5 ;
        RECT  143.664 107.916 143.688 108 ;
    END
  END rn_o[126]
  PIN rn_o[127]
    DIRECTION OUTPUT ;
    USE SIGNAL ;
    PORT
      LAYER M5 ;
        RECT  143.856 107.916 143.88 108 ;
    END
  END rn_o[127]
  PIN rn_o[128]
    DIRECTION OUTPUT ;
    USE SIGNAL ;
    PORT
      LAYER M5 ;
        RECT  144.048 107.916 144.072 108 ;
    END
  END rn_o[128]
  PIN rn_o[129]
    DIRECTION OUTPUT ;
    USE SIGNAL ;
    PORT
      LAYER M5 ;
        RECT  144.24 107.916 144.264 108 ;
    END
  END rn_o[129]
  PIN rn_o[12]
    DIRECTION OUTPUT ;
    USE SIGNAL ;
    PORT
      LAYER M5 ;
        RECT  158.64 107.916 158.664 108 ;
    END
  END rn_o[12]
  PIN rn_o[130]
    DIRECTION OUTPUT ;
    USE SIGNAL ;
    PORT
      LAYER M5 ;
        RECT  144.432 107.916 144.456 108 ;
    END
  END rn_o[130]
  PIN rn_o[131]
    DIRECTION OUTPUT ;
    USE SIGNAL ;
    PORT
      LAYER M5 ;
        RECT  144.624 107.916 144.648 108 ;
    END
  END rn_o[131]
  PIN rn_o[132]
    DIRECTION OUTPUT ;
    USE SIGNAL ;
    PORT
      LAYER M5 ;
        RECT  181.68 107.916 181.704 108 ;
    END
  END rn_o[132]
  PIN rn_o[133]
    DIRECTION OUTPUT ;
    USE SIGNAL ;
    PORT
      LAYER M5 ;
        RECT  181.872 107.916 181.896 108 ;
    END
  END rn_o[133]
  PIN rn_o[134]
    DIRECTION OUTPUT ;
    USE SIGNAL ;
    PORT
      LAYER M5 ;
        RECT  182.064 107.916 182.088 108 ;
    END
  END rn_o[134]
  PIN rn_o[135]
    DIRECTION OUTPUT ;
    USE SIGNAL ;
    PORT
      LAYER M5 ;
        RECT  182.256 107.916 182.28 108 ;
    END
  END rn_o[135]
  PIN rn_o[136]
    DIRECTION OUTPUT ;
    USE SIGNAL ;
    PORT
      LAYER M5 ;
        RECT  182.448 107.916 182.472 108 ;
    END
  END rn_o[136]
  PIN rn_o[137]
    DIRECTION OUTPUT ;
    USE SIGNAL ;
    PORT
      LAYER M5 ;
        RECT  182.64 107.916 182.664 108 ;
    END
  END rn_o[137]
  PIN rn_o[138]
    DIRECTION OUTPUT ;
    USE SIGNAL ;
    PORT
      LAYER M5 ;
        RECT  182.832 107.916 182.856 108 ;
    END
  END rn_o[138]
  PIN rn_o[139]
    DIRECTION OUTPUT ;
    USE SIGNAL ;
    PORT
      LAYER M5 ;
        RECT  183.024 107.916 183.048 108 ;
    END
  END rn_o[139]
  PIN rn_o[13]
    DIRECTION OUTPUT ;
    USE SIGNAL ;
    PORT
      LAYER M5 ;
        RECT  158.832 107.916 158.856 108 ;
    END
  END rn_o[13]
  PIN rn_o[140]
    DIRECTION OUTPUT ;
    USE SIGNAL ;
    PORT
      LAYER M5 ;
        RECT  183.216 107.916 183.24 108 ;
    END
  END rn_o[140]
  PIN rn_o[141]
    DIRECTION OUTPUT ;
    USE SIGNAL ;
    PORT
      LAYER M5 ;
        RECT  183.408 107.916 183.432 108 ;
    END
  END rn_o[141]
  PIN rn_o[142]
    DIRECTION OUTPUT ;
    USE SIGNAL ;
    PORT
      LAYER M5 ;
        RECT  183.6 107.916 183.624 108 ;
    END
  END rn_o[142]
  PIN rn_o[143]
    DIRECTION OUTPUT ;
    USE SIGNAL ;
    PORT
      LAYER M5 ;
        RECT  183.792 107.916 183.816 108 ;
    END
  END rn_o[143]
  PIN rn_o[144]
    DIRECTION OUTPUT ;
    USE SIGNAL ;
    PORT
      LAYER M5 ;
        RECT  183.984 107.916 184.008 108 ;
    END
  END rn_o[144]
  PIN rn_o[145]
    DIRECTION OUTPUT ;
    USE SIGNAL ;
    PORT
      LAYER M5 ;
        RECT  184.176 107.916 184.2 108 ;
    END
  END rn_o[145]
  PIN rn_o[146]
    DIRECTION OUTPUT ;
    USE SIGNAL ;
    PORT
      LAYER M5 ;
        RECT  184.368 107.916 184.392 108 ;
    END
  END rn_o[146]
  PIN rn_o[147]
    DIRECTION OUTPUT ;
    USE SIGNAL ;
    PORT
      LAYER M5 ;
        RECT  184.56 107.916 184.584 108 ;
    END
  END rn_o[147]
  PIN rn_o[148]
    DIRECTION OUTPUT ;
    USE SIGNAL ;
    PORT
      LAYER M5 ;
        RECT  184.752 107.916 184.776 108 ;
    END
  END rn_o[148]
  PIN rn_o[149]
    DIRECTION OUTPUT ;
    USE SIGNAL ;
    PORT
      LAYER M5 ;
        RECT  184.944 107.916 184.968 108 ;
    END
  END rn_o[149]
  PIN rn_o[14]
    DIRECTION OUTPUT ;
    USE SIGNAL ;
    PORT
      LAYER M5 ;
        RECT  159.024 107.916 159.048 108 ;
    END
  END rn_o[14]
  PIN rn_o[150]
    DIRECTION OUTPUT ;
    USE SIGNAL ;
    PORT
      LAYER M5 ;
        RECT  185.136 107.916 185.16 108 ;
    END
  END rn_o[150]
  PIN rn_o[151]
    DIRECTION OUTPUT ;
    USE SIGNAL ;
    PORT
      LAYER M5 ;
        RECT  185.328 107.916 185.352 108 ;
    END
  END rn_o[151]
  PIN rn_o[152]
    DIRECTION OUTPUT ;
    USE SIGNAL ;
    PORT
      LAYER M5 ;
        RECT  185.52 107.916 185.544 108 ;
    END
  END rn_o[152]
  PIN rn_o[153]
    DIRECTION OUTPUT ;
    USE SIGNAL ;
    PORT
      LAYER M5 ;
        RECT  185.712 107.916 185.736 108 ;
    END
  END rn_o[153]
  PIN rn_o[154]
    DIRECTION OUTPUT ;
    USE SIGNAL ;
    PORT
      LAYER M5 ;
        RECT  185.904 107.916 185.928 108 ;
    END
  END rn_o[154]
  PIN rn_o[155]
    DIRECTION OUTPUT ;
    USE SIGNAL ;
    PORT
      LAYER M5 ;
        RECT  186.096 107.916 186.12 108 ;
    END
  END rn_o[155]
  PIN rn_o[156]
    DIRECTION OUTPUT ;
    USE SIGNAL ;
    PORT
      LAYER M5 ;
        RECT  186.288 107.916 186.312 108 ;
    END
  END rn_o[156]
  PIN rn_o[157]
    DIRECTION OUTPUT ;
    USE SIGNAL ;
    PORT
      LAYER M5 ;
        RECT  186.48 107.916 186.504 108 ;
    END
  END rn_o[157]
  PIN rn_o[158]
    DIRECTION OUTPUT ;
    USE SIGNAL ;
    PORT
      LAYER M5 ;
        RECT  186.672 107.916 186.696 108 ;
    END
  END rn_o[158]
  PIN rn_o[159]
    DIRECTION OUTPUT ;
    USE SIGNAL ;
    PORT
      LAYER M5 ;
        RECT  186.864 107.916 186.888 108 ;
    END
  END rn_o[159]
  PIN rn_o[15]
    DIRECTION OUTPUT ;
    USE SIGNAL ;
    PORT
      LAYER M5 ;
        RECT  159.216 107.916 159.24 108 ;
    END
  END rn_o[15]
  PIN rn_o[160]
    DIRECTION OUTPUT ;
    USE SIGNAL ;
    PORT
      LAYER M5 ;
        RECT  187.056 107.916 187.08 108 ;
    END
  END rn_o[160]
  PIN rn_o[161]
    DIRECTION OUTPUT ;
    USE SIGNAL ;
    PORT
      LAYER M5 ;
        RECT  187.248 107.916 187.272 108 ;
    END
  END rn_o[161]
  PIN rn_o[162]
    DIRECTION OUTPUT ;
    USE SIGNAL ;
    PORT
      LAYER M5 ;
        RECT  187.44 107.916 187.464 108 ;
    END
  END rn_o[162]
  PIN rn_o[163]
    DIRECTION OUTPUT ;
    USE SIGNAL ;
    PORT
      LAYER M5 ;
        RECT  187.632 107.916 187.656 108 ;
    END
  END rn_o[163]
  PIN rn_o[164]
    DIRECTION OUTPUT ;
    USE SIGNAL ;
    PORT
      LAYER M5 ;
        RECT  175.536 107.916 175.56 108 ;
    END
  END rn_o[164]
  PIN rn_o[165]
    DIRECTION OUTPUT ;
    USE SIGNAL ;
    PORT
      LAYER M5 ;
        RECT  175.728 107.916 175.752 108 ;
    END
  END rn_o[165]
  PIN rn_o[166]
    DIRECTION OUTPUT ;
    USE SIGNAL ;
    PORT
      LAYER M5 ;
        RECT  175.92 107.916 175.944 108 ;
    END
  END rn_o[166]
  PIN rn_o[167]
    DIRECTION OUTPUT ;
    USE SIGNAL ;
    PORT
      LAYER M5 ;
        RECT  176.112 107.916 176.136 108 ;
    END
  END rn_o[167]
  PIN rn_o[168]
    DIRECTION OUTPUT ;
    USE SIGNAL ;
    PORT
      LAYER M5 ;
        RECT  176.304 107.916 176.328 108 ;
    END
  END rn_o[168]
  PIN rn_o[169]
    DIRECTION OUTPUT ;
    USE SIGNAL ;
    PORT
      LAYER M5 ;
        RECT  176.496 107.916 176.52 108 ;
    END
  END rn_o[169]
  PIN rn_o[16]
    DIRECTION OUTPUT ;
    USE SIGNAL ;
    PORT
      LAYER M5 ;
        RECT  159.408 107.916 159.432 108 ;
    END
  END rn_o[16]
  PIN rn_o[170]
    DIRECTION OUTPUT ;
    USE SIGNAL ;
    PORT
      LAYER M5 ;
        RECT  176.688 107.916 176.712 108 ;
    END
  END rn_o[170]
  PIN rn_o[171]
    DIRECTION OUTPUT ;
    USE SIGNAL ;
    PORT
      LAYER M5 ;
        RECT  176.88 107.916 176.904 108 ;
    END
  END rn_o[171]
  PIN rn_o[172]
    DIRECTION OUTPUT ;
    USE SIGNAL ;
    PORT
      LAYER M5 ;
        RECT  177.072 107.916 177.096 108 ;
    END
  END rn_o[172]
  PIN rn_o[173]
    DIRECTION OUTPUT ;
    USE SIGNAL ;
    PORT
      LAYER M5 ;
        RECT  177.264 107.916 177.288 108 ;
    END
  END rn_o[173]
  PIN rn_o[174]
    DIRECTION OUTPUT ;
    USE SIGNAL ;
    PORT
      LAYER M5 ;
        RECT  177.456 107.916 177.48 108 ;
    END
  END rn_o[174]
  PIN rn_o[175]
    DIRECTION OUTPUT ;
    USE SIGNAL ;
    PORT
      LAYER M5 ;
        RECT  177.648 107.916 177.672 108 ;
    END
  END rn_o[175]
  PIN rn_o[176]
    DIRECTION OUTPUT ;
    USE SIGNAL ;
    PORT
      LAYER M5 ;
        RECT  177.84 107.916 177.864 108 ;
    END
  END rn_o[176]
  PIN rn_o[177]
    DIRECTION OUTPUT ;
    USE SIGNAL ;
    PORT
      LAYER M5 ;
        RECT  178.032 107.916 178.056 108 ;
    END
  END rn_o[177]
  PIN rn_o[178]
    DIRECTION OUTPUT ;
    USE SIGNAL ;
    PORT
      LAYER M5 ;
        RECT  178.224 107.916 178.248 108 ;
    END
  END rn_o[178]
  PIN rn_o[179]
    DIRECTION OUTPUT ;
    USE SIGNAL ;
    PORT
      LAYER M5 ;
        RECT  178.416 107.916 178.44 108 ;
    END
  END rn_o[179]
  PIN rn_o[17]
    DIRECTION OUTPUT ;
    USE SIGNAL ;
    PORT
      LAYER M5 ;
        RECT  159.6 107.916 159.624 108 ;
    END
  END rn_o[17]
  PIN rn_o[180]
    DIRECTION OUTPUT ;
    USE SIGNAL ;
    PORT
      LAYER M5 ;
        RECT  178.608 107.916 178.632 108 ;
    END
  END rn_o[180]
  PIN rn_o[181]
    DIRECTION OUTPUT ;
    USE SIGNAL ;
    PORT
      LAYER M5 ;
        RECT  178.8 107.916 178.824 108 ;
    END
  END rn_o[181]
  PIN rn_o[182]
    DIRECTION OUTPUT ;
    USE SIGNAL ;
    PORT
      LAYER M5 ;
        RECT  178.992 107.916 179.016 108 ;
    END
  END rn_o[182]
  PIN rn_o[183]
    DIRECTION OUTPUT ;
    USE SIGNAL ;
    PORT
      LAYER M5 ;
        RECT  179.184 107.916 179.208 108 ;
    END
  END rn_o[183]
  PIN rn_o[184]
    DIRECTION OUTPUT ;
    USE SIGNAL ;
    PORT
      LAYER M5 ;
        RECT  179.376 107.916 179.4 108 ;
    END
  END rn_o[184]
  PIN rn_o[185]
    DIRECTION OUTPUT ;
    USE SIGNAL ;
    PORT
      LAYER M5 ;
        RECT  179.568 107.916 179.592 108 ;
    END
  END rn_o[185]
  PIN rn_o[186]
    DIRECTION OUTPUT ;
    USE SIGNAL ;
    PORT
      LAYER M5 ;
        RECT  179.76 107.916 179.784 108 ;
    END
  END rn_o[186]
  PIN rn_o[187]
    DIRECTION OUTPUT ;
    USE SIGNAL ;
    PORT
      LAYER M5 ;
        RECT  179.952 107.916 179.976 108 ;
    END
  END rn_o[187]
  PIN rn_o[188]
    DIRECTION OUTPUT ;
    USE SIGNAL ;
    PORT
      LAYER M5 ;
        RECT  180.144 107.916 180.168 108 ;
    END
  END rn_o[188]
  PIN rn_o[189]
    DIRECTION OUTPUT ;
    USE SIGNAL ;
    PORT
      LAYER M5 ;
        RECT  180.336 107.916 180.36 108 ;
    END
  END rn_o[189]
  PIN rn_o[18]
    DIRECTION OUTPUT ;
    USE SIGNAL ;
    PORT
      LAYER M5 ;
        RECT  159.792 107.916 159.816 108 ;
    END
  END rn_o[18]
  PIN rn_o[190]
    DIRECTION OUTPUT ;
    USE SIGNAL ;
    PORT
      LAYER M5 ;
        RECT  180.528 107.916 180.552 108 ;
    END
  END rn_o[190]
  PIN rn_o[191]
    DIRECTION OUTPUT ;
    USE SIGNAL ;
    PORT
      LAYER M5 ;
        RECT  180.72 107.916 180.744 108 ;
    END
  END rn_o[191]
  PIN rn_o[192]
    DIRECTION OUTPUT ;
    USE SIGNAL ;
    PORT
      LAYER M5 ;
        RECT  180.912 107.916 180.936 108 ;
    END
  END rn_o[192]
  PIN rn_o[193]
    DIRECTION OUTPUT ;
    USE SIGNAL ;
    PORT
      LAYER M5 ;
        RECT  181.104 107.916 181.128 108 ;
    END
  END rn_o[193]
  PIN rn_o[194]
    DIRECTION OUTPUT ;
    USE SIGNAL ;
    PORT
      LAYER M5 ;
        RECT  181.296 107.916 181.32 108 ;
    END
  END rn_o[194]
  PIN rn_o[195]
    DIRECTION OUTPUT ;
    USE SIGNAL ;
    PORT
      LAYER M5 ;
        RECT  181.488 107.916 181.512 108 ;
    END
  END rn_o[195]
  PIN rn_o[196]
    DIRECTION OUTPUT ;
    USE SIGNAL ;
    PORT
      LAYER M5 ;
        RECT  193.968 107.916 193.992 108 ;
    END
  END rn_o[196]
  PIN rn_o[197]
    DIRECTION OUTPUT ;
    USE SIGNAL ;
    PORT
      LAYER M5 ;
        RECT  194.16 107.916 194.184 108 ;
    END
  END rn_o[197]
  PIN rn_o[198]
    DIRECTION OUTPUT ;
    USE SIGNAL ;
    PORT
      LAYER M5 ;
        RECT  194.352 107.916 194.376 108 ;
    END
  END rn_o[198]
  PIN rn_o[199]
    DIRECTION OUTPUT ;
    USE SIGNAL ;
    PORT
      LAYER M5 ;
        RECT  194.544 107.916 194.568 108 ;
    END
  END rn_o[199]
  PIN rn_o[19]
    DIRECTION OUTPUT ;
    USE SIGNAL ;
    PORT
      LAYER M5 ;
        RECT  159.984 107.916 160.008 108 ;
    END
  END rn_o[19]
  PIN rn_o[1]
    DIRECTION OUTPUT ;
    USE SIGNAL ;
    PORT
      LAYER M5 ;
        RECT  168.816 107.916 168.84 108 ;
    END
  END rn_o[1]
  PIN rn_o[200]
    DIRECTION OUTPUT ;
    USE SIGNAL ;
    PORT
      LAYER M5 ;
        RECT  194.736 107.916 194.76 108 ;
    END
  END rn_o[200]
  PIN rn_o[201]
    DIRECTION OUTPUT ;
    USE SIGNAL ;
    PORT
      LAYER M5 ;
        RECT  194.928 107.916 194.952 108 ;
    END
  END rn_o[201]
  PIN rn_o[202]
    DIRECTION OUTPUT ;
    USE SIGNAL ;
    PORT
      LAYER M5 ;
        RECT  195.12 107.916 195.144 108 ;
    END
  END rn_o[202]
  PIN rn_o[203]
    DIRECTION OUTPUT ;
    USE SIGNAL ;
    PORT
      LAYER M5 ;
        RECT  195.312 107.916 195.336 108 ;
    END
  END rn_o[203]
  PIN rn_o[204]
    DIRECTION OUTPUT ;
    USE SIGNAL ;
    PORT
      LAYER M5 ;
        RECT  195.504 107.916 195.528 108 ;
    END
  END rn_o[204]
  PIN rn_o[205]
    DIRECTION OUTPUT ;
    USE SIGNAL ;
    PORT
      LAYER M5 ;
        RECT  195.696 107.916 195.72 108 ;
    END
  END rn_o[205]
  PIN rn_o[206]
    DIRECTION OUTPUT ;
    USE SIGNAL ;
    PORT
      LAYER M5 ;
        RECT  195.888 107.916 195.912 108 ;
    END
  END rn_o[206]
  PIN rn_o[207]
    DIRECTION OUTPUT ;
    USE SIGNAL ;
    PORT
      LAYER M5 ;
        RECT  196.08 107.916 196.104 108 ;
    END
  END rn_o[207]
  PIN rn_o[208]
    DIRECTION OUTPUT ;
    USE SIGNAL ;
    PORT
      LAYER M5 ;
        RECT  196.272 107.916 196.296 108 ;
    END
  END rn_o[208]
  PIN rn_o[209]
    DIRECTION OUTPUT ;
    USE SIGNAL ;
    PORT
      LAYER M5 ;
        RECT  196.464 107.916 196.488 108 ;
    END
  END rn_o[209]
  PIN rn_o[20]
    DIRECTION OUTPUT ;
    USE SIGNAL ;
    PORT
      LAYER M5 ;
        RECT  160.176 107.916 160.2 108 ;
    END
  END rn_o[20]
  PIN rn_o[210]
    DIRECTION OUTPUT ;
    USE SIGNAL ;
    PORT
      LAYER M5 ;
        RECT  196.656 107.916 196.68 108 ;
    END
  END rn_o[210]
  PIN rn_o[211]
    DIRECTION OUTPUT ;
    USE SIGNAL ;
    PORT
      LAYER M5 ;
        RECT  196.848 107.916 196.872 108 ;
    END
  END rn_o[211]
  PIN rn_o[212]
    DIRECTION OUTPUT ;
    USE SIGNAL ;
    PORT
      LAYER M5 ;
        RECT  197.04 107.916 197.064 108 ;
    END
  END rn_o[212]
  PIN rn_o[213]
    DIRECTION OUTPUT ;
    USE SIGNAL ;
    PORT
      LAYER M5 ;
        RECT  197.232 107.916 197.256 108 ;
    END
  END rn_o[213]
  PIN rn_o[214]
    DIRECTION OUTPUT ;
    USE SIGNAL ;
    PORT
      LAYER M5 ;
        RECT  197.424 107.916 197.448 108 ;
    END
  END rn_o[214]
  PIN rn_o[215]
    DIRECTION OUTPUT ;
    USE SIGNAL ;
    PORT
      LAYER M5 ;
        RECT  197.616 107.916 197.64 108 ;
    END
  END rn_o[215]
  PIN rn_o[216]
    DIRECTION OUTPUT ;
    USE SIGNAL ;
    PORT
      LAYER M5 ;
        RECT  197.808 107.916 197.832 108 ;
    END
  END rn_o[216]
  PIN rn_o[217]
    DIRECTION OUTPUT ;
    USE SIGNAL ;
    PORT
      LAYER M5 ;
        RECT  198 107.916 198.024 108 ;
    END
  END rn_o[217]
  PIN rn_o[218]
    DIRECTION OUTPUT ;
    USE SIGNAL ;
    PORT
      LAYER M5 ;
        RECT  198.192 107.916 198.216 108 ;
    END
  END rn_o[218]
  PIN rn_o[219]
    DIRECTION OUTPUT ;
    USE SIGNAL ;
    PORT
      LAYER M5 ;
        RECT  198.384 107.916 198.408 108 ;
    END
  END rn_o[219]
  PIN rn_o[21]
    DIRECTION OUTPUT ;
    USE SIGNAL ;
    PORT
      LAYER M5 ;
        RECT  160.368 107.916 160.392 108 ;
    END
  END rn_o[21]
  PIN rn_o[220]
    DIRECTION OUTPUT ;
    USE SIGNAL ;
    PORT
      LAYER M5 ;
        RECT  198.576 107.916 198.6 108 ;
    END
  END rn_o[220]
  PIN rn_o[221]
    DIRECTION OUTPUT ;
    USE SIGNAL ;
    PORT
      LAYER M5 ;
        RECT  198.768 107.916 198.792 108 ;
    END
  END rn_o[221]
  PIN rn_o[222]
    DIRECTION OUTPUT ;
    USE SIGNAL ;
    PORT
      LAYER M5 ;
        RECT  198.96 107.916 198.984 108 ;
    END
  END rn_o[222]
  PIN rn_o[223]
    DIRECTION OUTPUT ;
    USE SIGNAL ;
    PORT
      LAYER M5 ;
        RECT  199.152 107.916 199.176 108 ;
    END
  END rn_o[223]
  PIN rn_o[224]
    DIRECTION OUTPUT ;
    USE SIGNAL ;
    PORT
      LAYER M5 ;
        RECT  199.344 107.916 199.368 108 ;
    END
  END rn_o[224]
  PIN rn_o[225]
    DIRECTION OUTPUT ;
    USE SIGNAL ;
    PORT
      LAYER M5 ;
        RECT  199.536 107.916 199.56 108 ;
    END
  END rn_o[225]
  PIN rn_o[226]
    DIRECTION OUTPUT ;
    USE SIGNAL ;
    PORT
      LAYER M5 ;
        RECT  199.728 107.916 199.752 108 ;
    END
  END rn_o[226]
  PIN rn_o[227]
    DIRECTION OUTPUT ;
    USE SIGNAL ;
    PORT
      LAYER M5 ;
        RECT  199.92 107.916 199.944 108 ;
    END
  END rn_o[227]
  PIN rn_o[228]
    DIRECTION OUTPUT ;
    USE SIGNAL ;
    PORT
      LAYER M5 ;
        RECT  187.824 107.916 187.848 108 ;
    END
  END rn_o[228]
  PIN rn_o[229]
    DIRECTION OUTPUT ;
    USE SIGNAL ;
    PORT
      LAYER M5 ;
        RECT  188.016 107.916 188.04 108 ;
    END
  END rn_o[229]
  PIN rn_o[22]
    DIRECTION OUTPUT ;
    USE SIGNAL ;
    PORT
      LAYER M5 ;
        RECT  160.56 107.916 160.584 108 ;
    END
  END rn_o[22]
  PIN rn_o[230]
    DIRECTION OUTPUT ;
    USE SIGNAL ;
    PORT
      LAYER M5 ;
        RECT  188.208 107.916 188.232 108 ;
    END
  END rn_o[230]
  PIN rn_o[231]
    DIRECTION OUTPUT ;
    USE SIGNAL ;
    PORT
      LAYER M5 ;
        RECT  188.4 107.916 188.424 108 ;
    END
  END rn_o[231]
  PIN rn_o[232]
    DIRECTION OUTPUT ;
    USE SIGNAL ;
    PORT
      LAYER M5 ;
        RECT  188.592 107.916 188.616 108 ;
    END
  END rn_o[232]
  PIN rn_o[233]
    DIRECTION OUTPUT ;
    USE SIGNAL ;
    PORT
      LAYER M5 ;
        RECT  188.784 107.916 188.808 108 ;
    END
  END rn_o[233]
  PIN rn_o[234]
    DIRECTION OUTPUT ;
    USE SIGNAL ;
    PORT
      LAYER M5 ;
        RECT  188.976 107.916 189 108 ;
    END
  END rn_o[234]
  PIN rn_o[235]
    DIRECTION OUTPUT ;
    USE SIGNAL ;
    PORT
      LAYER M5 ;
        RECT  189.168 107.916 189.192 108 ;
    END
  END rn_o[235]
  PIN rn_o[236]
    DIRECTION OUTPUT ;
    USE SIGNAL ;
    PORT
      LAYER M5 ;
        RECT  189.36 107.916 189.384 108 ;
    END
  END rn_o[236]
  PIN rn_o[237]
    DIRECTION OUTPUT ;
    USE SIGNAL ;
    PORT
      LAYER M5 ;
        RECT  189.552 107.916 189.576 108 ;
    END
  END rn_o[237]
  PIN rn_o[238]
    DIRECTION OUTPUT ;
    USE SIGNAL ;
    PORT
      LAYER M5 ;
        RECT  189.744 107.916 189.768 108 ;
    END
  END rn_o[238]
  PIN rn_o[239]
    DIRECTION OUTPUT ;
    USE SIGNAL ;
    PORT
      LAYER M5 ;
        RECT  189.936 107.916 189.96 108 ;
    END
  END rn_o[239]
  PIN rn_o[23]
    DIRECTION OUTPUT ;
    USE SIGNAL ;
    PORT
      LAYER M5 ;
        RECT  160.752 107.916 160.776 108 ;
    END
  END rn_o[23]
  PIN rn_o[240]
    DIRECTION OUTPUT ;
    USE SIGNAL ;
    PORT
      LAYER M5 ;
        RECT  190.128 107.916 190.152 108 ;
    END
  END rn_o[240]
  PIN rn_o[241]
    DIRECTION OUTPUT ;
    USE SIGNAL ;
    PORT
      LAYER M5 ;
        RECT  190.32 107.916 190.344 108 ;
    END
  END rn_o[241]
  PIN rn_o[242]
    DIRECTION OUTPUT ;
    USE SIGNAL ;
    PORT
      LAYER M5 ;
        RECT  190.512 107.916 190.536 108 ;
    END
  END rn_o[242]
  PIN rn_o[243]
    DIRECTION OUTPUT ;
    USE SIGNAL ;
    PORT
      LAYER M5 ;
        RECT  190.704 107.916 190.728 108 ;
    END
  END rn_o[243]
  PIN rn_o[244]
    DIRECTION OUTPUT ;
    USE SIGNAL ;
    PORT
      LAYER M5 ;
        RECT  190.896 107.916 190.92 108 ;
    END
  END rn_o[244]
  PIN rn_o[245]
    DIRECTION OUTPUT ;
    USE SIGNAL ;
    PORT
      LAYER M5 ;
        RECT  191.088 107.916 191.112 108 ;
    END
  END rn_o[245]
  PIN rn_o[246]
    DIRECTION OUTPUT ;
    USE SIGNAL ;
    PORT
      LAYER M5 ;
        RECT  191.28 107.916 191.304 108 ;
    END
  END rn_o[246]
  PIN rn_o[247]
    DIRECTION OUTPUT ;
    USE SIGNAL ;
    PORT
      LAYER M5 ;
        RECT  191.472 107.916 191.496 108 ;
    END
  END rn_o[247]
  PIN rn_o[248]
    DIRECTION OUTPUT ;
    USE SIGNAL ;
    PORT
      LAYER M5 ;
        RECT  191.664 107.916 191.688 108 ;
    END
  END rn_o[248]
  PIN rn_o[249]
    DIRECTION OUTPUT ;
    USE SIGNAL ;
    PORT
      LAYER M5 ;
        RECT  191.856 107.916 191.88 108 ;
    END
  END rn_o[249]
  PIN rn_o[24]
    DIRECTION OUTPUT ;
    USE SIGNAL ;
    PORT
      LAYER M5 ;
        RECT  160.944 107.916 160.968 108 ;
    END
  END rn_o[24]
  PIN rn_o[250]
    DIRECTION OUTPUT ;
    USE SIGNAL ;
    PORT
      LAYER M5 ;
        RECT  192.048 107.916 192.072 108 ;
    END
  END rn_o[250]
  PIN rn_o[251]
    DIRECTION OUTPUT ;
    USE SIGNAL ;
    PORT
      LAYER M5 ;
        RECT  192.24 107.916 192.264 108 ;
    END
  END rn_o[251]
  PIN rn_o[252]
    DIRECTION OUTPUT ;
    USE SIGNAL ;
    PORT
      LAYER M5 ;
        RECT  192.432 107.916 192.456 108 ;
    END
  END rn_o[252]
  PIN rn_o[253]
    DIRECTION OUTPUT ;
    USE SIGNAL ;
    PORT
      LAYER M5 ;
        RECT  192.624 107.916 192.648 108 ;
    END
  END rn_o[253]
  PIN rn_o[254]
    DIRECTION OUTPUT ;
    USE SIGNAL ;
    PORT
      LAYER M5 ;
        RECT  192.816 107.916 192.84 108 ;
    END
  END rn_o[254]
  PIN rn_o[255]
    DIRECTION OUTPUT ;
    USE SIGNAL ;
    PORT
      LAYER M5 ;
        RECT  193.008 107.916 193.032 108 ;
    END
  END rn_o[255]
  PIN rn_o[256]
    DIRECTION OUTPUT ;
    USE SIGNAL ;
    PORT
      LAYER M5 ;
        RECT  193.2 107.916 193.224 108 ;
    END
  END rn_o[256]
  PIN rn_o[257]
    DIRECTION OUTPUT ;
    USE SIGNAL ;
    PORT
      LAYER M5 ;
        RECT  193.392 107.916 193.416 108 ;
    END
  END rn_o[257]
  PIN rn_o[258]
    DIRECTION OUTPUT ;
    USE SIGNAL ;
    PORT
      LAYER M5 ;
        RECT  193.584 107.916 193.608 108 ;
    END
  END rn_o[258]
  PIN rn_o[259]
    DIRECTION OUTPUT ;
    USE SIGNAL ;
    PORT
      LAYER M5 ;
        RECT  193.776 107.916 193.8 108 ;
    END
  END rn_o[259]
  PIN rn_o[25]
    DIRECTION OUTPUT ;
    USE SIGNAL ;
    PORT
      LAYER M5 ;
        RECT  161.136 107.916 161.16 108 ;
    END
  END rn_o[25]
  PIN rn_o[260]
    DIRECTION OUTPUT ;
    USE SIGNAL ;
    PORT
      LAYER M5 ;
        RECT  200.112 107.916 200.136 108 ;
    END
  END rn_o[260]
  PIN rn_o[261]
    DIRECTION OUTPUT ;
    USE SIGNAL ;
    PORT
      LAYER M5 ;
        RECT  200.304 107.916 200.328 108 ;
    END
  END rn_o[261]
  PIN rn_o[262]
    DIRECTION OUTPUT ;
    USE SIGNAL ;
    PORT
      LAYER M5 ;
        RECT  200.496 107.916 200.52 108 ;
    END
  END rn_o[262]
  PIN rn_o[263]
    DIRECTION OUTPUT ;
    USE SIGNAL ;
    PORT
      LAYER M5 ;
        RECT  200.688 107.916 200.712 108 ;
    END
  END rn_o[263]
  PIN rn_o[264]
    DIRECTION OUTPUT ;
    USE SIGNAL ;
    PORT
      LAYER M5 ;
        RECT  200.88 107.916 200.904 108 ;
    END
  END rn_o[264]
  PIN rn_o[265]
    DIRECTION OUTPUT ;
    USE SIGNAL ;
    PORT
      LAYER M5 ;
        RECT  201.072 107.916 201.096 108 ;
    END
  END rn_o[265]
  PIN rn_o[266]
    DIRECTION OUTPUT ;
    USE SIGNAL ;
    PORT
      LAYER M5 ;
        RECT  201.264 107.916 201.288 108 ;
    END
  END rn_o[266]
  PIN rn_o[267]
    DIRECTION OUTPUT ;
    USE SIGNAL ;
    PORT
      LAYER M5 ;
        RECT  201.456 107.916 201.48 108 ;
    END
  END rn_o[267]
  PIN rn_o[268]
    DIRECTION OUTPUT ;
    USE SIGNAL ;
    PORT
      LAYER M5 ;
        RECT  201.648 107.916 201.672 108 ;
    END
  END rn_o[268]
  PIN rn_o[269]
    DIRECTION OUTPUT ;
    USE SIGNAL ;
    PORT
      LAYER M5 ;
        RECT  201.84 107.916 201.864 108 ;
    END
  END rn_o[269]
  PIN rn_o[26]
    DIRECTION OUTPUT ;
    USE SIGNAL ;
    PORT
      LAYER M5 ;
        RECT  161.328 107.916 161.352 108 ;
    END
  END rn_o[26]
  PIN rn_o[270]
    DIRECTION OUTPUT ;
    USE SIGNAL ;
    PORT
      LAYER M5 ;
        RECT  202.032 107.916 202.056 108 ;
    END
  END rn_o[270]
  PIN rn_o[271]
    DIRECTION OUTPUT ;
    USE SIGNAL ;
    PORT
      LAYER M5 ;
        RECT  202.224 107.916 202.248 108 ;
    END
  END rn_o[271]
  PIN rn_o[272]
    DIRECTION OUTPUT ;
    USE SIGNAL ;
    PORT
      LAYER M5 ;
        RECT  202.416 107.916 202.44 108 ;
    END
  END rn_o[272]
  PIN rn_o[273]
    DIRECTION OUTPUT ;
    USE SIGNAL ;
    PORT
      LAYER M5 ;
        RECT  202.608 107.916 202.632 108 ;
    END
  END rn_o[273]
  PIN rn_o[274]
    DIRECTION OUTPUT ;
    USE SIGNAL ;
    PORT
      LAYER M5 ;
        RECT  202.8 107.916 202.824 108 ;
    END
  END rn_o[274]
  PIN rn_o[275]
    DIRECTION OUTPUT ;
    USE SIGNAL ;
    PORT
      LAYER M5 ;
        RECT  202.992 107.916 203.016 108 ;
    END
  END rn_o[275]
  PIN rn_o[27]
    DIRECTION OUTPUT ;
    USE SIGNAL ;
    PORT
      LAYER M5 ;
        RECT  161.52 107.916 161.544 108 ;
    END
  END rn_o[27]
  PIN rn_o[28]
    DIRECTION OUTPUT ;
    USE SIGNAL ;
    PORT
      LAYER M5 ;
        RECT  161.712 107.916 161.736 108 ;
    END
  END rn_o[28]
  PIN rn_o[29]
    DIRECTION OUTPUT ;
    USE SIGNAL ;
    PORT
      LAYER M5 ;
        RECT  161.904 107.916 161.928 108 ;
    END
  END rn_o[29]
  PIN rn_o[2]
    DIRECTION OUTPUT ;
    USE SIGNAL ;
    PORT
      LAYER M5 ;
        RECT  169.008 107.916 169.032 108 ;
    END
  END rn_o[2]
  PIN rn_o[30]
    DIRECTION OUTPUT ;
    USE SIGNAL ;
    PORT
      LAYER M5 ;
        RECT  162.096 107.916 162.12 108 ;
    END
  END rn_o[30]
  PIN rn_o[31]
    DIRECTION OUTPUT ;
    USE SIGNAL ;
    PORT
      LAYER M5 ;
        RECT  162.288 107.916 162.312 108 ;
    END
  END rn_o[31]
  PIN rn_o[32]
    DIRECTION OUTPUT ;
    USE SIGNAL ;
    PORT
      LAYER M5 ;
        RECT  162.48 107.916 162.504 108 ;
    END
  END rn_o[32]
  PIN rn_o[33]
    DIRECTION OUTPUT ;
    USE SIGNAL ;
    PORT
      LAYER M5 ;
        RECT  162.672 107.916 162.696 108 ;
    END
  END rn_o[33]
  PIN rn_o[34]
    DIRECTION OUTPUT ;
    USE SIGNAL ;
    PORT
      LAYER M5 ;
        RECT  162.864 107.916 162.888 108 ;
    END
  END rn_o[34]
  PIN rn_o[35]
    DIRECTION OUTPUT ;
    USE SIGNAL ;
    PORT
      LAYER M5 ;
        RECT  163.056 107.916 163.08 108 ;
    END
  END rn_o[35]
  PIN rn_o[36]
    DIRECTION OUTPUT ;
    USE SIGNAL ;
    PORT
      LAYER M5 ;
        RECT  169.392 107.916 169.416 108 ;
    END
  END rn_o[36]
  PIN rn_o[37]
    DIRECTION OUTPUT ;
    USE SIGNAL ;
    PORT
      LAYER M5 ;
        RECT  169.584 107.916 169.608 108 ;
    END
  END rn_o[37]
  PIN rn_o[38]
    DIRECTION OUTPUT ;
    USE SIGNAL ;
    PORT
      LAYER M5 ;
        RECT  169.776 107.916 169.8 108 ;
    END
  END rn_o[38]
  PIN rn_o[39]
    DIRECTION OUTPUT ;
    USE SIGNAL ;
    PORT
      LAYER M5 ;
        RECT  169.968 107.916 169.992 108 ;
    END
  END rn_o[39]
  PIN rn_o[3]
    DIRECTION OUTPUT ;
    USE SIGNAL ;
    PORT
      LAYER M5 ;
        RECT  169.2 107.916 169.224 108 ;
    END
  END rn_o[3]
  PIN rn_o[40]
    DIRECTION OUTPUT ;
    USE SIGNAL ;
    PORT
      LAYER M5 ;
        RECT  170.16 107.916 170.184 108 ;
    END
  END rn_o[40]
  PIN rn_o[41]
    DIRECTION OUTPUT ;
    USE SIGNAL ;
    PORT
      LAYER M5 ;
        RECT  170.352 107.916 170.376 108 ;
    END
  END rn_o[41]
  PIN rn_o[42]
    DIRECTION OUTPUT ;
    USE SIGNAL ;
    PORT
      LAYER M5 ;
        RECT  170.544 107.916 170.568 108 ;
    END
  END rn_o[42]
  PIN rn_o[43]
    DIRECTION OUTPUT ;
    USE SIGNAL ;
    PORT
      LAYER M5 ;
        RECT  170.736 107.916 170.76 108 ;
    END
  END rn_o[43]
  PIN rn_o[44]
    DIRECTION OUTPUT ;
    USE SIGNAL ;
    PORT
      LAYER M5 ;
        RECT  170.928 107.916 170.952 108 ;
    END
  END rn_o[44]
  PIN rn_o[45]
    DIRECTION OUTPUT ;
    USE SIGNAL ;
    PORT
      LAYER M5 ;
        RECT  171.12 107.916 171.144 108 ;
    END
  END rn_o[45]
  PIN rn_o[46]
    DIRECTION OUTPUT ;
    USE SIGNAL ;
    PORT
      LAYER M5 ;
        RECT  171.312 107.916 171.336 108 ;
    END
  END rn_o[46]
  PIN rn_o[47]
    DIRECTION OUTPUT ;
    USE SIGNAL ;
    PORT
      LAYER M5 ;
        RECT  171.504 107.916 171.528 108 ;
    END
  END rn_o[47]
  PIN rn_o[48]
    DIRECTION OUTPUT ;
    USE SIGNAL ;
    PORT
      LAYER M5 ;
        RECT  171.696 107.916 171.72 108 ;
    END
  END rn_o[48]
  PIN rn_o[49]
    DIRECTION OUTPUT ;
    USE SIGNAL ;
    PORT
      LAYER M5 ;
        RECT  171.888 107.916 171.912 108 ;
    END
  END rn_o[49]
  PIN rn_o[4]
    DIRECTION OUTPUT ;
    USE SIGNAL ;
    PORT
      LAYER M5 ;
        RECT  157.104 107.916 157.128 108 ;
    END
  END rn_o[4]
  PIN rn_o[50]
    DIRECTION OUTPUT ;
    USE SIGNAL ;
    PORT
      LAYER M5 ;
        RECT  172.08 107.916 172.104 108 ;
    END
  END rn_o[50]
  PIN rn_o[51]
    DIRECTION OUTPUT ;
    USE SIGNAL ;
    PORT
      LAYER M5 ;
        RECT  172.272 107.916 172.296 108 ;
    END
  END rn_o[51]
  PIN rn_o[52]
    DIRECTION OUTPUT ;
    USE SIGNAL ;
    PORT
      LAYER M5 ;
        RECT  172.464 107.916 172.488 108 ;
    END
  END rn_o[52]
  PIN rn_o[53]
    DIRECTION OUTPUT ;
    USE SIGNAL ;
    PORT
      LAYER M5 ;
        RECT  172.656 107.916 172.68 108 ;
    END
  END rn_o[53]
  PIN rn_o[54]
    DIRECTION OUTPUT ;
    USE SIGNAL ;
    PORT
      LAYER M5 ;
        RECT  172.848 107.916 172.872 108 ;
    END
  END rn_o[54]
  PIN rn_o[55]
    DIRECTION OUTPUT ;
    USE SIGNAL ;
    PORT
      LAYER M5 ;
        RECT  173.04 107.916 173.064 108 ;
    END
  END rn_o[55]
  PIN rn_o[56]
    DIRECTION OUTPUT ;
    USE SIGNAL ;
    PORT
      LAYER M5 ;
        RECT  173.232 107.916 173.256 108 ;
    END
  END rn_o[56]
  PIN rn_o[57]
    DIRECTION OUTPUT ;
    USE SIGNAL ;
    PORT
      LAYER M5 ;
        RECT  173.424 107.916 173.448 108 ;
    END
  END rn_o[57]
  PIN rn_o[58]
    DIRECTION OUTPUT ;
    USE SIGNAL ;
    PORT
      LAYER M5 ;
        RECT  173.616 107.916 173.64 108 ;
    END
  END rn_o[58]
  PIN rn_o[59]
    DIRECTION OUTPUT ;
    USE SIGNAL ;
    PORT
      LAYER M5 ;
        RECT  173.808 107.916 173.832 108 ;
    END
  END rn_o[59]
  PIN rn_o[5]
    DIRECTION OUTPUT ;
    USE SIGNAL ;
    PORT
      LAYER M5 ;
        RECT  157.296 107.916 157.32 108 ;
    END
  END rn_o[5]
  PIN rn_o[60]
    DIRECTION OUTPUT ;
    USE SIGNAL ;
    PORT
      LAYER M5 ;
        RECT  174 107.916 174.024 108 ;
    END
  END rn_o[60]
  PIN rn_o[61]
    DIRECTION OUTPUT ;
    USE SIGNAL ;
    PORT
      LAYER M5 ;
        RECT  174.192 107.916 174.216 108 ;
    END
  END rn_o[61]
  PIN rn_o[62]
    DIRECTION OUTPUT ;
    USE SIGNAL ;
    PORT
      LAYER M5 ;
        RECT  174.384 107.916 174.408 108 ;
    END
  END rn_o[62]
  PIN rn_o[63]
    DIRECTION OUTPUT ;
    USE SIGNAL ;
    PORT
      LAYER M5 ;
        RECT  174.576 107.916 174.6 108 ;
    END
  END rn_o[63]
  PIN rn_o[64]
    DIRECTION OUTPUT ;
    USE SIGNAL ;
    PORT
      LAYER M5 ;
        RECT  174.768 107.916 174.792 108 ;
    END
  END rn_o[64]
  PIN rn_o[65]
    DIRECTION OUTPUT ;
    USE SIGNAL ;
    PORT
      LAYER M5 ;
        RECT  174.96 107.916 174.984 108 ;
    END
  END rn_o[65]
  PIN rn_o[66]
    DIRECTION OUTPUT ;
    USE SIGNAL ;
    PORT
      LAYER M5 ;
        RECT  175.152 107.916 175.176 108 ;
    END
  END rn_o[66]
  PIN rn_o[67]
    DIRECTION OUTPUT ;
    USE SIGNAL ;
    PORT
      LAYER M5 ;
        RECT  175.344 107.916 175.368 108 ;
    END
  END rn_o[67]
  PIN rn_o[68]
    DIRECTION OUTPUT ;
    USE SIGNAL ;
    PORT
      LAYER M5 ;
        RECT  144.816 107.916 144.84 108 ;
    END
  END rn_o[68]
  PIN rn_o[69]
    DIRECTION OUTPUT ;
    USE SIGNAL ;
    PORT
      LAYER M5 ;
        RECT  145.008 107.916 145.032 108 ;
    END
  END rn_o[69]
  PIN rn_o[6]
    DIRECTION OUTPUT ;
    USE SIGNAL ;
    PORT
      LAYER M5 ;
        RECT  157.488 107.916 157.512 108 ;
    END
  END rn_o[6]
  PIN rn_o[70]
    DIRECTION OUTPUT ;
    USE SIGNAL ;
    PORT
      LAYER M5 ;
        RECT  145.2 107.916 145.224 108 ;
    END
  END rn_o[70]
  PIN rn_o[71]
    DIRECTION OUTPUT ;
    USE SIGNAL ;
    PORT
      LAYER M5 ;
        RECT  145.392 107.916 145.416 108 ;
    END
  END rn_o[71]
  PIN rn_o[72]
    DIRECTION OUTPUT ;
    USE SIGNAL ;
    PORT
      LAYER M5 ;
        RECT  145.584 107.916 145.608 108 ;
    END
  END rn_o[72]
  PIN rn_o[73]
    DIRECTION OUTPUT ;
    USE SIGNAL ;
    PORT
      LAYER M5 ;
        RECT  145.776 107.916 145.8 108 ;
    END
  END rn_o[73]
  PIN rn_o[74]
    DIRECTION OUTPUT ;
    USE SIGNAL ;
    PORT
      LAYER M5 ;
        RECT  145.968 107.916 145.992 108 ;
    END
  END rn_o[74]
  PIN rn_o[75]
    DIRECTION OUTPUT ;
    USE SIGNAL ;
    PORT
      LAYER M5 ;
        RECT  146.16 107.916 146.184 108 ;
    END
  END rn_o[75]
  PIN rn_o[76]
    DIRECTION OUTPUT ;
    USE SIGNAL ;
    PORT
      LAYER M5 ;
        RECT  146.352 107.916 146.376 108 ;
    END
  END rn_o[76]
  PIN rn_o[77]
    DIRECTION OUTPUT ;
    USE SIGNAL ;
    PORT
      LAYER M5 ;
        RECT  146.544 107.916 146.568 108 ;
    END
  END rn_o[77]
  PIN rn_o[78]
    DIRECTION OUTPUT ;
    USE SIGNAL ;
    PORT
      LAYER M5 ;
        RECT  146.736 107.916 146.76 108 ;
    END
  END rn_o[78]
  PIN rn_o[79]
    DIRECTION OUTPUT ;
    USE SIGNAL ;
    PORT
      LAYER M5 ;
        RECT  146.928 107.916 146.952 108 ;
    END
  END rn_o[79]
  PIN rn_o[7]
    DIRECTION OUTPUT ;
    USE SIGNAL ;
    PORT
      LAYER M5 ;
        RECT  157.68 107.916 157.704 108 ;
    END
  END rn_o[7]
  PIN rn_o[80]
    DIRECTION OUTPUT ;
    USE SIGNAL ;
    PORT
      LAYER M5 ;
        RECT  147.12 107.916 147.144 108 ;
    END
  END rn_o[80]
  PIN rn_o[81]
    DIRECTION OUTPUT ;
    USE SIGNAL ;
    PORT
      LAYER M5 ;
        RECT  147.312 107.916 147.336 108 ;
    END
  END rn_o[81]
  PIN rn_o[82]
    DIRECTION OUTPUT ;
    USE SIGNAL ;
    PORT
      LAYER M5 ;
        RECT  147.504 107.916 147.528 108 ;
    END
  END rn_o[82]
  PIN rn_o[83]
    DIRECTION OUTPUT ;
    USE SIGNAL ;
    PORT
      LAYER M5 ;
        RECT  147.696 107.916 147.72 108 ;
    END
  END rn_o[83]
  PIN rn_o[84]
    DIRECTION OUTPUT ;
    USE SIGNAL ;
    PORT
      LAYER M5 ;
        RECT  147.888 107.916 147.912 108 ;
    END
  END rn_o[84]
  PIN rn_o[85]
    DIRECTION OUTPUT ;
    USE SIGNAL ;
    PORT
      LAYER M5 ;
        RECT  148.08 107.916 148.104 108 ;
    END
  END rn_o[85]
  PIN rn_o[86]
    DIRECTION OUTPUT ;
    USE SIGNAL ;
    PORT
      LAYER M5 ;
        RECT  148.272 107.916 148.296 108 ;
    END
  END rn_o[86]
  PIN rn_o[87]
    DIRECTION OUTPUT ;
    USE SIGNAL ;
    PORT
      LAYER M5 ;
        RECT  148.464 107.916 148.488 108 ;
    END
  END rn_o[87]
  PIN rn_o[88]
    DIRECTION OUTPUT ;
    USE SIGNAL ;
    PORT
      LAYER M5 ;
        RECT  148.656 107.916 148.68 108 ;
    END
  END rn_o[88]
  PIN rn_o[89]
    DIRECTION OUTPUT ;
    USE SIGNAL ;
    PORT
      LAYER M5 ;
        RECT  148.848 107.916 148.872 108 ;
    END
  END rn_o[89]
  PIN rn_o[8]
    DIRECTION OUTPUT ;
    USE SIGNAL ;
    PORT
      LAYER M5 ;
        RECT  157.872 107.916 157.896 108 ;
    END
  END rn_o[8]
  PIN rn_o[90]
    DIRECTION OUTPUT ;
    USE SIGNAL ;
    PORT
      LAYER M5 ;
        RECT  149.04 107.916 149.064 108 ;
    END
  END rn_o[90]
  PIN rn_o[91]
    DIRECTION OUTPUT ;
    USE SIGNAL ;
    PORT
      LAYER M5 ;
        RECT  149.232 107.916 149.256 108 ;
    END
  END rn_o[91]
  PIN rn_o[92]
    DIRECTION OUTPUT ;
    USE SIGNAL ;
    PORT
      LAYER M5 ;
        RECT  149.424 107.916 149.448 108 ;
    END
  END rn_o[92]
  PIN rn_o[93]
    DIRECTION OUTPUT ;
    USE SIGNAL ;
    PORT
      LAYER M5 ;
        RECT  149.616 107.916 149.64 108 ;
    END
  END rn_o[93]
  PIN rn_o[94]
    DIRECTION OUTPUT ;
    USE SIGNAL ;
    PORT
      LAYER M5 ;
        RECT  149.808 107.916 149.832 108 ;
    END
  END rn_o[94]
  PIN rn_o[95]
    DIRECTION OUTPUT ;
    USE SIGNAL ;
    PORT
      LAYER M5 ;
        RECT  150 107.916 150.024 108 ;
    END
  END rn_o[95]
  PIN rn_o[96]
    DIRECTION OUTPUT ;
    USE SIGNAL ;
    PORT
      LAYER M5 ;
        RECT  150.192 107.916 150.216 108 ;
    END
  END rn_o[96]
  PIN rn_o[97]
    DIRECTION OUTPUT ;
    USE SIGNAL ;
    PORT
      LAYER M5 ;
        RECT  150.384 107.916 150.408 108 ;
    END
  END rn_o[97]
  PIN rn_o[98]
    DIRECTION OUTPUT ;
    USE SIGNAL ;
    PORT
      LAYER M5 ;
        RECT  150.576 107.916 150.6 108 ;
    END
  END rn_o[98]
  PIN rn_o[99]
    DIRECTION OUTPUT ;
    USE SIGNAL ;
    PORT
      LAYER M5 ;
        RECT  150.768 107.916 150.792 108 ;
    END
  END rn_o[99]
  PIN rn_o[9]
    DIRECTION OUTPUT ;
    USE SIGNAL ;
    PORT
      LAYER M5 ;
        RECT  158.064 107.916 158.088 108 ;
    END
  END rn_o[9]
  PIN rs_i[0]
    DIRECTION INPUT ;
    USE SIGNAL ;
    PORT
      LAYER M5 ;
        RECT  239.28 0 239.304 0.084 ;
    END
  END rs_i[0]
  PIN rs_i[100]
    DIRECTION INPUT ;
    USE SIGNAL ;
    PORT
      LAYER M5 ;
        RECT  147.648 0 147.672 0.084 ;
    END
  END rs_i[100]
  PIN rs_i[101]
    DIRECTION INPUT ;
    USE SIGNAL ;
    PORT
      LAYER M5 ;
        RECT  147.84 0 147.864 0.084 ;
    END
  END rs_i[101]
  PIN rs_i[102]
    DIRECTION INPUT ;
    USE SIGNAL ;
    PORT
      LAYER M5 ;
        RECT  148.032 0 148.056 0.084 ;
    END
  END rs_i[102]
  PIN rs_i[103]
    DIRECTION INPUT ;
    USE SIGNAL ;
    PORT
      LAYER M5 ;
        RECT  148.224 0 148.248 0.084 ;
    END
  END rs_i[103]
  PIN rs_i[104]
    DIRECTION INPUT ;
    USE SIGNAL ;
    PORT
      LAYER M5 ;
        RECT  148.416 0 148.44 0.084 ;
    END
  END rs_i[104]
  PIN rs_i[105]
    DIRECTION INPUT ;
    USE SIGNAL ;
    PORT
      LAYER M5 ;
        RECT  148.608 0 148.632 0.084 ;
    END
  END rs_i[105]
  PIN rs_i[106]
    DIRECTION INPUT ;
    USE SIGNAL ;
    PORT
      LAYER M5 ;
        RECT  148.8 0 148.824 0.084 ;
    END
  END rs_i[106]
  PIN rs_i[107]
    DIRECTION INPUT ;
    USE SIGNAL ;
    PORT
      LAYER M5 ;
        RECT  148.992 0 149.016 0.084 ;
    END
  END rs_i[107]
  PIN rs_i[108]
    DIRECTION INPUT ;
    USE SIGNAL ;
    PORT
      LAYER M5 ;
        RECT  149.184 0 149.208 0.084 ;
    END
  END rs_i[108]
  PIN rs_i[109]
    DIRECTION INPUT ;
    USE SIGNAL ;
    PORT
      LAYER M5 ;
        RECT  149.376 0 149.4 0.084 ;
    END
  END rs_i[109]
  PIN rs_i[10]
    DIRECTION INPUT ;
    USE SIGNAL ;
    PORT
      LAYER M5 ;
        RECT  241.2 0 241.224 0.084 ;
    END
  END rs_i[10]
  PIN rs_i[110]
    DIRECTION INPUT ;
    USE SIGNAL ;
    PORT
      LAYER M5 ;
        RECT  149.568 0 149.592 0.084 ;
    END
  END rs_i[110]
  PIN rs_i[111]
    DIRECTION INPUT ;
    USE SIGNAL ;
    PORT
      LAYER M5 ;
        RECT  149.76 0 149.784 0.084 ;
    END
  END rs_i[111]
  PIN rs_i[112]
    DIRECTION INPUT ;
    USE SIGNAL ;
    PORT
      LAYER M5 ;
        RECT  149.952 0 149.976 0.084 ;
    END
  END rs_i[112]
  PIN rs_i[113]
    DIRECTION INPUT ;
    USE SIGNAL ;
    PORT
      LAYER M5 ;
        RECT  168.816 0 168.84 0.084 ;
    END
  END rs_i[113]
  PIN rs_i[114]
    DIRECTION INPUT ;
    USE SIGNAL ;
    PORT
      LAYER M5 ;
        RECT  169.008 0 169.032 0.084 ;
    END
  END rs_i[114]
  PIN rs_i[115]
    DIRECTION INPUT ;
    USE SIGNAL ;
    PORT
      LAYER M5 ;
        RECT  169.2 0 169.224 0.084 ;
    END
  END rs_i[115]
  PIN rs_i[116]
    DIRECTION INPUT ;
    USE SIGNAL ;
    PORT
      LAYER M5 ;
        RECT  169.392 0 169.416 0.084 ;
    END
  END rs_i[116]
  PIN rs_i[117]
    DIRECTION INPUT ;
    USE SIGNAL ;
    PORT
      LAYER M5 ;
        RECT  169.584 0 169.608 0.084 ;
    END
  END rs_i[117]
  PIN rs_i[118]
    DIRECTION INPUT ;
    USE SIGNAL ;
    PORT
      LAYER M5 ;
        RECT  169.776 0 169.8 0.084 ;
    END
  END rs_i[118]
  PIN rs_i[119]
    DIRECTION INPUT ;
    USE SIGNAL ;
    PORT
      LAYER M5 ;
        RECT  169.968 0 169.992 0.084 ;
    END
  END rs_i[119]
  PIN rs_i[11]
    DIRECTION INPUT ;
    USE SIGNAL ;
    PORT
      LAYER M5 ;
        RECT  241.392 0 241.416 0.084 ;
    END
  END rs_i[11]
  PIN rs_i[120]
    DIRECTION INPUT ;
    USE SIGNAL ;
    PORT
      LAYER M5 ;
        RECT  170.16 0 170.184 0.084 ;
    END
  END rs_i[120]
  PIN rs_i[121]
    DIRECTION INPUT ;
    USE SIGNAL ;
    PORT
      LAYER M5 ;
        RECT  170.352 0 170.376 0.084 ;
    END
  END rs_i[121]
  PIN rs_i[122]
    DIRECTION INPUT ;
    USE SIGNAL ;
    PORT
      LAYER M5 ;
        RECT  170.544 0 170.568 0.084 ;
    END
  END rs_i[122]
  PIN rs_i[123]
    DIRECTION INPUT ;
    USE SIGNAL ;
    PORT
      LAYER M5 ;
        RECT  170.736 0 170.76 0.084 ;
    END
  END rs_i[123]
  PIN rs_i[124]
    DIRECTION INPUT ;
    USE SIGNAL ;
    PORT
      LAYER M5 ;
        RECT  170.928 0 170.952 0.084 ;
    END
  END rs_i[124]
  PIN rs_i[125]
    DIRECTION INPUT ;
    USE SIGNAL ;
    PORT
      LAYER M5 ;
        RECT  171.12 0 171.144 0.084 ;
    END
  END rs_i[125]
  PIN rs_i[126]
    DIRECTION INPUT ;
    USE SIGNAL ;
    PORT
      LAYER M5 ;
        RECT  171.312 0 171.336 0.084 ;
    END
  END rs_i[126]
  PIN rs_i[127]
    DIRECTION INPUT ;
    USE SIGNAL ;
    PORT
      LAYER M5 ;
        RECT  171.504 0 171.528 0.084 ;
    END
  END rs_i[127]
  PIN rs_i[128]
    DIRECTION INPUT ;
    USE SIGNAL ;
    PORT
      LAYER M5 ;
        RECT  171.696 0 171.72 0.084 ;
    END
  END rs_i[128]
  PIN rs_i[129]
    DIRECTION INPUT ;
    USE SIGNAL ;
    PORT
      LAYER M5 ;
        RECT  171.888 0 171.912 0.084 ;
    END
  END rs_i[129]
  PIN rs_i[12]
    DIRECTION INPUT ;
    USE SIGNAL ;
    PORT
      LAYER M5 ;
        RECT  241.584 0 241.608 0.084 ;
    END
  END rs_i[12]
  PIN rs_i[130]
    DIRECTION INPUT ;
    USE SIGNAL ;
    PORT
      LAYER M5 ;
        RECT  172.08 0 172.104 0.084 ;
    END
  END rs_i[130]
  PIN rs_i[131]
    DIRECTION INPUT ;
    USE SIGNAL ;
    PORT
      LAYER M5 ;
        RECT  172.272 0 172.296 0.084 ;
    END
  END rs_i[131]
  PIN rs_i[132]
    DIRECTION INPUT ;
    USE SIGNAL ;
    PORT
      LAYER M5 ;
        RECT  172.464 0 172.488 0.084 ;
    END
  END rs_i[132]
  PIN rs_i[133]
    DIRECTION INPUT ;
    USE SIGNAL ;
    PORT
      LAYER M5 ;
        RECT  172.656 0 172.68 0.084 ;
    END
  END rs_i[133]
  PIN rs_i[134]
    DIRECTION INPUT ;
    USE SIGNAL ;
    PORT
      LAYER M5 ;
        RECT  172.848 0 172.872 0.084 ;
    END
  END rs_i[134]
  PIN rs_i[135]
    DIRECTION INPUT ;
    USE SIGNAL ;
    PORT
      LAYER M5 ;
        RECT  173.04 0 173.064 0.084 ;
    END
  END rs_i[135]
  PIN rs_i[136]
    DIRECTION INPUT ;
    USE SIGNAL ;
    PORT
      LAYER M5 ;
        RECT  173.232 0 173.256 0.084 ;
    END
  END rs_i[136]
  PIN rs_i[137]
    DIRECTION INPUT ;
    USE SIGNAL ;
    PORT
      LAYER M5 ;
        RECT  173.424 0 173.448 0.084 ;
    END
  END rs_i[137]
  PIN rs_i[138]
    DIRECTION INPUT ;
    USE SIGNAL ;
    PORT
      LAYER M5 ;
        RECT  173.616 0 173.64 0.084 ;
    END
  END rs_i[138]
  PIN rs_i[139]
    DIRECTION INPUT ;
    USE SIGNAL ;
    PORT
      LAYER M5 ;
        RECT  173.808 0 173.832 0.084 ;
    END
  END rs_i[139]
  PIN rs_i[13]
    DIRECTION INPUT ;
    USE SIGNAL ;
    PORT
      LAYER M5 ;
        RECT  241.776 0 241.8 0.084 ;
    END
  END rs_i[13]
  PIN rs_i[140]
    DIRECTION INPUT ;
    USE SIGNAL ;
    PORT
      LAYER M5 ;
        RECT  174 0 174.024 0.084 ;
    END
  END rs_i[140]
  PIN rs_i[141]
    DIRECTION INPUT ;
    USE SIGNAL ;
    PORT
      LAYER M5 ;
        RECT  174.192 0 174.216 0.084 ;
    END
  END rs_i[141]
  PIN rs_i[142]
    DIRECTION INPUT ;
    USE SIGNAL ;
    PORT
      LAYER M5 ;
        RECT  174.384 0 174.408 0.084 ;
    END
  END rs_i[142]
  PIN rs_i[143]
    DIRECTION INPUT ;
    USE SIGNAL ;
    PORT
      LAYER M5 ;
        RECT  174.576 0 174.6 0.084 ;
    END
  END rs_i[143]
  PIN rs_i[144]
    DIRECTION INPUT ;
    USE SIGNAL ;
    PORT
      LAYER M5 ;
        RECT  174.768 0 174.792 0.084 ;
    END
  END rs_i[144]
  PIN rs_i[145]
    DIRECTION INPUT ;
    USE SIGNAL ;
    PORT
      LAYER M5 ;
        RECT  187.248 0 187.272 0.084 ;
    END
  END rs_i[145]
  PIN rs_i[146]
    DIRECTION INPUT ;
    USE SIGNAL ;
    PORT
      LAYER M5 ;
        RECT  187.44 0 187.464 0.084 ;
    END
  END rs_i[146]
  PIN rs_i[147]
    DIRECTION INPUT ;
    USE SIGNAL ;
    PORT
      LAYER M5 ;
        RECT  187.632 0 187.656 0.084 ;
    END
  END rs_i[147]
  PIN rs_i[148]
    DIRECTION INPUT ;
    USE SIGNAL ;
    PORT
      LAYER M5 ;
        RECT  187.824 0 187.848 0.084 ;
    END
  END rs_i[148]
  PIN rs_i[149]
    DIRECTION INPUT ;
    USE SIGNAL ;
    PORT
      LAYER M5 ;
        RECT  188.016 0 188.04 0.084 ;
    END
  END rs_i[149]
  PIN rs_i[14]
    DIRECTION INPUT ;
    USE SIGNAL ;
    PORT
      LAYER M5 ;
        RECT  241.968 0 241.992 0.084 ;
    END
  END rs_i[14]
  PIN rs_i[150]
    DIRECTION INPUT ;
    USE SIGNAL ;
    PORT
      LAYER M5 ;
        RECT  188.208 0 188.232 0.084 ;
    END
  END rs_i[150]
  PIN rs_i[151]
    DIRECTION INPUT ;
    USE SIGNAL ;
    PORT
      LAYER M5 ;
        RECT  188.4 0 188.424 0.084 ;
    END
  END rs_i[151]
  PIN rs_i[152]
    DIRECTION INPUT ;
    USE SIGNAL ;
    PORT
      LAYER M5 ;
        RECT  188.592 0 188.616 0.084 ;
    END
  END rs_i[152]
  PIN rs_i[153]
    DIRECTION INPUT ;
    USE SIGNAL ;
    PORT
      LAYER M5 ;
        RECT  188.784 0 188.808 0.084 ;
    END
  END rs_i[153]
  PIN rs_i[154]
    DIRECTION INPUT ;
    USE SIGNAL ;
    PORT
      LAYER M5 ;
        RECT  188.976 0 189 0.084 ;
    END
  END rs_i[154]
  PIN rs_i[155]
    DIRECTION INPUT ;
    USE SIGNAL ;
    PORT
      LAYER M5 ;
        RECT  189.168 0 189.192 0.084 ;
    END
  END rs_i[155]
  PIN rs_i[156]
    DIRECTION INPUT ;
    USE SIGNAL ;
    PORT
      LAYER M5 ;
        RECT  189.36 0 189.384 0.084 ;
    END
  END rs_i[156]
  PIN rs_i[157]
    DIRECTION INPUT ;
    USE SIGNAL ;
    PORT
      LAYER M5 ;
        RECT  189.552 0 189.576 0.084 ;
    END
  END rs_i[157]
  PIN rs_i[158]
    DIRECTION INPUT ;
    USE SIGNAL ;
    PORT
      LAYER M5 ;
        RECT  189.744 0 189.768 0.084 ;
    END
  END rs_i[158]
  PIN rs_i[159]
    DIRECTION INPUT ;
    USE SIGNAL ;
    PORT
      LAYER M5 ;
        RECT  189.936 0 189.96 0.084 ;
    END
  END rs_i[159]
  PIN rs_i[15]
    DIRECTION INPUT ;
    USE SIGNAL ;
    PORT
      LAYER M5 ;
        RECT  242.16 0 242.184 0.084 ;
    END
  END rs_i[15]
  PIN rs_i[160]
    DIRECTION INPUT ;
    USE SIGNAL ;
    PORT
      LAYER M5 ;
        RECT  190.128 0 190.152 0.084 ;
    END
  END rs_i[160]
  PIN rs_i[161]
    DIRECTION INPUT ;
    USE SIGNAL ;
    PORT
      LAYER M5 ;
        RECT  190.32 0 190.344 0.084 ;
    END
  END rs_i[161]
  PIN rs_i[162]
    DIRECTION INPUT ;
    USE SIGNAL ;
    PORT
      LAYER M5 ;
        RECT  190.512 0 190.536 0.084 ;
    END
  END rs_i[162]
  PIN rs_i[163]
    DIRECTION INPUT ;
    USE SIGNAL ;
    PORT
      LAYER M5 ;
        RECT  190.704 0 190.728 0.084 ;
    END
  END rs_i[163]
  PIN rs_i[164]
    DIRECTION INPUT ;
    USE SIGNAL ;
    PORT
      LAYER M5 ;
        RECT  190.896 0 190.92 0.084 ;
    END
  END rs_i[164]
  PIN rs_i[165]
    DIRECTION INPUT ;
    USE SIGNAL ;
    PORT
      LAYER M5 ;
        RECT  191.088 0 191.112 0.084 ;
    END
  END rs_i[165]
  PIN rs_i[166]
    DIRECTION INPUT ;
    USE SIGNAL ;
    PORT
      LAYER M5 ;
        RECT  191.28 0 191.304 0.084 ;
    END
  END rs_i[166]
  PIN rs_i[167]
    DIRECTION INPUT ;
    USE SIGNAL ;
    PORT
      LAYER M5 ;
        RECT  191.472 0 191.496 0.084 ;
    END
  END rs_i[167]
  PIN rs_i[168]
    DIRECTION INPUT ;
    USE SIGNAL ;
    PORT
      LAYER M5 ;
        RECT  191.664 0 191.688 0.084 ;
    END
  END rs_i[168]
  PIN rs_i[169]
    DIRECTION INPUT ;
    USE SIGNAL ;
    PORT
      LAYER M5 ;
        RECT  191.856 0 191.88 0.084 ;
    END
  END rs_i[169]
  PIN rs_i[16]
    DIRECTION INPUT ;
    USE SIGNAL ;
    PORT
      LAYER M5 ;
        RECT  242.352 0 242.376 0.084 ;
    END
  END rs_i[16]
  PIN rs_i[170]
    DIRECTION INPUT ;
    USE SIGNAL ;
    PORT
      LAYER M5 ;
        RECT  192.048 0 192.072 0.084 ;
    END
  END rs_i[170]
  PIN rs_i[171]
    DIRECTION INPUT ;
    USE SIGNAL ;
    PORT
      LAYER M5 ;
        RECT  192.24 0 192.264 0.084 ;
    END
  END rs_i[171]
  PIN rs_i[172]
    DIRECTION INPUT ;
    USE SIGNAL ;
    PORT
      LAYER M5 ;
        RECT  192.432 0 192.456 0.084 ;
    END
  END rs_i[172]
  PIN rs_i[173]
    DIRECTION INPUT ;
    USE SIGNAL ;
    PORT
      LAYER M5 ;
        RECT  192.624 0 192.648 0.084 ;
    END
  END rs_i[173]
  PIN rs_i[174]
    DIRECTION INPUT ;
    USE SIGNAL ;
    PORT
      LAYER M5 ;
        RECT  192.816 0 192.84 0.084 ;
    END
  END rs_i[174]
  PIN rs_i[175]
    DIRECTION INPUT ;
    USE SIGNAL ;
    PORT
      LAYER M5 ;
        RECT  193.008 0 193.032 0.084 ;
    END
  END rs_i[175]
  PIN rs_i[176]
    DIRECTION INPUT ;
    USE SIGNAL ;
    PORT
      LAYER M5 ;
        RECT  193.2 0 193.224 0.084 ;
    END
  END rs_i[176]
  PIN rs_i[177]
    DIRECTION INPUT ;
    USE SIGNAL ;
    PORT
      LAYER M5 ;
        RECT  181.104 0 181.128 0.084 ;
    END
  END rs_i[177]
  PIN rs_i[178]
    DIRECTION INPUT ;
    USE SIGNAL ;
    PORT
      LAYER M5 ;
        RECT  181.296 0 181.32 0.084 ;
    END
  END rs_i[178]
  PIN rs_i[179]
    DIRECTION INPUT ;
    USE SIGNAL ;
    PORT
      LAYER M5 ;
        RECT  181.488 0 181.512 0.084 ;
    END
  END rs_i[179]
  PIN rs_i[17]
    DIRECTION INPUT ;
    USE SIGNAL ;
    PORT
      LAYER M5 ;
        RECT  162.672 0 162.696 0.084 ;
    END
  END rs_i[17]
  PIN rs_i[180]
    DIRECTION INPUT ;
    USE SIGNAL ;
    PORT
      LAYER M5 ;
        RECT  181.68 0 181.704 0.084 ;
    END
  END rs_i[180]
  PIN rs_i[181]
    DIRECTION INPUT ;
    USE SIGNAL ;
    PORT
      LAYER M5 ;
        RECT  181.872 0 181.896 0.084 ;
    END
  END rs_i[181]
  PIN rs_i[182]
    DIRECTION INPUT ;
    USE SIGNAL ;
    PORT
      LAYER M5 ;
        RECT  182.064 0 182.088 0.084 ;
    END
  END rs_i[182]
  PIN rs_i[183]
    DIRECTION INPUT ;
    USE SIGNAL ;
    PORT
      LAYER M5 ;
        RECT  182.256 0 182.28 0.084 ;
    END
  END rs_i[183]
  PIN rs_i[184]
    DIRECTION INPUT ;
    USE SIGNAL ;
    PORT
      LAYER M5 ;
        RECT  182.448 0 182.472 0.084 ;
    END
  END rs_i[184]
  PIN rs_i[185]
    DIRECTION INPUT ;
    USE SIGNAL ;
    PORT
      LAYER M5 ;
        RECT  182.64 0 182.664 0.084 ;
    END
  END rs_i[185]
  PIN rs_i[186]
    DIRECTION INPUT ;
    USE SIGNAL ;
    PORT
      LAYER M5 ;
        RECT  182.832 0 182.856 0.084 ;
    END
  END rs_i[186]
  PIN rs_i[187]
    DIRECTION INPUT ;
    USE SIGNAL ;
    PORT
      LAYER M5 ;
        RECT  183.024 0 183.048 0.084 ;
    END
  END rs_i[187]
  PIN rs_i[188]
    DIRECTION INPUT ;
    USE SIGNAL ;
    PORT
      LAYER M5 ;
        RECT  183.216 0 183.24 0.084 ;
    END
  END rs_i[188]
  PIN rs_i[189]
    DIRECTION INPUT ;
    USE SIGNAL ;
    PORT
      LAYER M5 ;
        RECT  183.408 0 183.432 0.084 ;
    END
  END rs_i[189]
  PIN rs_i[18]
    DIRECTION INPUT ;
    USE SIGNAL ;
    PORT
      LAYER M5 ;
        RECT  162.864 0 162.888 0.084 ;
    END
  END rs_i[18]
  PIN rs_i[190]
    DIRECTION INPUT ;
    USE SIGNAL ;
    PORT
      LAYER M5 ;
        RECT  183.6 0 183.624 0.084 ;
    END
  END rs_i[190]
  PIN rs_i[191]
    DIRECTION INPUT ;
    USE SIGNAL ;
    PORT
      LAYER M5 ;
        RECT  183.792 0 183.816 0.084 ;
    END
  END rs_i[191]
  PIN rs_i[192]
    DIRECTION INPUT ;
    USE SIGNAL ;
    PORT
      LAYER M5 ;
        RECT  183.984 0 184.008 0.084 ;
    END
  END rs_i[192]
  PIN rs_i[193]
    DIRECTION INPUT ;
    USE SIGNAL ;
    PORT
      LAYER M5 ;
        RECT  184.176 0 184.2 0.084 ;
    END
  END rs_i[193]
  PIN rs_i[194]
    DIRECTION INPUT ;
    USE SIGNAL ;
    PORT
      LAYER M5 ;
        RECT  184.368 0 184.392 0.084 ;
    END
  END rs_i[194]
  PIN rs_i[195]
    DIRECTION INPUT ;
    USE SIGNAL ;
    PORT
      LAYER M5 ;
        RECT  184.56 0 184.584 0.084 ;
    END
  END rs_i[195]
  PIN rs_i[196]
    DIRECTION INPUT ;
    USE SIGNAL ;
    PORT
      LAYER M5 ;
        RECT  184.752 0 184.776 0.084 ;
    END
  END rs_i[196]
  PIN rs_i[197]
    DIRECTION INPUT ;
    USE SIGNAL ;
    PORT
      LAYER M5 ;
        RECT  184.944 0 184.968 0.084 ;
    END
  END rs_i[197]
  PIN rs_i[198]
    DIRECTION INPUT ;
    USE SIGNAL ;
    PORT
      LAYER M5 ;
        RECT  185.136 0 185.16 0.084 ;
    END
  END rs_i[198]
  PIN rs_i[199]
    DIRECTION INPUT ;
    USE SIGNAL ;
    PORT
      LAYER M5 ;
        RECT  185.328 0 185.352 0.084 ;
    END
  END rs_i[199]
  PIN rs_i[19]
    DIRECTION INPUT ;
    USE SIGNAL ;
    PORT
      LAYER M5 ;
        RECT  163.056 0 163.08 0.084 ;
    END
  END rs_i[19]
  PIN rs_i[1]
    DIRECTION INPUT ;
    USE SIGNAL ;
    PORT
      LAYER M5 ;
        RECT  239.472 0 239.496 0.084 ;
    END
  END rs_i[1]
  PIN rs_i[200]
    DIRECTION INPUT ;
    USE SIGNAL ;
    PORT
      LAYER M5 ;
        RECT  185.52 0 185.544 0.084 ;
    END
  END rs_i[200]
  PIN rs_i[201]
    DIRECTION INPUT ;
    USE SIGNAL ;
    PORT
      LAYER M5 ;
        RECT  185.712 0 185.736 0.084 ;
    END
  END rs_i[201]
  PIN rs_i[202]
    DIRECTION INPUT ;
    USE SIGNAL ;
    PORT
      LAYER M5 ;
        RECT  185.904 0 185.928 0.084 ;
    END
  END rs_i[202]
  PIN rs_i[203]
    DIRECTION INPUT ;
    USE SIGNAL ;
    PORT
      LAYER M5 ;
        RECT  186.096 0 186.12 0.084 ;
    END
  END rs_i[203]
  PIN rs_i[204]
    DIRECTION INPUT ;
    USE SIGNAL ;
    PORT
      LAYER M5 ;
        RECT  186.288 0 186.312 0.084 ;
    END
  END rs_i[204]
  PIN rs_i[205]
    DIRECTION INPUT ;
    USE SIGNAL ;
    PORT
      LAYER M5 ;
        RECT  186.48 0 186.504 0.084 ;
    END
  END rs_i[205]
  PIN rs_i[206]
    DIRECTION INPUT ;
    USE SIGNAL ;
    PORT
      LAYER M5 ;
        RECT  186.672 0 186.696 0.084 ;
    END
  END rs_i[206]
  PIN rs_i[207]
    DIRECTION INPUT ;
    USE SIGNAL ;
    PORT
      LAYER M5 ;
        RECT  186.864 0 186.888 0.084 ;
    END
  END rs_i[207]
  PIN rs_i[208]
    DIRECTION INPUT ;
    USE SIGNAL ;
    PORT
      LAYER M5 ;
        RECT  187.056 0 187.08 0.084 ;
    END
  END rs_i[208]
  PIN rs_i[209]
    DIRECTION INPUT ;
    USE SIGNAL ;
    PORT
      LAYER M5 ;
        RECT  199.536 0 199.56 0.084 ;
    END
  END rs_i[209]
  PIN rs_i[20]
    DIRECTION INPUT ;
    USE SIGNAL ;
    PORT
      LAYER M5 ;
        RECT  163.248 0 163.272 0.084 ;
    END
  END rs_i[20]
  PIN rs_i[210]
    DIRECTION INPUT ;
    USE SIGNAL ;
    PORT
      LAYER M5 ;
        RECT  199.728 0 199.752 0.084 ;
    END
  END rs_i[210]
  PIN rs_i[211]
    DIRECTION INPUT ;
    USE SIGNAL ;
    PORT
      LAYER M5 ;
        RECT  199.92 0 199.944 0.084 ;
    END
  END rs_i[211]
  PIN rs_i[212]
    DIRECTION INPUT ;
    USE SIGNAL ;
    PORT
      LAYER M5 ;
        RECT  200.112 0 200.136 0.084 ;
    END
  END rs_i[212]
  PIN rs_i[213]
    DIRECTION INPUT ;
    USE SIGNAL ;
    PORT
      LAYER M5 ;
        RECT  200.304 0 200.328 0.084 ;
    END
  END rs_i[213]
  PIN rs_i[214]
    DIRECTION INPUT ;
    USE SIGNAL ;
    PORT
      LAYER M5 ;
        RECT  200.496 0 200.52 0.084 ;
    END
  END rs_i[214]
  PIN rs_i[215]
    DIRECTION INPUT ;
    USE SIGNAL ;
    PORT
      LAYER M5 ;
        RECT  200.688 0 200.712 0.084 ;
    END
  END rs_i[215]
  PIN rs_i[216]
    DIRECTION INPUT ;
    USE SIGNAL ;
    PORT
      LAYER M5 ;
        RECT  200.88 0 200.904 0.084 ;
    END
  END rs_i[216]
  PIN rs_i[217]
    DIRECTION INPUT ;
    USE SIGNAL ;
    PORT
      LAYER M5 ;
        RECT  201.072 0 201.096 0.084 ;
    END
  END rs_i[217]
  PIN rs_i[218]
    DIRECTION INPUT ;
    USE SIGNAL ;
    PORT
      LAYER M5 ;
        RECT  201.264 0 201.288 0.084 ;
    END
  END rs_i[218]
  PIN rs_i[219]
    DIRECTION INPUT ;
    USE SIGNAL ;
    PORT
      LAYER M5 ;
        RECT  201.456 0 201.48 0.084 ;
    END
  END rs_i[219]
  PIN rs_i[21]
    DIRECTION INPUT ;
    USE SIGNAL ;
    PORT
      LAYER M5 ;
        RECT  163.44 0 163.464 0.084 ;
    END
  END rs_i[21]
  PIN rs_i[220]
    DIRECTION INPUT ;
    USE SIGNAL ;
    PORT
      LAYER M5 ;
        RECT  201.648 0 201.672 0.084 ;
    END
  END rs_i[220]
  PIN rs_i[221]
    DIRECTION INPUT ;
    USE SIGNAL ;
    PORT
      LAYER M5 ;
        RECT  201.84 0 201.864 0.084 ;
    END
  END rs_i[221]
  PIN rs_i[222]
    DIRECTION INPUT ;
    USE SIGNAL ;
    PORT
      LAYER M5 ;
        RECT  202.032 0 202.056 0.084 ;
    END
  END rs_i[222]
  PIN rs_i[223]
    DIRECTION INPUT ;
    USE SIGNAL ;
    PORT
      LAYER M5 ;
        RECT  202.224 0 202.248 0.084 ;
    END
  END rs_i[223]
  PIN rs_i[224]
    DIRECTION INPUT ;
    USE SIGNAL ;
    PORT
      LAYER M5 ;
        RECT  202.416 0 202.44 0.084 ;
    END
  END rs_i[224]
  PIN rs_i[225]
    DIRECTION INPUT ;
    USE SIGNAL ;
    PORT
      LAYER M5 ;
        RECT  202.608 0 202.632 0.084 ;
    END
  END rs_i[225]
  PIN rs_i[226]
    DIRECTION INPUT ;
    USE SIGNAL ;
    PORT
      LAYER M5 ;
        RECT  202.8 0 202.824 0.084 ;
    END
  END rs_i[226]
  PIN rs_i[227]
    DIRECTION INPUT ;
    USE SIGNAL ;
    PORT
      LAYER M5 ;
        RECT  202.992 0 203.016 0.084 ;
    END
  END rs_i[227]
  PIN rs_i[228]
    DIRECTION INPUT ;
    USE SIGNAL ;
    PORT
      LAYER M5 ;
        RECT  203.184 0 203.208 0.084 ;
    END
  END rs_i[228]
  PIN rs_i[229]
    DIRECTION INPUT ;
    USE SIGNAL ;
    PORT
      LAYER M5 ;
        RECT  203.376 0 203.4 0.084 ;
    END
  END rs_i[229]
  PIN rs_i[22]
    DIRECTION INPUT ;
    USE SIGNAL ;
    PORT
      LAYER M5 ;
        RECT  163.632 0 163.656 0.084 ;
    END
  END rs_i[22]
  PIN rs_i[230]
    DIRECTION INPUT ;
    USE SIGNAL ;
    PORT
      LAYER M5 ;
        RECT  203.568 0 203.592 0.084 ;
    END
  END rs_i[230]
  PIN rs_i[231]
    DIRECTION INPUT ;
    USE SIGNAL ;
    PORT
      LAYER M5 ;
        RECT  203.76 0 203.784 0.084 ;
    END
  END rs_i[231]
  PIN rs_i[232]
    DIRECTION INPUT ;
    USE SIGNAL ;
    PORT
      LAYER M5 ;
        RECT  203.952 0 203.976 0.084 ;
    END
  END rs_i[232]
  PIN rs_i[233]
    DIRECTION INPUT ;
    USE SIGNAL ;
    PORT
      LAYER M5 ;
        RECT  204.144 0 204.168 0.084 ;
    END
  END rs_i[233]
  PIN rs_i[234]
    DIRECTION INPUT ;
    USE SIGNAL ;
    PORT
      LAYER M5 ;
        RECT  204.336 0 204.36 0.084 ;
    END
  END rs_i[234]
  PIN rs_i[235]
    DIRECTION INPUT ;
    USE SIGNAL ;
    PORT
      LAYER M5 ;
        RECT  204.528 0 204.552 0.084 ;
    END
  END rs_i[235]
  PIN rs_i[236]
    DIRECTION INPUT ;
    USE SIGNAL ;
    PORT
      LAYER M5 ;
        RECT  204.72 0 204.744 0.084 ;
    END
  END rs_i[236]
  PIN rs_i[237]
    DIRECTION INPUT ;
    USE SIGNAL ;
    PORT
      LAYER M5 ;
        RECT  204.912 0 204.936 0.084 ;
    END
  END rs_i[237]
  PIN rs_i[238]
    DIRECTION INPUT ;
    USE SIGNAL ;
    PORT
      LAYER M5 ;
        RECT  205.104 0 205.128 0.084 ;
    END
  END rs_i[238]
  PIN rs_i[239]
    DIRECTION INPUT ;
    USE SIGNAL ;
    PORT
      LAYER M5 ;
        RECT  205.296 0 205.32 0.084 ;
    END
  END rs_i[239]
  PIN rs_i[23]
    DIRECTION INPUT ;
    USE SIGNAL ;
    PORT
      LAYER M5 ;
        RECT  163.824 0 163.848 0.084 ;
    END
  END rs_i[23]
  PIN rs_i[240]
    DIRECTION INPUT ;
    USE SIGNAL ;
    PORT
      LAYER M5 ;
        RECT  205.488 0 205.512 0.084 ;
    END
  END rs_i[240]
  PIN rs_i[241]
    DIRECTION INPUT ;
    USE SIGNAL ;
    PORT
      LAYER M5 ;
        RECT  193.392 0 193.416 0.084 ;
    END
  END rs_i[241]
  PIN rs_i[242]
    DIRECTION INPUT ;
    USE SIGNAL ;
    PORT
      LAYER M5 ;
        RECT  193.584 0 193.608 0.084 ;
    END
  END rs_i[242]
  PIN rs_i[243]
    DIRECTION INPUT ;
    USE SIGNAL ;
    PORT
      LAYER M5 ;
        RECT  193.776 0 193.8 0.084 ;
    END
  END rs_i[243]
  PIN rs_i[244]
    DIRECTION INPUT ;
    USE SIGNAL ;
    PORT
      LAYER M5 ;
        RECT  193.968 0 193.992 0.084 ;
    END
  END rs_i[244]
  PIN rs_i[245]
    DIRECTION INPUT ;
    USE SIGNAL ;
    PORT
      LAYER M5 ;
        RECT  194.16 0 194.184 0.084 ;
    END
  END rs_i[245]
  PIN rs_i[246]
    DIRECTION INPUT ;
    USE SIGNAL ;
    PORT
      LAYER M5 ;
        RECT  194.352 0 194.376 0.084 ;
    END
  END rs_i[246]
  PIN rs_i[247]
    DIRECTION INPUT ;
    USE SIGNAL ;
    PORT
      LAYER M5 ;
        RECT  194.544 0 194.568 0.084 ;
    END
  END rs_i[247]
  PIN rs_i[248]
    DIRECTION INPUT ;
    USE SIGNAL ;
    PORT
      LAYER M5 ;
        RECT  194.736 0 194.76 0.084 ;
    END
  END rs_i[248]
  PIN rs_i[249]
    DIRECTION INPUT ;
    USE SIGNAL ;
    PORT
      LAYER M5 ;
        RECT  194.928 0 194.952 0.084 ;
    END
  END rs_i[249]
  PIN rs_i[24]
    DIRECTION INPUT ;
    USE SIGNAL ;
    PORT
      LAYER M5 ;
        RECT  164.016 0 164.04 0.084 ;
    END
  END rs_i[24]
  PIN rs_i[250]
    DIRECTION INPUT ;
    USE SIGNAL ;
    PORT
      LAYER M5 ;
        RECT  195.12 0 195.144 0.084 ;
    END
  END rs_i[250]
  PIN rs_i[251]
    DIRECTION INPUT ;
    USE SIGNAL ;
    PORT
      LAYER M5 ;
        RECT  195.312 0 195.336 0.084 ;
    END
  END rs_i[251]
  PIN rs_i[252]
    DIRECTION INPUT ;
    USE SIGNAL ;
    PORT
      LAYER M5 ;
        RECT  195.504 0 195.528 0.084 ;
    END
  END rs_i[252]
  PIN rs_i[253]
    DIRECTION INPUT ;
    USE SIGNAL ;
    PORT
      LAYER M5 ;
        RECT  195.696 0 195.72 0.084 ;
    END
  END rs_i[253]
  PIN rs_i[254]
    DIRECTION INPUT ;
    USE SIGNAL ;
    PORT
      LAYER M5 ;
        RECT  195.888 0 195.912 0.084 ;
    END
  END rs_i[254]
  PIN rs_i[255]
    DIRECTION INPUT ;
    USE SIGNAL ;
    PORT
      LAYER M5 ;
        RECT  196.08 0 196.104 0.084 ;
    END
  END rs_i[255]
  PIN rs_i[256]
    DIRECTION INPUT ;
    USE SIGNAL ;
    PORT
      LAYER M5 ;
        RECT  196.272 0 196.296 0.084 ;
    END
  END rs_i[256]
  PIN rs_i[257]
    DIRECTION INPUT ;
    USE SIGNAL ;
    PORT
      LAYER M5 ;
        RECT  196.464 0 196.488 0.084 ;
    END
  END rs_i[257]
  PIN rs_i[258]
    DIRECTION INPUT ;
    USE SIGNAL ;
    PORT
      LAYER M5 ;
        RECT  196.656 0 196.68 0.084 ;
    END
  END rs_i[258]
  PIN rs_i[259]
    DIRECTION INPUT ;
    USE SIGNAL ;
    PORT
      LAYER M5 ;
        RECT  196.848 0 196.872 0.084 ;
    END
  END rs_i[259]
  PIN rs_i[25]
    DIRECTION INPUT ;
    USE SIGNAL ;
    PORT
      LAYER M5 ;
        RECT  164.208 0 164.232 0.084 ;
    END
  END rs_i[25]
  PIN rs_i[260]
    DIRECTION INPUT ;
    USE SIGNAL ;
    PORT
      LAYER M5 ;
        RECT  197.04 0 197.064 0.084 ;
    END
  END rs_i[260]
  PIN rs_i[261]
    DIRECTION INPUT ;
    USE SIGNAL ;
    PORT
      LAYER M5 ;
        RECT  197.232 0 197.256 0.084 ;
    END
  END rs_i[261]
  PIN rs_i[262]
    DIRECTION INPUT ;
    USE SIGNAL ;
    PORT
      LAYER M5 ;
        RECT  197.424 0 197.448 0.084 ;
    END
  END rs_i[262]
  PIN rs_i[263]
    DIRECTION INPUT ;
    USE SIGNAL ;
    PORT
      LAYER M5 ;
        RECT  197.616 0 197.64 0.084 ;
    END
  END rs_i[263]
  PIN rs_i[264]
    DIRECTION INPUT ;
    USE SIGNAL ;
    PORT
      LAYER M5 ;
        RECT  197.808 0 197.832 0.084 ;
    END
  END rs_i[264]
  PIN rs_i[265]
    DIRECTION INPUT ;
    USE SIGNAL ;
    PORT
      LAYER M5 ;
        RECT  198 0 198.024 0.084 ;
    END
  END rs_i[265]
  PIN rs_i[266]
    DIRECTION INPUT ;
    USE SIGNAL ;
    PORT
      LAYER M5 ;
        RECT  198.192 0 198.216 0.084 ;
    END
  END rs_i[266]
  PIN rs_i[267]
    DIRECTION INPUT ;
    USE SIGNAL ;
    PORT
      LAYER M5 ;
        RECT  198.384 0 198.408 0.084 ;
    END
  END rs_i[267]
  PIN rs_i[268]
    DIRECTION INPUT ;
    USE SIGNAL ;
    PORT
      LAYER M5 ;
        RECT  198.576 0 198.6 0.084 ;
    END
  END rs_i[268]
  PIN rs_i[269]
    DIRECTION INPUT ;
    USE SIGNAL ;
    PORT
      LAYER M5 ;
        RECT  198.768 0 198.792 0.084 ;
    END
  END rs_i[269]
  PIN rs_i[26]
    DIRECTION INPUT ;
    USE SIGNAL ;
    PORT
      LAYER M5 ;
        RECT  164.4 0 164.424 0.084 ;
    END
  END rs_i[26]
  PIN rs_i[270]
    DIRECTION INPUT ;
    USE SIGNAL ;
    PORT
      LAYER M5 ;
        RECT  198.96 0 198.984 0.084 ;
    END
  END rs_i[270]
  PIN rs_i[271]
    DIRECTION INPUT ;
    USE SIGNAL ;
    PORT
      LAYER M5 ;
        RECT  199.152 0 199.176 0.084 ;
    END
  END rs_i[271]
  PIN rs_i[272]
    DIRECTION INPUT ;
    USE SIGNAL ;
    PORT
      LAYER M5 ;
        RECT  199.344 0 199.368 0.084 ;
    END
  END rs_i[272]
  PIN rs_i[273]
    DIRECTION INPUT ;
    USE SIGNAL ;
    PORT
      LAYER M5 ;
        RECT  174.96 0 174.984 0.084 ;
    END
  END rs_i[273]
  PIN rs_i[274]
    DIRECTION INPUT ;
    USE SIGNAL ;
    PORT
      LAYER M5 ;
        RECT  175.152 0 175.176 0.084 ;
    END
  END rs_i[274]
  PIN rs_i[275]
    DIRECTION INPUT ;
    USE SIGNAL ;
    PORT
      LAYER M5 ;
        RECT  175.344 0 175.368 0.084 ;
    END
  END rs_i[275]
  PIN rs_i[27]
    DIRECTION INPUT ;
    USE SIGNAL ;
    PORT
      LAYER M5 ;
        RECT  164.592 0 164.616 0.084 ;
    END
  END rs_i[27]
  PIN rs_i[28]
    DIRECTION INPUT ;
    USE SIGNAL ;
    PORT
      LAYER M5 ;
        RECT  164.784 0 164.808 0.084 ;
    END
  END rs_i[28]
  PIN rs_i[29]
    DIRECTION INPUT ;
    USE SIGNAL ;
    PORT
      LAYER M5 ;
        RECT  164.976 0 165 0.084 ;
    END
  END rs_i[29]
  PIN rs_i[2]
    DIRECTION INPUT ;
    USE SIGNAL ;
    PORT
      LAYER M5 ;
        RECT  239.664 0 239.688 0.084 ;
    END
  END rs_i[2]
  PIN rs_i[30]
    DIRECTION INPUT ;
    USE SIGNAL ;
    PORT
      LAYER M5 ;
        RECT  165.168 0 165.192 0.084 ;
    END
  END rs_i[30]
  PIN rs_i[31]
    DIRECTION INPUT ;
    USE SIGNAL ;
    PORT
      LAYER M5 ;
        RECT  165.36 0 165.384 0.084 ;
    END
  END rs_i[31]
  PIN rs_i[32]
    DIRECTION INPUT ;
    USE SIGNAL ;
    PORT
      LAYER M5 ;
        RECT  165.552 0 165.576 0.084 ;
    END
  END rs_i[32]
  PIN rs_i[33]
    DIRECTION INPUT ;
    USE SIGNAL ;
    PORT
      LAYER M5 ;
        RECT  165.744 0 165.768 0.084 ;
    END
  END rs_i[33]
  PIN rs_i[34]
    DIRECTION INPUT ;
    USE SIGNAL ;
    PORT
      LAYER M5 ;
        RECT  165.936 0 165.96 0.084 ;
    END
  END rs_i[34]
  PIN rs_i[35]
    DIRECTION INPUT ;
    USE SIGNAL ;
    PORT
      LAYER M5 ;
        RECT  166.128 0 166.152 0.084 ;
    END
  END rs_i[35]
  PIN rs_i[36]
    DIRECTION INPUT ;
    USE SIGNAL ;
    PORT
      LAYER M5 ;
        RECT  166.32 0 166.344 0.084 ;
    END
  END rs_i[36]
  PIN rs_i[37]
    DIRECTION INPUT ;
    USE SIGNAL ;
    PORT
      LAYER M5 ;
        RECT  166.512 0 166.536 0.084 ;
    END
  END rs_i[37]
  PIN rs_i[38]
    DIRECTION INPUT ;
    USE SIGNAL ;
    PORT
      LAYER M5 ;
        RECT  166.704 0 166.728 0.084 ;
    END
  END rs_i[38]
  PIN rs_i[39]
    DIRECTION INPUT ;
    USE SIGNAL ;
    PORT
      LAYER M5 ;
        RECT  166.896 0 166.92 0.084 ;
    END
  END rs_i[39]
  PIN rs_i[3]
    DIRECTION INPUT ;
    USE SIGNAL ;
    PORT
      LAYER M5 ;
        RECT  239.856 0 239.88 0.084 ;
    END
  END rs_i[3]
  PIN rs_i[40]
    DIRECTION INPUT ;
    USE SIGNAL ;
    PORT
      LAYER M5 ;
        RECT  167.088 0 167.112 0.084 ;
    END
  END rs_i[40]
  PIN rs_i[41]
    DIRECTION INPUT ;
    USE SIGNAL ;
    PORT
      LAYER M5 ;
        RECT  167.28 0 167.304 0.084 ;
    END
  END rs_i[41]
  PIN rs_i[42]
    DIRECTION INPUT ;
    USE SIGNAL ;
    PORT
      LAYER M5 ;
        RECT  167.472 0 167.496 0.084 ;
    END
  END rs_i[42]
  PIN rs_i[43]
    DIRECTION INPUT ;
    USE SIGNAL ;
    PORT
      LAYER M5 ;
        RECT  167.664 0 167.688 0.084 ;
    END
  END rs_i[43]
  PIN rs_i[44]
    DIRECTION INPUT ;
    USE SIGNAL ;
    PORT
      LAYER M5 ;
        RECT  167.856 0 167.88 0.084 ;
    END
  END rs_i[44]
  PIN rs_i[45]
    DIRECTION INPUT ;
    USE SIGNAL ;
    PORT
      LAYER M5 ;
        RECT  168.048 0 168.072 0.084 ;
    END
  END rs_i[45]
  PIN rs_i[46]
    DIRECTION INPUT ;
    USE SIGNAL ;
    PORT
      LAYER M5 ;
        RECT  168.24 0 168.264 0.084 ;
    END
  END rs_i[46]
  PIN rs_i[47]
    DIRECTION INPUT ;
    USE SIGNAL ;
    PORT
      LAYER M5 ;
        RECT  168.432 0 168.456 0.084 ;
    END
  END rs_i[47]
  PIN rs_i[48]
    DIRECTION INPUT ;
    USE SIGNAL ;
    PORT
      LAYER M5 ;
        RECT  168.624 0 168.648 0.084 ;
    END
  END rs_i[48]
  PIN rs_i[49]
    DIRECTION INPUT ;
    USE SIGNAL ;
    PORT
      LAYER M5 ;
        RECT  156.528 0 156.552 0.084 ;
    END
  END rs_i[49]
  PIN rs_i[4]
    DIRECTION INPUT ;
    USE SIGNAL ;
    PORT
      LAYER M5 ;
        RECT  240.048 0 240.072 0.084 ;
    END
  END rs_i[4]
  PIN rs_i[50]
    DIRECTION INPUT ;
    USE SIGNAL ;
    PORT
      LAYER M5 ;
        RECT  156.72 0 156.744 0.084 ;
    END
  END rs_i[50]
  PIN rs_i[51]
    DIRECTION INPUT ;
    USE SIGNAL ;
    PORT
      LAYER M5 ;
        RECT  156.912 0 156.936 0.084 ;
    END
  END rs_i[51]
  PIN rs_i[52]
    DIRECTION INPUT ;
    USE SIGNAL ;
    PORT
      LAYER M5 ;
        RECT  157.104 0 157.128 0.084 ;
    END
  END rs_i[52]
  PIN rs_i[53]
    DIRECTION INPUT ;
    USE SIGNAL ;
    PORT
      LAYER M5 ;
        RECT  157.296 0 157.32 0.084 ;
    END
  END rs_i[53]
  PIN rs_i[54]
    DIRECTION INPUT ;
    USE SIGNAL ;
    PORT
      LAYER M5 ;
        RECT  157.488 0 157.512 0.084 ;
    END
  END rs_i[54]
  PIN rs_i[55]
    DIRECTION INPUT ;
    USE SIGNAL ;
    PORT
      LAYER M5 ;
        RECT  157.68 0 157.704 0.084 ;
    END
  END rs_i[55]
  PIN rs_i[56]
    DIRECTION INPUT ;
    USE SIGNAL ;
    PORT
      LAYER M5 ;
        RECT  157.872 0 157.896 0.084 ;
    END
  END rs_i[56]
  PIN rs_i[57]
    DIRECTION INPUT ;
    USE SIGNAL ;
    PORT
      LAYER M5 ;
        RECT  158.064 0 158.088 0.084 ;
    END
  END rs_i[57]
  PIN rs_i[58]
    DIRECTION INPUT ;
    USE SIGNAL ;
    PORT
      LAYER M5 ;
        RECT  158.256 0 158.28 0.084 ;
    END
  END rs_i[58]
  PIN rs_i[59]
    DIRECTION INPUT ;
    USE SIGNAL ;
    PORT
      LAYER M5 ;
        RECT  158.448 0 158.472 0.084 ;
    END
  END rs_i[59]
  PIN rs_i[5]
    DIRECTION INPUT ;
    USE SIGNAL ;
    PORT
      LAYER M5 ;
        RECT  240.24 0 240.264 0.084 ;
    END
  END rs_i[5]
  PIN rs_i[60]
    DIRECTION INPUT ;
    USE SIGNAL ;
    PORT
      LAYER M5 ;
        RECT  158.64 0 158.664 0.084 ;
    END
  END rs_i[60]
  PIN rs_i[61]
    DIRECTION INPUT ;
    USE SIGNAL ;
    PORT
      LAYER M5 ;
        RECT  158.832 0 158.856 0.084 ;
    END
  END rs_i[61]
  PIN rs_i[62]
    DIRECTION INPUT ;
    USE SIGNAL ;
    PORT
      LAYER M5 ;
        RECT  159.024 0 159.048 0.084 ;
    END
  END rs_i[62]
  PIN rs_i[63]
    DIRECTION INPUT ;
    USE SIGNAL ;
    PORT
      LAYER M5 ;
        RECT  159.216 0 159.24 0.084 ;
    END
  END rs_i[63]
  PIN rs_i[64]
    DIRECTION INPUT ;
    USE SIGNAL ;
    PORT
      LAYER M5 ;
        RECT  159.408 0 159.432 0.084 ;
    END
  END rs_i[64]
  PIN rs_i[65]
    DIRECTION INPUT ;
    USE SIGNAL ;
    PORT
      LAYER M5 ;
        RECT  159.6 0 159.624 0.084 ;
    END
  END rs_i[65]
  PIN rs_i[66]
    DIRECTION INPUT ;
    USE SIGNAL ;
    PORT
      LAYER M5 ;
        RECT  159.792 0 159.816 0.084 ;
    END
  END rs_i[66]
  PIN rs_i[67]
    DIRECTION INPUT ;
    USE SIGNAL ;
    PORT
      LAYER M5 ;
        RECT  159.984 0 160.008 0.084 ;
    END
  END rs_i[67]
  PIN rs_i[68]
    DIRECTION INPUT ;
    USE SIGNAL ;
    PORT
      LAYER M5 ;
        RECT  160.176 0 160.2 0.084 ;
    END
  END rs_i[68]
  PIN rs_i[69]
    DIRECTION INPUT ;
    USE SIGNAL ;
    PORT
      LAYER M5 ;
        RECT  160.368 0 160.392 0.084 ;
    END
  END rs_i[69]
  PIN rs_i[6]
    DIRECTION INPUT ;
    USE SIGNAL ;
    PORT
      LAYER M5 ;
        RECT  240.432 0 240.456 0.084 ;
    END
  END rs_i[6]
  PIN rs_i[70]
    DIRECTION INPUT ;
    USE SIGNAL ;
    PORT
      LAYER M5 ;
        RECT  160.56 0 160.584 0.084 ;
    END
  END rs_i[70]
  PIN rs_i[71]
    DIRECTION INPUT ;
    USE SIGNAL ;
    PORT
      LAYER M5 ;
        RECT  160.752 0 160.776 0.084 ;
    END
  END rs_i[71]
  PIN rs_i[72]
    DIRECTION INPUT ;
    USE SIGNAL ;
    PORT
      LAYER M5 ;
        RECT  160.944 0 160.968 0.084 ;
    END
  END rs_i[72]
  PIN rs_i[73]
    DIRECTION INPUT ;
    USE SIGNAL ;
    PORT
      LAYER M5 ;
        RECT  161.136 0 161.16 0.084 ;
    END
  END rs_i[73]
  PIN rs_i[74]
    DIRECTION INPUT ;
    USE SIGNAL ;
    PORT
      LAYER M5 ;
        RECT  161.328 0 161.352 0.084 ;
    END
  END rs_i[74]
  PIN rs_i[75]
    DIRECTION INPUT ;
    USE SIGNAL ;
    PORT
      LAYER M5 ;
        RECT  161.52 0 161.544 0.084 ;
    END
  END rs_i[75]
  PIN rs_i[76]
    DIRECTION INPUT ;
    USE SIGNAL ;
    PORT
      LAYER M5 ;
        RECT  161.712 0 161.736 0.084 ;
    END
  END rs_i[76]
  PIN rs_i[77]
    DIRECTION INPUT ;
    USE SIGNAL ;
    PORT
      LAYER M5 ;
        RECT  161.904 0 161.928 0.084 ;
    END
  END rs_i[77]
  PIN rs_i[78]
    DIRECTION INPUT ;
    USE SIGNAL ;
    PORT
      LAYER M5 ;
        RECT  162.096 0 162.12 0.084 ;
    END
  END rs_i[78]
  PIN rs_i[79]
    DIRECTION INPUT ;
    USE SIGNAL ;
    PORT
      LAYER M5 ;
        RECT  162.288 0 162.312 0.084 ;
    END
  END rs_i[79]
  PIN rs_i[7]
    DIRECTION INPUT ;
    USE SIGNAL ;
    PORT
      LAYER M5 ;
        RECT  240.624 0 240.648 0.084 ;
    END
  END rs_i[7]
  PIN rs_i[80]
    DIRECTION INPUT ;
    USE SIGNAL ;
    PORT
      LAYER M5 ;
        RECT  162.48 0 162.504 0.084 ;
    END
  END rs_i[80]
  PIN rs_i[81]
    DIRECTION INPUT ;
    USE SIGNAL ;
    PORT
      LAYER M5 ;
        RECT  144 0 144.024 0.084 ;
    END
  END rs_i[81]
  PIN rs_i[82]
    DIRECTION INPUT ;
    USE SIGNAL ;
    PORT
      LAYER M5 ;
        RECT  144.192 0 144.216 0.084 ;
    END
  END rs_i[82]
  PIN rs_i[83]
    DIRECTION INPUT ;
    USE SIGNAL ;
    PORT
      LAYER M5 ;
        RECT  144.384 0 144.408 0.084 ;
    END
  END rs_i[83]
  PIN rs_i[84]
    DIRECTION INPUT ;
    USE SIGNAL ;
    PORT
      LAYER M5 ;
        RECT  144.576 0 144.6 0.084 ;
    END
  END rs_i[84]
  PIN rs_i[85]
    DIRECTION INPUT ;
    USE SIGNAL ;
    PORT
      LAYER M5 ;
        RECT  144.768 0 144.792 0.084 ;
    END
  END rs_i[85]
  PIN rs_i[86]
    DIRECTION INPUT ;
    USE SIGNAL ;
    PORT
      LAYER M5 ;
        RECT  144.96 0 144.984 0.084 ;
    END
  END rs_i[86]
  PIN rs_i[87]
    DIRECTION INPUT ;
    USE SIGNAL ;
    PORT
      LAYER M5 ;
        RECT  145.152 0 145.176 0.084 ;
    END
  END rs_i[87]
  PIN rs_i[88]
    DIRECTION INPUT ;
    USE SIGNAL ;
    PORT
      LAYER M5 ;
        RECT  145.344 0 145.368 0.084 ;
    END
  END rs_i[88]
  PIN rs_i[89]
    DIRECTION INPUT ;
    USE SIGNAL ;
    PORT
      LAYER M5 ;
        RECT  145.536 0 145.56 0.084 ;
    END
  END rs_i[89]
  PIN rs_i[8]
    DIRECTION INPUT ;
    USE SIGNAL ;
    PORT
      LAYER M5 ;
        RECT  240.816 0 240.84 0.084 ;
    END
  END rs_i[8]
  PIN rs_i[90]
    DIRECTION INPUT ;
    USE SIGNAL ;
    PORT
      LAYER M5 ;
        RECT  145.728 0 145.752 0.084 ;
    END
  END rs_i[90]
  PIN rs_i[91]
    DIRECTION INPUT ;
    USE SIGNAL ;
    PORT
      LAYER M5 ;
        RECT  145.92 0 145.944 0.084 ;
    END
  END rs_i[91]
  PIN rs_i[92]
    DIRECTION INPUT ;
    USE SIGNAL ;
    PORT
      LAYER M5 ;
        RECT  146.112 0 146.136 0.084 ;
    END
  END rs_i[92]
  PIN rs_i[93]
    DIRECTION INPUT ;
    USE SIGNAL ;
    PORT
      LAYER M5 ;
        RECT  146.304 0 146.328 0.084 ;
    END
  END rs_i[93]
  PIN rs_i[94]
    DIRECTION INPUT ;
    USE SIGNAL ;
    PORT
      LAYER M5 ;
        RECT  146.496 0 146.52 0.084 ;
    END
  END rs_i[94]
  PIN rs_i[95]
    DIRECTION INPUT ;
    USE SIGNAL ;
    PORT
      LAYER M5 ;
        RECT  146.688 0 146.712 0.084 ;
    END
  END rs_i[95]
  PIN rs_i[96]
    DIRECTION INPUT ;
    USE SIGNAL ;
    PORT
      LAYER M5 ;
        RECT  146.88 0 146.904 0.084 ;
    END
  END rs_i[96]
  PIN rs_i[97]
    DIRECTION INPUT ;
    USE SIGNAL ;
    PORT
      LAYER M5 ;
        RECT  147.072 0 147.096 0.084 ;
    END
  END rs_i[97]
  PIN rs_i[98]
    DIRECTION INPUT ;
    USE SIGNAL ;
    PORT
      LAYER M5 ;
        RECT  147.264 0 147.288 0.084 ;
    END
  END rs_i[98]
  PIN rs_i[99]
    DIRECTION INPUT ;
    USE SIGNAL ;
    PORT
      LAYER M5 ;
        RECT  147.456 0 147.48 0.084 ;
    END
  END rs_i[99]
  PIN rs_i[9]
    DIRECTION INPUT ;
    USE SIGNAL ;
    PORT
      LAYER M5 ;
        RECT  241.008 0 241.032 0.084 ;
    END
  END rs_i[9]
  PIN rs_o[0]
    DIRECTION OUTPUT ;
    USE SIGNAL ;
    PORT
      LAYER M5 ;
        RECT  175.536 0 175.56 0.084 ;
    END
  END rs_o[0]
  PIN rs_o[100]
    DIRECTION OUTPUT ;
    USE SIGNAL ;
    PORT
      LAYER M5 ;
        RECT  225.456 0 225.48 0.084 ;
    END
  END rs_o[100]
  PIN rs_o[101]
    DIRECTION OUTPUT ;
    USE SIGNAL ;
    PORT
      LAYER M5 ;
        RECT  225.648 0 225.672 0.084 ;
    END
  END rs_o[101]
  PIN rs_o[102]
    DIRECTION OUTPUT ;
    USE SIGNAL ;
    PORT
      LAYER M5 ;
        RECT  225.84 0 225.864 0.084 ;
    END
  END rs_o[102]
  PIN rs_o[103]
    DIRECTION OUTPUT ;
    USE SIGNAL ;
    PORT
      LAYER M5 ;
        RECT  226.032 0 226.056 0.084 ;
    END
  END rs_o[103]
  PIN rs_o[104]
    DIRECTION OUTPUT ;
    USE SIGNAL ;
    PORT
      LAYER M5 ;
        RECT  226.224 0 226.248 0.084 ;
    END
  END rs_o[104]
  PIN rs_o[105]
    DIRECTION OUTPUT ;
    USE SIGNAL ;
    PORT
      LAYER M5 ;
        RECT  226.416 0 226.44 0.084 ;
    END
  END rs_o[105]
  PIN rs_o[106]
    DIRECTION OUTPUT ;
    USE SIGNAL ;
    PORT
      LAYER M5 ;
        RECT  226.608 0 226.632 0.084 ;
    END
  END rs_o[106]
  PIN rs_o[107]
    DIRECTION OUTPUT ;
    USE SIGNAL ;
    PORT
      LAYER M5 ;
        RECT  226.8 0 226.824 0.084 ;
    END
  END rs_o[107]
  PIN rs_o[108]
    DIRECTION OUTPUT ;
    USE SIGNAL ;
    PORT
      LAYER M5 ;
        RECT  226.992 0 227.016 0.084 ;
    END
  END rs_o[108]
  PIN rs_o[109]
    DIRECTION OUTPUT ;
    USE SIGNAL ;
    PORT
      LAYER M5 ;
        RECT  227.184 0 227.208 0.084 ;
    END
  END rs_o[109]
  PIN rs_o[10]
    DIRECTION OUTPUT ;
    USE SIGNAL ;
    PORT
      LAYER M5 ;
        RECT  177.456 0 177.48 0.084 ;
    END
  END rs_o[10]
  PIN rs_o[110]
    DIRECTION OUTPUT ;
    USE SIGNAL ;
    PORT
      LAYER M5 ;
        RECT  227.376 0 227.4 0.084 ;
    END
  END rs_o[110]
  PIN rs_o[111]
    DIRECTION OUTPUT ;
    USE SIGNAL ;
    PORT
      LAYER M5 ;
        RECT  227.568 0 227.592 0.084 ;
    END
  END rs_o[111]
  PIN rs_o[112]
    DIRECTION OUTPUT ;
    USE SIGNAL ;
    PORT
      LAYER M5 ;
        RECT  227.76 0 227.784 0.084 ;
    END
  END rs_o[112]
  PIN rs_o[113]
    DIRECTION OUTPUT ;
    USE SIGNAL ;
    PORT
      LAYER M5 ;
        RECT  227.952 0 227.976 0.084 ;
    END
  END rs_o[113]
  PIN rs_o[114]
    DIRECTION OUTPUT ;
    USE SIGNAL ;
    PORT
      LAYER M5 ;
        RECT  228.144 0 228.168 0.084 ;
    END
  END rs_o[114]
  PIN rs_o[115]
    DIRECTION OUTPUT ;
    USE SIGNAL ;
    PORT
      LAYER M5 ;
        RECT  228.336 0 228.36 0.084 ;
    END
  END rs_o[115]
  PIN rs_o[116]
    DIRECTION OUTPUT ;
    USE SIGNAL ;
    PORT
      LAYER M5 ;
        RECT  228.528 0 228.552 0.084 ;
    END
  END rs_o[116]
  PIN rs_o[117]
    DIRECTION OUTPUT ;
    USE SIGNAL ;
    PORT
      LAYER M5 ;
        RECT  228.72 0 228.744 0.084 ;
    END
  END rs_o[117]
  PIN rs_o[118]
    DIRECTION OUTPUT ;
    USE SIGNAL ;
    PORT
      LAYER M5 ;
        RECT  228.912 0 228.936 0.084 ;
    END
  END rs_o[118]
  PIN rs_o[119]
    DIRECTION OUTPUT ;
    USE SIGNAL ;
    PORT
      LAYER M5 ;
        RECT  229.104 0 229.128 0.084 ;
    END
  END rs_o[119]
  PIN rs_o[11]
    DIRECTION OUTPUT ;
    USE SIGNAL ;
    PORT
      LAYER M5 ;
        RECT  177.648 0 177.672 0.084 ;
    END
  END rs_o[11]
  PIN rs_o[120]
    DIRECTION OUTPUT ;
    USE SIGNAL ;
    PORT
      LAYER M5 ;
        RECT  229.296 0 229.32 0.084 ;
    END
  END rs_o[120]
  PIN rs_o[121]
    DIRECTION OUTPUT ;
    USE SIGNAL ;
    PORT
      LAYER M5 ;
        RECT  229.488 0 229.512 0.084 ;
    END
  END rs_o[121]
  PIN rs_o[122]
    DIRECTION OUTPUT ;
    USE SIGNAL ;
    PORT
      LAYER M5 ;
        RECT  229.68 0 229.704 0.084 ;
    END
  END rs_o[122]
  PIN rs_o[123]
    DIRECTION OUTPUT ;
    USE SIGNAL ;
    PORT
      LAYER M5 ;
        RECT  229.872 0 229.896 0.084 ;
    END
  END rs_o[123]
  PIN rs_o[124]
    DIRECTION OUTPUT ;
    USE SIGNAL ;
    PORT
      LAYER M5 ;
        RECT  230.064 0 230.088 0.084 ;
    END
  END rs_o[124]
  PIN rs_o[125]
    DIRECTION OUTPUT ;
    USE SIGNAL ;
    PORT
      LAYER M5 ;
        RECT  211.824 0 211.848 0.084 ;
    END
  END rs_o[125]
  PIN rs_o[126]
    DIRECTION OUTPUT ;
    USE SIGNAL ;
    PORT
      LAYER M5 ;
        RECT  212.016 0 212.04 0.084 ;
    END
  END rs_o[126]
  PIN rs_o[127]
    DIRECTION OUTPUT ;
    USE SIGNAL ;
    PORT
      LAYER M5 ;
        RECT  212.208 0 212.232 0.084 ;
    END
  END rs_o[127]
  PIN rs_o[128]
    DIRECTION OUTPUT ;
    USE SIGNAL ;
    PORT
      LAYER M5 ;
        RECT  212.4 0 212.424 0.084 ;
    END
  END rs_o[128]
  PIN rs_o[129]
    DIRECTION OUTPUT ;
    USE SIGNAL ;
    PORT
      LAYER M5 ;
        RECT  212.592 0 212.616 0.084 ;
    END
  END rs_o[129]
  PIN rs_o[12]
    DIRECTION OUTPUT ;
    USE SIGNAL ;
    PORT
      LAYER M5 ;
        RECT  177.84 0 177.864 0.084 ;
    END
  END rs_o[12]
  PIN rs_o[130]
    DIRECTION OUTPUT ;
    USE SIGNAL ;
    PORT
      LAYER M5 ;
        RECT  212.784 0 212.808 0.084 ;
    END
  END rs_o[130]
  PIN rs_o[131]
    DIRECTION OUTPUT ;
    USE SIGNAL ;
    PORT
      LAYER M5 ;
        RECT  212.976 0 213 0.084 ;
    END
  END rs_o[131]
  PIN rs_o[132]
    DIRECTION OUTPUT ;
    USE SIGNAL ;
    PORT
      LAYER M5 ;
        RECT  213.168 0 213.192 0.084 ;
    END
  END rs_o[132]
  PIN rs_o[133]
    DIRECTION OUTPUT ;
    USE SIGNAL ;
    PORT
      LAYER M5 ;
        RECT  213.36 0 213.384 0.084 ;
    END
  END rs_o[133]
  PIN rs_o[134]
    DIRECTION OUTPUT ;
    USE SIGNAL ;
    PORT
      LAYER M5 ;
        RECT  213.552 0 213.576 0.084 ;
    END
  END rs_o[134]
  PIN rs_o[135]
    DIRECTION OUTPUT ;
    USE SIGNAL ;
    PORT
      LAYER M5 ;
        RECT  213.744 0 213.768 0.084 ;
    END
  END rs_o[135]
  PIN rs_o[136]
    DIRECTION OUTPUT ;
    USE SIGNAL ;
    PORT
      LAYER M5 ;
        RECT  213.936 0 213.96 0.084 ;
    END
  END rs_o[136]
  PIN rs_o[137]
    DIRECTION OUTPUT ;
    USE SIGNAL ;
    PORT
      LAYER M5 ;
        RECT  214.128 0 214.152 0.084 ;
    END
  END rs_o[137]
  PIN rs_o[138]
    DIRECTION OUTPUT ;
    USE SIGNAL ;
    PORT
      LAYER M5 ;
        RECT  214.32 0 214.344 0.084 ;
    END
  END rs_o[138]
  PIN rs_o[139]
    DIRECTION OUTPUT ;
    USE SIGNAL ;
    PORT
      LAYER M5 ;
        RECT  214.512 0 214.536 0.084 ;
    END
  END rs_o[139]
  PIN rs_o[13]
    DIRECTION OUTPUT ;
    USE SIGNAL ;
    PORT
      LAYER M5 ;
        RECT  178.032 0 178.056 0.084 ;
    END
  END rs_o[13]
  PIN rs_o[140]
    DIRECTION OUTPUT ;
    USE SIGNAL ;
    PORT
      LAYER M5 ;
        RECT  214.704 0 214.728 0.084 ;
    END
  END rs_o[140]
  PIN rs_o[141]
    DIRECTION OUTPUT ;
    USE SIGNAL ;
    PORT
      LAYER M5 ;
        RECT  214.896 0 214.92 0.084 ;
    END
  END rs_o[141]
  PIN rs_o[142]
    DIRECTION OUTPUT ;
    USE SIGNAL ;
    PORT
      LAYER M5 ;
        RECT  215.088 0 215.112 0.084 ;
    END
  END rs_o[142]
  PIN rs_o[143]
    DIRECTION OUTPUT ;
    USE SIGNAL ;
    PORT
      LAYER M5 ;
        RECT  215.28 0 215.304 0.084 ;
    END
  END rs_o[143]
  PIN rs_o[144]
    DIRECTION OUTPUT ;
    USE SIGNAL ;
    PORT
      LAYER M5 ;
        RECT  215.472 0 215.496 0.084 ;
    END
  END rs_o[144]
  PIN rs_o[145]
    DIRECTION OUTPUT ;
    USE SIGNAL ;
    PORT
      LAYER M5 ;
        RECT  215.664 0 215.688 0.084 ;
    END
  END rs_o[145]
  PIN rs_o[146]
    DIRECTION OUTPUT ;
    USE SIGNAL ;
    PORT
      LAYER M5 ;
        RECT  215.856 0 215.88 0.084 ;
    END
  END rs_o[146]
  PIN rs_o[147]
    DIRECTION OUTPUT ;
    USE SIGNAL ;
    PORT
      LAYER M5 ;
        RECT  216.048 0 216.072 0.084 ;
    END
  END rs_o[147]
  PIN rs_o[148]
    DIRECTION OUTPUT ;
    USE SIGNAL ;
    PORT
      LAYER M5 ;
        RECT  216.24 0 216.264 0.084 ;
    END
  END rs_o[148]
  PIN rs_o[149]
    DIRECTION OUTPUT ;
    USE SIGNAL ;
    PORT
      LAYER M5 ;
        RECT  216.432 0 216.456 0.084 ;
    END
  END rs_o[149]
  PIN rs_o[14]
    DIRECTION OUTPUT ;
    USE SIGNAL ;
    PORT
      LAYER M5 ;
        RECT  178.224 0 178.248 0.084 ;
    END
  END rs_o[14]
  PIN rs_o[150]
    DIRECTION OUTPUT ;
    USE SIGNAL ;
    PORT
      LAYER M5 ;
        RECT  216.624 0 216.648 0.084 ;
    END
  END rs_o[150]
  PIN rs_o[151]
    DIRECTION OUTPUT ;
    USE SIGNAL ;
    PORT
      LAYER M5 ;
        RECT  216.816 0 216.84 0.084 ;
    END
  END rs_o[151]
  PIN rs_o[152]
    DIRECTION OUTPUT ;
    USE SIGNAL ;
    PORT
      LAYER M5 ;
        RECT  217.008 0 217.032 0.084 ;
    END
  END rs_o[152]
  PIN rs_o[153]
    DIRECTION OUTPUT ;
    USE SIGNAL ;
    PORT
      LAYER M5 ;
        RECT  217.2 0 217.224 0.084 ;
    END
  END rs_o[153]
  PIN rs_o[154]
    DIRECTION OUTPUT ;
    USE SIGNAL ;
    PORT
      LAYER M5 ;
        RECT  217.392 0 217.416 0.084 ;
    END
  END rs_o[154]
  PIN rs_o[155]
    DIRECTION OUTPUT ;
    USE SIGNAL ;
    PORT
      LAYER M5 ;
        RECT  217.584 0 217.608 0.084 ;
    END
  END rs_o[155]
  PIN rs_o[156]
    DIRECTION OUTPUT ;
    USE SIGNAL ;
    PORT
      LAYER M5 ;
        RECT  217.776 0 217.8 0.084 ;
    END
  END rs_o[156]
  PIN rs_o[157]
    DIRECTION OUTPUT ;
    USE SIGNAL ;
    PORT
      LAYER M5 ;
        RECT  217.968 0 217.992 0.084 ;
    END
  END rs_o[157]
  PIN rs_o[158]
    DIRECTION OUTPUT ;
    USE SIGNAL ;
    PORT
      LAYER M5 ;
        RECT  218.16 0 218.184 0.084 ;
    END
  END rs_o[158]
  PIN rs_o[159]
    DIRECTION OUTPUT ;
    USE SIGNAL ;
    PORT
      LAYER M5 ;
        RECT  218.352 0 218.376 0.084 ;
    END
  END rs_o[159]
  PIN rs_o[15]
    DIRECTION OUTPUT ;
    USE SIGNAL ;
    PORT
      LAYER M5 ;
        RECT  178.416 0 178.44 0.084 ;
    END
  END rs_o[15]
  PIN rs_o[160]
    DIRECTION OUTPUT ;
    USE SIGNAL ;
    PORT
      LAYER M5 ;
        RECT  218.544 0 218.568 0.084 ;
    END
  END rs_o[160]
  PIN rs_o[161]
    DIRECTION OUTPUT ;
    USE SIGNAL ;
    PORT
      LAYER M5 ;
        RECT  218.736 0 218.76 0.084 ;
    END
  END rs_o[161]
  PIN rs_o[162]
    DIRECTION OUTPUT ;
    USE SIGNAL ;
    PORT
      LAYER M5 ;
        RECT  218.928 0 218.952 0.084 ;
    END
  END rs_o[162]
  PIN rs_o[163]
    DIRECTION OUTPUT ;
    USE SIGNAL ;
    PORT
      LAYER M5 ;
        RECT  219.12 0 219.144 0.084 ;
    END
  END rs_o[163]
  PIN rs_o[164]
    DIRECTION OUTPUT ;
    USE SIGNAL ;
    PORT
      LAYER M5 ;
        RECT  219.312 0 219.336 0.084 ;
    END
  END rs_o[164]
  PIN rs_o[165]
    DIRECTION OUTPUT ;
    USE SIGNAL ;
    PORT
      LAYER M5 ;
        RECT  219.504 0 219.528 0.084 ;
    END
  END rs_o[165]
  PIN rs_o[166]
    DIRECTION OUTPUT ;
    USE SIGNAL ;
    PORT
      LAYER M5 ;
        RECT  219.696 0 219.72 0.084 ;
    END
  END rs_o[166]
  PIN rs_o[167]
    DIRECTION OUTPUT ;
    USE SIGNAL ;
    PORT
      LAYER M5 ;
        RECT  219.888 0 219.912 0.084 ;
    END
  END rs_o[167]
  PIN rs_o[168]
    DIRECTION OUTPUT ;
    USE SIGNAL ;
    PORT
      LAYER M5 ;
        RECT  220.08 0 220.104 0.084 ;
    END
  END rs_o[168]
  PIN rs_o[169]
    DIRECTION OUTPUT ;
    USE SIGNAL ;
    PORT
      LAYER M5 ;
        RECT  220.272 0 220.296 0.084 ;
    END
  END rs_o[169]
  PIN rs_o[16]
    DIRECTION OUTPUT ;
    USE SIGNAL ;
    PORT
      LAYER M5 ;
        RECT  178.608 0 178.632 0.084 ;
    END
  END rs_o[16]
  PIN rs_o[170]
    DIRECTION OUTPUT ;
    USE SIGNAL ;
    PORT
      LAYER M5 ;
        RECT  220.464 0 220.488 0.084 ;
    END
  END rs_o[170]
  PIN rs_o[171]
    DIRECTION OUTPUT ;
    USE SIGNAL ;
    PORT
      LAYER M5 ;
        RECT  220.656 0 220.68 0.084 ;
    END
  END rs_o[171]
  PIN rs_o[172]
    DIRECTION OUTPUT ;
    USE SIGNAL ;
    PORT
      LAYER M5 ;
        RECT  220.848 0 220.872 0.084 ;
    END
  END rs_o[172]
  PIN rs_o[173]
    DIRECTION OUTPUT ;
    USE SIGNAL ;
    PORT
      LAYER M5 ;
        RECT  221.04 0 221.064 0.084 ;
    END
  END rs_o[173]
  PIN rs_o[174]
    DIRECTION OUTPUT ;
    USE SIGNAL ;
    PORT
      LAYER M5 ;
        RECT  221.232 0 221.256 0.084 ;
    END
  END rs_o[174]
  PIN rs_o[175]
    DIRECTION OUTPUT ;
    USE SIGNAL ;
    PORT
      LAYER M5 ;
        RECT  221.424 0 221.448 0.084 ;
    END
  END rs_o[175]
  PIN rs_o[176]
    DIRECTION OUTPUT ;
    USE SIGNAL ;
    PORT
      LAYER M5 ;
        RECT  221.616 0 221.64 0.084 ;
    END
  END rs_o[176]
  PIN rs_o[177]
    DIRECTION OUTPUT ;
    USE SIGNAL ;
    PORT
      LAYER M5 ;
        RECT  221.808 0 221.832 0.084 ;
    END
  END rs_o[177]
  PIN rs_o[178]
    DIRECTION OUTPUT ;
    USE SIGNAL ;
    PORT
      LAYER M5 ;
        RECT  222 0 222.024 0.084 ;
    END
  END rs_o[178]
  PIN rs_o[179]
    DIRECTION OUTPUT ;
    USE SIGNAL ;
    PORT
      LAYER M5 ;
        RECT  222.192 0 222.216 0.084 ;
    END
  END rs_o[179]
  PIN rs_o[17]
    DIRECTION OUTPUT ;
    USE SIGNAL ;
    PORT
      LAYER M5 ;
        RECT  178.8 0 178.824 0.084 ;
    END
  END rs_o[17]
  PIN rs_o[180]
    DIRECTION OUTPUT ;
    USE SIGNAL ;
    PORT
      LAYER M5 ;
        RECT  222.384 0 222.408 0.084 ;
    END
  END rs_o[180]
  PIN rs_o[181]
    DIRECTION OUTPUT ;
    USE SIGNAL ;
    PORT
      LAYER M5 ;
        RECT  222.576 0 222.6 0.084 ;
    END
  END rs_o[181]
  PIN rs_o[182]
    DIRECTION OUTPUT ;
    USE SIGNAL ;
    PORT
      LAYER M5 ;
        RECT  222.768 0 222.792 0.084 ;
    END
  END rs_o[182]
  PIN rs_o[183]
    DIRECTION OUTPUT ;
    USE SIGNAL ;
    PORT
      LAYER M5 ;
        RECT  222.96 0 222.984 0.084 ;
    END
  END rs_o[183]
  PIN rs_o[184]
    DIRECTION OUTPUT ;
    USE SIGNAL ;
    PORT
      LAYER M5 ;
        RECT  223.152 0 223.176 0.084 ;
    END
  END rs_o[184]
  PIN rs_o[185]
    DIRECTION OUTPUT ;
    USE SIGNAL ;
    PORT
      LAYER M5 ;
        RECT  223.344 0 223.368 0.084 ;
    END
  END rs_o[185]
  PIN rs_o[186]
    DIRECTION OUTPUT ;
    USE SIGNAL ;
    PORT
      LAYER M5 ;
        RECT  223.536 0 223.56 0.084 ;
    END
  END rs_o[186]
  PIN rs_o[187]
    DIRECTION OUTPUT ;
    USE SIGNAL ;
    PORT
      LAYER M5 ;
        RECT  223.728 0 223.752 0.084 ;
    END
  END rs_o[187]
  PIN rs_o[188]
    DIRECTION OUTPUT ;
    USE SIGNAL ;
    PORT
      LAYER M5 ;
        RECT  223.92 0 223.944 0.084 ;
    END
  END rs_o[188]
  PIN rs_o[189]
    DIRECTION OUTPUT ;
    USE SIGNAL ;
    PORT
      LAYER M5 ;
        RECT  248.688 0 248.712 0.084 ;
    END
  END rs_o[189]
  PIN rs_o[18]
    DIRECTION OUTPUT ;
    USE SIGNAL ;
    PORT
      LAYER M5 ;
        RECT  178.992 0 179.016 0.084 ;
    END
  END rs_o[18]
  PIN rs_o[190]
    DIRECTION OUTPUT ;
    USE SIGNAL ;
    PORT
      LAYER M5 ;
        RECT  248.88 0 248.904 0.084 ;
    END
  END rs_o[190]
  PIN rs_o[191]
    DIRECTION OUTPUT ;
    USE SIGNAL ;
    PORT
      LAYER M5 ;
        RECT  249.072 0 249.096 0.084 ;
    END
  END rs_o[191]
  PIN rs_o[192]
    DIRECTION OUTPUT ;
    USE SIGNAL ;
    PORT
      LAYER M5 ;
        RECT  249.264 0 249.288 0.084 ;
    END
  END rs_o[192]
  PIN rs_o[193]
    DIRECTION OUTPUT ;
    USE SIGNAL ;
    PORT
      LAYER M5 ;
        RECT  249.456 0 249.48 0.084 ;
    END
  END rs_o[193]
  PIN rs_o[194]
    DIRECTION OUTPUT ;
    USE SIGNAL ;
    PORT
      LAYER M5 ;
        RECT  249.648 0 249.672 0.084 ;
    END
  END rs_o[194]
  PIN rs_o[195]
    DIRECTION OUTPUT ;
    USE SIGNAL ;
    PORT
      LAYER M5 ;
        RECT  249.84 0 249.864 0.084 ;
    END
  END rs_o[195]
  PIN rs_o[196]
    DIRECTION OUTPUT ;
    USE SIGNAL ;
    PORT
      LAYER M5 ;
        RECT  250.032 0 250.056 0.084 ;
    END
  END rs_o[196]
  PIN rs_o[197]
    DIRECTION OUTPUT ;
    USE SIGNAL ;
    PORT
      LAYER M5 ;
        RECT  250.224 0 250.248 0.084 ;
    END
  END rs_o[197]
  PIN rs_o[198]
    DIRECTION OUTPUT ;
    USE SIGNAL ;
    PORT
      LAYER M5 ;
        RECT  250.416 0 250.44 0.084 ;
    END
  END rs_o[198]
  PIN rs_o[199]
    DIRECTION OUTPUT ;
    USE SIGNAL ;
    PORT
      LAYER M5 ;
        RECT  250.608 0 250.632 0.084 ;
    END
  END rs_o[199]
  PIN rs_o[19]
    DIRECTION OUTPUT ;
    USE SIGNAL ;
    PORT
      LAYER M5 ;
        RECT  179.184 0 179.208 0.084 ;
    END
  END rs_o[19]
  PIN rs_o[1]
    DIRECTION OUTPUT ;
    USE SIGNAL ;
    PORT
      LAYER M5 ;
        RECT  175.728 0 175.752 0.084 ;
    END
  END rs_o[1]
  PIN rs_o[200]
    DIRECTION OUTPUT ;
    USE SIGNAL ;
    PORT
      LAYER M5 ;
        RECT  250.8 0 250.824 0.084 ;
    END
  END rs_o[200]
  PIN rs_o[201]
    DIRECTION OUTPUT ;
    USE SIGNAL ;
    PORT
      LAYER M5 ;
        RECT  250.992 0 251.016 0.084 ;
    END
  END rs_o[201]
  PIN rs_o[202]
    DIRECTION OUTPUT ;
    USE SIGNAL ;
    PORT
      LAYER M5 ;
        RECT  251.184 0 251.208 0.084 ;
    END
  END rs_o[202]
  PIN rs_o[203]
    DIRECTION OUTPUT ;
    USE SIGNAL ;
    PORT
      LAYER M5 ;
        RECT  251.376 0 251.4 0.084 ;
    END
  END rs_o[203]
  PIN rs_o[204]
    DIRECTION OUTPUT ;
    USE SIGNAL ;
    PORT
      LAYER M5 ;
        RECT  251.568 0 251.592 0.084 ;
    END
  END rs_o[204]
  PIN rs_o[205]
    DIRECTION OUTPUT ;
    USE SIGNAL ;
    PORT
      LAYER M5 ;
        RECT  251.76 0 251.784 0.084 ;
    END
  END rs_o[205]
  PIN rs_o[206]
    DIRECTION OUTPUT ;
    USE SIGNAL ;
    PORT
      LAYER M5 ;
        RECT  251.952 0 251.976 0.084 ;
    END
  END rs_o[206]
  PIN rs_o[207]
    DIRECTION OUTPUT ;
    USE SIGNAL ;
    PORT
      LAYER M5 ;
        RECT  252.144 0 252.168 0.084 ;
    END
  END rs_o[207]
  PIN rs_o[208]
    DIRECTION OUTPUT ;
    USE SIGNAL ;
    PORT
      LAYER M5 ;
        RECT  252.336 0 252.36 0.084 ;
    END
  END rs_o[208]
  PIN rs_o[209]
    DIRECTION OUTPUT ;
    USE SIGNAL ;
    PORT
      LAYER M5 ;
        RECT  252.528 0 252.552 0.084 ;
    END
  END rs_o[209]
  PIN rs_o[20]
    DIRECTION OUTPUT ;
    USE SIGNAL ;
    PORT
      LAYER M5 ;
        RECT  179.376 0 179.4 0.084 ;
    END
  END rs_o[20]
  PIN rs_o[210]
    DIRECTION OUTPUT ;
    USE SIGNAL ;
    PORT
      LAYER M5 ;
        RECT  252.72 0 252.744 0.084 ;
    END
  END rs_o[210]
  PIN rs_o[211]
    DIRECTION OUTPUT ;
    USE SIGNAL ;
    PORT
      LAYER M5 ;
        RECT  252.912 0 252.936 0.084 ;
    END
  END rs_o[211]
  PIN rs_o[212]
    DIRECTION OUTPUT ;
    USE SIGNAL ;
    PORT
      LAYER M5 ;
        RECT  253.104 0 253.128 0.084 ;
    END
  END rs_o[212]
  PIN rs_o[213]
    DIRECTION OUTPUT ;
    USE SIGNAL ;
    PORT
      LAYER M5 ;
        RECT  253.296 0 253.32 0.084 ;
    END
  END rs_o[213]
  PIN rs_o[214]
    DIRECTION OUTPUT ;
    USE SIGNAL ;
    PORT
      LAYER M5 ;
        RECT  253.488 0 253.512 0.084 ;
    END
  END rs_o[214]
  PIN rs_o[215]
    DIRECTION OUTPUT ;
    USE SIGNAL ;
    PORT
      LAYER M5 ;
        RECT  253.68 0 253.704 0.084 ;
    END
  END rs_o[215]
  PIN rs_o[216]
    DIRECTION OUTPUT ;
    USE SIGNAL ;
    PORT
      LAYER M5 ;
        RECT  253.872 0 253.896 0.084 ;
    END
  END rs_o[216]
  PIN rs_o[217]
    DIRECTION OUTPUT ;
    USE SIGNAL ;
    PORT
      LAYER M5 ;
        RECT  254.064 0 254.088 0.084 ;
    END
  END rs_o[217]
  PIN rs_o[218]
    DIRECTION OUTPUT ;
    USE SIGNAL ;
    PORT
      LAYER M5 ;
        RECT  254.256 0 254.28 0.084 ;
    END
  END rs_o[218]
  PIN rs_o[219]
    DIRECTION OUTPUT ;
    USE SIGNAL ;
    PORT
      LAYER M5 ;
        RECT  254.448 0 254.472 0.084 ;
    END
  END rs_o[219]
  PIN rs_o[21]
    DIRECTION OUTPUT ;
    USE SIGNAL ;
    PORT
      LAYER M5 ;
        RECT  179.568 0 179.592 0.084 ;
    END
  END rs_o[21]
  PIN rs_o[220]
    DIRECTION OUTPUT ;
    USE SIGNAL ;
    PORT
      LAYER M5 ;
        RECT  254.64 0 254.664 0.084 ;
    END
  END rs_o[220]
  PIN rs_o[221]
    DIRECTION OUTPUT ;
    USE SIGNAL ;
    PORT
      LAYER M5 ;
        RECT  242.544 0 242.568 0.084 ;
    END
  END rs_o[221]
  PIN rs_o[222]
    DIRECTION OUTPUT ;
    USE SIGNAL ;
    PORT
      LAYER M5 ;
        RECT  242.736 0 242.76 0.084 ;
    END
  END rs_o[222]
  PIN rs_o[223]
    DIRECTION OUTPUT ;
    USE SIGNAL ;
    PORT
      LAYER M5 ;
        RECT  242.928 0 242.952 0.084 ;
    END
  END rs_o[223]
  PIN rs_o[224]
    DIRECTION OUTPUT ;
    USE SIGNAL ;
    PORT
      LAYER M5 ;
        RECT  243.12 0 243.144 0.084 ;
    END
  END rs_o[224]
  PIN rs_o[225]
    DIRECTION OUTPUT ;
    USE SIGNAL ;
    PORT
      LAYER M5 ;
        RECT  243.312 0 243.336 0.084 ;
    END
  END rs_o[225]
  PIN rs_o[226]
    DIRECTION OUTPUT ;
    USE SIGNAL ;
    PORT
      LAYER M5 ;
        RECT  243.504 0 243.528 0.084 ;
    END
  END rs_o[226]
  PIN rs_o[227]
    DIRECTION OUTPUT ;
    USE SIGNAL ;
    PORT
      LAYER M5 ;
        RECT  243.696 0 243.72 0.084 ;
    END
  END rs_o[227]
  PIN rs_o[228]
    DIRECTION OUTPUT ;
    USE SIGNAL ;
    PORT
      LAYER M5 ;
        RECT  243.888 0 243.912 0.084 ;
    END
  END rs_o[228]
  PIN rs_o[229]
    DIRECTION OUTPUT ;
    USE SIGNAL ;
    PORT
      LAYER M5 ;
        RECT  244.08 0 244.104 0.084 ;
    END
  END rs_o[229]
  PIN rs_o[22]
    DIRECTION OUTPUT ;
    USE SIGNAL ;
    PORT
      LAYER M5 ;
        RECT  179.76 0 179.784 0.084 ;
    END
  END rs_o[22]
  PIN rs_o[230]
    DIRECTION OUTPUT ;
    USE SIGNAL ;
    PORT
      LAYER M5 ;
        RECT  244.272 0 244.296 0.084 ;
    END
  END rs_o[230]
  PIN rs_o[231]
    DIRECTION OUTPUT ;
    USE SIGNAL ;
    PORT
      LAYER M5 ;
        RECT  244.464 0 244.488 0.084 ;
    END
  END rs_o[231]
  PIN rs_o[232]
    DIRECTION OUTPUT ;
    USE SIGNAL ;
    PORT
      LAYER M5 ;
        RECT  244.656 0 244.68 0.084 ;
    END
  END rs_o[232]
  PIN rs_o[233]
    DIRECTION OUTPUT ;
    USE SIGNAL ;
    PORT
      LAYER M5 ;
        RECT  244.848 0 244.872 0.084 ;
    END
  END rs_o[233]
  PIN rs_o[234]
    DIRECTION OUTPUT ;
    USE SIGNAL ;
    PORT
      LAYER M5 ;
        RECT  245.04 0 245.064 0.084 ;
    END
  END rs_o[234]
  PIN rs_o[235]
    DIRECTION OUTPUT ;
    USE SIGNAL ;
    PORT
      LAYER M5 ;
        RECT  245.232 0 245.256 0.084 ;
    END
  END rs_o[235]
  PIN rs_o[236]
    DIRECTION OUTPUT ;
    USE SIGNAL ;
    PORT
      LAYER M5 ;
        RECT  245.424 0 245.448 0.084 ;
    END
  END rs_o[236]
  PIN rs_o[237]
    DIRECTION OUTPUT ;
    USE SIGNAL ;
    PORT
      LAYER M5 ;
        RECT  245.616 0 245.64 0.084 ;
    END
  END rs_o[237]
  PIN rs_o[238]
    DIRECTION OUTPUT ;
    USE SIGNAL ;
    PORT
      LAYER M5 ;
        RECT  245.808 0 245.832 0.084 ;
    END
  END rs_o[238]
  PIN rs_o[239]
    DIRECTION OUTPUT ;
    USE SIGNAL ;
    PORT
      LAYER M5 ;
        RECT  246 0 246.024 0.084 ;
    END
  END rs_o[239]
  PIN rs_o[23]
    DIRECTION OUTPUT ;
    USE SIGNAL ;
    PORT
      LAYER M5 ;
        RECT  179.952 0 179.976 0.084 ;
    END
  END rs_o[23]
  PIN rs_o[240]
    DIRECTION OUTPUT ;
    USE SIGNAL ;
    PORT
      LAYER M5 ;
        RECT  246.192 0 246.216 0.084 ;
    END
  END rs_o[240]
  PIN rs_o[241]
    DIRECTION OUTPUT ;
    USE SIGNAL ;
    PORT
      LAYER M5 ;
        RECT  246.384 0 246.408 0.084 ;
    END
  END rs_o[241]
  PIN rs_o[242]
    DIRECTION OUTPUT ;
    USE SIGNAL ;
    PORT
      LAYER M5 ;
        RECT  246.576 0 246.6 0.084 ;
    END
  END rs_o[242]
  PIN rs_o[243]
    DIRECTION OUTPUT ;
    USE SIGNAL ;
    PORT
      LAYER M5 ;
        RECT  246.768 0 246.792 0.084 ;
    END
  END rs_o[243]
  PIN rs_o[244]
    DIRECTION OUTPUT ;
    USE SIGNAL ;
    PORT
      LAYER M5 ;
        RECT  246.96 0 246.984 0.084 ;
    END
  END rs_o[244]
  PIN rs_o[245]
    DIRECTION OUTPUT ;
    USE SIGNAL ;
    PORT
      LAYER M5 ;
        RECT  247.152 0 247.176 0.084 ;
    END
  END rs_o[245]
  PIN rs_o[246]
    DIRECTION OUTPUT ;
    USE SIGNAL ;
    PORT
      LAYER M5 ;
        RECT  247.344 0 247.368 0.084 ;
    END
  END rs_o[246]
  PIN rs_o[247]
    DIRECTION OUTPUT ;
    USE SIGNAL ;
    PORT
      LAYER M5 ;
        RECT  247.536 0 247.56 0.084 ;
    END
  END rs_o[247]
  PIN rs_o[248]
    DIRECTION OUTPUT ;
    USE SIGNAL ;
    PORT
      LAYER M5 ;
        RECT  247.728 0 247.752 0.084 ;
    END
  END rs_o[248]
  PIN rs_o[249]
    DIRECTION OUTPUT ;
    USE SIGNAL ;
    PORT
      LAYER M5 ;
        RECT  247.92 0 247.944 0.084 ;
    END
  END rs_o[249]
  PIN rs_o[24]
    DIRECTION OUTPUT ;
    USE SIGNAL ;
    PORT
      LAYER M5 ;
        RECT  180.144 0 180.168 0.084 ;
    END
  END rs_o[24]
  PIN rs_o[250]
    DIRECTION OUTPUT ;
    USE SIGNAL ;
    PORT
      LAYER M5 ;
        RECT  248.112 0 248.136 0.084 ;
    END
  END rs_o[250]
  PIN rs_o[251]
    DIRECTION OUTPUT ;
    USE SIGNAL ;
    PORT
      LAYER M5 ;
        RECT  248.304 0 248.328 0.084 ;
    END
  END rs_o[251]
  PIN rs_o[252]
    DIRECTION OUTPUT ;
    USE SIGNAL ;
    PORT
      LAYER M5 ;
        RECT  248.496 0 248.52 0.084 ;
    END
  END rs_o[252]
  PIN rs_o[253]
    DIRECTION OUTPUT ;
    USE SIGNAL ;
    PORT
      LAYER M5 ;
        RECT  254.832 0 254.856 0.084 ;
    END
  END rs_o[253]
  PIN rs_o[254]
    DIRECTION OUTPUT ;
    USE SIGNAL ;
    PORT
      LAYER M5 ;
        RECT  255.024 0 255.048 0.084 ;
    END
  END rs_o[254]
  PIN rs_o[255]
    DIRECTION OUTPUT ;
    USE SIGNAL ;
    PORT
      LAYER M5 ;
        RECT  255.216 0 255.24 0.084 ;
    END
  END rs_o[255]
  PIN rs_o[256]
    DIRECTION OUTPUT ;
    USE SIGNAL ;
    PORT
      LAYER M5 ;
        RECT  255.408 0 255.432 0.084 ;
    END
  END rs_o[256]
  PIN rs_o[257]
    DIRECTION OUTPUT ;
    USE SIGNAL ;
    PORT
      LAYER M5 ;
        RECT  255.6 0 255.624 0.084 ;
    END
  END rs_o[257]
  PIN rs_o[258]
    DIRECTION OUTPUT ;
    USE SIGNAL ;
    PORT
      LAYER M5 ;
        RECT  255.792 0 255.816 0.084 ;
    END
  END rs_o[258]
  PIN rs_o[259]
    DIRECTION OUTPUT ;
    USE SIGNAL ;
    PORT
      LAYER M5 ;
        RECT  255.984 0 256.008 0.084 ;
    END
  END rs_o[259]
  PIN rs_o[25]
    DIRECTION OUTPUT ;
    USE SIGNAL ;
    PORT
      LAYER M5 ;
        RECT  180.336 0 180.36 0.084 ;
    END
  END rs_o[25]
  PIN rs_o[260]
    DIRECTION OUTPUT ;
    USE SIGNAL ;
    PORT
      LAYER M5 ;
        RECT  256.176 0 256.2 0.084 ;
    END
  END rs_o[260]
  PIN rs_o[261]
    DIRECTION OUTPUT ;
    USE SIGNAL ;
    PORT
      LAYER M5 ;
        RECT  256.368 0 256.392 0.084 ;
    END
  END rs_o[261]
  PIN rs_o[262]
    DIRECTION OUTPUT ;
    USE SIGNAL ;
    PORT
      LAYER M5 ;
        RECT  256.56 0 256.584 0.084 ;
    END
  END rs_o[262]
  PIN rs_o[263]
    DIRECTION OUTPUT ;
    USE SIGNAL ;
    PORT
      LAYER M5 ;
        RECT  256.752 0 256.776 0.084 ;
    END
  END rs_o[263]
  PIN rs_o[264]
    DIRECTION OUTPUT ;
    USE SIGNAL ;
    PORT
      LAYER M5 ;
        RECT  256.944 0 256.968 0.084 ;
    END
  END rs_o[264]
  PIN rs_o[265]
    DIRECTION OUTPUT ;
    USE SIGNAL ;
    PORT
      LAYER M5 ;
        RECT  257.136 0 257.16 0.084 ;
    END
  END rs_o[265]
  PIN rs_o[266]
    DIRECTION OUTPUT ;
    USE SIGNAL ;
    PORT
      LAYER M5 ;
        RECT  257.328 0 257.352 0.084 ;
    END
  END rs_o[266]
  PIN rs_o[267]
    DIRECTION OUTPUT ;
    USE SIGNAL ;
    PORT
      LAYER M5 ;
        RECT  257.52 0 257.544 0.084 ;
    END
  END rs_o[267]
  PIN rs_o[268]
    DIRECTION OUTPUT ;
    USE SIGNAL ;
    PORT
      LAYER M5 ;
        RECT  257.712 0 257.736 0.084 ;
    END
  END rs_o[268]
  PIN rs_o[269]
    DIRECTION OUTPUT ;
    USE SIGNAL ;
    PORT
      LAYER M5 ;
        RECT  257.904 0 257.928 0.084 ;
    END
  END rs_o[269]
  PIN rs_o[26]
    DIRECTION OUTPUT ;
    USE SIGNAL ;
    PORT
      LAYER M5 ;
        RECT  180.528 0 180.552 0.084 ;
    END
  END rs_o[26]
  PIN rs_o[270]
    DIRECTION OUTPUT ;
    USE SIGNAL ;
    PORT
      LAYER M5 ;
        RECT  258.096 0 258.12 0.084 ;
    END
  END rs_o[270]
  PIN rs_o[271]
    DIRECTION OUTPUT ;
    USE SIGNAL ;
    PORT
      LAYER M5 ;
        RECT  258.288 0 258.312 0.084 ;
    END
  END rs_o[271]
  PIN rs_o[272]
    DIRECTION OUTPUT ;
    USE SIGNAL ;
    PORT
      LAYER M5 ;
        RECT  258.48 0 258.504 0.084 ;
    END
  END rs_o[272]
  PIN rs_o[273]
    DIRECTION OUTPUT ;
    USE SIGNAL ;
    PORT
      LAYER M5 ;
        RECT  258.672 0 258.696 0.084 ;
    END
  END rs_o[273]
  PIN rs_o[274]
    DIRECTION OUTPUT ;
    USE SIGNAL ;
    PORT
      LAYER M5 ;
        RECT  258.864 0 258.888 0.084 ;
    END
  END rs_o[274]
  PIN rs_o[275]
    DIRECTION OUTPUT ;
    USE SIGNAL ;
    PORT
      LAYER M5 ;
        RECT  259.056 0 259.08 0.084 ;
    END
  END rs_o[275]
  PIN rs_o[27]
    DIRECTION OUTPUT ;
    USE SIGNAL ;
    PORT
      LAYER M5 ;
        RECT  180.72 0 180.744 0.084 ;
    END
  END rs_o[27]
  PIN rs_o[28]
    DIRECTION OUTPUT ;
    USE SIGNAL ;
    PORT
      LAYER M5 ;
        RECT  180.912 0 180.936 0.084 ;
    END
  END rs_o[28]
  PIN rs_o[29]
    DIRECTION OUTPUT ;
    USE SIGNAL ;
    PORT
      LAYER M5 ;
        RECT  230.256 0 230.28 0.084 ;
    END
  END rs_o[29]
  PIN rs_o[2]
    DIRECTION OUTPUT ;
    USE SIGNAL ;
    PORT
      LAYER M5 ;
        RECT  175.92 0 175.944 0.084 ;
    END
  END rs_o[2]
  PIN rs_o[30]
    DIRECTION OUTPUT ;
    USE SIGNAL ;
    PORT
      LAYER M5 ;
        RECT  230.448 0 230.472 0.084 ;
    END
  END rs_o[30]
  PIN rs_o[31]
    DIRECTION OUTPUT ;
    USE SIGNAL ;
    PORT
      LAYER M5 ;
        RECT  230.64 0 230.664 0.084 ;
    END
  END rs_o[31]
  PIN rs_o[32]
    DIRECTION OUTPUT ;
    USE SIGNAL ;
    PORT
      LAYER M5 ;
        RECT  230.832 0 230.856 0.084 ;
    END
  END rs_o[32]
  PIN rs_o[33]
    DIRECTION OUTPUT ;
    USE SIGNAL ;
    PORT
      LAYER M5 ;
        RECT  231.024 0 231.048 0.084 ;
    END
  END rs_o[33]
  PIN rs_o[34]
    DIRECTION OUTPUT ;
    USE SIGNAL ;
    PORT
      LAYER M5 ;
        RECT  231.216 0 231.24 0.084 ;
    END
  END rs_o[34]
  PIN rs_o[35]
    DIRECTION OUTPUT ;
    USE SIGNAL ;
    PORT
      LAYER M5 ;
        RECT  231.408 0 231.432 0.084 ;
    END
  END rs_o[35]
  PIN rs_o[36]
    DIRECTION OUTPUT ;
    USE SIGNAL ;
    PORT
      LAYER M5 ;
        RECT  231.6 0 231.624 0.084 ;
    END
  END rs_o[36]
  PIN rs_o[37]
    DIRECTION OUTPUT ;
    USE SIGNAL ;
    PORT
      LAYER M5 ;
        RECT  231.792 0 231.816 0.084 ;
    END
  END rs_o[37]
  PIN rs_o[38]
    DIRECTION OUTPUT ;
    USE SIGNAL ;
    PORT
      LAYER M5 ;
        RECT  231.984 0 232.008 0.084 ;
    END
  END rs_o[38]
  PIN rs_o[39]
    DIRECTION OUTPUT ;
    USE SIGNAL ;
    PORT
      LAYER M5 ;
        RECT  232.176 0 232.2 0.084 ;
    END
  END rs_o[39]
  PIN rs_o[3]
    DIRECTION OUTPUT ;
    USE SIGNAL ;
    PORT
      LAYER M5 ;
        RECT  176.112 0 176.136 0.084 ;
    END
  END rs_o[3]
  PIN rs_o[40]
    DIRECTION OUTPUT ;
    USE SIGNAL ;
    PORT
      LAYER M5 ;
        RECT  232.368 0 232.392 0.084 ;
    END
  END rs_o[40]
  PIN rs_o[41]
    DIRECTION OUTPUT ;
    USE SIGNAL ;
    PORT
      LAYER M5 ;
        RECT  232.56 0 232.584 0.084 ;
    END
  END rs_o[41]
  PIN rs_o[42]
    DIRECTION OUTPUT ;
    USE SIGNAL ;
    PORT
      LAYER M5 ;
        RECT  232.752 0 232.776 0.084 ;
    END
  END rs_o[42]
  PIN rs_o[43]
    DIRECTION OUTPUT ;
    USE SIGNAL ;
    PORT
      LAYER M5 ;
        RECT  232.944 0 232.968 0.084 ;
    END
  END rs_o[43]
  PIN rs_o[44]
    DIRECTION OUTPUT ;
    USE SIGNAL ;
    PORT
      LAYER M5 ;
        RECT  233.136 0 233.16 0.084 ;
    END
  END rs_o[44]
  PIN rs_o[45]
    DIRECTION OUTPUT ;
    USE SIGNAL ;
    PORT
      LAYER M5 ;
        RECT  233.328 0 233.352 0.084 ;
    END
  END rs_o[45]
  PIN rs_o[46]
    DIRECTION OUTPUT ;
    USE SIGNAL ;
    PORT
      LAYER M5 ;
        RECT  233.52 0 233.544 0.084 ;
    END
  END rs_o[46]
  PIN rs_o[47]
    DIRECTION OUTPUT ;
    USE SIGNAL ;
    PORT
      LAYER M5 ;
        RECT  233.712 0 233.736 0.084 ;
    END
  END rs_o[47]
  PIN rs_o[48]
    DIRECTION OUTPUT ;
    USE SIGNAL ;
    PORT
      LAYER M5 ;
        RECT  233.904 0 233.928 0.084 ;
    END
  END rs_o[48]
  PIN rs_o[49]
    DIRECTION OUTPUT ;
    USE SIGNAL ;
    PORT
      LAYER M5 ;
        RECT  234.096 0 234.12 0.084 ;
    END
  END rs_o[49]
  PIN rs_o[4]
    DIRECTION OUTPUT ;
    USE SIGNAL ;
    PORT
      LAYER M5 ;
        RECT  176.304 0 176.328 0.084 ;
    END
  END rs_o[4]
  PIN rs_o[50]
    DIRECTION OUTPUT ;
    USE SIGNAL ;
    PORT
      LAYER M5 ;
        RECT  234.288 0 234.312 0.084 ;
    END
  END rs_o[50]
  PIN rs_o[51]
    DIRECTION OUTPUT ;
    USE SIGNAL ;
    PORT
      LAYER M5 ;
        RECT  234.48 0 234.504 0.084 ;
    END
  END rs_o[51]
  PIN rs_o[52]
    DIRECTION OUTPUT ;
    USE SIGNAL ;
    PORT
      LAYER M5 ;
        RECT  234.672 0 234.696 0.084 ;
    END
  END rs_o[52]
  PIN rs_o[53]
    DIRECTION OUTPUT ;
    USE SIGNAL ;
    PORT
      LAYER M5 ;
        RECT  234.864 0 234.888 0.084 ;
    END
  END rs_o[53]
  PIN rs_o[54]
    DIRECTION OUTPUT ;
    USE SIGNAL ;
    PORT
      LAYER M5 ;
        RECT  235.056 0 235.08 0.084 ;
    END
  END rs_o[54]
  PIN rs_o[55]
    DIRECTION OUTPUT ;
    USE SIGNAL ;
    PORT
      LAYER M5 ;
        RECT  235.248 0 235.272 0.084 ;
    END
  END rs_o[55]
  PIN rs_o[56]
    DIRECTION OUTPUT ;
    USE SIGNAL ;
    PORT
      LAYER M5 ;
        RECT  235.44 0 235.464 0.084 ;
    END
  END rs_o[56]
  PIN rs_o[57]
    DIRECTION OUTPUT ;
    USE SIGNAL ;
    PORT
      LAYER M5 ;
        RECT  235.632 0 235.656 0.084 ;
    END
  END rs_o[57]
  PIN rs_o[58]
    DIRECTION OUTPUT ;
    USE SIGNAL ;
    PORT
      LAYER M5 ;
        RECT  235.824 0 235.848 0.084 ;
    END
  END rs_o[58]
  PIN rs_o[59]
    DIRECTION OUTPUT ;
    USE SIGNAL ;
    PORT
      LAYER M5 ;
        RECT  236.016 0 236.04 0.084 ;
    END
  END rs_o[59]
  PIN rs_o[5]
    DIRECTION OUTPUT ;
    USE SIGNAL ;
    PORT
      LAYER M5 ;
        RECT  176.496 0 176.52 0.084 ;
    END
  END rs_o[5]
  PIN rs_o[60]
    DIRECTION OUTPUT ;
    USE SIGNAL ;
    PORT
      LAYER M5 ;
        RECT  236.208 0 236.232 0.084 ;
    END
  END rs_o[60]
  PIN rs_o[61]
    DIRECTION OUTPUT ;
    USE SIGNAL ;
    PORT
      LAYER M5 ;
        RECT  205.68 0 205.704 0.084 ;
    END
  END rs_o[61]
  PIN rs_o[62]
    DIRECTION OUTPUT ;
    USE SIGNAL ;
    PORT
      LAYER M5 ;
        RECT  205.872 0 205.896 0.084 ;
    END
  END rs_o[62]
  PIN rs_o[63]
    DIRECTION OUTPUT ;
    USE SIGNAL ;
    PORT
      LAYER M5 ;
        RECT  206.064 0 206.088 0.084 ;
    END
  END rs_o[63]
  PIN rs_o[64]
    DIRECTION OUTPUT ;
    USE SIGNAL ;
    PORT
      LAYER M5 ;
        RECT  206.256 0 206.28 0.084 ;
    END
  END rs_o[64]
  PIN rs_o[65]
    DIRECTION OUTPUT ;
    USE SIGNAL ;
    PORT
      LAYER M5 ;
        RECT  206.448 0 206.472 0.084 ;
    END
  END rs_o[65]
  PIN rs_o[66]
    DIRECTION OUTPUT ;
    USE SIGNAL ;
    PORT
      LAYER M5 ;
        RECT  206.64 0 206.664 0.084 ;
    END
  END rs_o[66]
  PIN rs_o[67]
    DIRECTION OUTPUT ;
    USE SIGNAL ;
    PORT
      LAYER M5 ;
        RECT  206.832 0 206.856 0.084 ;
    END
  END rs_o[67]
  PIN rs_o[68]
    DIRECTION OUTPUT ;
    USE SIGNAL ;
    PORT
      LAYER M5 ;
        RECT  207.024 0 207.048 0.084 ;
    END
  END rs_o[68]
  PIN rs_o[69]
    DIRECTION OUTPUT ;
    USE SIGNAL ;
    PORT
      LAYER M5 ;
        RECT  207.216 0 207.24 0.084 ;
    END
  END rs_o[69]
  PIN rs_o[6]
    DIRECTION OUTPUT ;
    USE SIGNAL ;
    PORT
      LAYER M5 ;
        RECT  176.688 0 176.712 0.084 ;
    END
  END rs_o[6]
  PIN rs_o[70]
    DIRECTION OUTPUT ;
    USE SIGNAL ;
    PORT
      LAYER M5 ;
        RECT  207.408 0 207.432 0.084 ;
    END
  END rs_o[70]
  PIN rs_o[71]
    DIRECTION OUTPUT ;
    USE SIGNAL ;
    PORT
      LAYER M5 ;
        RECT  207.6 0 207.624 0.084 ;
    END
  END rs_o[71]
  PIN rs_o[72]
    DIRECTION OUTPUT ;
    USE SIGNAL ;
    PORT
      LAYER M5 ;
        RECT  207.792 0 207.816 0.084 ;
    END
  END rs_o[72]
  PIN rs_o[73]
    DIRECTION OUTPUT ;
    USE SIGNAL ;
    PORT
      LAYER M5 ;
        RECT  207.984 0 208.008 0.084 ;
    END
  END rs_o[73]
  PIN rs_o[74]
    DIRECTION OUTPUT ;
    USE SIGNAL ;
    PORT
      LAYER M5 ;
        RECT  208.176 0 208.2 0.084 ;
    END
  END rs_o[74]
  PIN rs_o[75]
    DIRECTION OUTPUT ;
    USE SIGNAL ;
    PORT
      LAYER M5 ;
        RECT  208.368 0 208.392 0.084 ;
    END
  END rs_o[75]
  PIN rs_o[76]
    DIRECTION OUTPUT ;
    USE SIGNAL ;
    PORT
      LAYER M5 ;
        RECT  208.56 0 208.584 0.084 ;
    END
  END rs_o[76]
  PIN rs_o[77]
    DIRECTION OUTPUT ;
    USE SIGNAL ;
    PORT
      LAYER M5 ;
        RECT  208.752 0 208.776 0.084 ;
    END
  END rs_o[77]
  PIN rs_o[78]
    DIRECTION OUTPUT ;
    USE SIGNAL ;
    PORT
      LAYER M5 ;
        RECT  208.944 0 208.968 0.084 ;
    END
  END rs_o[78]
  PIN rs_o[79]
    DIRECTION OUTPUT ;
    USE SIGNAL ;
    PORT
      LAYER M5 ;
        RECT  209.136 0 209.16 0.084 ;
    END
  END rs_o[79]
  PIN rs_o[7]
    DIRECTION OUTPUT ;
    USE SIGNAL ;
    PORT
      LAYER M5 ;
        RECT  176.88 0 176.904 0.084 ;
    END
  END rs_o[7]
  PIN rs_o[80]
    DIRECTION OUTPUT ;
    USE SIGNAL ;
    PORT
      LAYER M5 ;
        RECT  209.328 0 209.352 0.084 ;
    END
  END rs_o[80]
  PIN rs_o[81]
    DIRECTION OUTPUT ;
    USE SIGNAL ;
    PORT
      LAYER M5 ;
        RECT  209.52 0 209.544 0.084 ;
    END
  END rs_o[81]
  PIN rs_o[82]
    DIRECTION OUTPUT ;
    USE SIGNAL ;
    PORT
      LAYER M5 ;
        RECT  209.712 0 209.736 0.084 ;
    END
  END rs_o[82]
  PIN rs_o[83]
    DIRECTION OUTPUT ;
    USE SIGNAL ;
    PORT
      LAYER M5 ;
        RECT  209.904 0 209.928 0.084 ;
    END
  END rs_o[83]
  PIN rs_o[84]
    DIRECTION OUTPUT ;
    USE SIGNAL ;
    PORT
      LAYER M5 ;
        RECT  210.096 0 210.12 0.084 ;
    END
  END rs_o[84]
  PIN rs_o[85]
    DIRECTION OUTPUT ;
    USE SIGNAL ;
    PORT
      LAYER M5 ;
        RECT  210.288 0 210.312 0.084 ;
    END
  END rs_o[85]
  PIN rs_o[86]
    DIRECTION OUTPUT ;
    USE SIGNAL ;
    PORT
      LAYER M5 ;
        RECT  210.48 0 210.504 0.084 ;
    END
  END rs_o[86]
  PIN rs_o[87]
    DIRECTION OUTPUT ;
    USE SIGNAL ;
    PORT
      LAYER M5 ;
        RECT  210.672 0 210.696 0.084 ;
    END
  END rs_o[87]
  PIN rs_o[88]
    DIRECTION OUTPUT ;
    USE SIGNAL ;
    PORT
      LAYER M5 ;
        RECT  210.864 0 210.888 0.084 ;
    END
  END rs_o[88]
  PIN rs_o[89]
    DIRECTION OUTPUT ;
    USE SIGNAL ;
    PORT
      LAYER M5 ;
        RECT  211.056 0 211.08 0.084 ;
    END
  END rs_o[89]
  PIN rs_o[8]
    DIRECTION OUTPUT ;
    USE SIGNAL ;
    PORT
      LAYER M5 ;
        RECT  177.072 0 177.096 0.084 ;
    END
  END rs_o[8]
  PIN rs_o[90]
    DIRECTION OUTPUT ;
    USE SIGNAL ;
    PORT
      LAYER M5 ;
        RECT  211.248 0 211.272 0.084 ;
    END
  END rs_o[90]
  PIN rs_o[91]
    DIRECTION OUTPUT ;
    USE SIGNAL ;
    PORT
      LAYER M5 ;
        RECT  211.44 0 211.464 0.084 ;
    END
  END rs_o[91]
  PIN rs_o[92]
    DIRECTION OUTPUT ;
    USE SIGNAL ;
    PORT
      LAYER M5 ;
        RECT  211.632 0 211.656 0.084 ;
    END
  END rs_o[92]
  PIN rs_o[93]
    DIRECTION OUTPUT ;
    USE SIGNAL ;
    PORT
      LAYER M5 ;
        RECT  224.112 0 224.136 0.084 ;
    END
  END rs_o[93]
  PIN rs_o[94]
    DIRECTION OUTPUT ;
    USE SIGNAL ;
    PORT
      LAYER M5 ;
        RECT  224.304 0 224.328 0.084 ;
    END
  END rs_o[94]
  PIN rs_o[95]
    DIRECTION OUTPUT ;
    USE SIGNAL ;
    PORT
      LAYER M5 ;
        RECT  224.496 0 224.52 0.084 ;
    END
  END rs_o[95]
  PIN rs_o[96]
    DIRECTION OUTPUT ;
    USE SIGNAL ;
    PORT
      LAYER M5 ;
        RECT  224.688 0 224.712 0.084 ;
    END
  END rs_o[96]
  PIN rs_o[97]
    DIRECTION OUTPUT ;
    USE SIGNAL ;
    PORT
      LAYER M5 ;
        RECT  224.88 0 224.904 0.084 ;
    END
  END rs_o[97]
  PIN rs_o[98]
    DIRECTION OUTPUT ;
    USE SIGNAL ;
    PORT
      LAYER M5 ;
        RECT  225.072 0 225.096 0.084 ;
    END
  END rs_o[98]
  PIN rs_o[99]
    DIRECTION OUTPUT ;
    USE SIGNAL ;
    PORT
      LAYER M5 ;
        RECT  225.264 0 225.288 0.084 ;
    END
  END rs_o[99]
  PIN rs_o[9]
    DIRECTION OUTPUT ;
    USE SIGNAL ;
    PORT
      LAYER M5 ;
        RECT  177.264 0 177.288 0.084 ;
    END
  END rs_o[9]
  PIN rst_n
    DIRECTION INPUT ;
    USE SIGNAL ;
    PORT
      LAYER M4 ;
        RECT  0 35.424 0.084 35.448 ;
    END
  END rst_n
  PIN sid_i[0]
    DIRECTION INPUT ;
    USE SIGNAL ;
    PORT
      LAYER M5 ;
        RECT  259.248 0 259.272 0.084 ;
    END
  END sid_i[0]
  PIN sid_i[1]
    DIRECTION INPUT ;
    USE SIGNAL ;
    PORT
      LAYER M5 ;
        RECT  259.44 0 259.464 0.084 ;
    END
  END sid_i[1]
  PIN sid_i[2]
    DIRECTION INPUT ;
    USE SIGNAL ;
    PORT
      LAYER M5 ;
        RECT  259.632 0 259.656 0.084 ;
    END
  END sid_i[2]
  PIN sid_i[3]
    DIRECTION INPUT ;
    USE SIGNAL ;
    PORT
      LAYER M5 ;
        RECT  259.824 0 259.848 0.084 ;
    END
  END sid_i[3]
  PIN sid_o[0]
    DIRECTION OUTPUT ;
    USE SIGNAL ;
    PORT
      LAYER M5 ;
        RECT  203.184 107.916 203.208 108 ;
    END
  END sid_o[0]
  PIN sid_o[1]
    DIRECTION OUTPUT ;
    USE SIGNAL ;
    PORT
      LAYER M5 ;
        RECT  203.376 107.916 203.4 108 ;
    END
  END sid_o[1]
  PIN sid_o[2]
    DIRECTION OUTPUT ;
    USE SIGNAL ;
    PORT
      LAYER M5 ;
        RECT  203.568 107.916 203.592 108 ;
    END
  END sid_o[2]
  PIN sid_o[3]
    DIRECTION OUTPUT ;
    USE SIGNAL ;
    PORT
      LAYER M5 ;
        RECT  203.76 107.916 203.784 108 ;
    END
  END sid_o[3]
  PIN ss[0]
    DIRECTION OUTPUT ;
    USE SIGNAL ;
    PORT
      LAYER M4 ;
        RECT  302.316 39.456 302.4 39.48 ;
    END
  END ss[0]
  PIN ss[10]
    DIRECTION OUTPUT ;
    USE SIGNAL ;
    PORT
      LAYER M4 ;
        RECT  302.316 41.376 302.4 41.4 ;
    END
  END ss[10]
  PIN ss[11]
    DIRECTION OUTPUT ;
    USE SIGNAL ;
    PORT
      LAYER M4 ;
        RECT  302.316 41.568 302.4 41.592 ;
    END
  END ss[11]
  PIN ss[12]
    DIRECTION OUTPUT ;
    USE SIGNAL ;
    PORT
      LAYER M4 ;
        RECT  302.316 41.76 302.4 41.784 ;
    END
  END ss[12]
  PIN ss[13]
    DIRECTION OUTPUT ;
    USE SIGNAL ;
    PORT
      LAYER M4 ;
        RECT  302.316 41.952 302.4 41.976 ;
    END
  END ss[13]
  PIN ss[14]
    DIRECTION OUTPUT ;
    USE SIGNAL ;
    PORT
      LAYER M4 ;
        RECT  302.316 42.144 302.4 42.168 ;
    END
  END ss[14]
  PIN ss[15]
    DIRECTION OUTPUT ;
    USE SIGNAL ;
    PORT
      LAYER M4 ;
        RECT  302.316 42.336 302.4 42.36 ;
    END
  END ss[15]
  PIN ss[16]
    DIRECTION OUTPUT ;
    USE SIGNAL ;
    PORT
      LAYER M4 ;
        RECT  302.316 42.528 302.4 42.552 ;
    END
  END ss[16]
  PIN ss[17]
    DIRECTION OUTPUT ;
    USE SIGNAL ;
    PORT
      LAYER M4 ;
        RECT  302.316 42.72 302.4 42.744 ;
    END
  END ss[17]
  PIN ss[18]
    DIRECTION OUTPUT ;
    USE SIGNAL ;
    PORT
      LAYER M4 ;
        RECT  302.316 42.912 302.4 42.936 ;
    END
  END ss[18]
  PIN ss[19]
    DIRECTION OUTPUT ;
    USE SIGNAL ;
    PORT
      LAYER M4 ;
        RECT  302.316 43.104 302.4 43.128 ;
    END
  END ss[19]
  PIN ss[1]
    DIRECTION OUTPUT ;
    USE SIGNAL ;
    PORT
      LAYER M4 ;
        RECT  302.316 39.648 302.4 39.672 ;
    END
  END ss[1]
  PIN ss[20]
    DIRECTION OUTPUT ;
    USE SIGNAL ;
    PORT
      LAYER M4 ;
        RECT  302.316 43.296 302.4 43.32 ;
    END
  END ss[20]
  PIN ss[21]
    DIRECTION OUTPUT ;
    USE SIGNAL ;
    PORT
      LAYER M4 ;
        RECT  302.316 43.488 302.4 43.512 ;
    END
  END ss[21]
  PIN ss[22]
    DIRECTION OUTPUT ;
    USE SIGNAL ;
    PORT
      LAYER M4 ;
        RECT  302.316 43.68 302.4 43.704 ;
    END
  END ss[22]
  PIN ss[23]
    DIRECTION OUTPUT ;
    USE SIGNAL ;
    PORT
      LAYER M4 ;
        RECT  302.316 43.872 302.4 43.896 ;
    END
  END ss[23]
  PIN ss[24]
    DIRECTION OUTPUT ;
    USE SIGNAL ;
    PORT
      LAYER M4 ;
        RECT  302.316 44.064 302.4 44.088 ;
    END
  END ss[24]
  PIN ss[25]
    DIRECTION OUTPUT ;
    USE SIGNAL ;
    PORT
      LAYER M4 ;
        RECT  302.316 44.256 302.4 44.28 ;
    END
  END ss[25]
  PIN ss[26]
    DIRECTION OUTPUT ;
    USE SIGNAL ;
    PORT
      LAYER M4 ;
        RECT  302.316 44.448 302.4 44.472 ;
    END
  END ss[26]
  PIN ss[27]
    DIRECTION OUTPUT ;
    USE SIGNAL ;
    PORT
      LAYER M4 ;
        RECT  302.316 44.64 302.4 44.664 ;
    END
  END ss[27]
  PIN ss[28]
    DIRECTION OUTPUT ;
    USE SIGNAL ;
    PORT
      LAYER M4 ;
        RECT  302.316 44.832 302.4 44.856 ;
    END
  END ss[28]
  PIN ss[29]
    DIRECTION OUTPUT ;
    USE SIGNAL ;
    PORT
      LAYER M4 ;
        RECT  302.316 45.024 302.4 45.048 ;
    END
  END ss[29]
  PIN ss[2]
    DIRECTION OUTPUT ;
    USE SIGNAL ;
    PORT
      LAYER M4 ;
        RECT  302.316 39.84 302.4 39.864 ;
    END
  END ss[2]
  PIN ss[30]
    DIRECTION OUTPUT ;
    USE SIGNAL ;
    PORT
      LAYER M4 ;
        RECT  302.316 45.216 302.4 45.24 ;
    END
  END ss[30]
  PIN ss[31]
    DIRECTION OUTPUT ;
    USE SIGNAL ;
    PORT
      LAYER M4 ;
        RECT  302.316 45.408 302.4 45.432 ;
    END
  END ss[31]
  PIN ss[3]
    DIRECTION OUTPUT ;
    USE SIGNAL ;
    PORT
      LAYER M4 ;
        RECT  302.316 40.032 302.4 40.056 ;
    END
  END ss[3]
  PIN ss[4]
    DIRECTION OUTPUT ;
    USE SIGNAL ;
    PORT
      LAYER M4 ;
        RECT  302.316 40.224 302.4 40.248 ;
    END
  END ss[4]
  PIN ss[5]
    DIRECTION OUTPUT ;
    USE SIGNAL ;
    PORT
      LAYER M4 ;
        RECT  302.316 40.416 302.4 40.44 ;
    END
  END ss[5]
  PIN ss[6]
    DIRECTION OUTPUT ;
    USE SIGNAL ;
    PORT
      LAYER M4 ;
        RECT  302.316 40.608 302.4 40.632 ;
    END
  END ss[6]
  PIN ss[7]
    DIRECTION OUTPUT ;
    USE SIGNAL ;
    PORT
      LAYER M4 ;
        RECT  302.316 40.8 302.4 40.824 ;
    END
  END ss[7]
  PIN ss[8]
    DIRECTION OUTPUT ;
    USE SIGNAL ;
    PORT
      LAYER M4 ;
        RECT  302.316 40.992 302.4 41.016 ;
    END
  END ss[8]
  PIN ss[9]
    DIRECTION OUTPUT ;
    USE SIGNAL ;
    PORT
      LAYER M4 ;
        RECT  302.316 41.184 302.4 41.208 ;
    END
  END ss[9]
  PIN ss_v
    DIRECTION OUTPUT ;
    USE SIGNAL ;
    PORT
      LAYER M4 ;
        RECT  302.316 45.6 302.4 45.624 ;
    END
  END ss_v
  PIN t_lm[0]
    DIRECTION OUTPUT ;
    USE SIGNAL ;
    PORT
      LAYER M5 ;
        RECT  203.952 107.916 203.976 108 ;
    END
  END t_lm[0]
  PIN t_lm[1]
    DIRECTION OUTPUT ;
    USE SIGNAL ;
    PORT
      LAYER M5 ;
        RECT  204.144 107.916 204.168 108 ;
    END
  END t_lm[1]
  PIN t_lm[2]
    DIRECTION OUTPUT ;
    USE SIGNAL ;
    PORT
      LAYER M5 ;
        RECT  204.336 107.916 204.36 108 ;
    END
  END t_lm[2]
  PIN t_lm[3]
    DIRECTION OUTPUT ;
    USE SIGNAL ;
    PORT
      LAYER M5 ;
        RECT  204.528 107.916 204.552 108 ;
    END
  END t_lm[3]
  PIN t_lm[4]
    DIRECTION OUTPUT ;
    USE SIGNAL ;
    PORT
      LAYER M5 ;
        RECT  204.72 107.916 204.744 108 ;
    END
  END t_lm[4]
  PIN t_row[0]
    DIRECTION OUTPUT ;
    USE SIGNAL ;
    PORT
      LAYER M5 ;
        RECT  204.912 107.916 204.936 108 ;
    END
  END t_row[0]
  PIN t_row[1]
    DIRECTION OUTPUT ;
    USE SIGNAL ;
    PORT
      LAYER M5 ;
        RECT  205.104 107.916 205.128 108 ;
    END
  END t_row[1]
  PIN t_row[2]
    DIRECTION OUTPUT ;
    USE SIGNAL ;
    PORT
      LAYER M5 ;
        RECT  205.296 107.916 205.32 108 ;
    END
  END t_row[2]
  PIN t_row[3]
    DIRECTION OUTPUT ;
    USE SIGNAL ;
    PORT
      LAYER M5 ;
        RECT  205.488 107.916 205.512 108 ;
    END
  END t_row[3]
  PIN t_row[4]
    DIRECTION OUTPUT ;
    USE SIGNAL ;
    PORT
      LAYER M5 ;
        RECT  205.68 107.916 205.704 108 ;
    END
  END t_row[4]
  PIN t_row[5]
    DIRECTION OUTPUT ;
    USE SIGNAL ;
    PORT
      LAYER M5 ;
        RECT  205.872 107.916 205.896 108 ;
    END
  END t_row[5]
  PIN t_row[6]
    DIRECTION OUTPUT ;
    USE SIGNAL ;
    PORT
      LAYER M5 ;
        RECT  206.064 107.916 206.088 108 ;
    END
  END t_row[6]
  PIN t_row[7]
    DIRECTION OUTPUT ;
    USE SIGNAL ;
    PORT
      LAYER M5 ;
        RECT  287.568 107.916 287.592 108 ;
    END
  END t_row[7]
  PIN t_row[8]
    DIRECTION OUTPUT ;
    USE SIGNAL ;
    PORT
      LAYER M5 ;
        RECT  287.76 107.916 287.784 108 ;
    END
  END t_row[8]
  PIN t_row[9]
    DIRECTION OUTPUT ;
    USE SIGNAL ;
    PORT
      LAYER M5 ;
        RECT  287.952 107.916 287.976 108 ;
    END
  END t_row[9]
  PIN t_set
    DIRECTION OUTPUT ;
    USE SIGNAL ;
    PORT
      LAYER M5 ;
        RECT  288.144 107.916 288.168 108 ;
    END
  END t_set
  PIN t_sm[0]
    DIRECTION OUTPUT ;
    USE SIGNAL ;
    PORT
      LAYER M5 ;
        RECT  288.336 107.916 288.36 108 ;
    END
  END t_sm[0]
  PIN t_sm[10]
    DIRECTION OUTPUT ;
    USE SIGNAL ;
    PORT
      LAYER M5 ;
        RECT  290.256 107.916 290.28 108 ;
    END
  END t_sm[10]
  PIN t_sm[11]
    DIRECTION OUTPUT ;
    USE SIGNAL ;
    PORT
      LAYER M5 ;
        RECT  290.448 107.916 290.472 108 ;
    END
  END t_sm[11]
  PIN t_sm[12]
    DIRECTION OUTPUT ;
    USE SIGNAL ;
    PORT
      LAYER M5 ;
        RECT  290.64 107.916 290.664 108 ;
    END
  END t_sm[12]
  PIN t_sm[13]
    DIRECTION OUTPUT ;
    USE SIGNAL ;
    PORT
      LAYER M5 ;
        RECT  290.832 107.916 290.856 108 ;
    END
  END t_sm[13]
  PIN t_sm[14]
    DIRECTION OUTPUT ;
    USE SIGNAL ;
    PORT
      LAYER M5 ;
        RECT  291.024 107.916 291.048 108 ;
    END
  END t_sm[14]
  PIN t_sm[15]
    DIRECTION OUTPUT ;
    USE SIGNAL ;
    PORT
      LAYER M5 ;
        RECT  291.216 107.916 291.24 108 ;
    END
  END t_sm[15]
  PIN t_sm[1]
    DIRECTION OUTPUT ;
    USE SIGNAL ;
    PORT
      LAYER M5 ;
        RECT  288.528 107.916 288.552 108 ;
    END
  END t_sm[1]
  PIN t_sm[2]
    DIRECTION OUTPUT ;
    USE SIGNAL ;
    PORT
      LAYER M5 ;
        RECT  288.72 107.916 288.744 108 ;
    END
  END t_sm[2]
  PIN t_sm[3]
    DIRECTION OUTPUT ;
    USE SIGNAL ;
    PORT
      LAYER M5 ;
        RECT  288.912 107.916 288.936 108 ;
    END
  END t_sm[3]
  PIN t_sm[4]
    DIRECTION OUTPUT ;
    USE SIGNAL ;
    PORT
      LAYER M5 ;
        RECT  289.104 107.916 289.128 108 ;
    END
  END t_sm[4]
  PIN t_sm[5]
    DIRECTION OUTPUT ;
    USE SIGNAL ;
    PORT
      LAYER M5 ;
        RECT  289.296 107.916 289.32 108 ;
    END
  END t_sm[5]
  PIN t_sm[6]
    DIRECTION OUTPUT ;
    USE SIGNAL ;
    PORT
      LAYER M5 ;
        RECT  289.488 107.916 289.512 108 ;
    END
  END t_sm[6]
  PIN t_sm[7]
    DIRECTION OUTPUT ;
    USE SIGNAL ;
    PORT
      LAYER M5 ;
        RECT  289.68 107.916 289.704 108 ;
    END
  END t_sm[7]
  PIN t_sm[8]
    DIRECTION OUTPUT ;
    USE SIGNAL ;
    PORT
      LAYER M5 ;
        RECT  289.872 107.916 289.896 108 ;
    END
  END t_sm[8]
  PIN t_sm[9]
    DIRECTION OUTPUT ;
    USE SIGNAL ;
    PORT
      LAYER M5 ;
        RECT  290.064 107.916 290.088 108 ;
    END
  END t_sm[9]
  PIN t_w
    DIRECTION OUTPUT ;
    USE SIGNAL ;
    PORT
      LAYER M5 ;
        RECT  291.408 107.916 291.432 108 ;
    END
  END t_w
  PIN VDD
    DIRECTION INOUT ;
    USE POWER ;
    PORT
      LAYER M5 ;
        RECT  295.956 4.311 296.076 103.689 ;
        RECT  291.636 4.311 291.756 103.689 ;
        RECT  287.316 4.311 287.436 103.689 ;
        RECT  282.996 4.311 283.116 103.689 ;
        RECT  278.676 4.311 278.796 103.689 ;
        RECT  274.356 4.311 274.476 103.689 ;
        RECT  270.036 4.311 270.156 103.689 ;
        RECT  265.716 4.311 265.836 103.689 ;
        RECT  261.396 4.311 261.516 103.689 ;
        RECT  257.076 4.311 257.196 103.689 ;
        RECT  252.756 4.311 252.876 103.689 ;
        RECT  248.436 4.311 248.556 103.689 ;
        RECT  244.116 4.311 244.236 103.689 ;
        RECT  239.796 4.311 239.916 103.689 ;
        RECT  235.476 4.311 235.596 103.689 ;
        RECT  231.156 4.311 231.276 103.689 ;
        RECT  226.836 4.311 226.956 103.689 ;
        RECT  222.516 4.311 222.636 103.689 ;
        RECT  218.196 4.311 218.316 103.689 ;
        RECT  213.876 4.311 213.996 103.689 ;
        RECT  209.556 4.311 209.676 103.689 ;
        RECT  205.236 4.311 205.356 103.689 ;
        RECT  200.916 4.311 201.036 103.689 ;
        RECT  196.596 4.311 196.716 103.689 ;
        RECT  192.276 4.311 192.396 103.689 ;
        RECT  187.956 4.311 188.076 103.689 ;
        RECT  183.636 4.311 183.756 103.689 ;
        RECT  179.316 4.311 179.436 103.689 ;
        RECT  174.996 4.311 175.116 103.689 ;
        RECT  170.676 4.311 170.796 103.689 ;
        RECT  166.356 4.311 166.476 103.689 ;
        RECT  162.036 4.311 162.156 103.689 ;
        RECT  157.716 4.311 157.836 103.689 ;
        RECT  153.396 4.311 153.516 103.689 ;
        RECT  149.076 4.311 149.196 103.689 ;
        RECT  144.756 4.311 144.876 103.689 ;
        RECT  140.436 4.311 140.556 103.689 ;
        RECT  136.116 4.311 136.236 103.689 ;
        RECT  131.796 4.311 131.916 103.689 ;
        RECT  127.476 4.311 127.596 103.689 ;
        RECT  123.156 4.311 123.276 103.689 ;
        RECT  118.836 4.311 118.956 103.689 ;
        RECT  114.516 4.311 114.636 103.689 ;
        RECT  110.196 4.311 110.316 103.689 ;
        RECT  105.876 4.311 105.996 103.689 ;
        RECT  101.556 4.311 101.676 103.689 ;
        RECT  97.236 4.311 97.356 103.689 ;
        RECT  92.916 4.311 93.036 103.689 ;
        RECT  88.596 4.311 88.716 103.689 ;
        RECT  84.276 4.311 84.396 103.689 ;
        RECT  79.956 4.311 80.076 103.689 ;
        RECT  75.636 4.311 75.756 103.689 ;
        RECT  71.316 4.311 71.436 103.689 ;
        RECT  66.996 4.311 67.116 103.689 ;
        RECT  62.676 4.311 62.796 103.689 ;
        RECT  58.356 4.311 58.476 103.689 ;
        RECT  54.036 4.311 54.156 103.689 ;
        RECT  49.716 4.311 49.836 103.689 ;
        RECT  45.396 4.311 45.516 103.689 ;
        RECT  41.076 4.311 41.196 103.689 ;
        RECT  36.756 4.311 36.876 103.689 ;
        RECT  32.436 4.311 32.556 103.689 ;
        RECT  28.116 4.311 28.236 103.689 ;
        RECT  23.796 4.311 23.916 103.689 ;
        RECT  19.476 4.311 19.596 103.689 ;
        RECT  15.156 4.311 15.276 103.689 ;
        RECT  10.836 4.311 10.956 103.689 ;
        RECT  6.516 4.311 6.636 103.689 ;
    END
  END VDD
  PIN VSS
    DIRECTION INOUT ;
    USE GROUND ;
    PORT
      LAYER M5 ;
        RECT  295.764 4.297 295.884 103.703 ;
        RECT  291.444 4.297 291.564 103.703 ;
        RECT  287.124 4.297 287.244 103.703 ;
        RECT  282.804 4.297 282.924 103.703 ;
        RECT  278.484 4.297 278.604 103.703 ;
        RECT  274.164 4.297 274.284 103.703 ;
        RECT  269.844 4.297 269.964 103.703 ;
        RECT  265.524 4.297 265.644 103.703 ;
        RECT  261.204 4.297 261.324 103.703 ;
        RECT  256.884 4.297 257.004 103.703 ;
        RECT  252.564 4.297 252.684 103.703 ;
        RECT  248.244 4.297 248.364 103.703 ;
        RECT  243.924 4.297 244.044 103.703 ;
        RECT  239.604 4.297 239.724 103.703 ;
        RECT  235.284 4.297 235.404 103.703 ;
        RECT  230.964 4.297 231.084 103.703 ;
        RECT  226.644 4.297 226.764 103.703 ;
        RECT  222.324 4.297 222.444 103.703 ;
        RECT  218.004 4.297 218.124 103.703 ;
        RECT  213.684 4.297 213.804 103.703 ;
        RECT  209.364 4.297 209.484 103.703 ;
        RECT  205.044 4.297 205.164 103.703 ;
        RECT  200.724 4.297 200.844 103.703 ;
        RECT  196.404 4.297 196.524 103.703 ;
        RECT  192.084 4.297 192.204 103.703 ;
        RECT  187.764 4.297 187.884 103.703 ;
        RECT  183.444 4.297 183.564 103.703 ;
        RECT  179.124 4.297 179.244 103.703 ;
        RECT  174.804 4.297 174.924 103.703 ;
        RECT  170.484 4.297 170.604 103.703 ;
        RECT  166.164 4.297 166.284 103.703 ;
        RECT  161.844 4.297 161.964 103.703 ;
        RECT  157.524 4.297 157.644 103.703 ;
        RECT  153.204 4.297 153.324 103.703 ;
        RECT  148.884 4.297 149.004 103.703 ;
        RECT  144.564 4.297 144.684 103.703 ;
        RECT  140.244 4.297 140.364 103.703 ;
        RECT  135.924 4.297 136.044 103.703 ;
        RECT  131.604 4.297 131.724 103.703 ;
        RECT  127.284 4.297 127.404 103.703 ;
        RECT  122.964 4.297 123.084 103.703 ;
        RECT  118.644 4.297 118.764 103.703 ;
        RECT  114.324 4.297 114.444 103.703 ;
        RECT  110.004 4.297 110.124 103.703 ;
        RECT  105.684 4.297 105.804 103.703 ;
        RECT  101.364 4.297 101.484 103.703 ;
        RECT  97.044 4.297 97.164 103.703 ;
        RECT  92.724 4.297 92.844 103.703 ;
        RECT  88.404 4.297 88.524 103.703 ;
        RECT  84.084 4.297 84.204 103.703 ;
        RECT  79.764 4.297 79.884 103.703 ;
        RECT  75.444 4.297 75.564 103.703 ;
        RECT  71.124 4.297 71.244 103.703 ;
        RECT  66.804 4.297 66.924 103.703 ;
        RECT  62.484 4.297 62.604 103.703 ;
        RECT  58.164 4.297 58.284 103.703 ;
        RECT  53.844 4.297 53.964 103.703 ;
        RECT  49.524 4.297 49.644 103.703 ;
        RECT  45.204 4.297 45.324 103.703 ;
        RECT  40.884 4.297 41.004 103.703 ;
        RECT  36.564 4.297 36.684 103.703 ;
        RECT  32.244 4.297 32.364 103.703 ;
        RECT  27.924 4.297 28.044 103.703 ;
        RECT  23.604 4.297 23.724 103.703 ;
        RECT  19.284 4.297 19.404 103.703 ;
        RECT  14.964 4.297 15.084 103.703 ;
        RECT  10.644 4.297 10.764 103.703 ;
        RECT  6.324 4.297 6.444 103.703 ;
    END
  END VSS
  OBS
    LAYER RVTN ;
     RECT  0 0 302.4 108 ;
    LAYER RVTP ;
     RECT  0 0 302.4 108 ;
    LAYER M1 ;
     RECT  0 0 302.4 108 ;
    LAYER M2 ;
     RECT  0 0 302.4 108 ;
    LAYER M3 ;
     RECT  0 0 302.4 108 ;
    LAYER M4 ;
     RECT  0 0 302.4 108 ;
    LAYER M5 ;
     RECT  0 0 302.4 108 ;
  END
END dsdv_gunit_l4
END LIBRARY
